VERSION 5.7 ;
  NOWIREEXTENSIONATPIN ON ;
  DIVIDERCHAR "/" ;
  BUSBITCHARS "[]" ;
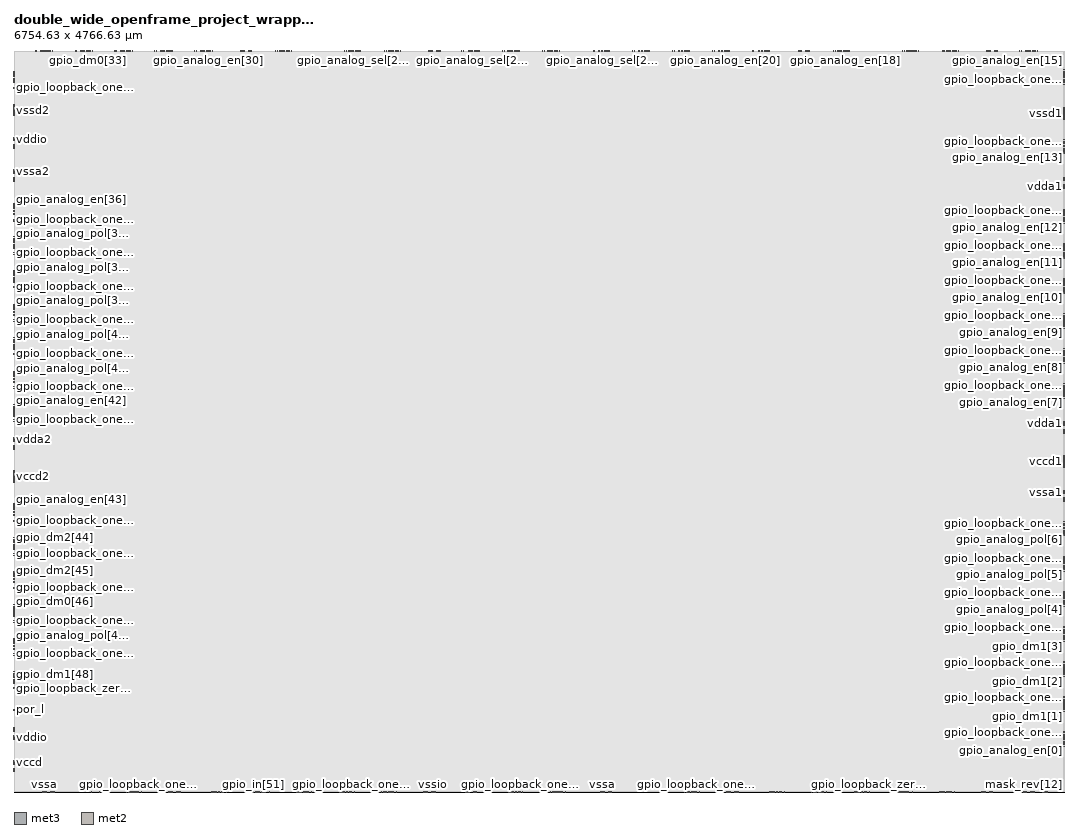
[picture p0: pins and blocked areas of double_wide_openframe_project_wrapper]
MACRO double_wide_openframe_project_wrapper
  CLASS BLOCK ;
  FOREIGN double_wide_openframe_project_wrapper ;
  ORIGIN 0.000 0.000 ;
  SIZE 6754.630 BY 4766.630 ;
  PIN analog_io[0]
    DIRECTION INOUT ;
    USE SIGNAL ;
    PORT
      LAYER met3 ;
        RECT 6754.330 306.190 6756.630 306.830 ;
    END
  END analog_io[0]
  PIN analog_io[10]
    DIRECTION INOUT ;
    USE SIGNAL ;
    PORT
      LAYER met3 ;
        RECT 6754.330 3222.190 6756.630 3222.830 ;
    END
  END analog_io[10]
  PIN analog_io[11]
    DIRECTION INOUT ;
    USE SIGNAL ;
    PORT
      LAYER met3 ;
        RECT 6754.330 3447.190 6756.630 3447.830 ;
    END
  END analog_io[11]
  PIN analog_io[12]
    DIRECTION INOUT ;
    USE SIGNAL ;
    PORT
      LAYER met3 ;
        RECT 6754.330 3672.190 6756.630 3672.830 ;
    END
  END analog_io[12]
  PIN analog_io[13]
    DIRECTION INOUT ;
    USE SIGNAL ;
    PORT
      LAYER met3 ;
        RECT 6754.330 4118.190 6756.630 4118.830 ;
    END
  END analog_io[13]
  PIN analog_io[14]
    DIRECTION INOUT ;
    USE SIGNAL ;
    PORT
      LAYER met3 ;
        RECT 6754.330 4564.190 6756.630 4564.830 ;
    END
  END analog_io[14]
  PIN analog_io[15]
    DIRECTION INOUT ;
    USE SIGNAL ;
    PORT
      LAYER met2 ;
        RECT 6569.800 4766.350 6570.440 4768.630 ;
    END
  END analog_io[15]
  PIN analog_io[16]
    DIRECTION INOUT ;
    USE SIGNAL ;
    PORT
      LAYER met2 ;
        RECT 6060.800 4766.350 6061.440 4768.630 ;
    END
  END analog_io[16]
  PIN analog_io[17]
    DIRECTION INOUT ;
    USE SIGNAL ;
    PORT
      LAYER met2 ;
        RECT 5803.800 4766.350 5804.440 4768.630 ;
    END
  END analog_io[17]
  PIN analog_io[18]
    DIRECTION INOUT ;
    USE SIGNAL ;
    PORT
      LAYER met2 ;
        RECT 5358.800 4766.350 5359.440 4768.630 ;
    END
  END analog_io[18]
  PIN analog_io[19]
    DIRECTION INOUT ;
    USE SIGNAL ;
    PORT
      LAYER met2 ;
        RECT 4849.800 4766.350 4850.440 4768.630 ;
    END
  END analog_io[19]
  PIN analog_io[1]
    DIRECTION INOUT ;
    USE SIGNAL ;
    PORT
      LAYER met3 ;
        RECT 6754.330 532.190 6756.630 532.830 ;
    END
  END analog_io[1]
  PIN analog_io[20]
    DIRECTION INOUT ;
    USE SIGNAL ;
    PORT
      LAYER met2 ;
        RECT 4591.800 4766.350 4592.440 4768.630 ;
    END
  END analog_io[20]
  PIN analog_io[21]
    DIRECTION INOUT ;
    USE SIGNAL ;
    PORT
      LAYER met2 ;
        RECT 4334.800 4766.350 4335.440 4768.630 ;
    END
  END analog_io[21]
  PIN analog_io[22]
    DIRECTION INOUT ;
    USE SIGNAL ;
    PORT
      LAYER met2 ;
        RECT 4077.800 4766.350 4078.440 4768.630 ;
    END
  END analog_io[22]
  PIN analog_io[23]
    DIRECTION INOUT ;
    USE SIGNAL ;
    PORT
      LAYER met2 ;
        RECT 3820.800 4766.350 3821.440 4768.630 ;
    END
  END analog_io[23]
  PIN analog_io[24]
    DIRECTION INOUT ;
    USE SIGNAL ;
    PORT
      LAYER met2 ;
        RECT 3495.800 4766.350 3496.440 4768.630 ;
    END
  END analog_io[24]
  PIN analog_io[25]
    DIRECTION INOUT ;
    USE SIGNAL ;
    PORT
      LAYER met2 ;
        RECT 3238.800 4766.350 3239.440 4768.630 ;
    END
  END analog_io[25]
  PIN analog_io[26]
    DIRECTION INOUT ;
    USE SIGNAL ;
    PORT
      LAYER met2 ;
        RECT 2981.800 4766.350 2982.440 4768.630 ;
    END
  END analog_io[26]
  PIN analog_io[27]
    DIRECTION INOUT ;
    USE SIGNAL ;
    PORT
      LAYER met2 ;
        RECT 2472.800 4766.350 2473.440 4768.630 ;
    END
  END analog_io[27]
  PIN analog_io[28]
    DIRECTION INOUT ;
    USE SIGNAL ;
    PORT
      LAYER met2 ;
        RECT 2215.800 4766.350 2216.440 4768.630 ;
    END
  END analog_io[28]
  PIN analog_io[29]
    DIRECTION INOUT ;
    USE SIGNAL ;
    PORT
      LAYER met2 ;
        RECT 1770.800 4766.350 1771.440 4768.630 ;
    END
  END analog_io[29]
  PIN analog_io[2]
    DIRECTION INOUT ;
    USE SIGNAL ;
    PORT
      LAYER met3 ;
        RECT 6754.330 757.190 6756.630 757.830 ;
    END
  END analog_io[2]
  PIN analog_io[30]
    DIRECTION INOUT ;
    USE SIGNAL ;
    PORT
      LAYER met2 ;
        RECT 1261.800 4766.350 1262.440 4768.630 ;
    END
  END analog_io[30]
  PIN analog_io[31]
    DIRECTION INOUT ;
    USE SIGNAL ;
    PORT
      LAYER met2 ;
        RECT 1003.800 4766.350 1004.440 4768.630 ;
    END
  END analog_io[31]
  PIN analog_io[32]
    DIRECTION INOUT ;
    USE SIGNAL ;
    PORT
      LAYER met2 ;
        RECT 746.800 4766.350 747.440 4768.630 ;
    END
  END analog_io[32]
  PIN analog_io[33]
    DIRECTION INOUT ;
    USE SIGNAL ;
    PORT
      LAYER met2 ;
        RECT 489.800 4766.350 490.440 4768.630 ;
    END
  END analog_io[33]
  PIN analog_io[34]
    DIRECTION INOUT ;
    USE SIGNAL ;
    PORT
      LAYER met2 ;
        RECT 232.800 4766.350 233.440 4768.630 ;
    END
  END analog_io[34]
  PIN analog_io[35]
    DIRECTION INOUT ;
    USE SIGNAL ;
    PORT
      LAYER met3 ;
        RECT -2.000 4622.800 0.300 4623.440 ;
    END
  END analog_io[35]
  PIN analog_io[36]
    DIRECTION INOUT ;
    USE SIGNAL ;
    PORT
      LAYER met3 ;
        RECT -2.000 3773.800 0.300 3774.440 ;
    END
  END analog_io[36]
  PIN analog_io[37]
    DIRECTION INOUT ;
    USE SIGNAL ;
    PORT
      LAYER met3 ;
        RECT -2.000 3557.800 0.300 3558.440 ;
    END
  END analog_io[37]
  PIN analog_io[38]
    DIRECTION INOUT ;
    USE SIGNAL ;
    PORT
      LAYER met3 ;
        RECT -2.000 3341.800 0.300 3342.440 ;
    END
  END analog_io[38]
  PIN analog_io[39]
    DIRECTION INOUT ;
    USE SIGNAL ;
    PORT
      LAYER met3 ;
        RECT -2.000 3125.800 0.300 3126.440 ;
    END
  END analog_io[39]
  PIN analog_io[3]
    DIRECTION INOUT ;
    USE SIGNAL ;
    PORT
      LAYER met3 ;
        RECT 6754.330 983.190 6756.630 983.830 ;
    END
  END analog_io[3]
  PIN analog_io[40]
    DIRECTION INOUT ;
    USE SIGNAL ;
    PORT
      LAYER met3 ;
        RECT -2.000 2909.800 0.300 2910.440 ;
    END
  END analog_io[40]
  PIN analog_io[41]
    DIRECTION INOUT ;
    USE SIGNAL ;
    PORT
      LAYER met3 ;
        RECT -2.000 2693.800 0.300 2694.440 ;
    END
  END analog_io[41]
  PIN analog_io[42]
    DIRECTION INOUT ;
    USE SIGNAL ;
    PORT
      LAYER met3 ;
        RECT -2.000 2477.800 0.300 2478.440 ;
    END
  END analog_io[42]
  PIN analog_io[43]
    DIRECTION INOUT ;
    USE SIGNAL ;
    PORT
      LAYER met3 ;
        RECT -2.000 1839.800 0.300 1840.440 ;
    END
  END analog_io[43]
  PIN analog_io[44]
    DIRECTION INOUT ;
    USE SIGNAL ;
    PORT
      LAYER met3 ;
        RECT -2.000 1623.800 0.300 1624.440 ;
    END
  END analog_io[44]
  PIN analog_io[45]
    DIRECTION INOUT ;
    USE SIGNAL ;
    PORT
      LAYER met3 ;
        RECT -2.000 1407.800 0.300 1408.440 ;
    END
  END analog_io[45]
  PIN analog_io[46]
    DIRECTION INOUT ;
    USE SIGNAL ;
    PORT
      LAYER met3 ;
        RECT -2.000 1191.800 0.300 1192.440 ;
    END
  END analog_io[46]
  PIN analog_io[47]
    DIRECTION INOUT ;
    USE SIGNAL ;
    PORT
      LAYER met3 ;
        RECT -2.000 975.800 0.300 976.440 ;
    END
  END analog_io[47]
  PIN analog_io[48]
    DIRECTION INOUT ;
    USE SIGNAL ;
    PORT
      LAYER met3 ;
        RECT -2.000 759.800 0.300 760.440 ;
    END
  END analog_io[48]
  PIN analog_io[49]
    DIRECTION INOUT ;
    USE SIGNAL ;
    PORT
      LAYER met2 ;
        RECT 738.190 -2.000 738.830 0.280 ;
    END
  END analog_io[49]
  PIN analog_io[4]
    DIRECTION INOUT ;
    USE SIGNAL ;
    PORT
      LAYER met3 ;
        RECT 6754.330 1208.190 6756.630 1208.830 ;
    END
  END analog_io[4]
  PIN analog_io[50]
    DIRECTION INOUT ;
    USE SIGNAL ;
    PORT
      LAYER met2 ;
        RECT 1281.190 -2.000 1281.830 0.280 ;
    END
  END analog_io[50]
  PIN analog_io[51]
    DIRECTION INOUT ;
    USE SIGNAL ;
    PORT
      LAYER met2 ;
        RECT 1555.190 -2.000 1555.830 0.280 ;
    END
  END analog_io[51]
  PIN analog_io[52]
    DIRECTION INOUT ;
    USE SIGNAL ;
    PORT
      LAYER met2 ;
        RECT 1829.190 -2.000 1829.830 0.280 ;
    END
  END analog_io[52]
  PIN analog_io[53]
    DIRECTION INOUT ;
    USE SIGNAL ;
    PORT
      LAYER met2 ;
        RECT 2103.190 -2.000 2103.830 0.280 ;
    END
  END analog_io[53]
  PIN analog_io[54]
    DIRECTION INOUT ;
    USE SIGNAL ;
    PORT
      LAYER met2 ;
        RECT 2377.190 -2.000 2377.830 0.280 ;
    END
  END analog_io[54]
  PIN analog_io[55]
    DIRECTION INOUT ;
    USE SIGNAL ;
    PORT
      LAYER met2 ;
        RECT 3191.670 -2.000 3192.310 0.280 ;
    END
  END analog_io[55]
  PIN analog_io[56]
    DIRECTION INOUT ;
    USE SIGNAL ;
    PORT
      LAYER met2 ;
        RECT 3465.670 -2.000 3466.310 0.280 ;
    END
  END analog_io[56]
  PIN analog_io[57]
    DIRECTION INOUT ;
    USE SIGNAL ;
    PORT
      LAYER met2 ;
        RECT 4326.190 -2.000 4326.830 0.280 ;
    END
  END analog_io[57]
  PIN analog_io[58]
    DIRECTION INOUT ;
    USE SIGNAL ;
    PORT
      LAYER met2 ;
        RECT 4869.190 -2.000 4869.830 0.280 ;
    END
  END analog_io[58]
  PIN analog_io[59]
    DIRECTION INOUT ;
    USE SIGNAL ;
    PORT
      LAYER met2 ;
        RECT 5143.190 -2.000 5143.830 0.280 ;
    END
  END analog_io[59]
  PIN analog_io[5]
    DIRECTION INOUT ;
    USE SIGNAL ;
    PORT
      LAYER met3 ;
        RECT 6754.330 1433.190 6756.630 1433.830 ;
    END
  END analog_io[5]
  PIN analog_io[60]
    DIRECTION INOUT ;
    USE SIGNAL ;
    PORT
      LAYER met2 ;
        RECT 5417.190 -2.000 5417.830 0.280 ;
    END
  END analog_io[60]
  PIN analog_io[61]
    DIRECTION INOUT ;
    USE SIGNAL ;
    PORT
      LAYER met2 ;
        RECT 5691.190 -2.000 5691.830 0.280 ;
    END
  END analog_io[61]
  PIN analog_io[62]
    DIRECTION INOUT ;
    USE SIGNAL ;
    PORT
      LAYER met2 ;
        RECT 5965.190 -2.000 5965.830 0.280 ;
    END
  END analog_io[62]
  PIN analog_io[6]
    DIRECTION INOUT ;
    USE SIGNAL ;
    PORT
      LAYER met3 ;
        RECT 6754.330 1659.190 6756.630 1659.830 ;
    END
  END analog_io[6]
  PIN analog_io[7]
    DIRECTION INOUT ;
    USE SIGNAL ;
    PORT
      LAYER met3 ;
        RECT 6754.330 2545.190 6756.630 2545.830 ;
    END
  END analog_io[7]
  PIN analog_io[8]
    DIRECTION INOUT ;
    USE SIGNAL ;
    PORT
      LAYER met3 ;
        RECT 6754.330 2771.190 6756.630 2771.830 ;
    END
  END analog_io[8]
  PIN analog_io[9]
    DIRECTION INOUT ;
    USE SIGNAL ;
    PORT
      LAYER met3 ;
        RECT 6754.330 2996.190 6756.630 2996.830 ;
    END
  END analog_io[9]
  PIN analog_noesd_io[0]
    DIRECTION INOUT ;
    USE SIGNAL ;
    PORT
      LAYER met3 ;
        RECT 6754.330 315.175 6756.630 316.245 ;
    END
  END analog_noesd_io[0]
  PIN analog_noesd_io[10]
    DIRECTION INOUT ;
    USE SIGNAL ;
    PORT
      LAYER met3 ;
        RECT 6754.330 3231.175 6756.630 3232.245 ;
    END
  END analog_noesd_io[10]
  PIN analog_noesd_io[11]
    DIRECTION INOUT ;
    USE SIGNAL ;
    PORT
      LAYER met3 ;
        RECT 6754.330 3456.175 6756.630 3457.245 ;
    END
  END analog_noesd_io[11]
  PIN analog_noesd_io[12]
    DIRECTION INOUT ;
    USE SIGNAL ;
    PORT
      LAYER met3 ;
        RECT 6754.330 3681.175 6756.630 3682.245 ;
    END
  END analog_noesd_io[12]
  PIN analog_noesd_io[13]
    DIRECTION INOUT ;
    USE SIGNAL ;
    PORT
      LAYER met3 ;
        RECT 6754.330 4127.175 6756.630 4128.245 ;
    END
  END analog_noesd_io[13]
  PIN analog_noesd_io[14]
    DIRECTION INOUT ;
    USE SIGNAL ;
    PORT
      LAYER met3 ;
        RECT 6754.330 4573.175 6756.630 4574.245 ;
    END
  END analog_noesd_io[14]
  PIN analog_noesd_io[15]
    DIRECTION INOUT ;
    USE SIGNAL ;
    PORT
      LAYER met2 ;
        RECT 6560.385 4766.350 6561.455 4768.630 ;
    END
  END analog_noesd_io[15]
  PIN analog_noesd_io[16]
    DIRECTION INOUT ;
    USE SIGNAL ;
    PORT
      LAYER met2 ;
        RECT 6051.385 4766.350 6052.455 4768.630 ;
    END
  END analog_noesd_io[16]
  PIN analog_noesd_io[17]
    DIRECTION INOUT ;
    USE SIGNAL ;
    PORT
      LAYER met2 ;
        RECT 5794.385 4766.350 5795.455 4768.630 ;
    END
  END analog_noesd_io[17]
  PIN analog_noesd_io[18]
    DIRECTION INOUT ;
    USE SIGNAL ;
    PORT
      LAYER met2 ;
        RECT 5349.385 4766.350 5350.455 4768.630 ;
    END
  END analog_noesd_io[18]
  PIN analog_noesd_io[19]
    DIRECTION INOUT ;
    USE SIGNAL ;
    PORT
      LAYER met2 ;
        RECT 4840.385 4766.350 4841.455 4768.630 ;
    END
  END analog_noesd_io[19]
  PIN analog_noesd_io[1]
    DIRECTION INOUT ;
    USE SIGNAL ;
    PORT
      LAYER met3 ;
        RECT 6754.330 541.175 6756.630 542.245 ;
    END
  END analog_noesd_io[1]
  PIN analog_noesd_io[20]
    DIRECTION INOUT ;
    USE SIGNAL ;
    PORT
      LAYER met2 ;
        RECT 4582.385 4766.350 4583.455 4768.630 ;
    END
  END analog_noesd_io[20]
  PIN analog_noesd_io[21]
    DIRECTION INOUT ;
    USE SIGNAL ;
    PORT
      LAYER met2 ;
        RECT 4325.385 4766.350 4326.455 4768.630 ;
    END
  END analog_noesd_io[21]
  PIN analog_noesd_io[22]
    DIRECTION INOUT ;
    USE SIGNAL ;
    PORT
      LAYER met2 ;
        RECT 4068.385 4766.350 4069.455 4768.630 ;
    END
  END analog_noesd_io[22]
  PIN analog_noesd_io[23]
    DIRECTION INOUT ;
    USE SIGNAL ;
    PORT
      LAYER met2 ;
        RECT 3811.385 4766.350 3812.455 4768.630 ;
    END
  END analog_noesd_io[23]
  PIN analog_noesd_io[24]
    DIRECTION INOUT ;
    USE SIGNAL ;
    PORT
      LAYER met2 ;
        RECT 3486.385 4766.350 3487.455 4768.630 ;
    END
  END analog_noesd_io[24]
  PIN analog_noesd_io[25]
    DIRECTION INOUT ;
    USE SIGNAL ;
    PORT
      LAYER met2 ;
        RECT 3229.385 4766.350 3230.455 4768.630 ;
    END
  END analog_noesd_io[25]
  PIN analog_noesd_io[26]
    DIRECTION INOUT ;
    USE SIGNAL ;
    PORT
      LAYER met2 ;
        RECT 2972.385 4766.350 2973.455 4768.630 ;
    END
  END analog_noesd_io[26]
  PIN analog_noesd_io[27]
    DIRECTION INOUT ;
    USE SIGNAL ;
    PORT
      LAYER met2 ;
        RECT 2463.385 4766.350 2464.455 4768.630 ;
    END
  END analog_noesd_io[27]
  PIN analog_noesd_io[28]
    DIRECTION INOUT ;
    USE SIGNAL ;
    PORT
      LAYER met2 ;
        RECT 2206.385 4766.350 2207.455 4768.630 ;
    END
  END analog_noesd_io[28]
  PIN analog_noesd_io[29]
    DIRECTION INOUT ;
    USE SIGNAL ;
    PORT
      LAYER met2 ;
        RECT 1761.385 4766.350 1762.455 4768.630 ;
    END
  END analog_noesd_io[29]
  PIN analog_noesd_io[2]
    DIRECTION INOUT ;
    USE SIGNAL ;
    PORT
      LAYER met3 ;
        RECT 6754.330 766.175 6756.630 767.245 ;
    END
  END analog_noesd_io[2]
  PIN analog_noesd_io[30]
    DIRECTION INOUT ;
    USE SIGNAL ;
    PORT
      LAYER met2 ;
        RECT 1252.385 4766.350 1253.455 4768.630 ;
    END
  END analog_noesd_io[30]
  PIN analog_noesd_io[31]
    DIRECTION INOUT ;
    USE SIGNAL ;
    PORT
      LAYER met2 ;
        RECT 994.385 4766.350 995.455 4768.630 ;
    END
  END analog_noesd_io[31]
  PIN analog_noesd_io[32]
    DIRECTION INOUT ;
    USE SIGNAL ;
    PORT
      LAYER met2 ;
        RECT 737.385 4766.350 738.455 4768.630 ;
    END
  END analog_noesd_io[32]
  PIN analog_noesd_io[33]
    DIRECTION INOUT ;
    USE SIGNAL ;
    PORT
      LAYER met2 ;
        RECT 480.385 4766.350 481.455 4768.630 ;
    END
  END analog_noesd_io[33]
  PIN analog_noesd_io[34]
    DIRECTION INOUT ;
    USE SIGNAL ;
    PORT
      LAYER met2 ;
        RECT 223.385 4766.350 224.455 4768.630 ;
    END
  END analog_noesd_io[34]
  PIN analog_noesd_io[35]
    DIRECTION INOUT ;
    USE SIGNAL ;
    PORT
      LAYER met3 ;
        RECT -2.000 4613.385 0.300 4614.455 ;
    END
  END analog_noesd_io[35]
  PIN analog_noesd_io[36]
    DIRECTION INOUT ;
    USE SIGNAL ;
    PORT
      LAYER met3 ;
        RECT -2.000 3764.385 0.300 3765.455 ;
    END
  END analog_noesd_io[36]
  PIN analog_noesd_io[37]
    DIRECTION INOUT ;
    USE SIGNAL ;
    PORT
      LAYER met3 ;
        RECT -2.000 3548.385 0.300 3549.455 ;
    END
  END analog_noesd_io[37]
  PIN analog_noesd_io[38]
    DIRECTION INOUT ;
    USE SIGNAL ;
    PORT
      LAYER met3 ;
        RECT -2.000 3332.385 0.300 3333.455 ;
    END
  END analog_noesd_io[38]
  PIN analog_noesd_io[39]
    DIRECTION INOUT ;
    USE SIGNAL ;
    PORT
      LAYER met3 ;
        RECT -2.000 3116.385 0.300 3117.455 ;
    END
  END analog_noesd_io[39]
  PIN analog_noesd_io[3]
    DIRECTION INOUT ;
    USE SIGNAL ;
    PORT
      LAYER met3 ;
        RECT 6754.330 992.175 6756.630 993.245 ;
    END
  END analog_noesd_io[3]
  PIN analog_noesd_io[40]
    DIRECTION INOUT ;
    USE SIGNAL ;
    PORT
      LAYER met3 ;
        RECT -2.000 2900.385 0.300 2901.455 ;
    END
  END analog_noesd_io[40]
  PIN analog_noesd_io[41]
    DIRECTION INOUT ;
    USE SIGNAL ;
    PORT
      LAYER met3 ;
        RECT -2.000 2684.385 0.300 2685.455 ;
    END
  END analog_noesd_io[41]
  PIN analog_noesd_io[42]
    DIRECTION INOUT ;
    USE SIGNAL ;
    PORT
      LAYER met3 ;
        RECT -2.000 2468.385 0.300 2469.455 ;
    END
  END analog_noesd_io[42]
  PIN analog_noesd_io[43]
    DIRECTION INOUT ;
    USE SIGNAL ;
    PORT
      LAYER met3 ;
        RECT -2.000 1830.385 0.300 1831.455 ;
    END
  END analog_noesd_io[43]
  PIN analog_noesd_io[44]
    DIRECTION INOUT ;
    USE SIGNAL ;
    PORT
      LAYER met3 ;
        RECT -2.000 1614.385 0.300 1615.455 ;
    END
  END analog_noesd_io[44]
  PIN analog_noesd_io[45]
    DIRECTION INOUT ;
    USE SIGNAL ;
    PORT
      LAYER met3 ;
        RECT -2.000 1398.385 0.300 1399.455 ;
    END
  END analog_noesd_io[45]
  PIN analog_noesd_io[46]
    DIRECTION INOUT ;
    USE SIGNAL ;
    PORT
      LAYER met3 ;
        RECT -2.000 1182.385 0.300 1183.455 ;
    END
  END analog_noesd_io[46]
  PIN analog_noesd_io[47]
    DIRECTION INOUT ;
    USE SIGNAL ;
    PORT
      LAYER met3 ;
        RECT -2.000 966.385 0.300 967.455 ;
    END
  END analog_noesd_io[47]
  PIN analog_noesd_io[48]
    DIRECTION INOUT ;
    USE SIGNAL ;
    PORT
      LAYER met3 ;
        RECT -2.000 750.385 0.300 751.455 ;
    END
  END analog_noesd_io[48]
  PIN analog_noesd_io[49]
    DIRECTION INOUT ;
    USE SIGNAL ;
    PORT
      LAYER met2 ;
        RECT 747.175 -2.000 748.245 0.280 ;
    END
  END analog_noesd_io[49]
  PIN analog_noesd_io[4]
    DIRECTION INOUT ;
    USE SIGNAL ;
    PORT
      LAYER met3 ;
        RECT 6754.330 1217.175 6756.630 1218.245 ;
    END
  END analog_noesd_io[4]
  PIN analog_noesd_io[50]
    DIRECTION INOUT ;
    USE SIGNAL ;
    PORT
      LAYER met2 ;
        RECT 1290.175 -2.000 1291.245 0.280 ;
    END
  END analog_noesd_io[50]
  PIN analog_noesd_io[51]
    DIRECTION INOUT ;
    USE SIGNAL ;
    PORT
      LAYER met2 ;
        RECT 1564.175 -2.000 1565.245 0.280 ;
    END
  END analog_noesd_io[51]
  PIN analog_noesd_io[52]
    DIRECTION INOUT ;
    USE SIGNAL ;
    PORT
      LAYER met2 ;
        RECT 1838.175 -2.000 1839.245 0.280 ;
    END
  END analog_noesd_io[52]
  PIN analog_noesd_io[53]
    DIRECTION INOUT ;
    USE SIGNAL ;
    PORT
      LAYER met2 ;
        RECT 2112.175 -2.000 2113.245 0.280 ;
    END
  END analog_noesd_io[53]
  PIN analog_noesd_io[54]
    DIRECTION INOUT ;
    USE SIGNAL ;
    PORT
      LAYER met2 ;
        RECT 2386.175 -2.000 2387.245 0.280 ;
    END
  END analog_noesd_io[54]
  PIN analog_noesd_io[55]
    DIRECTION INOUT ;
    USE SIGNAL ;
    PORT
      LAYER met2 ;
        RECT 3200.655 -2.000 3201.725 0.280 ;
    END
  END analog_noesd_io[55]
  PIN analog_noesd_io[56]
    DIRECTION INOUT ;
    USE SIGNAL ;
    PORT
      LAYER met2 ;
        RECT 3474.655 -2.000 3475.725 0.280 ;
    END
  END analog_noesd_io[56]
  PIN analog_noesd_io[57]
    DIRECTION INOUT ;
    USE SIGNAL ;
    PORT
      LAYER met2 ;
        RECT 4335.175 -2.000 4336.245 0.280 ;
    END
  END analog_noesd_io[57]
  PIN analog_noesd_io[58]
    DIRECTION INOUT ;
    USE SIGNAL ;
    PORT
      LAYER met2 ;
        RECT 4878.175 -2.000 4879.245 0.280 ;
    END
  END analog_noesd_io[58]
  PIN analog_noesd_io[59]
    DIRECTION INOUT ;
    USE SIGNAL ;
    PORT
      LAYER met2 ;
        RECT 5152.175 -2.000 5153.245 0.280 ;
    END
  END analog_noesd_io[59]
  PIN analog_noesd_io[5]
    DIRECTION INOUT ;
    USE SIGNAL ;
    PORT
      LAYER met3 ;
        RECT 6754.330 1442.175 6756.630 1443.245 ;
    END
  END analog_noesd_io[5]
  PIN analog_noesd_io[60]
    DIRECTION INOUT ;
    USE SIGNAL ;
    PORT
      LAYER met2 ;
        RECT 5426.175 -2.000 5427.245 0.280 ;
    END
  END analog_noesd_io[60]
  PIN analog_noesd_io[61]
    DIRECTION INOUT ;
    USE SIGNAL ;
    PORT
      LAYER met2 ;
        RECT 5700.175 -2.000 5701.245 0.280 ;
    END
  END analog_noesd_io[61]
  PIN analog_noesd_io[62]
    DIRECTION INOUT ;
    USE SIGNAL ;
    PORT
      LAYER met2 ;
        RECT 5974.175 -2.000 5975.245 0.280 ;
    END
  END analog_noesd_io[62]
  PIN analog_noesd_io[6]
    DIRECTION INOUT ;
    USE SIGNAL ;
    PORT
      LAYER met3 ;
        RECT 6754.330 1668.175 6756.630 1669.245 ;
    END
  END analog_noesd_io[6]
  PIN analog_noesd_io[7]
    DIRECTION INOUT ;
    USE SIGNAL ;
    PORT
      LAYER met3 ;
        RECT 6754.330 2554.175 6756.630 2555.245 ;
    END
  END analog_noesd_io[7]
  PIN analog_noesd_io[8]
    DIRECTION INOUT ;
    USE SIGNAL ;
    PORT
      LAYER met3 ;
        RECT 6754.330 2780.175 6756.630 2781.245 ;
    END
  END analog_noesd_io[8]
  PIN analog_noesd_io[9]
    DIRECTION INOUT ;
    USE SIGNAL ;
    PORT
      LAYER met3 ;
        RECT 6754.330 3005.175 6756.630 3006.245 ;
    END
  END analog_noesd_io[9]
  PIN gpio_analog_en[0]
    DIRECTION OUTPUT ;
    USE SIGNAL ;
    PORT
      LAYER met3 ;
        RECT 6754.330 318.300 6756.630 318.650 ;
    END
  END gpio_analog_en[0]
  PIN gpio_analog_en[10]
    DIRECTION OUTPUT ;
    USE SIGNAL ;
    PORT
      LAYER met3 ;
        RECT 6754.330 3234.300 6756.630 3234.650 ;
    END
  END gpio_analog_en[10]
  PIN gpio_analog_en[11]
    DIRECTION OUTPUT ;
    USE SIGNAL ;
    PORT
      LAYER met3 ;
        RECT 6754.330 3459.300 6756.630 3459.650 ;
    END
  END gpio_analog_en[11]
  PIN gpio_analog_en[12]
    DIRECTION OUTPUT ;
    USE SIGNAL ;
    PORT
      LAYER met3 ;
        RECT 6754.330 3684.300 6756.630 3684.650 ;
    END
  END gpio_analog_en[12]
  PIN gpio_analog_en[13]
    DIRECTION OUTPUT ;
    USE SIGNAL ;
    PORT
      LAYER met3 ;
        RECT 6754.330 4130.300 6756.630 4130.650 ;
    END
  END gpio_analog_en[13]
  PIN gpio_analog_en[14]
    DIRECTION OUTPUT ;
    USE SIGNAL ;
    PORT
      LAYER met3 ;
        RECT 6754.330 4576.300 6756.630 4576.650 ;
    END
  END gpio_analog_en[14]
  PIN gpio_analog_en[15]
    DIRECTION OUTPUT ;
    USE SIGNAL ;
    PORT
      LAYER met2 ;
        RECT 6558.020 4766.350 6558.300 4768.630 ;
    END
  END gpio_analog_en[15]
  PIN gpio_analog_en[16]
    DIRECTION OUTPUT ;
    USE SIGNAL ;
    PORT
      LAYER met2 ;
        RECT 6049.020 4766.350 6049.300 4768.630 ;
    END
  END gpio_analog_en[16]
  PIN gpio_analog_en[17]
    DIRECTION OUTPUT ;
    USE SIGNAL ;
    PORT
      LAYER met2 ;
        RECT 5792.020 4766.350 5792.300 4768.630 ;
    END
  END gpio_analog_en[17]
  PIN gpio_analog_en[18]
    DIRECTION OUTPUT ;
    USE SIGNAL ;
    PORT
      LAYER met2 ;
        RECT 5347.020 4766.350 5347.300 4768.630 ;
    END
  END gpio_analog_en[18]
  PIN gpio_analog_en[19]
    DIRECTION OUTPUT ;
    USE SIGNAL ;
    PORT
      LAYER met2 ;
        RECT 4838.020 4766.350 4838.300 4768.630 ;
    END
  END gpio_analog_en[19]
  PIN gpio_analog_en[1]
    DIRECTION OUTPUT ;
    USE SIGNAL ;
    PORT
      LAYER met3 ;
        RECT 6754.330 544.300 6756.630 544.650 ;
    END
  END gpio_analog_en[1]
  PIN gpio_analog_en[20]
    DIRECTION OUTPUT ;
    USE SIGNAL ;
    PORT
      LAYER met2 ;
        RECT 4580.020 4766.350 4580.300 4768.630 ;
    END
  END gpio_analog_en[20]
  PIN gpio_analog_en[21]
    DIRECTION OUTPUT ;
    USE SIGNAL ;
    PORT
      LAYER met2 ;
        RECT 4323.020 4766.350 4323.300 4768.630 ;
    END
  END gpio_analog_en[21]
  PIN gpio_analog_en[22]
    DIRECTION OUTPUT ;
    USE SIGNAL ;
    PORT
      LAYER met2 ;
        RECT 4066.020 4766.350 4066.300 4768.630 ;
    END
  END gpio_analog_en[22]
  PIN gpio_analog_en[23]
    DIRECTION OUTPUT ;
    USE SIGNAL ;
    PORT
      LAYER met2 ;
        RECT 3809.020 4766.350 3809.300 4768.630 ;
    END
  END gpio_analog_en[23]
  PIN gpio_analog_en[24]
    DIRECTION OUTPUT ;
    USE SIGNAL ;
    PORT
      LAYER met2 ;
        RECT 3484.020 4766.350 3484.300 4768.630 ;
    END
  END gpio_analog_en[24]
  PIN gpio_analog_en[25]
    DIRECTION OUTPUT ;
    USE SIGNAL ;
    PORT
      LAYER met2 ;
        RECT 3227.020 4766.350 3227.300 4768.630 ;
    END
  END gpio_analog_en[25]
  PIN gpio_analog_en[26]
    DIRECTION OUTPUT ;
    USE SIGNAL ;
    PORT
      LAYER met2 ;
        RECT 2970.020 4766.350 2970.300 4768.630 ;
    END
  END gpio_analog_en[26]
  PIN gpio_analog_en[27]
    DIRECTION OUTPUT ;
    USE SIGNAL ;
    PORT
      LAYER met2 ;
        RECT 2461.020 4766.350 2461.300 4768.630 ;
    END
  END gpio_analog_en[27]
  PIN gpio_analog_en[28]
    DIRECTION OUTPUT ;
    USE SIGNAL ;
    PORT
      LAYER met2 ;
        RECT 2204.020 4766.350 2204.300 4768.630 ;
    END
  END gpio_analog_en[28]
  PIN gpio_analog_en[29]
    DIRECTION OUTPUT ;
    USE SIGNAL ;
    PORT
      LAYER met2 ;
        RECT 1759.020 4766.350 1759.300 4768.630 ;
    END
  END gpio_analog_en[29]
  PIN gpio_analog_en[2]
    DIRECTION OUTPUT ;
    USE SIGNAL ;
    PORT
      LAYER met3 ;
        RECT 6754.330 769.300 6756.630 769.650 ;
    END
  END gpio_analog_en[2]
  PIN gpio_analog_en[30]
    DIRECTION OUTPUT ;
    USE SIGNAL ;
    PORT
      LAYER met2 ;
        RECT 1250.020 4766.350 1250.300 4768.630 ;
    END
  END gpio_analog_en[30]
  PIN gpio_analog_en[31]
    DIRECTION OUTPUT ;
    USE SIGNAL ;
    PORT
      LAYER met2 ;
        RECT 992.020 4766.350 992.300 4768.630 ;
    END
  END gpio_analog_en[31]
  PIN gpio_analog_en[32]
    DIRECTION OUTPUT ;
    USE SIGNAL ;
    PORT
      LAYER met2 ;
        RECT 735.020 4766.350 735.300 4768.630 ;
    END
  END gpio_analog_en[32]
  PIN gpio_analog_en[33]
    DIRECTION OUTPUT ;
    USE SIGNAL ;
    PORT
      LAYER met2 ;
        RECT 478.020 4766.350 478.300 4768.630 ;
    END
  END gpio_analog_en[33]
  PIN gpio_analog_en[34]
    DIRECTION OUTPUT ;
    USE SIGNAL ;
    PORT
      LAYER met2 ;
        RECT 221.020 4766.350 221.300 4768.630 ;
    END
  END gpio_analog_en[34]
  PIN gpio_analog_en[35]
    DIRECTION OUTPUT ;
    USE SIGNAL ;
    PORT
      LAYER met3 ;
        RECT -2.000 4610.980 0.300 4611.330 ;
    END
  END gpio_analog_en[35]
  PIN gpio_analog_en[36]
    DIRECTION OUTPUT ;
    USE SIGNAL ;
    PORT
      LAYER met3 ;
        RECT -2.000 3761.980 0.300 3762.330 ;
    END
  END gpio_analog_en[36]
  PIN gpio_analog_en[37]
    DIRECTION OUTPUT ;
    USE SIGNAL ;
    PORT
      LAYER met3 ;
        RECT -2.000 3545.980 0.300 3546.330 ;
    END
  END gpio_analog_en[37]
  PIN gpio_analog_en[38]
    DIRECTION OUTPUT ;
    USE SIGNAL ;
    PORT
      LAYER met3 ;
        RECT -2.000 3329.980 0.300 3330.330 ;
    END
  END gpio_analog_en[38]
  PIN gpio_analog_en[39]
    DIRECTION OUTPUT ;
    USE SIGNAL ;
    PORT
      LAYER met3 ;
        RECT -2.000 3113.980 0.300 3114.330 ;
    END
  END gpio_analog_en[39]
  PIN gpio_analog_en[3]
    DIRECTION OUTPUT ;
    USE SIGNAL ;
    PORT
      LAYER met3 ;
        RECT 6754.330 995.300 6756.630 995.650 ;
    END
  END gpio_analog_en[3]
  PIN gpio_analog_en[40]
    DIRECTION OUTPUT ;
    USE SIGNAL ;
    PORT
      LAYER met3 ;
        RECT -2.000 2897.980 0.300 2898.330 ;
    END
  END gpio_analog_en[40]
  PIN gpio_analog_en[41]
    DIRECTION OUTPUT ;
    USE SIGNAL ;
    PORT
      LAYER met3 ;
        RECT -2.000 2681.980 0.300 2682.330 ;
    END
  END gpio_analog_en[41]
  PIN gpio_analog_en[42]
    DIRECTION OUTPUT ;
    USE SIGNAL ;
    PORT
      LAYER met3 ;
        RECT -2.000 2465.980 0.300 2466.330 ;
    END
  END gpio_analog_en[42]
  PIN gpio_analog_en[43]
    DIRECTION OUTPUT ;
    USE SIGNAL ;
    PORT
      LAYER met3 ;
        RECT -2.000 1827.980 0.300 1828.330 ;
    END
  END gpio_analog_en[43]
  PIN gpio_analog_en[44]
    DIRECTION OUTPUT ;
    USE SIGNAL ;
    PORT
      LAYER met3 ;
        RECT -2.000 1611.980 0.300 1612.330 ;
    END
  END gpio_analog_en[44]
  PIN gpio_analog_en[45]
    DIRECTION OUTPUT ;
    USE SIGNAL ;
    PORT
      LAYER met3 ;
        RECT -2.000 1395.980 0.300 1396.330 ;
    END
  END gpio_analog_en[45]
  PIN gpio_analog_en[46]
    DIRECTION OUTPUT ;
    USE SIGNAL ;
    PORT
      LAYER met3 ;
        RECT -2.000 1179.980 0.300 1180.330 ;
    END
  END gpio_analog_en[46]
  PIN gpio_analog_en[47]
    DIRECTION OUTPUT ;
    USE SIGNAL ;
    PORT
      LAYER met3 ;
        RECT -2.000 963.980 0.300 964.330 ;
    END
  END gpio_analog_en[47]
  PIN gpio_analog_en[48]
    DIRECTION OUTPUT ;
    USE SIGNAL ;
    PORT
      LAYER met3 ;
        RECT -2.000 747.980 0.300 748.330 ;
    END
  END gpio_analog_en[48]
  PIN gpio_analog_en[49]
    DIRECTION OUTPUT ;
    USE SIGNAL ;
    PORT
      LAYER met2 ;
        RECT 750.330 -2.000 750.610 0.280 ;
    END
  END gpio_analog_en[49]
  PIN gpio_analog_en[4]
    DIRECTION OUTPUT ;
    USE SIGNAL ;
    PORT
      LAYER met3 ;
        RECT 6754.330 1220.300 6756.630 1220.650 ;
    END
  END gpio_analog_en[4]
  PIN gpio_analog_en[50]
    DIRECTION OUTPUT ;
    USE SIGNAL ;
    PORT
      LAYER met2 ;
        RECT 1293.330 -2.000 1293.610 0.280 ;
    END
  END gpio_analog_en[50]
  PIN gpio_analog_en[51]
    DIRECTION OUTPUT ;
    USE SIGNAL ;
    PORT
      LAYER met2 ;
        RECT 1567.330 -2.000 1567.610 0.280 ;
    END
  END gpio_analog_en[51]
  PIN gpio_analog_en[52]
    DIRECTION OUTPUT ;
    USE SIGNAL ;
    PORT
      LAYER met2 ;
        RECT 1841.330 -2.000 1841.610 0.280 ;
    END
  END gpio_analog_en[52]
  PIN gpio_analog_en[53]
    DIRECTION OUTPUT ;
    USE SIGNAL ;
    PORT
      LAYER met2 ;
        RECT 2115.330 -2.000 2115.610 0.280 ;
    END
  END gpio_analog_en[53]
  PIN gpio_analog_en[54]
    DIRECTION OUTPUT ;
    USE SIGNAL ;
    PORT
      LAYER met2 ;
        RECT 2389.330 -2.000 2389.610 0.280 ;
    END
  END gpio_analog_en[54]
  PIN gpio_analog_en[55]
    DIRECTION OUTPUT ;
    USE SIGNAL ;
    PORT
      LAYER met2 ;
        RECT 3203.810 -2.000 3204.090 0.280 ;
    END
  END gpio_analog_en[55]
  PIN gpio_analog_en[56]
    DIRECTION OUTPUT ;
    USE SIGNAL ;
    PORT
      LAYER met2 ;
        RECT 3477.810 -2.000 3478.090 0.280 ;
    END
  END gpio_analog_en[56]
  PIN gpio_analog_en[57]
    DIRECTION OUTPUT ;
    USE SIGNAL ;
    PORT
      LAYER met2 ;
        RECT 4338.330 -2.000 4338.610 0.280 ;
    END
  END gpio_analog_en[57]
  PIN gpio_analog_en[58]
    DIRECTION OUTPUT ;
    USE SIGNAL ;
    PORT
      LAYER met2 ;
        RECT 4881.330 -2.000 4881.610 0.280 ;
    END
  END gpio_analog_en[58]
  PIN gpio_analog_en[59]
    DIRECTION OUTPUT ;
    USE SIGNAL ;
    PORT
      LAYER met2 ;
        RECT 5155.330 -2.000 5155.610 0.280 ;
    END
  END gpio_analog_en[59]
  PIN gpio_analog_en[5]
    DIRECTION OUTPUT ;
    USE SIGNAL ;
    PORT
      LAYER met3 ;
        RECT 6754.330 1445.300 6756.630 1445.650 ;
    END
  END gpio_analog_en[5]
  PIN gpio_analog_en[60]
    DIRECTION OUTPUT ;
    USE SIGNAL ;
    PORT
      LAYER met2 ;
        RECT 5429.330 -2.000 5429.610 0.280 ;
    END
  END gpio_analog_en[60]
  PIN gpio_analog_en[61]
    DIRECTION OUTPUT ;
    USE SIGNAL ;
    PORT
      LAYER met2 ;
        RECT 5703.330 -2.000 5703.610 0.280 ;
    END
  END gpio_analog_en[61]
  PIN gpio_analog_en[62]
    DIRECTION OUTPUT ;
    USE SIGNAL ;
    PORT
      LAYER met2 ;
        RECT 5977.330 -2.000 5977.610 0.280 ;
    END
  END gpio_analog_en[62]
  PIN gpio_analog_en[6]
    DIRECTION OUTPUT ;
    USE SIGNAL ;
    PORT
      LAYER met3 ;
        RECT 6754.330 1671.300 6756.630 1671.650 ;
    END
  END gpio_analog_en[6]
  PIN gpio_analog_en[7]
    DIRECTION OUTPUT ;
    USE SIGNAL ;
    PORT
      LAYER met3 ;
        RECT 6754.330 2557.300 6756.630 2557.650 ;
    END
  END gpio_analog_en[7]
  PIN gpio_analog_en[8]
    DIRECTION OUTPUT ;
    USE SIGNAL ;
    PORT
      LAYER met3 ;
        RECT 6754.330 2783.300 6756.630 2783.650 ;
    END
  END gpio_analog_en[8]
  PIN gpio_analog_en[9]
    DIRECTION OUTPUT ;
    USE SIGNAL ;
    PORT
      LAYER met3 ;
        RECT 6754.330 3008.300 6756.630 3008.650 ;
    END
  END gpio_analog_en[9]
  PIN gpio_analog_pol[0]
    DIRECTION OUTPUT ;
    USE SIGNAL ;
    PORT
      LAYER met3 ;
        RECT 6754.330 324.740 6756.630 325.090 ;
    END
  END gpio_analog_pol[0]
  PIN gpio_analog_pol[10]
    DIRECTION OUTPUT ;
    USE SIGNAL ;
    PORT
      LAYER met3 ;
        RECT 6754.330 3240.740 6756.630 3241.090 ;
    END
  END gpio_analog_pol[10]
  PIN gpio_analog_pol[11]
    DIRECTION OUTPUT ;
    USE SIGNAL ;
    PORT
      LAYER met3 ;
        RECT 6754.330 3465.740 6756.630 3466.090 ;
    END
  END gpio_analog_pol[11]
  PIN gpio_analog_pol[12]
    DIRECTION OUTPUT ;
    USE SIGNAL ;
    PORT
      LAYER met3 ;
        RECT 6754.330 3690.740 6756.630 3691.090 ;
    END
  END gpio_analog_pol[12]
  PIN gpio_analog_pol[13]
    DIRECTION OUTPUT ;
    USE SIGNAL ;
    PORT
      LAYER met3 ;
        RECT 6754.330 4136.740 6756.630 4137.090 ;
    END
  END gpio_analog_pol[13]
  PIN gpio_analog_pol[14]
    DIRECTION OUTPUT ;
    USE SIGNAL ;
    PORT
      LAYER met3 ;
        RECT 6754.330 4582.740 6756.630 4583.090 ;
    END
  END gpio_analog_pol[14]
  PIN gpio_analog_pol[15]
    DIRECTION OUTPUT ;
    USE SIGNAL ;
    PORT
      LAYER met2 ;
        RECT 6551.580 4766.350 6551.860 4768.630 ;
    END
  END gpio_analog_pol[15]
  PIN gpio_analog_pol[16]
    DIRECTION OUTPUT ;
    USE SIGNAL ;
    PORT
      LAYER met2 ;
        RECT 6042.580 4766.350 6042.860 4768.630 ;
    END
  END gpio_analog_pol[16]
  PIN gpio_analog_pol[17]
    DIRECTION OUTPUT ;
    USE SIGNAL ;
    PORT
      LAYER met2 ;
        RECT 5785.580 4766.350 5785.860 4768.630 ;
    END
  END gpio_analog_pol[17]
  PIN gpio_analog_pol[18]
    DIRECTION OUTPUT ;
    USE SIGNAL ;
    PORT
      LAYER met2 ;
        RECT 5340.580 4766.350 5340.860 4768.630 ;
    END
  END gpio_analog_pol[18]
  PIN gpio_analog_pol[19]
    DIRECTION OUTPUT ;
    USE SIGNAL ;
    PORT
      LAYER met2 ;
        RECT 4831.580 4766.350 4831.860 4768.630 ;
    END
  END gpio_analog_pol[19]
  PIN gpio_analog_pol[1]
    DIRECTION OUTPUT ;
    USE SIGNAL ;
    PORT
      LAYER met3 ;
        RECT 6754.330 550.740 6756.630 551.090 ;
    END
  END gpio_analog_pol[1]
  PIN gpio_analog_pol[20]
    DIRECTION OUTPUT ;
    USE SIGNAL ;
    PORT
      LAYER met2 ;
        RECT 4573.580 4766.350 4573.860 4768.630 ;
    END
  END gpio_analog_pol[20]
  PIN gpio_analog_pol[21]
    DIRECTION OUTPUT ;
    USE SIGNAL ;
    PORT
      LAYER met2 ;
        RECT 4316.580 4766.350 4316.860 4768.630 ;
    END
  END gpio_analog_pol[21]
  PIN gpio_analog_pol[22]
    DIRECTION OUTPUT ;
    USE SIGNAL ;
    PORT
      LAYER met2 ;
        RECT 4059.580 4766.350 4059.860 4768.630 ;
    END
  END gpio_analog_pol[22]
  PIN gpio_analog_pol[23]
    DIRECTION OUTPUT ;
    USE SIGNAL ;
    PORT
      LAYER met2 ;
        RECT 3802.580 4766.350 3802.860 4768.630 ;
    END
  END gpio_analog_pol[23]
  PIN gpio_analog_pol[24]
    DIRECTION OUTPUT ;
    USE SIGNAL ;
    PORT
      LAYER met2 ;
        RECT 3477.580 4766.350 3477.860 4768.630 ;
    END
  END gpio_analog_pol[24]
  PIN gpio_analog_pol[25]
    DIRECTION OUTPUT ;
    USE SIGNAL ;
    PORT
      LAYER met2 ;
        RECT 3220.580 4766.350 3220.860 4768.630 ;
    END
  END gpio_analog_pol[25]
  PIN gpio_analog_pol[26]
    DIRECTION OUTPUT ;
    USE SIGNAL ;
    PORT
      LAYER met2 ;
        RECT 2963.580 4766.350 2963.860 4768.630 ;
    END
  END gpio_analog_pol[26]
  PIN gpio_analog_pol[27]
    DIRECTION OUTPUT ;
    USE SIGNAL ;
    PORT
      LAYER met2 ;
        RECT 2454.580 4766.350 2454.860 4768.630 ;
    END
  END gpio_analog_pol[27]
  PIN gpio_analog_pol[28]
    DIRECTION OUTPUT ;
    USE SIGNAL ;
    PORT
      LAYER met2 ;
        RECT 2197.580 4766.350 2197.860 4768.630 ;
    END
  END gpio_analog_pol[28]
  PIN gpio_analog_pol[29]
    DIRECTION OUTPUT ;
    USE SIGNAL ;
    PORT
      LAYER met2 ;
        RECT 1752.580 4766.350 1752.860 4768.630 ;
    END
  END gpio_analog_pol[29]
  PIN gpio_analog_pol[2]
    DIRECTION OUTPUT ;
    USE SIGNAL ;
    PORT
      LAYER met3 ;
        RECT 6754.330 775.740 6756.630 776.090 ;
    END
  END gpio_analog_pol[2]
  PIN gpio_analog_pol[30]
    DIRECTION OUTPUT ;
    USE SIGNAL ;
    PORT
      LAYER met2 ;
        RECT 1243.580 4766.350 1243.860 4768.630 ;
    END
  END gpio_analog_pol[30]
  PIN gpio_analog_pol[31]
    DIRECTION OUTPUT ;
    USE SIGNAL ;
    PORT
      LAYER met2 ;
        RECT 985.580 4766.350 985.860 4768.630 ;
    END
  END gpio_analog_pol[31]
  PIN gpio_analog_pol[32]
    DIRECTION OUTPUT ;
    USE SIGNAL ;
    PORT
      LAYER met2 ;
        RECT 728.580 4766.350 728.860 4768.630 ;
    END
  END gpio_analog_pol[32]
  PIN gpio_analog_pol[33]
    DIRECTION OUTPUT ;
    USE SIGNAL ;
    PORT
      LAYER met2 ;
        RECT 471.580 4766.350 471.860 4768.630 ;
    END
  END gpio_analog_pol[33]
  PIN gpio_analog_pol[34]
    DIRECTION OUTPUT ;
    USE SIGNAL ;
    PORT
      LAYER met2 ;
        RECT 214.580 4766.350 214.860 4768.630 ;
    END
  END gpio_analog_pol[34]
  PIN gpio_analog_pol[35]
    DIRECTION OUTPUT ;
    USE SIGNAL ;
    PORT
      LAYER met3 ;
        RECT -2.000 4604.540 0.300 4604.890 ;
    END
  END gpio_analog_pol[35]
  PIN gpio_analog_pol[36]
    DIRECTION OUTPUT ;
    USE SIGNAL ;
    PORT
      LAYER met3 ;
        RECT -2.000 3755.540 0.300 3755.890 ;
    END
  END gpio_analog_pol[36]
  PIN gpio_analog_pol[37]
    DIRECTION OUTPUT ;
    USE SIGNAL ;
    PORT
      LAYER met3 ;
        RECT -2.000 3539.540 0.300 3539.890 ;
    END
  END gpio_analog_pol[37]
  PIN gpio_analog_pol[38]
    DIRECTION OUTPUT ;
    USE SIGNAL ;
    PORT
      LAYER met3 ;
        RECT -2.000 3323.540 0.300 3323.890 ;
    END
  END gpio_analog_pol[38]
  PIN gpio_analog_pol[39]
    DIRECTION OUTPUT ;
    USE SIGNAL ;
    PORT
      LAYER met3 ;
        RECT -2.000 3107.540 0.300 3107.890 ;
    END
  END gpio_analog_pol[39]
  PIN gpio_analog_pol[3]
    DIRECTION OUTPUT ;
    USE SIGNAL ;
    PORT
      LAYER met3 ;
        RECT 6754.330 1001.740 6756.630 1002.090 ;
    END
  END gpio_analog_pol[3]
  PIN gpio_analog_pol[40]
    DIRECTION OUTPUT ;
    USE SIGNAL ;
    PORT
      LAYER met3 ;
        RECT -2.000 2891.540 0.300 2891.890 ;
    END
  END gpio_analog_pol[40]
  PIN gpio_analog_pol[41]
    DIRECTION OUTPUT ;
    USE SIGNAL ;
    PORT
      LAYER met3 ;
        RECT -2.000 2675.540 0.300 2675.890 ;
    END
  END gpio_analog_pol[41]
  PIN gpio_analog_pol[42]
    DIRECTION OUTPUT ;
    USE SIGNAL ;
    PORT
      LAYER met3 ;
        RECT -2.000 2459.540 0.300 2459.890 ;
    END
  END gpio_analog_pol[42]
  PIN gpio_analog_pol[43]
    DIRECTION OUTPUT ;
    USE SIGNAL ;
    PORT
      LAYER met3 ;
        RECT -2.000 1821.540 0.300 1821.890 ;
    END
  END gpio_analog_pol[43]
  PIN gpio_analog_pol[44]
    DIRECTION OUTPUT ;
    USE SIGNAL ;
    PORT
      LAYER met3 ;
        RECT -2.000 1605.540 0.300 1605.890 ;
    END
  END gpio_analog_pol[44]
  PIN gpio_analog_pol[45]
    DIRECTION OUTPUT ;
    USE SIGNAL ;
    PORT
      LAYER met3 ;
        RECT -2.000 1389.540 0.300 1389.890 ;
    END
  END gpio_analog_pol[45]
  PIN gpio_analog_pol[46]
    DIRECTION OUTPUT ;
    USE SIGNAL ;
    PORT
      LAYER met3 ;
        RECT -2.000 1173.540 0.300 1173.890 ;
    END
  END gpio_analog_pol[46]
  PIN gpio_analog_pol[47]
    DIRECTION OUTPUT ;
    USE SIGNAL ;
    PORT
      LAYER met3 ;
        RECT -2.000 957.540 0.300 957.890 ;
    END
  END gpio_analog_pol[47]
  PIN gpio_analog_pol[48]
    DIRECTION OUTPUT ;
    USE SIGNAL ;
    PORT
      LAYER met3 ;
        RECT -2.000 741.540 0.300 741.890 ;
    END
  END gpio_analog_pol[48]
  PIN gpio_analog_pol[49]
    DIRECTION OUTPUT ;
    USE SIGNAL ;
    PORT
      LAYER met2 ;
        RECT 756.770 -2.000 757.050 0.280 ;
    END
  END gpio_analog_pol[49]
  PIN gpio_analog_pol[4]
    DIRECTION OUTPUT ;
    USE SIGNAL ;
    PORT
      LAYER met3 ;
        RECT 6754.330 1226.740 6756.630 1227.090 ;
    END
  END gpio_analog_pol[4]
  PIN gpio_analog_pol[50]
    DIRECTION OUTPUT ;
    USE SIGNAL ;
    PORT
      LAYER met2 ;
        RECT 1299.770 -2.000 1300.050 0.280 ;
    END
  END gpio_analog_pol[50]
  PIN gpio_analog_pol[51]
    DIRECTION OUTPUT ;
    USE SIGNAL ;
    PORT
      LAYER met2 ;
        RECT 1573.770 -2.000 1574.050 0.280 ;
    END
  END gpio_analog_pol[51]
  PIN gpio_analog_pol[52]
    DIRECTION OUTPUT ;
    USE SIGNAL ;
    PORT
      LAYER met2 ;
        RECT 1847.770 -2.000 1848.050 0.280 ;
    END
  END gpio_analog_pol[52]
  PIN gpio_analog_pol[53]
    DIRECTION OUTPUT ;
    USE SIGNAL ;
    PORT
      LAYER met2 ;
        RECT 2121.770 -2.000 2122.050 0.280 ;
    END
  END gpio_analog_pol[53]
  PIN gpio_analog_pol[54]
    DIRECTION OUTPUT ;
    USE SIGNAL ;
    PORT
      LAYER met2 ;
        RECT 2395.770 -2.000 2396.050 0.280 ;
    END
  END gpio_analog_pol[54]
  PIN gpio_analog_pol[55]
    DIRECTION OUTPUT ;
    USE SIGNAL ;
    PORT
      LAYER met2 ;
        RECT 3210.250 -2.000 3210.530 0.280 ;
    END
  END gpio_analog_pol[55]
  PIN gpio_analog_pol[56]
    DIRECTION OUTPUT ;
    USE SIGNAL ;
    PORT
      LAYER met2 ;
        RECT 3484.250 -2.000 3484.530 0.280 ;
    END
  END gpio_analog_pol[56]
  PIN gpio_analog_pol[57]
    DIRECTION OUTPUT ;
    USE SIGNAL ;
    PORT
      LAYER met2 ;
        RECT 4344.770 -2.000 4345.050 0.280 ;
    END
  END gpio_analog_pol[57]
  PIN gpio_analog_pol[58]
    DIRECTION OUTPUT ;
    USE SIGNAL ;
    PORT
      LAYER met2 ;
        RECT 4887.770 -2.000 4888.050 0.280 ;
    END
  END gpio_analog_pol[58]
  PIN gpio_analog_pol[59]
    DIRECTION OUTPUT ;
    USE SIGNAL ;
    PORT
      LAYER met2 ;
        RECT 5161.770 -2.000 5162.050 0.280 ;
    END
  END gpio_analog_pol[59]
  PIN gpio_analog_pol[5]
    DIRECTION OUTPUT ;
    USE SIGNAL ;
    PORT
      LAYER met3 ;
        RECT 6754.330 1451.740 6756.630 1452.090 ;
    END
  END gpio_analog_pol[5]
  PIN gpio_analog_pol[60]
    DIRECTION OUTPUT ;
    USE SIGNAL ;
    PORT
      LAYER met2 ;
        RECT 5435.770 -2.000 5436.050 0.280 ;
    END
  END gpio_analog_pol[60]
  PIN gpio_analog_pol[61]
    DIRECTION OUTPUT ;
    USE SIGNAL ;
    PORT
      LAYER met2 ;
        RECT 5709.770 -2.000 5710.050 0.280 ;
    END
  END gpio_analog_pol[61]
  PIN gpio_analog_pol[62]
    DIRECTION OUTPUT ;
    USE SIGNAL ;
    PORT
      LAYER met2 ;
        RECT 5983.770 -2.000 5984.050 0.280 ;
    END
  END gpio_analog_pol[62]
  PIN gpio_analog_pol[6]
    DIRECTION OUTPUT ;
    USE SIGNAL ;
    PORT
      LAYER met3 ;
        RECT 6754.330 1677.740 6756.630 1678.090 ;
    END
  END gpio_analog_pol[6]
  PIN gpio_analog_pol[7]
    DIRECTION OUTPUT ;
    USE SIGNAL ;
    PORT
      LAYER met3 ;
        RECT 6754.330 2563.740 6756.630 2564.090 ;
    END
  END gpio_analog_pol[7]
  PIN gpio_analog_pol[8]
    DIRECTION OUTPUT ;
    USE SIGNAL ;
    PORT
      LAYER met3 ;
        RECT 6754.330 2789.740 6756.630 2790.090 ;
    END
  END gpio_analog_pol[8]
  PIN gpio_analog_pol[9]
    DIRECTION OUTPUT ;
    USE SIGNAL ;
    PORT
      LAYER met3 ;
        RECT 6754.330 3014.740 6756.630 3015.090 ;
    END
  END gpio_analog_pol[9]
  PIN gpio_analog_sel[0]
    DIRECTION OUTPUT ;
    USE SIGNAL ;
    PORT
      LAYER met3 ;
        RECT 6754.330 339.920 6756.630 340.270 ;
    END
  END gpio_analog_sel[0]
  PIN gpio_analog_sel[10]
    DIRECTION OUTPUT ;
    USE SIGNAL ;
    PORT
      LAYER met3 ;
        RECT 6754.330 3255.920 6756.630 3256.270 ;
    END
  END gpio_analog_sel[10]
  PIN gpio_analog_sel[11]
    DIRECTION OUTPUT ;
    USE SIGNAL ;
    PORT
      LAYER met3 ;
        RECT 6754.330 3480.920 6756.630 3481.270 ;
    END
  END gpio_analog_sel[11]
  PIN gpio_analog_sel[12]
    DIRECTION OUTPUT ;
    USE SIGNAL ;
    PORT
      LAYER met3 ;
        RECT 6754.330 3705.920 6756.630 3706.270 ;
    END
  END gpio_analog_sel[12]
  PIN gpio_analog_sel[13]
    DIRECTION OUTPUT ;
    USE SIGNAL ;
    PORT
      LAYER met3 ;
        RECT 6754.330 4151.920 6756.630 4152.270 ;
    END
  END gpio_analog_sel[13]
  PIN gpio_analog_sel[14]
    DIRECTION OUTPUT ;
    USE SIGNAL ;
    PORT
      LAYER met3 ;
        RECT 6754.330 4597.920 6756.630 4598.270 ;
    END
  END gpio_analog_sel[14]
  PIN gpio_analog_sel[15]
    DIRECTION OUTPUT ;
    USE SIGNAL ;
    PORT
      LAYER met2 ;
        RECT 6536.400 4766.350 6536.680 4768.630 ;
    END
  END gpio_analog_sel[15]
  PIN gpio_analog_sel[16]
    DIRECTION OUTPUT ;
    USE SIGNAL ;
    PORT
      LAYER met2 ;
        RECT 6027.400 4766.350 6027.680 4768.630 ;
    END
  END gpio_analog_sel[16]
  PIN gpio_analog_sel[17]
    DIRECTION OUTPUT ;
    USE SIGNAL ;
    PORT
      LAYER met2 ;
        RECT 5770.400 4766.350 5770.680 4768.630 ;
    END
  END gpio_analog_sel[17]
  PIN gpio_analog_sel[18]
    DIRECTION OUTPUT ;
    USE SIGNAL ;
    PORT
      LAYER met2 ;
        RECT 5325.400 4766.350 5325.680 4768.630 ;
    END
  END gpio_analog_sel[18]
  PIN gpio_analog_sel[19]
    DIRECTION OUTPUT ;
    USE SIGNAL ;
    PORT
      LAYER met2 ;
        RECT 4816.400 4766.350 4816.680 4768.630 ;
    END
  END gpio_analog_sel[19]
  PIN gpio_analog_sel[1]
    DIRECTION OUTPUT ;
    USE SIGNAL ;
    PORT
      LAYER met3 ;
        RECT 6754.330 565.920 6756.630 566.270 ;
    END
  END gpio_analog_sel[1]
  PIN gpio_analog_sel[20]
    DIRECTION OUTPUT ;
    USE SIGNAL ;
    PORT
      LAYER met2 ;
        RECT 4558.400 4766.350 4558.680 4768.630 ;
    END
  END gpio_analog_sel[20]
  PIN gpio_analog_sel[21]
    DIRECTION OUTPUT ;
    USE SIGNAL ;
    PORT
      LAYER met2 ;
        RECT 4301.400 4766.350 4301.680 4768.630 ;
    END
  END gpio_analog_sel[21]
  PIN gpio_analog_sel[22]
    DIRECTION OUTPUT ;
    USE SIGNAL ;
    PORT
      LAYER met2 ;
        RECT 4044.400 4766.350 4044.680 4768.630 ;
    END
  END gpio_analog_sel[22]
  PIN gpio_analog_sel[23]
    DIRECTION OUTPUT ;
    USE SIGNAL ;
    PORT
      LAYER met2 ;
        RECT 3787.400 4766.350 3787.680 4768.630 ;
    END
  END gpio_analog_sel[23]
  PIN gpio_analog_sel[24]
    DIRECTION OUTPUT ;
    USE SIGNAL ;
    PORT
      LAYER met2 ;
        RECT 3462.400 4766.350 3462.680 4768.630 ;
    END
  END gpio_analog_sel[24]
  PIN gpio_analog_sel[25]
    DIRECTION OUTPUT ;
    USE SIGNAL ;
    PORT
      LAYER met2 ;
        RECT 3205.400 4766.350 3205.680 4768.630 ;
    END
  END gpio_analog_sel[25]
  PIN gpio_analog_sel[26]
    DIRECTION OUTPUT ;
    USE SIGNAL ;
    PORT
      LAYER met2 ;
        RECT 2948.400 4766.350 2948.680 4768.630 ;
    END
  END gpio_analog_sel[26]
  PIN gpio_analog_sel[27]
    DIRECTION OUTPUT ;
    USE SIGNAL ;
    PORT
      LAYER met2 ;
        RECT 2439.400 4766.350 2439.680 4768.630 ;
    END
  END gpio_analog_sel[27]
  PIN gpio_analog_sel[28]
    DIRECTION OUTPUT ;
    USE SIGNAL ;
    PORT
      LAYER met2 ;
        RECT 2182.400 4766.350 2182.680 4768.630 ;
    END
  END gpio_analog_sel[28]
  PIN gpio_analog_sel[29]
    DIRECTION OUTPUT ;
    USE SIGNAL ;
    PORT
      LAYER met2 ;
        RECT 1737.400 4766.350 1737.680 4768.630 ;
    END
  END gpio_analog_sel[29]
  PIN gpio_analog_sel[2]
    DIRECTION OUTPUT ;
    USE SIGNAL ;
    PORT
      LAYER met3 ;
        RECT 6754.330 790.920 6756.630 791.270 ;
    END
  END gpio_analog_sel[2]
  PIN gpio_analog_sel[30]
    DIRECTION OUTPUT ;
    USE SIGNAL ;
    PORT
      LAYER met2 ;
        RECT 1228.400 4766.350 1228.680 4768.630 ;
    END
  END gpio_analog_sel[30]
  PIN gpio_analog_sel[31]
    DIRECTION OUTPUT ;
    USE SIGNAL ;
    PORT
      LAYER met2 ;
        RECT 970.400 4766.350 970.680 4768.630 ;
    END
  END gpio_analog_sel[31]
  PIN gpio_analog_sel[32]
    DIRECTION OUTPUT ;
    USE SIGNAL ;
    PORT
      LAYER met2 ;
        RECT 713.400 4766.350 713.680 4768.630 ;
    END
  END gpio_analog_sel[32]
  PIN gpio_analog_sel[33]
    DIRECTION OUTPUT ;
    USE SIGNAL ;
    PORT
      LAYER met2 ;
        RECT 456.400 4766.350 456.680 4768.630 ;
    END
  END gpio_analog_sel[33]
  PIN gpio_analog_sel[34]
    DIRECTION OUTPUT ;
    USE SIGNAL ;
    PORT
      LAYER met2 ;
        RECT 199.400 4766.350 199.680 4768.630 ;
    END
  END gpio_analog_sel[34]
  PIN gpio_analog_sel[35]
    DIRECTION OUTPUT ;
    USE SIGNAL ;
    PORT
      LAYER met3 ;
        RECT -2.000 4589.360 0.300 4589.710 ;
    END
  END gpio_analog_sel[35]
  PIN gpio_analog_sel[36]
    DIRECTION OUTPUT ;
    USE SIGNAL ;
    PORT
      LAYER met3 ;
        RECT -2.000 3740.360 0.300 3740.710 ;
    END
  END gpio_analog_sel[36]
  PIN gpio_analog_sel[37]
    DIRECTION OUTPUT ;
    USE SIGNAL ;
    PORT
      LAYER met3 ;
        RECT -2.000 3524.360 0.300 3524.710 ;
    END
  END gpio_analog_sel[37]
  PIN gpio_analog_sel[38]
    DIRECTION OUTPUT ;
    USE SIGNAL ;
    PORT
      LAYER met3 ;
        RECT -2.000 3308.360 0.300 3308.710 ;
    END
  END gpio_analog_sel[38]
  PIN gpio_analog_sel[39]
    DIRECTION OUTPUT ;
    USE SIGNAL ;
    PORT
      LAYER met3 ;
        RECT -2.000 3092.360 0.300 3092.710 ;
    END
  END gpio_analog_sel[39]
  PIN gpio_analog_sel[3]
    DIRECTION OUTPUT ;
    USE SIGNAL ;
    PORT
      LAYER met3 ;
        RECT 6754.330 1016.920 6756.630 1017.270 ;
    END
  END gpio_analog_sel[3]
  PIN gpio_analog_sel[40]
    DIRECTION OUTPUT ;
    USE SIGNAL ;
    PORT
      LAYER met3 ;
        RECT -2.000 2876.360 0.300 2876.710 ;
    END
  END gpio_analog_sel[40]
  PIN gpio_analog_sel[41]
    DIRECTION OUTPUT ;
    USE SIGNAL ;
    PORT
      LAYER met3 ;
        RECT -2.000 2660.360 0.300 2660.710 ;
    END
  END gpio_analog_sel[41]
  PIN gpio_analog_sel[42]
    DIRECTION OUTPUT ;
    USE SIGNAL ;
    PORT
      LAYER met3 ;
        RECT -2.000 2444.360 0.300 2444.710 ;
    END
  END gpio_analog_sel[42]
  PIN gpio_analog_sel[43]
    DIRECTION OUTPUT ;
    USE SIGNAL ;
    PORT
      LAYER met3 ;
        RECT -2.000 1806.360 0.300 1806.710 ;
    END
  END gpio_analog_sel[43]
  PIN gpio_analog_sel[44]
    DIRECTION OUTPUT ;
    USE SIGNAL ;
    PORT
      LAYER met3 ;
        RECT -2.000 1590.360 0.300 1590.710 ;
    END
  END gpio_analog_sel[44]
  PIN gpio_analog_sel[45]
    DIRECTION OUTPUT ;
    USE SIGNAL ;
    PORT
      LAYER met3 ;
        RECT -2.000 1374.360 0.300 1374.710 ;
    END
  END gpio_analog_sel[45]
  PIN gpio_analog_sel[46]
    DIRECTION OUTPUT ;
    USE SIGNAL ;
    PORT
      LAYER met3 ;
        RECT -2.000 1158.360 0.300 1158.710 ;
    END
  END gpio_analog_sel[46]
  PIN gpio_analog_sel[47]
    DIRECTION OUTPUT ;
    USE SIGNAL ;
    PORT
      LAYER met3 ;
        RECT -2.000 942.360 0.300 942.710 ;
    END
  END gpio_analog_sel[47]
  PIN gpio_analog_sel[48]
    DIRECTION OUTPUT ;
    USE SIGNAL ;
    PORT
      LAYER met3 ;
        RECT -2.000 726.360 0.300 726.710 ;
    END
  END gpio_analog_sel[48]
  PIN gpio_analog_sel[49]
    DIRECTION OUTPUT ;
    USE SIGNAL ;
    PORT
      LAYER met2 ;
        RECT 771.950 -2.000 772.230 0.280 ;
    END
  END gpio_analog_sel[49]
  PIN gpio_analog_sel[4]
    DIRECTION OUTPUT ;
    USE SIGNAL ;
    PORT
      LAYER met3 ;
        RECT 6754.330 1241.920 6756.630 1242.270 ;
    END
  END gpio_analog_sel[4]
  PIN gpio_analog_sel[50]
    DIRECTION OUTPUT ;
    USE SIGNAL ;
    PORT
      LAYER met2 ;
        RECT 1314.950 -2.000 1315.230 0.280 ;
    END
  END gpio_analog_sel[50]
  PIN gpio_analog_sel[51]
    DIRECTION OUTPUT ;
    USE SIGNAL ;
    PORT
      LAYER met2 ;
        RECT 1588.950 -2.000 1589.230 0.280 ;
    END
  END gpio_analog_sel[51]
  PIN gpio_analog_sel[52]
    DIRECTION OUTPUT ;
    USE SIGNAL ;
    PORT
      LAYER met2 ;
        RECT 1862.950 -2.000 1863.230 0.280 ;
    END
  END gpio_analog_sel[52]
  PIN gpio_analog_sel[53]
    DIRECTION OUTPUT ;
    USE SIGNAL ;
    PORT
      LAYER met2 ;
        RECT 2136.950 -2.000 2137.230 0.280 ;
    END
  END gpio_analog_sel[53]
  PIN gpio_analog_sel[54]
    DIRECTION OUTPUT ;
    USE SIGNAL ;
    PORT
      LAYER met2 ;
        RECT 2410.950 -2.000 2411.230 0.280 ;
    END
  END gpio_analog_sel[54]
  PIN gpio_analog_sel[55]
    DIRECTION OUTPUT ;
    USE SIGNAL ;
    PORT
      LAYER met2 ;
        RECT 3225.430 -2.000 3225.710 0.280 ;
    END
  END gpio_analog_sel[55]
  PIN gpio_analog_sel[56]
    DIRECTION OUTPUT ;
    USE SIGNAL ;
    PORT
      LAYER met2 ;
        RECT 3499.430 -2.000 3499.710 0.280 ;
    END
  END gpio_analog_sel[56]
  PIN gpio_analog_sel[57]
    DIRECTION OUTPUT ;
    USE SIGNAL ;
    PORT
      LAYER met2 ;
        RECT 4359.950 -2.000 4360.230 0.280 ;
    END
  END gpio_analog_sel[57]
  PIN gpio_analog_sel[58]
    DIRECTION OUTPUT ;
    USE SIGNAL ;
    PORT
      LAYER met2 ;
        RECT 4902.950 -2.000 4903.230 0.280 ;
    END
  END gpio_analog_sel[58]
  PIN gpio_analog_sel[59]
    DIRECTION OUTPUT ;
    USE SIGNAL ;
    PORT
      LAYER met2 ;
        RECT 5176.950 -2.000 5177.230 0.280 ;
    END
  END gpio_analog_sel[59]
  PIN gpio_analog_sel[5]
    DIRECTION OUTPUT ;
    USE SIGNAL ;
    PORT
      LAYER met3 ;
        RECT 6754.330 1466.920 6756.630 1467.270 ;
    END
  END gpio_analog_sel[5]
  PIN gpio_analog_sel[60]
    DIRECTION OUTPUT ;
    USE SIGNAL ;
    PORT
      LAYER met2 ;
        RECT 5450.950 -2.000 5451.230 0.280 ;
    END
  END gpio_analog_sel[60]
  PIN gpio_analog_sel[61]
    DIRECTION OUTPUT ;
    USE SIGNAL ;
    PORT
      LAYER met2 ;
        RECT 5724.950 -2.000 5725.230 0.280 ;
    END
  END gpio_analog_sel[61]
  PIN gpio_analog_sel[62]
    DIRECTION OUTPUT ;
    USE SIGNAL ;
    PORT
      LAYER met2 ;
        RECT 5998.950 -2.000 5999.230 0.280 ;
    END
  END gpio_analog_sel[62]
  PIN gpio_analog_sel[6]
    DIRECTION OUTPUT ;
    USE SIGNAL ;
    PORT
      LAYER met3 ;
        RECT 6754.330 1692.920 6756.630 1693.270 ;
    END
  END gpio_analog_sel[6]
  PIN gpio_analog_sel[7]
    DIRECTION OUTPUT ;
    USE SIGNAL ;
    PORT
      LAYER met3 ;
        RECT 6754.330 2578.920 6756.630 2579.270 ;
    END
  END gpio_analog_sel[7]
  PIN gpio_analog_sel[8]
    DIRECTION OUTPUT ;
    USE SIGNAL ;
    PORT
      LAYER met3 ;
        RECT 6754.330 2804.920 6756.630 2805.270 ;
    END
  END gpio_analog_sel[8]
  PIN gpio_analog_sel[9]
    DIRECTION OUTPUT ;
    USE SIGNAL ;
    PORT
      LAYER met3 ;
        RECT 6754.330 3029.920 6756.630 3030.270 ;
    END
  END gpio_analog_sel[9]
  PIN gpio_dm0[0]
    DIRECTION OUTPUT ;
    USE SIGNAL ;
    PORT
      LAYER met3 ;
        RECT 6754.330 321.520 6756.630 321.870 ;
    END
  END gpio_dm0[0]
  PIN gpio_dm0[10]
    DIRECTION OUTPUT ;
    USE SIGNAL ;
    PORT
      LAYER met3 ;
        RECT 6754.330 3237.520 6756.630 3237.870 ;
    END
  END gpio_dm0[10]
  PIN gpio_dm0[11]
    DIRECTION OUTPUT ;
    USE SIGNAL ;
    PORT
      LAYER met3 ;
        RECT 6754.330 3462.520 6756.630 3462.870 ;
    END
  END gpio_dm0[11]
  PIN gpio_dm0[12]
    DIRECTION OUTPUT ;
    USE SIGNAL ;
    PORT
      LAYER met3 ;
        RECT 6754.330 3687.520 6756.630 3687.870 ;
    END
  END gpio_dm0[12]
  PIN gpio_dm0[13]
    DIRECTION OUTPUT ;
    USE SIGNAL ;
    PORT
      LAYER met3 ;
        RECT 6754.330 4133.520 6756.630 4133.870 ;
    END
  END gpio_dm0[13]
  PIN gpio_dm0[14]
    DIRECTION OUTPUT ;
    USE SIGNAL ;
    PORT
      LAYER met3 ;
        RECT 6754.330 4579.520 6756.630 4579.870 ;
    END
  END gpio_dm0[14]
  PIN gpio_dm0[15]
    DIRECTION OUTPUT ;
    USE SIGNAL ;
    PORT
      LAYER met2 ;
        RECT 6554.800 4766.350 6555.080 4768.630 ;
    END
  END gpio_dm0[15]
  PIN gpio_dm0[16]
    DIRECTION OUTPUT ;
    USE SIGNAL ;
    PORT
      LAYER met2 ;
        RECT 6045.800 4766.350 6046.080 4768.630 ;
    END
  END gpio_dm0[16]
  PIN gpio_dm0[17]
    DIRECTION OUTPUT ;
    USE SIGNAL ;
    PORT
      LAYER met2 ;
        RECT 5788.800 4766.350 5789.080 4768.630 ;
    END
  END gpio_dm0[17]
  PIN gpio_dm0[18]
    DIRECTION OUTPUT ;
    USE SIGNAL ;
    PORT
      LAYER met2 ;
        RECT 5343.800 4766.350 5344.080 4768.630 ;
    END
  END gpio_dm0[18]
  PIN gpio_dm0[19]
    DIRECTION OUTPUT ;
    USE SIGNAL ;
    PORT
      LAYER met2 ;
        RECT 4834.800 4766.350 4835.080 4768.630 ;
    END
  END gpio_dm0[19]
  PIN gpio_dm0[1]
    DIRECTION OUTPUT ;
    USE SIGNAL ;
    PORT
      LAYER met3 ;
        RECT 6754.330 547.520 6756.630 547.870 ;
    END
  END gpio_dm0[1]
  PIN gpio_dm0[20]
    DIRECTION OUTPUT ;
    USE SIGNAL ;
    PORT
      LAYER met2 ;
        RECT 4576.800 4766.220 4577.080 4768.630 ;
    END
  END gpio_dm0[20]
  PIN gpio_dm0[21]
    DIRECTION OUTPUT ;
    USE SIGNAL ;
    PORT
      LAYER met2 ;
        RECT 4319.800 4766.350 4320.080 4768.630 ;
    END
  END gpio_dm0[21]
  PIN gpio_dm0[22]
    DIRECTION OUTPUT ;
    USE SIGNAL ;
    PORT
      LAYER met2 ;
        RECT 4062.800 4766.350 4063.080 4768.630 ;
    END
  END gpio_dm0[22]
  PIN gpio_dm0[23]
    DIRECTION OUTPUT ;
    USE SIGNAL ;
    PORT
      LAYER met2 ;
        RECT 3805.800 4766.350 3806.080 4768.630 ;
    END
  END gpio_dm0[23]
  PIN gpio_dm0[24]
    DIRECTION OUTPUT ;
    USE SIGNAL ;
    PORT
      LAYER met2 ;
        RECT 3480.800 4766.350 3481.080 4768.630 ;
    END
  END gpio_dm0[24]
  PIN gpio_dm0[25]
    DIRECTION OUTPUT ;
    USE SIGNAL ;
    PORT
      LAYER met2 ;
        RECT 3223.800 4766.350 3224.080 4768.630 ;
    END
  END gpio_dm0[25]
  PIN gpio_dm0[26]
    DIRECTION OUTPUT ;
    USE SIGNAL ;
    PORT
      LAYER met2 ;
        RECT 2966.800 4766.350 2967.080 4768.630 ;
    END
  END gpio_dm0[26]
  PIN gpio_dm0[27]
    DIRECTION OUTPUT ;
    USE SIGNAL ;
    PORT
      LAYER met2 ;
        RECT 2457.800 4766.350 2458.080 4768.630 ;
    END
  END gpio_dm0[27]
  PIN gpio_dm0[28]
    DIRECTION OUTPUT ;
    USE SIGNAL ;
    PORT
      LAYER met2 ;
        RECT 2200.800 4766.350 2201.080 4768.630 ;
    END
  END gpio_dm0[28]
  PIN gpio_dm0[29]
    DIRECTION OUTPUT ;
    USE SIGNAL ;
    PORT
      LAYER met2 ;
        RECT 1755.800 4766.350 1756.080 4768.630 ;
    END
  END gpio_dm0[29]
  PIN gpio_dm0[2]
    DIRECTION OUTPUT ;
    USE SIGNAL ;
    PORT
      LAYER met3 ;
        RECT 6754.330 772.520 6756.630 772.870 ;
    END
  END gpio_dm0[2]
  PIN gpio_dm0[30]
    DIRECTION OUTPUT ;
    USE SIGNAL ;
    PORT
      LAYER met2 ;
        RECT 1246.800 4766.350 1247.080 4768.630 ;
    END
  END gpio_dm0[30]
  PIN gpio_dm0[31]
    DIRECTION OUTPUT ;
    USE SIGNAL ;
    PORT
      LAYER met2 ;
        RECT 988.800 4766.350 989.080 4768.630 ;
    END
  END gpio_dm0[31]
  PIN gpio_dm0[32]
    DIRECTION OUTPUT ;
    USE SIGNAL ;
    PORT
      LAYER met2 ;
        RECT 731.800 4766.350 732.080 4768.630 ;
    END
  END gpio_dm0[32]
  PIN gpio_dm0[33]
    DIRECTION OUTPUT ;
    USE SIGNAL ;
    PORT
      LAYER met2 ;
        RECT 474.800 4766.350 475.080 4768.630 ;
    END
  END gpio_dm0[33]
  PIN gpio_dm0[34]
    DIRECTION OUTPUT ;
    USE SIGNAL ;
    PORT
      LAYER met2 ;
        RECT 217.800 4766.350 218.080 4768.630 ;
    END
  END gpio_dm0[34]
  PIN gpio_dm0[35]
    DIRECTION OUTPUT ;
    USE SIGNAL ;
    PORT
      LAYER met3 ;
        RECT -2.000 4607.760 0.300 4608.110 ;
    END
  END gpio_dm0[35]
  PIN gpio_dm0[36]
    DIRECTION OUTPUT ;
    USE SIGNAL ;
    PORT
      LAYER met3 ;
        RECT -2.000 3758.760 0.300 3759.110 ;
    END
  END gpio_dm0[36]
  PIN gpio_dm0[37]
    DIRECTION OUTPUT ;
    USE SIGNAL ;
    PORT
      LAYER met3 ;
        RECT -2.000 3542.760 0.300 3543.110 ;
    END
  END gpio_dm0[37]
  PIN gpio_dm0[38]
    DIRECTION OUTPUT ;
    USE SIGNAL ;
    PORT
      LAYER met3 ;
        RECT -2.000 3326.760 0.300 3327.110 ;
    END
  END gpio_dm0[38]
  PIN gpio_dm0[39]
    DIRECTION OUTPUT ;
    USE SIGNAL ;
    PORT
      LAYER met3 ;
        RECT -2.000 3110.760 0.300 3111.110 ;
    END
  END gpio_dm0[39]
  PIN gpio_dm0[3]
    DIRECTION OUTPUT ;
    USE SIGNAL ;
    PORT
      LAYER met3 ;
        RECT 6754.330 998.520 6756.630 998.870 ;
    END
  END gpio_dm0[3]
  PIN gpio_dm0[40]
    DIRECTION OUTPUT ;
    USE SIGNAL ;
    PORT
      LAYER met3 ;
        RECT -2.000 2894.760 0.300 2895.110 ;
    END
  END gpio_dm0[40]
  PIN gpio_dm0[41]
    DIRECTION OUTPUT ;
    USE SIGNAL ;
    PORT
      LAYER met3 ;
        RECT -2.000 2678.760 0.300 2679.110 ;
    END
  END gpio_dm0[41]
  PIN gpio_dm0[42]
    DIRECTION OUTPUT ;
    USE SIGNAL ;
    PORT
      LAYER met3 ;
        RECT -2.000 2462.760 0.300 2463.110 ;
    END
  END gpio_dm0[42]
  PIN gpio_dm0[43]
    DIRECTION OUTPUT ;
    USE SIGNAL ;
    PORT
      LAYER met3 ;
        RECT -2.000 1824.760 0.300 1825.110 ;
    END
  END gpio_dm0[43]
  PIN gpio_dm0[44]
    DIRECTION OUTPUT ;
    USE SIGNAL ;
    PORT
      LAYER met3 ;
        RECT -2.000 1608.760 0.300 1609.110 ;
    END
  END gpio_dm0[44]
  PIN gpio_dm0[45]
    DIRECTION OUTPUT ;
    USE SIGNAL ;
    PORT
      LAYER met3 ;
        RECT -2.000 1392.760 0.300 1393.110 ;
    END
  END gpio_dm0[45]
  PIN gpio_dm0[46]
    DIRECTION OUTPUT ;
    USE SIGNAL ;
    PORT
      LAYER met3 ;
        RECT -2.000 1176.760 0.300 1177.110 ;
    END
  END gpio_dm0[46]
  PIN gpio_dm0[47]
    DIRECTION OUTPUT ;
    USE SIGNAL ;
    PORT
      LAYER met3 ;
        RECT -2.000 960.760 0.300 961.110 ;
    END
  END gpio_dm0[47]
  PIN gpio_dm0[48]
    DIRECTION OUTPUT ;
    USE SIGNAL ;
    PORT
      LAYER met3 ;
        RECT -2.000 744.760 0.300 745.110 ;
    END
  END gpio_dm0[48]
  PIN gpio_dm0[49]
    DIRECTION OUTPUT ;
    USE SIGNAL ;
    PORT
      LAYER met2 ;
        RECT 753.550 -2.000 753.830 0.280 ;
    END
  END gpio_dm0[49]
  PIN gpio_dm0[4]
    DIRECTION OUTPUT ;
    USE SIGNAL ;
    PORT
      LAYER met3 ;
        RECT 6754.330 1223.520 6756.630 1223.870 ;
    END
  END gpio_dm0[4]
  PIN gpio_dm0[50]
    DIRECTION OUTPUT ;
    USE SIGNAL ;
    PORT
      LAYER met2 ;
        RECT 1296.550 -2.000 1296.830 0.280 ;
    END
  END gpio_dm0[50]
  PIN gpio_dm0[51]
    DIRECTION OUTPUT ;
    USE SIGNAL ;
    PORT
      LAYER met2 ;
        RECT 1570.550 -2.000 1570.830 0.280 ;
    END
  END gpio_dm0[51]
  PIN gpio_dm0[52]
    DIRECTION OUTPUT ;
    USE SIGNAL ;
    PORT
      LAYER met2 ;
        RECT 1844.550 -2.000 1844.830 0.280 ;
    END
  END gpio_dm0[52]
  PIN gpio_dm0[53]
    DIRECTION OUTPUT ;
    USE SIGNAL ;
    PORT
      LAYER met2 ;
        RECT 2118.550 -2.000 2118.830 0.280 ;
    END
  END gpio_dm0[53]
  PIN gpio_dm0[54]
    DIRECTION OUTPUT ;
    USE SIGNAL ;
    PORT
      LAYER met2 ;
        RECT 2392.550 -2.000 2392.830 0.280 ;
    END
  END gpio_dm0[54]
  PIN gpio_dm0[55]
    DIRECTION OUTPUT ;
    USE SIGNAL ;
    PORT
      LAYER met2 ;
        RECT 3207.030 -2.000 3207.310 0.280 ;
    END
  END gpio_dm0[55]
  PIN gpio_dm0[56]
    DIRECTION OUTPUT ;
    USE SIGNAL ;
    PORT
      LAYER met2 ;
        RECT 3481.030 -2.000 3481.310 0.280 ;
    END
  END gpio_dm0[56]
  PIN gpio_dm0[57]
    DIRECTION OUTPUT ;
    USE SIGNAL ;
    PORT
      LAYER met2 ;
        RECT 4341.550 -2.000 4341.830 0.280 ;
    END
  END gpio_dm0[57]
  PIN gpio_dm0[58]
    DIRECTION OUTPUT ;
    USE SIGNAL ;
    PORT
      LAYER met2 ;
        RECT 4884.550 -2.000 4884.830 0.280 ;
    END
  END gpio_dm0[58]
  PIN gpio_dm0[59]
    DIRECTION OUTPUT ;
    USE SIGNAL ;
    PORT
      LAYER met2 ;
        RECT 5158.550 -2.000 5158.830 0.280 ;
    END
  END gpio_dm0[59]
  PIN gpio_dm0[5]
    DIRECTION OUTPUT ;
    USE SIGNAL ;
    PORT
      LAYER met3 ;
        RECT 6754.330 1448.520 6756.630 1448.870 ;
    END
  END gpio_dm0[5]
  PIN gpio_dm0[60]
    DIRECTION OUTPUT ;
    USE SIGNAL ;
    PORT
      LAYER met2 ;
        RECT 5432.550 -2.000 5432.830 0.280 ;
    END
  END gpio_dm0[60]
  PIN gpio_dm0[61]
    DIRECTION OUTPUT ;
    USE SIGNAL ;
    PORT
      LAYER met2 ;
        RECT 5706.550 -2.000 5706.830 0.280 ;
    END
  END gpio_dm0[61]
  PIN gpio_dm0[62]
    DIRECTION OUTPUT ;
    USE SIGNAL ;
    PORT
      LAYER met2 ;
        RECT 5980.550 -2.000 5980.830 0.280 ;
    END
  END gpio_dm0[62]
  PIN gpio_dm0[6]
    DIRECTION OUTPUT ;
    USE SIGNAL ;
    PORT
      LAYER met3 ;
        RECT 6754.330 1674.520 6756.630 1674.870 ;
    END
  END gpio_dm0[6]
  PIN gpio_dm0[7]
    DIRECTION OUTPUT ;
    USE SIGNAL ;
    PORT
      LAYER met3 ;
        RECT 6754.330 2560.520 6756.630 2560.870 ;
    END
  END gpio_dm0[7]
  PIN gpio_dm0[8]
    DIRECTION OUTPUT ;
    USE SIGNAL ;
    PORT
      LAYER met3 ;
        RECT 6754.330 2786.520 6756.630 2786.870 ;
    END
  END gpio_dm0[8]
  PIN gpio_dm0[9]
    DIRECTION OUTPUT ;
    USE SIGNAL ;
    PORT
      LAYER met3 ;
        RECT 6754.330 3011.520 6756.630 3011.870 ;
    END
  END gpio_dm0[9]
  PIN gpio_dm1[0]
    DIRECTION OUTPUT ;
    USE SIGNAL ;
    PORT
      LAYER met3 ;
        RECT 6754.330 312.320 6756.630 312.670 ;
    END
  END gpio_dm1[0]
  PIN gpio_dm1[10]
    DIRECTION OUTPUT ;
    USE SIGNAL ;
    PORT
      LAYER met3 ;
        RECT 6754.330 3228.320 6756.630 3228.670 ;
    END
  END gpio_dm1[10]
  PIN gpio_dm1[11]
    DIRECTION OUTPUT ;
    USE SIGNAL ;
    PORT
      LAYER met3 ;
        RECT 6754.330 3453.320 6756.630 3453.670 ;
    END
  END gpio_dm1[11]
  PIN gpio_dm1[12]
    DIRECTION OUTPUT ;
    USE SIGNAL ;
    PORT
      LAYER met3 ;
        RECT 6754.330 3678.320 6756.630 3678.670 ;
    END
  END gpio_dm1[12]
  PIN gpio_dm1[13]
    DIRECTION OUTPUT ;
    USE SIGNAL ;
    PORT
      LAYER met3 ;
        RECT 6754.330 4124.320 6756.630 4124.670 ;
    END
  END gpio_dm1[13]
  PIN gpio_dm1[14]
    DIRECTION OUTPUT ;
    USE SIGNAL ;
    PORT
      LAYER met3 ;
        RECT 6754.330 4570.320 6756.630 4570.670 ;
    END
  END gpio_dm1[14]
  PIN gpio_dm1[15]
    DIRECTION OUTPUT ;
    USE SIGNAL ;
    PORT
      LAYER met2 ;
        RECT 6564.000 4766.350 6564.280 4768.630 ;
    END
  END gpio_dm1[15]
  PIN gpio_dm1[16]
    DIRECTION OUTPUT ;
    USE SIGNAL ;
    PORT
      LAYER met2 ;
        RECT 6055.000 4766.350 6055.280 4768.630 ;
    END
  END gpio_dm1[16]
  PIN gpio_dm1[17]
    DIRECTION OUTPUT ;
    USE SIGNAL ;
    PORT
      LAYER met2 ;
        RECT 5798.000 4766.350 5798.280 4768.630 ;
    END
  END gpio_dm1[17]
  PIN gpio_dm1[18]
    DIRECTION OUTPUT ;
    USE SIGNAL ;
    PORT
      LAYER met2 ;
        RECT 5353.000 4766.350 5353.280 4768.630 ;
    END
  END gpio_dm1[18]
  PIN gpio_dm1[19]
    DIRECTION OUTPUT ;
    USE SIGNAL ;
    PORT
      LAYER met2 ;
        RECT 4844.000 4766.350 4844.280 4768.630 ;
    END
  END gpio_dm1[19]
  PIN gpio_dm1[1]
    DIRECTION OUTPUT ;
    USE SIGNAL ;
    PORT
      LAYER met3 ;
        RECT 6754.330 538.320 6756.630 538.670 ;
    END
  END gpio_dm1[1]
  PIN gpio_dm1[20]
    DIRECTION OUTPUT ;
    USE SIGNAL ;
    PORT
      LAYER met2 ;
        RECT 4586.000 4766.350 4586.280 4768.630 ;
    END
  END gpio_dm1[20]
  PIN gpio_dm1[21]
    DIRECTION OUTPUT ;
    USE SIGNAL ;
    PORT
      LAYER met2 ;
        RECT 4329.000 4766.350 4329.280 4768.630 ;
    END
  END gpio_dm1[21]
  PIN gpio_dm1[22]
    DIRECTION OUTPUT ;
    USE SIGNAL ;
    PORT
      LAYER met2 ;
        RECT 4072.000 4766.350 4072.280 4768.630 ;
    END
  END gpio_dm1[22]
  PIN gpio_dm1[23]
    DIRECTION OUTPUT ;
    USE SIGNAL ;
    PORT
      LAYER met2 ;
        RECT 3815.000 4766.350 3815.280 4768.630 ;
    END
  END gpio_dm1[23]
  PIN gpio_dm1[24]
    DIRECTION OUTPUT ;
    USE SIGNAL ;
    PORT
      LAYER met2 ;
        RECT 3490.000 4766.350 3490.280 4768.630 ;
    END
  END gpio_dm1[24]
  PIN gpio_dm1[25]
    DIRECTION OUTPUT ;
    USE SIGNAL ;
    PORT
      LAYER met2 ;
        RECT 3233.000 4766.350 3233.280 4768.630 ;
    END
  END gpio_dm1[25]
  PIN gpio_dm1[26]
    DIRECTION OUTPUT ;
    USE SIGNAL ;
    PORT
      LAYER met2 ;
        RECT 2976.000 4766.350 2976.280 4768.630 ;
    END
  END gpio_dm1[26]
  PIN gpio_dm1[27]
    DIRECTION OUTPUT ;
    USE SIGNAL ;
    PORT
      LAYER met2 ;
        RECT 2467.000 4766.350 2467.280 4768.630 ;
    END
  END gpio_dm1[27]
  PIN gpio_dm1[28]
    DIRECTION OUTPUT ;
    USE SIGNAL ;
    PORT
      LAYER met2 ;
        RECT 2210.000 4766.350 2210.280 4768.630 ;
    END
  END gpio_dm1[28]
  PIN gpio_dm1[29]
    DIRECTION OUTPUT ;
    USE SIGNAL ;
    PORT
      LAYER met2 ;
        RECT 1765.000 4766.350 1765.280 4768.630 ;
    END
  END gpio_dm1[29]
  PIN gpio_dm1[2]
    DIRECTION OUTPUT ;
    USE SIGNAL ;
    PORT
      LAYER met3 ;
        RECT 6754.330 763.320 6756.630 763.670 ;
    END
  END gpio_dm1[2]
  PIN gpio_dm1[30]
    DIRECTION OUTPUT ;
    USE SIGNAL ;
    PORT
      LAYER met2 ;
        RECT 1256.000 4766.350 1256.280 4768.630 ;
    END
  END gpio_dm1[30]
  PIN gpio_dm1[31]
    DIRECTION OUTPUT ;
    USE SIGNAL ;
    PORT
      LAYER met2 ;
        RECT 998.000 4766.350 998.280 4768.630 ;
    END
  END gpio_dm1[31]
  PIN gpio_dm1[32]
    DIRECTION OUTPUT ;
    USE SIGNAL ;
    PORT
      LAYER met2 ;
        RECT 741.000 4766.350 741.280 4768.630 ;
    END
  END gpio_dm1[32]
  PIN gpio_dm1[33]
    DIRECTION OUTPUT ;
    USE SIGNAL ;
    PORT
      LAYER met2 ;
        RECT 484.000 4766.350 484.280 4768.630 ;
    END
  END gpio_dm1[33]
  PIN gpio_dm1[34]
    DIRECTION OUTPUT ;
    USE SIGNAL ;
    PORT
      LAYER met2 ;
        RECT 227.000 4766.350 227.280 4768.630 ;
    END
  END gpio_dm1[34]
  PIN gpio_dm1[35]
    DIRECTION OUTPUT ;
    USE SIGNAL ;
    PORT
      LAYER met3 ;
        RECT -2.000 4616.960 0.300 4617.310 ;
    END
  END gpio_dm1[35]
  PIN gpio_dm1[36]
    DIRECTION OUTPUT ;
    USE SIGNAL ;
    PORT
      LAYER met3 ;
        RECT -2.000 3767.960 0.300 3768.310 ;
    END
  END gpio_dm1[36]
  PIN gpio_dm1[37]
    DIRECTION OUTPUT ;
    USE SIGNAL ;
    PORT
      LAYER met3 ;
        RECT -2.000 3551.960 0.300 3552.310 ;
    END
  END gpio_dm1[37]
  PIN gpio_dm1[38]
    DIRECTION OUTPUT ;
    USE SIGNAL ;
    PORT
      LAYER met3 ;
        RECT -2.000 3335.960 0.300 3336.310 ;
    END
  END gpio_dm1[38]
  PIN gpio_dm1[39]
    DIRECTION OUTPUT ;
    USE SIGNAL ;
    PORT
      LAYER met3 ;
        RECT -2.000 3119.960 0.300 3120.310 ;
    END
  END gpio_dm1[39]
  PIN gpio_dm1[3]
    DIRECTION OUTPUT ;
    USE SIGNAL ;
    PORT
      LAYER met3 ;
        RECT 6754.330 989.320 6756.630 989.670 ;
    END
  END gpio_dm1[3]
  PIN gpio_dm1[40]
    DIRECTION OUTPUT ;
    USE SIGNAL ;
    PORT
      LAYER met3 ;
        RECT -2.000 2903.960 0.300 2904.310 ;
    END
  END gpio_dm1[40]
  PIN gpio_dm1[41]
    DIRECTION OUTPUT ;
    USE SIGNAL ;
    PORT
      LAYER met3 ;
        RECT -2.000 2687.960 0.300 2688.310 ;
    END
  END gpio_dm1[41]
  PIN gpio_dm1[42]
    DIRECTION OUTPUT ;
    USE SIGNAL ;
    PORT
      LAYER met3 ;
        RECT -2.000 2471.960 0.300 2472.310 ;
    END
  END gpio_dm1[42]
  PIN gpio_dm1[43]
    DIRECTION OUTPUT ;
    USE SIGNAL ;
    PORT
      LAYER met3 ;
        RECT -2.000 1833.960 0.300 1834.310 ;
    END
  END gpio_dm1[43]
  PIN gpio_dm1[44]
    DIRECTION OUTPUT ;
    USE SIGNAL ;
    PORT
      LAYER met3 ;
        RECT -2.000 1617.960 0.300 1618.310 ;
    END
  END gpio_dm1[44]
  PIN gpio_dm1[45]
    DIRECTION OUTPUT ;
    USE SIGNAL ;
    PORT
      LAYER met3 ;
        RECT -2.000 1401.960 0.300 1402.310 ;
    END
  END gpio_dm1[45]
  PIN gpio_dm1[46]
    DIRECTION OUTPUT ;
    USE SIGNAL ;
    PORT
      LAYER met3 ;
        RECT -2.000 1185.960 0.300 1186.310 ;
    END
  END gpio_dm1[46]
  PIN gpio_dm1[47]
    DIRECTION OUTPUT ;
    USE SIGNAL ;
    PORT
      LAYER met3 ;
        RECT -2.000 969.960 0.300 970.310 ;
    END
  END gpio_dm1[47]
  PIN gpio_dm1[48]
    DIRECTION OUTPUT ;
    USE SIGNAL ;
    PORT
      LAYER met3 ;
        RECT -2.000 753.960 0.300 754.310 ;
    END
  END gpio_dm1[48]
  PIN gpio_dm1[49]
    DIRECTION OUTPUT ;
    USE SIGNAL ;
    PORT
      LAYER met2 ;
        RECT 744.350 -2.000 744.630 0.280 ;
    END
  END gpio_dm1[49]
  PIN gpio_dm1[4]
    DIRECTION OUTPUT ;
    USE SIGNAL ;
    PORT
      LAYER met3 ;
        RECT 6754.330 1214.320 6756.630 1214.670 ;
    END
  END gpio_dm1[4]
  PIN gpio_dm1[50]
    DIRECTION OUTPUT ;
    USE SIGNAL ;
    PORT
      LAYER met2 ;
        RECT 1287.350 -2.000 1287.630 0.280 ;
    END
  END gpio_dm1[50]
  PIN gpio_dm1[51]
    DIRECTION OUTPUT ;
    USE SIGNAL ;
    PORT
      LAYER met2 ;
        RECT 1561.350 -2.000 1561.630 0.280 ;
    END
  END gpio_dm1[51]
  PIN gpio_dm1[52]
    DIRECTION OUTPUT ;
    USE SIGNAL ;
    PORT
      LAYER met2 ;
        RECT 1835.350 -2.000 1835.630 0.280 ;
    END
  END gpio_dm1[52]
  PIN gpio_dm1[53]
    DIRECTION OUTPUT ;
    USE SIGNAL ;
    PORT
      LAYER met2 ;
        RECT 2109.350 -2.000 2109.630 0.280 ;
    END
  END gpio_dm1[53]
  PIN gpio_dm1[54]
    DIRECTION OUTPUT ;
    USE SIGNAL ;
    PORT
      LAYER met2 ;
        RECT 2383.350 -2.000 2383.630 0.280 ;
    END
  END gpio_dm1[54]
  PIN gpio_dm1[55]
    DIRECTION OUTPUT ;
    USE SIGNAL ;
    PORT
      LAYER met2 ;
        RECT 3197.830 -2.000 3198.110 0.280 ;
    END
  END gpio_dm1[55]
  PIN gpio_dm1[56]
    DIRECTION OUTPUT ;
    USE SIGNAL ;
    PORT
      LAYER met2 ;
        RECT 3471.830 -2.000 3472.110 0.280 ;
    END
  END gpio_dm1[56]
  PIN gpio_dm1[57]
    DIRECTION OUTPUT ;
    USE SIGNAL ;
    PORT
      LAYER met2 ;
        RECT 4332.350 -2.000 4332.630 0.280 ;
    END
  END gpio_dm1[57]
  PIN gpio_dm1[58]
    DIRECTION OUTPUT ;
    USE SIGNAL ;
    PORT
      LAYER met2 ;
        RECT 4875.350 -2.000 4875.630 0.280 ;
    END
  END gpio_dm1[58]
  PIN gpio_dm1[59]
    DIRECTION OUTPUT ;
    USE SIGNAL ;
    PORT
      LAYER met2 ;
        RECT 5149.350 -2.000 5149.630 0.280 ;
    END
  END gpio_dm1[59]
  PIN gpio_dm1[5]
    DIRECTION OUTPUT ;
    USE SIGNAL ;
    PORT
      LAYER met3 ;
        RECT 6754.330 1439.320 6756.630 1439.670 ;
    END
  END gpio_dm1[5]
  PIN gpio_dm1[60]
    DIRECTION OUTPUT ;
    USE SIGNAL ;
    PORT
      LAYER met2 ;
        RECT 5423.350 -2.000 5423.630 0.280 ;
    END
  END gpio_dm1[60]
  PIN gpio_dm1[61]
    DIRECTION OUTPUT ;
    USE SIGNAL ;
    PORT
      LAYER met2 ;
        RECT 5697.350 -2.000 5697.630 0.280 ;
    END
  END gpio_dm1[61]
  PIN gpio_dm1[62]
    DIRECTION OUTPUT ;
    USE SIGNAL ;
    PORT
      LAYER met2 ;
        RECT 5971.350 -2.000 5971.630 0.280 ;
    END
  END gpio_dm1[62]
  PIN gpio_dm1[6]
    DIRECTION OUTPUT ;
    USE SIGNAL ;
    PORT
      LAYER met3 ;
        RECT 6754.330 1665.320 6756.630 1665.670 ;
    END
  END gpio_dm1[6]
  PIN gpio_dm1[7]
    DIRECTION OUTPUT ;
    USE SIGNAL ;
    PORT
      LAYER met3 ;
        RECT 6754.330 2551.320 6756.630 2551.670 ;
    END
  END gpio_dm1[7]
  PIN gpio_dm1[8]
    DIRECTION OUTPUT ;
    USE SIGNAL ;
    PORT
      LAYER met3 ;
        RECT 6754.330 2777.320 6756.630 2777.670 ;
    END
  END gpio_dm1[8]
  PIN gpio_dm1[9]
    DIRECTION OUTPUT ;
    USE SIGNAL ;
    PORT
      LAYER met3 ;
        RECT 6754.330 3002.320 6756.630 3002.670 ;
    END
  END gpio_dm1[9]
  PIN gpio_dm2[0]
    DIRECTION OUTPUT ;
    USE SIGNAL ;
    PORT
      LAYER met3 ;
        RECT 6754.330 343.140 6756.630 343.490 ;
    END
  END gpio_dm2[0]
  PIN gpio_dm2[10]
    DIRECTION OUTPUT ;
    USE SIGNAL ;
    PORT
      LAYER met3 ;
        RECT 6754.330 3259.140 6756.630 3259.490 ;
    END
  END gpio_dm2[10]
  PIN gpio_dm2[11]
    DIRECTION OUTPUT ;
    USE SIGNAL ;
    PORT
      LAYER met3 ;
        RECT 6754.330 3484.140 6756.630 3484.490 ;
    END
  END gpio_dm2[11]
  PIN gpio_dm2[12]
    DIRECTION OUTPUT ;
    USE SIGNAL ;
    PORT
      LAYER met3 ;
        RECT 6754.330 3709.140 6756.630 3709.490 ;
    END
  END gpio_dm2[12]
  PIN gpio_dm2[13]
    DIRECTION OUTPUT ;
    USE SIGNAL ;
    PORT
      LAYER met3 ;
        RECT 6754.330 4155.140 6756.630 4155.490 ;
    END
  END gpio_dm2[13]
  PIN gpio_dm2[14]
    DIRECTION OUTPUT ;
    USE SIGNAL ;
    PORT
      LAYER met3 ;
        RECT 6754.330 4601.140 6756.630 4601.490 ;
    END
  END gpio_dm2[14]
  PIN gpio_dm2[15]
    DIRECTION OUTPUT ;
    USE SIGNAL ;
    PORT
      LAYER met2 ;
        RECT 6533.180 4766.350 6533.460 4768.630 ;
    END
  END gpio_dm2[15]
  PIN gpio_dm2[16]
    DIRECTION OUTPUT ;
    USE SIGNAL ;
    PORT
      LAYER met2 ;
        RECT 6024.180 4766.350 6024.460 4768.630 ;
    END
  END gpio_dm2[16]
  PIN gpio_dm2[17]
    DIRECTION OUTPUT ;
    USE SIGNAL ;
    PORT
      LAYER met2 ;
        RECT 5767.180 4766.350 5767.460 4768.630 ;
    END
  END gpio_dm2[17]
  PIN gpio_dm2[18]
    DIRECTION OUTPUT ;
    USE SIGNAL ;
    PORT
      LAYER met2 ;
        RECT 5322.180 4766.350 5322.460 4768.630 ;
    END
  END gpio_dm2[18]
  PIN gpio_dm2[19]
    DIRECTION OUTPUT ;
    USE SIGNAL ;
    PORT
      LAYER met2 ;
        RECT 4813.180 4766.350 4813.460 4768.630 ;
    END
  END gpio_dm2[19]
  PIN gpio_dm2[1]
    DIRECTION OUTPUT ;
    USE SIGNAL ;
    PORT
      LAYER met3 ;
        RECT 6754.330 569.140 6756.630 569.490 ;
    END
  END gpio_dm2[1]
  PIN gpio_dm2[20]
    DIRECTION OUTPUT ;
    USE SIGNAL ;
    PORT
      LAYER met2 ;
        RECT 4555.180 4766.350 4555.460 4768.630 ;
    END
  END gpio_dm2[20]
  PIN gpio_dm2[21]
    DIRECTION OUTPUT ;
    USE SIGNAL ;
    PORT
      LAYER met2 ;
        RECT 4298.180 4766.350 4298.460 4768.630 ;
    END
  END gpio_dm2[21]
  PIN gpio_dm2[22]
    DIRECTION OUTPUT ;
    USE SIGNAL ;
    PORT
      LAYER met2 ;
        RECT 4041.180 4766.350 4041.460 4768.630 ;
    END
  END gpio_dm2[22]
  PIN gpio_dm2[23]
    DIRECTION OUTPUT ;
    USE SIGNAL ;
    PORT
      LAYER met2 ;
        RECT 3784.180 4766.350 3784.460 4768.630 ;
    END
  END gpio_dm2[23]
  PIN gpio_dm2[24]
    DIRECTION OUTPUT ;
    USE SIGNAL ;
    PORT
      LAYER met2 ;
        RECT 3459.180 4766.350 3459.460 4768.630 ;
    END
  END gpio_dm2[24]
  PIN gpio_dm2[25]
    DIRECTION OUTPUT ;
    USE SIGNAL ;
    PORT
      LAYER met2 ;
        RECT 3202.180 4766.350 3202.460 4768.630 ;
    END
  END gpio_dm2[25]
  PIN gpio_dm2[26]
    DIRECTION OUTPUT ;
    USE SIGNAL ;
    PORT
      LAYER met2 ;
        RECT 2945.180 4766.350 2945.460 4768.630 ;
    END
  END gpio_dm2[26]
  PIN gpio_dm2[27]
    DIRECTION OUTPUT ;
    USE SIGNAL ;
    PORT
      LAYER met2 ;
        RECT 2436.180 4766.350 2436.460 4768.630 ;
    END
  END gpio_dm2[27]
  PIN gpio_dm2[28]
    DIRECTION OUTPUT ;
    USE SIGNAL ;
    PORT
      LAYER met2 ;
        RECT 2179.180 4766.350 2179.460 4768.630 ;
    END
  END gpio_dm2[28]
  PIN gpio_dm2[29]
    DIRECTION OUTPUT ;
    USE SIGNAL ;
    PORT
      LAYER met2 ;
        RECT 1734.180 4766.350 1734.460 4768.630 ;
    END
  END gpio_dm2[29]
  PIN gpio_dm2[2]
    DIRECTION OUTPUT ;
    USE SIGNAL ;
    PORT
      LAYER met3 ;
        RECT 6754.330 794.140 6756.630 794.490 ;
    END
  END gpio_dm2[2]
  PIN gpio_dm2[30]
    DIRECTION OUTPUT ;
    USE SIGNAL ;
    PORT
      LAYER met2 ;
        RECT 1225.180 4766.350 1225.460 4768.630 ;
    END
  END gpio_dm2[30]
  PIN gpio_dm2[31]
    DIRECTION OUTPUT ;
    USE SIGNAL ;
    PORT
      LAYER met2 ;
        RECT 967.180 4766.350 967.460 4768.630 ;
    END
  END gpio_dm2[31]
  PIN gpio_dm2[32]
    DIRECTION OUTPUT ;
    USE SIGNAL ;
    PORT
      LAYER met2 ;
        RECT 710.180 4766.350 710.460 4768.630 ;
    END
  END gpio_dm2[32]
  PIN gpio_dm2[33]
    DIRECTION OUTPUT ;
    USE SIGNAL ;
    PORT
      LAYER met2 ;
        RECT 453.180 4766.350 453.460 4768.630 ;
    END
  END gpio_dm2[33]
  PIN gpio_dm2[34]
    DIRECTION OUTPUT ;
    USE SIGNAL ;
    PORT
      LAYER met2 ;
        RECT 196.180 4766.350 196.460 4768.630 ;
    END
  END gpio_dm2[34]
  PIN gpio_dm2[35]
    DIRECTION OUTPUT ;
    USE SIGNAL ;
    PORT
      LAYER met3 ;
        RECT -2.000 4586.140 0.300 4586.490 ;
    END
  END gpio_dm2[35]
  PIN gpio_dm2[36]
    DIRECTION OUTPUT ;
    USE SIGNAL ;
    PORT
      LAYER met3 ;
        RECT -2.000 3737.140 0.300 3737.490 ;
    END
  END gpio_dm2[36]
  PIN gpio_dm2[37]
    DIRECTION OUTPUT ;
    USE SIGNAL ;
    PORT
      LAYER met3 ;
        RECT -2.000 3521.140 0.300 3521.490 ;
    END
  END gpio_dm2[37]
  PIN gpio_dm2[38]
    DIRECTION OUTPUT ;
    USE SIGNAL ;
    PORT
      LAYER met3 ;
        RECT -2.000 3305.140 0.300 3305.490 ;
    END
  END gpio_dm2[38]
  PIN gpio_dm2[39]
    DIRECTION OUTPUT ;
    USE SIGNAL ;
    PORT
      LAYER met3 ;
        RECT -2.000 3089.140 0.300 3089.490 ;
    END
  END gpio_dm2[39]
  PIN gpio_dm2[3]
    DIRECTION OUTPUT ;
    USE SIGNAL ;
    PORT
      LAYER met3 ;
        RECT 6754.330 1020.140 6756.630 1020.490 ;
    END
  END gpio_dm2[3]
  PIN gpio_dm2[40]
    DIRECTION OUTPUT ;
    USE SIGNAL ;
    PORT
      LAYER met3 ;
        RECT -2.000 2873.140 0.300 2873.490 ;
    END
  END gpio_dm2[40]
  PIN gpio_dm2[41]
    DIRECTION OUTPUT ;
    USE SIGNAL ;
    PORT
      LAYER met3 ;
        RECT -2.000 2657.140 0.300 2657.490 ;
    END
  END gpio_dm2[41]
  PIN gpio_dm2[42]
    DIRECTION OUTPUT ;
    USE SIGNAL ;
    PORT
      LAYER met3 ;
        RECT -2.000 2441.140 0.300 2441.490 ;
    END
  END gpio_dm2[42]
  PIN gpio_dm2[43]
    DIRECTION OUTPUT ;
    USE SIGNAL ;
    PORT
      LAYER met3 ;
        RECT -2.000 1803.140 0.300 1803.490 ;
    END
  END gpio_dm2[43]
  PIN gpio_dm2[44]
    DIRECTION OUTPUT ;
    USE SIGNAL ;
    PORT
      LAYER met3 ;
        RECT -2.000 1587.140 0.300 1587.490 ;
    END
  END gpio_dm2[44]
  PIN gpio_dm2[45]
    DIRECTION OUTPUT ;
    USE SIGNAL ;
    PORT
      LAYER met3 ;
        RECT -2.000 1371.140 0.300 1371.490 ;
    END
  END gpio_dm2[45]
  PIN gpio_dm2[46]
    DIRECTION OUTPUT ;
    USE SIGNAL ;
    PORT
      LAYER met3 ;
        RECT -2.000 1155.140 0.300 1155.490 ;
    END
  END gpio_dm2[46]
  PIN gpio_dm2[47]
    DIRECTION OUTPUT ;
    USE SIGNAL ;
    PORT
      LAYER met3 ;
        RECT -2.000 939.140 0.300 939.490 ;
    END
  END gpio_dm2[47]
  PIN gpio_dm2[48]
    DIRECTION OUTPUT ;
    USE SIGNAL ;
    PORT
      LAYER met3 ;
        RECT -2.000 723.140 0.300 723.490 ;
    END
  END gpio_dm2[48]
  PIN gpio_dm2[49]
    DIRECTION OUTPUT ;
    USE SIGNAL ;
    PORT
      LAYER met2 ;
        RECT 775.170 -2.000 775.450 0.280 ;
    END
  END gpio_dm2[49]
  PIN gpio_dm2[4]
    DIRECTION OUTPUT ;
    USE SIGNAL ;
    PORT
      LAYER met3 ;
        RECT 6754.330 1245.140 6756.630 1245.490 ;
    END
  END gpio_dm2[4]
  PIN gpio_dm2[50]
    DIRECTION OUTPUT ;
    USE SIGNAL ;
    PORT
      LAYER met2 ;
        RECT 1318.170 -2.000 1318.450 0.280 ;
    END
  END gpio_dm2[50]
  PIN gpio_dm2[51]
    DIRECTION OUTPUT ;
    USE SIGNAL ;
    PORT
      LAYER met2 ;
        RECT 1592.170 -2.000 1592.450 0.280 ;
    END
  END gpio_dm2[51]
  PIN gpio_dm2[52]
    DIRECTION OUTPUT ;
    USE SIGNAL ;
    PORT
      LAYER met2 ;
        RECT 1866.170 -2.000 1866.450 0.280 ;
    END
  END gpio_dm2[52]
  PIN gpio_dm2[53]
    DIRECTION OUTPUT ;
    USE SIGNAL ;
    PORT
      LAYER met2 ;
        RECT 2140.170 -2.000 2140.450 0.280 ;
    END
  END gpio_dm2[53]
  PIN gpio_dm2[54]
    DIRECTION OUTPUT ;
    USE SIGNAL ;
    PORT
      LAYER met2 ;
        RECT 2414.170 -2.000 2414.450 0.280 ;
    END
  END gpio_dm2[54]
  PIN gpio_dm2[55]
    DIRECTION OUTPUT ;
    USE SIGNAL ;
    PORT
      LAYER met2 ;
        RECT 3228.650 -2.000 3228.930 0.280 ;
    END
  END gpio_dm2[55]
  PIN gpio_dm2[56]
    DIRECTION OUTPUT ;
    USE SIGNAL ;
    PORT
      LAYER met2 ;
        RECT 3502.650 -2.000 3502.930 0.280 ;
    END
  END gpio_dm2[56]
  PIN gpio_dm2[57]
    DIRECTION OUTPUT ;
    USE SIGNAL ;
    PORT
      LAYER met2 ;
        RECT 4363.170 -2.000 4363.450 0.280 ;
    END
  END gpio_dm2[57]
  PIN gpio_dm2[58]
    DIRECTION OUTPUT ;
    USE SIGNAL ;
    PORT
      LAYER met2 ;
        RECT 4906.170 -2.000 4906.450 0.280 ;
    END
  END gpio_dm2[58]
  PIN gpio_dm2[59]
    DIRECTION OUTPUT ;
    USE SIGNAL ;
    PORT
      LAYER met2 ;
        RECT 5180.170 -2.000 5180.450 0.280 ;
    END
  END gpio_dm2[59]
  PIN gpio_dm2[5]
    DIRECTION OUTPUT ;
    USE SIGNAL ;
    PORT
      LAYER met3 ;
        RECT 6754.330 1470.140 6756.630 1470.490 ;
    END
  END gpio_dm2[5]
  PIN gpio_dm2[60]
    DIRECTION OUTPUT ;
    USE SIGNAL ;
    PORT
      LAYER met2 ;
        RECT 5454.170 -2.000 5454.450 0.280 ;
    END
  END gpio_dm2[60]
  PIN gpio_dm2[61]
    DIRECTION OUTPUT ;
    USE SIGNAL ;
    PORT
      LAYER met2 ;
        RECT 5728.170 -2.000 5728.450 0.280 ;
    END
  END gpio_dm2[61]
  PIN gpio_dm2[62]
    DIRECTION OUTPUT ;
    USE SIGNAL ;
    PORT
      LAYER met2 ;
        RECT 6002.170 -2.000 6002.450 0.280 ;
    END
  END gpio_dm2[62]
  PIN gpio_dm2[6]
    DIRECTION OUTPUT ;
    USE SIGNAL ;
    PORT
      LAYER met3 ;
        RECT 6754.330 1696.140 6756.630 1696.490 ;
    END
  END gpio_dm2[6]
  PIN gpio_dm2[7]
    DIRECTION OUTPUT ;
    USE SIGNAL ;
    PORT
      LAYER met3 ;
        RECT 6754.330 2582.140 6756.630 2582.490 ;
    END
  END gpio_dm2[7]
  PIN gpio_dm2[8]
    DIRECTION OUTPUT ;
    USE SIGNAL ;
    PORT
      LAYER met3 ;
        RECT 6754.330 2808.140 6756.630 2808.490 ;
    END
  END gpio_dm2[8]
  PIN gpio_dm2[9]
    DIRECTION OUTPUT ;
    USE SIGNAL ;
    PORT
      LAYER met3 ;
        RECT 6754.330 3033.140 6756.630 3033.490 ;
    END
  END gpio_dm2[9]
  PIN gpio_holdover[0]
    DIRECTION OUTPUT ;
    USE SIGNAL ;
    PORT
      LAYER met3 ;
        RECT 6754.330 346.360 6756.630 346.710 ;
    END
  END gpio_holdover[0]
  PIN gpio_holdover[10]
    DIRECTION OUTPUT ;
    USE SIGNAL ;
    PORT
      LAYER met3 ;
        RECT 6754.330 3262.360 6756.630 3262.710 ;
    END
  END gpio_holdover[10]
  PIN gpio_holdover[11]
    DIRECTION OUTPUT ;
    USE SIGNAL ;
    PORT
      LAYER met3 ;
        RECT 6754.330 3487.360 6756.630 3487.710 ;
    END
  END gpio_holdover[11]
  PIN gpio_holdover[12]
    DIRECTION OUTPUT ;
    USE SIGNAL ;
    PORT
      LAYER met3 ;
        RECT 6754.330 3712.360 6756.630 3712.710 ;
    END
  END gpio_holdover[12]
  PIN gpio_holdover[13]
    DIRECTION OUTPUT ;
    USE SIGNAL ;
    PORT
      LAYER met3 ;
        RECT 6754.330 4158.360 6756.630 4158.710 ;
    END
  END gpio_holdover[13]
  PIN gpio_holdover[14]
    DIRECTION OUTPUT ;
    USE SIGNAL ;
    PORT
      LAYER met3 ;
        RECT 6754.330 4604.360 6756.630 4604.710 ;
    END
  END gpio_holdover[14]
  PIN gpio_holdover[15]
    DIRECTION OUTPUT ;
    USE SIGNAL ;
    PORT
      LAYER met2 ;
        RECT 6529.960 4766.350 6530.240 4768.630 ;
    END
  END gpio_holdover[15]
  PIN gpio_holdover[16]
    DIRECTION OUTPUT ;
    USE SIGNAL ;
    PORT
      LAYER met2 ;
        RECT 6020.960 4766.350 6021.240 4768.630 ;
    END
  END gpio_holdover[16]
  PIN gpio_holdover[17]
    DIRECTION OUTPUT ;
    USE SIGNAL ;
    PORT
      LAYER met2 ;
        RECT 5763.960 4766.350 5764.240 4768.630 ;
    END
  END gpio_holdover[17]
  PIN gpio_holdover[18]
    DIRECTION OUTPUT ;
    USE SIGNAL ;
    PORT
      LAYER met2 ;
        RECT 5318.960 4766.350 5319.240 4768.630 ;
    END
  END gpio_holdover[18]
  PIN gpio_holdover[19]
    DIRECTION OUTPUT ;
    USE SIGNAL ;
    PORT
      LAYER met2 ;
        RECT 4809.960 4766.350 4810.240 4768.630 ;
    END
  END gpio_holdover[19]
  PIN gpio_holdover[1]
    DIRECTION OUTPUT ;
    USE SIGNAL ;
    PORT
      LAYER met3 ;
        RECT 6754.330 572.360 6756.630 572.710 ;
    END
  END gpio_holdover[1]
  PIN gpio_holdover[20]
    DIRECTION OUTPUT ;
    USE SIGNAL ;
    PORT
      LAYER met2 ;
        RECT 4551.960 4766.350 4552.240 4768.630 ;
    END
  END gpio_holdover[20]
  PIN gpio_holdover[21]
    DIRECTION OUTPUT ;
    USE SIGNAL ;
    PORT
      LAYER met2 ;
        RECT 4294.960 4766.350 4295.240 4768.630 ;
    END
  END gpio_holdover[21]
  PIN gpio_holdover[22]
    DIRECTION OUTPUT ;
    USE SIGNAL ;
    PORT
      LAYER met2 ;
        RECT 4037.960 4766.350 4038.240 4768.630 ;
    END
  END gpio_holdover[22]
  PIN gpio_holdover[23]
    DIRECTION OUTPUT ;
    USE SIGNAL ;
    PORT
      LAYER met2 ;
        RECT 3780.960 4766.350 3781.240 4768.630 ;
    END
  END gpio_holdover[23]
  PIN gpio_holdover[24]
    DIRECTION OUTPUT ;
    USE SIGNAL ;
    PORT
      LAYER met2 ;
        RECT 3455.960 4766.350 3456.240 4768.630 ;
    END
  END gpio_holdover[24]
  PIN gpio_holdover[25]
    DIRECTION OUTPUT ;
    USE SIGNAL ;
    PORT
      LAYER met2 ;
        RECT 3198.960 4766.350 3199.240 4768.630 ;
    END
  END gpio_holdover[25]
  PIN gpio_holdover[26]
    DIRECTION OUTPUT ;
    USE SIGNAL ;
    PORT
      LAYER met2 ;
        RECT 2941.960 4766.350 2942.240 4768.630 ;
    END
  END gpio_holdover[26]
  PIN gpio_holdover[27]
    DIRECTION OUTPUT ;
    USE SIGNAL ;
    PORT
      LAYER met2 ;
        RECT 2432.960 4766.350 2433.240 4768.630 ;
    END
  END gpio_holdover[27]
  PIN gpio_holdover[28]
    DIRECTION OUTPUT ;
    USE SIGNAL ;
    PORT
      LAYER met2 ;
        RECT 2175.960 4766.350 2176.240 4768.630 ;
    END
  END gpio_holdover[28]
  PIN gpio_holdover[29]
    DIRECTION OUTPUT ;
    USE SIGNAL ;
    PORT
      LAYER met2 ;
        RECT 1730.960 4766.350 1731.240 4768.630 ;
    END
  END gpio_holdover[29]
  PIN gpio_holdover[2]
    DIRECTION OUTPUT ;
    USE SIGNAL ;
    PORT
      LAYER met3 ;
        RECT 6754.330 797.360 6756.630 797.710 ;
    END
  END gpio_holdover[2]
  PIN gpio_holdover[30]
    DIRECTION OUTPUT ;
    USE SIGNAL ;
    PORT
      LAYER met2 ;
        RECT 1221.960 4766.350 1222.240 4768.630 ;
    END
  END gpio_holdover[30]
  PIN gpio_holdover[31]
    DIRECTION OUTPUT ;
    USE SIGNAL ;
    PORT
      LAYER met2 ;
        RECT 963.960 4766.350 964.240 4768.630 ;
    END
  END gpio_holdover[31]
  PIN gpio_holdover[32]
    DIRECTION OUTPUT ;
    USE SIGNAL ;
    PORT
      LAYER met2 ;
        RECT 706.960 4766.350 707.240 4768.630 ;
    END
  END gpio_holdover[32]
  PIN gpio_holdover[33]
    DIRECTION OUTPUT ;
    USE SIGNAL ;
    PORT
      LAYER met2 ;
        RECT 449.960 4766.350 450.240 4768.630 ;
    END
  END gpio_holdover[33]
  PIN gpio_holdover[34]
    DIRECTION OUTPUT ;
    USE SIGNAL ;
    PORT
      LAYER met2 ;
        RECT 192.960 4766.350 193.240 4768.630 ;
    END
  END gpio_holdover[34]
  PIN gpio_holdover[35]
    DIRECTION OUTPUT ;
    USE SIGNAL ;
    PORT
      LAYER met3 ;
        RECT -2.000 4582.920 0.300 4583.270 ;
    END
  END gpio_holdover[35]
  PIN gpio_holdover[36]
    DIRECTION OUTPUT ;
    USE SIGNAL ;
    PORT
      LAYER met3 ;
        RECT -2.000 3733.920 0.300 3734.270 ;
    END
  END gpio_holdover[36]
  PIN gpio_holdover[37]
    DIRECTION OUTPUT ;
    USE SIGNAL ;
    PORT
      LAYER met3 ;
        RECT -2.000 3517.920 0.300 3518.270 ;
    END
  END gpio_holdover[37]
  PIN gpio_holdover[38]
    DIRECTION OUTPUT ;
    USE SIGNAL ;
    PORT
      LAYER met3 ;
        RECT -2.000 3301.920 0.300 3302.270 ;
    END
  END gpio_holdover[38]
  PIN gpio_holdover[39]
    DIRECTION OUTPUT ;
    USE SIGNAL ;
    PORT
      LAYER met3 ;
        RECT -2.000 3085.920 0.300 3086.270 ;
    END
  END gpio_holdover[39]
  PIN gpio_holdover[3]
    DIRECTION OUTPUT ;
    USE SIGNAL ;
    PORT
      LAYER met3 ;
        RECT 6754.330 1023.360 6756.630 1023.710 ;
    END
  END gpio_holdover[3]
  PIN gpio_holdover[40]
    DIRECTION OUTPUT ;
    USE SIGNAL ;
    PORT
      LAYER met3 ;
        RECT -2.000 2869.920 0.300 2870.270 ;
    END
  END gpio_holdover[40]
  PIN gpio_holdover[41]
    DIRECTION OUTPUT ;
    USE SIGNAL ;
    PORT
      LAYER met3 ;
        RECT -2.000 2653.920 0.300 2654.270 ;
    END
  END gpio_holdover[41]
  PIN gpio_holdover[42]
    DIRECTION OUTPUT ;
    USE SIGNAL ;
    PORT
      LAYER met3 ;
        RECT -2.000 2437.920 0.300 2438.270 ;
    END
  END gpio_holdover[42]
  PIN gpio_holdover[43]
    DIRECTION OUTPUT ;
    USE SIGNAL ;
    PORT
      LAYER met3 ;
        RECT -2.000 1799.920 0.300 1800.270 ;
    END
  END gpio_holdover[43]
  PIN gpio_holdover[44]
    DIRECTION OUTPUT ;
    USE SIGNAL ;
    PORT
      LAYER met3 ;
        RECT -2.000 1583.920 0.300 1584.270 ;
    END
  END gpio_holdover[44]
  PIN gpio_holdover[45]
    DIRECTION OUTPUT ;
    USE SIGNAL ;
    PORT
      LAYER met3 ;
        RECT -2.000 1367.920 0.300 1368.270 ;
    END
  END gpio_holdover[45]
  PIN gpio_holdover[46]
    DIRECTION OUTPUT ;
    USE SIGNAL ;
    PORT
      LAYER met3 ;
        RECT -2.000 1151.920 0.300 1152.270 ;
    END
  END gpio_holdover[46]
  PIN gpio_holdover[47]
    DIRECTION OUTPUT ;
    USE SIGNAL ;
    PORT
      LAYER met3 ;
        RECT -2.000 935.920 0.300 936.270 ;
    END
  END gpio_holdover[47]
  PIN gpio_holdover[48]
    DIRECTION OUTPUT ;
    USE SIGNAL ;
    PORT
      LAYER met3 ;
        RECT -2.000 719.920 0.300 720.270 ;
    END
  END gpio_holdover[48]
  PIN gpio_holdover[49]
    DIRECTION OUTPUT ;
    USE SIGNAL ;
    PORT
      LAYER met2 ;
        RECT 778.390 -2.000 778.670 0.280 ;
    END
  END gpio_holdover[49]
  PIN gpio_holdover[4]
    DIRECTION OUTPUT ;
    USE SIGNAL ;
    PORT
      LAYER met3 ;
        RECT 6754.330 1248.360 6756.630 1248.710 ;
    END
  END gpio_holdover[4]
  PIN gpio_holdover[50]
    DIRECTION OUTPUT ;
    USE SIGNAL ;
    PORT
      LAYER met2 ;
        RECT 1321.390 -2.000 1321.670 0.280 ;
    END
  END gpio_holdover[50]
  PIN gpio_holdover[51]
    DIRECTION OUTPUT ;
    USE SIGNAL ;
    PORT
      LAYER met2 ;
        RECT 1595.390 -2.000 1595.670 0.280 ;
    END
  END gpio_holdover[51]
  PIN gpio_holdover[52]
    DIRECTION OUTPUT ;
    USE SIGNAL ;
    PORT
      LAYER met2 ;
        RECT 1869.390 -2.000 1869.670 0.280 ;
    END
  END gpio_holdover[52]
  PIN gpio_holdover[53]
    DIRECTION OUTPUT ;
    USE SIGNAL ;
    PORT
      LAYER met2 ;
        RECT 2143.390 -2.000 2143.670 0.280 ;
    END
  END gpio_holdover[53]
  PIN gpio_holdover[54]
    DIRECTION OUTPUT ;
    USE SIGNAL ;
    PORT
      LAYER met2 ;
        RECT 2417.390 -2.000 2417.670 0.280 ;
    END
  END gpio_holdover[54]
  PIN gpio_holdover[55]
    DIRECTION OUTPUT ;
    USE SIGNAL ;
    PORT
      LAYER met2 ;
        RECT 3231.870 -2.000 3232.150 0.280 ;
    END
  END gpio_holdover[55]
  PIN gpio_holdover[56]
    DIRECTION OUTPUT ;
    USE SIGNAL ;
    PORT
      LAYER met2 ;
        RECT 3505.870 -2.000 3506.150 0.280 ;
    END
  END gpio_holdover[56]
  PIN gpio_holdover[57]
    DIRECTION OUTPUT ;
    USE SIGNAL ;
    PORT
      LAYER met2 ;
        RECT 4366.390 -2.000 4366.670 0.280 ;
    END
  END gpio_holdover[57]
  PIN gpio_holdover[58]
    DIRECTION OUTPUT ;
    USE SIGNAL ;
    PORT
      LAYER met2 ;
        RECT 4909.390 -2.000 4909.670 0.280 ;
    END
  END gpio_holdover[58]
  PIN gpio_holdover[59]
    DIRECTION OUTPUT ;
    USE SIGNAL ;
    PORT
      LAYER met2 ;
        RECT 5183.390 -2.000 5183.670 0.280 ;
    END
  END gpio_holdover[59]
  PIN gpio_holdover[5]
    DIRECTION OUTPUT ;
    USE SIGNAL ;
    PORT
      LAYER met3 ;
        RECT 6754.330 1473.360 6756.630 1473.710 ;
    END
  END gpio_holdover[5]
  PIN gpio_holdover[60]
    DIRECTION OUTPUT ;
    USE SIGNAL ;
    PORT
      LAYER met2 ;
        RECT 5457.390 -2.000 5457.670 0.280 ;
    END
  END gpio_holdover[60]
  PIN gpio_holdover[61]
    DIRECTION OUTPUT ;
    USE SIGNAL ;
    PORT
      LAYER met2 ;
        RECT 5731.390 -2.000 5731.670 0.280 ;
    END
  END gpio_holdover[61]
  PIN gpio_holdover[62]
    DIRECTION OUTPUT ;
    USE SIGNAL ;
    PORT
      LAYER met2 ;
        RECT 6005.390 -2.000 6005.670 0.280 ;
    END
  END gpio_holdover[62]
  PIN gpio_holdover[6]
    DIRECTION OUTPUT ;
    USE SIGNAL ;
    PORT
      LAYER met3 ;
        RECT 6754.330 1699.360 6756.630 1699.710 ;
    END
  END gpio_holdover[6]
  PIN gpio_holdover[7]
    DIRECTION OUTPUT ;
    USE SIGNAL ;
    PORT
      LAYER met3 ;
        RECT 6754.330 2585.360 6756.630 2585.710 ;
    END
  END gpio_holdover[7]
  PIN gpio_holdover[8]
    DIRECTION OUTPUT ;
    USE SIGNAL ;
    PORT
      LAYER met3 ;
        RECT 6754.330 2811.360 6756.630 2811.710 ;
    END
  END gpio_holdover[8]
  PIN gpio_holdover[9]
    DIRECTION OUTPUT ;
    USE SIGNAL ;
    PORT
      LAYER met3 ;
        RECT 6754.330 3036.360 6756.630 3036.710 ;
    END
  END gpio_holdover[9]
  PIN gpio_ib_mode_sel[0]
    DIRECTION OUTPUT ;
    USE SIGNAL ;
    PORT
      LAYER met3 ;
        RECT 6754.330 361.540 6756.630 361.890 ;
    END
  END gpio_ib_mode_sel[0]
  PIN gpio_ib_mode_sel[10]
    DIRECTION OUTPUT ;
    USE SIGNAL ;
    PORT
      LAYER met3 ;
        RECT 6754.330 3277.540 6756.630 3277.890 ;
    END
  END gpio_ib_mode_sel[10]
  PIN gpio_ib_mode_sel[11]
    DIRECTION OUTPUT ;
    USE SIGNAL ;
    PORT
      LAYER met3 ;
        RECT 6754.330 3502.540 6756.630 3502.890 ;
    END
  END gpio_ib_mode_sel[11]
  PIN gpio_ib_mode_sel[12]
    DIRECTION OUTPUT ;
    USE SIGNAL ;
    PORT
      LAYER met3 ;
        RECT 6754.330 3727.540 6756.630 3727.890 ;
    END
  END gpio_ib_mode_sel[12]
  PIN gpio_ib_mode_sel[13]
    DIRECTION OUTPUT ;
    USE SIGNAL ;
    PORT
      LAYER met3 ;
        RECT 6754.330 4173.540 6756.630 4173.890 ;
    END
  END gpio_ib_mode_sel[13]
  PIN gpio_ib_mode_sel[14]
    DIRECTION OUTPUT ;
    USE SIGNAL ;
    PORT
      LAYER met3 ;
        RECT 6754.330 4619.540 6756.630 4619.890 ;
    END
  END gpio_ib_mode_sel[14]
  PIN gpio_ib_mode_sel[15]
    DIRECTION OUTPUT ;
    USE SIGNAL ;
    PORT
      LAYER met2 ;
        RECT 6514.780 4766.350 6515.060 4768.630 ;
    END
  END gpio_ib_mode_sel[15]
  PIN gpio_ib_mode_sel[16]
    DIRECTION OUTPUT ;
    USE SIGNAL ;
    PORT
      LAYER met2 ;
        RECT 6005.780 4766.350 6006.060 4768.630 ;
    END
  END gpio_ib_mode_sel[16]
  PIN gpio_ib_mode_sel[17]
    DIRECTION OUTPUT ;
    USE SIGNAL ;
    PORT
      LAYER met2 ;
        RECT 5748.780 4766.350 5749.060 4768.630 ;
    END
  END gpio_ib_mode_sel[17]
  PIN gpio_ib_mode_sel[18]
    DIRECTION OUTPUT ;
    USE SIGNAL ;
    PORT
      LAYER met2 ;
        RECT 5303.780 4766.350 5304.060 4768.630 ;
    END
  END gpio_ib_mode_sel[18]
  PIN gpio_ib_mode_sel[19]
    DIRECTION OUTPUT ;
    USE SIGNAL ;
    PORT
      LAYER met2 ;
        RECT 4794.780 4766.350 4795.060 4768.630 ;
    END
  END gpio_ib_mode_sel[19]
  PIN gpio_ib_mode_sel[1]
    DIRECTION OUTPUT ;
    USE SIGNAL ;
    PORT
      LAYER met3 ;
        RECT 6754.330 587.540 6756.630 587.890 ;
    END
  END gpio_ib_mode_sel[1]
  PIN gpio_ib_mode_sel[20]
    DIRECTION OUTPUT ;
    USE SIGNAL ;
    PORT
      LAYER met2 ;
        RECT 4536.780 4766.350 4537.060 4768.630 ;
    END
  END gpio_ib_mode_sel[20]
  PIN gpio_ib_mode_sel[21]
    DIRECTION OUTPUT ;
    USE SIGNAL ;
    PORT
      LAYER met2 ;
        RECT 4279.780 4766.350 4280.060 4768.630 ;
    END
  END gpio_ib_mode_sel[21]
  PIN gpio_ib_mode_sel[22]
    DIRECTION OUTPUT ;
    USE SIGNAL ;
    PORT
      LAYER met2 ;
        RECT 4022.780 4766.350 4023.060 4768.630 ;
    END
  END gpio_ib_mode_sel[22]
  PIN gpio_ib_mode_sel[23]
    DIRECTION OUTPUT ;
    USE SIGNAL ;
    PORT
      LAYER met2 ;
        RECT 3765.780 4766.350 3766.060 4768.630 ;
    END
  END gpio_ib_mode_sel[23]
  PIN gpio_ib_mode_sel[24]
    DIRECTION OUTPUT ;
    USE SIGNAL ;
    PORT
      LAYER met2 ;
        RECT 3440.780 4766.350 3441.060 4768.630 ;
    END
  END gpio_ib_mode_sel[24]
  PIN gpio_ib_mode_sel[25]
    DIRECTION OUTPUT ;
    USE SIGNAL ;
    PORT
      LAYER met2 ;
        RECT 3183.780 4766.350 3184.060 4768.630 ;
    END
  END gpio_ib_mode_sel[25]
  PIN gpio_ib_mode_sel[26]
    DIRECTION OUTPUT ;
    USE SIGNAL ;
    PORT
      LAYER met2 ;
        RECT 2926.780 4766.350 2927.060 4768.630 ;
    END
  END gpio_ib_mode_sel[26]
  PIN gpio_ib_mode_sel[27]
    DIRECTION OUTPUT ;
    USE SIGNAL ;
    PORT
      LAYER met2 ;
        RECT 2417.780 4766.350 2418.060 4768.630 ;
    END
  END gpio_ib_mode_sel[27]
  PIN gpio_ib_mode_sel[28]
    DIRECTION OUTPUT ;
    USE SIGNAL ;
    PORT
      LAYER met2 ;
        RECT 2160.780 4766.350 2161.060 4768.630 ;
    END
  END gpio_ib_mode_sel[28]
  PIN gpio_ib_mode_sel[29]
    DIRECTION OUTPUT ;
    USE SIGNAL ;
    PORT
      LAYER met2 ;
        RECT 1715.780 4766.350 1716.060 4768.630 ;
    END
  END gpio_ib_mode_sel[29]
  PIN gpio_ib_mode_sel[2]
    DIRECTION OUTPUT ;
    USE SIGNAL ;
    PORT
      LAYER met3 ;
        RECT 6754.330 812.540 6756.630 812.890 ;
    END
  END gpio_ib_mode_sel[2]
  PIN gpio_ib_mode_sel[30]
    DIRECTION OUTPUT ;
    USE SIGNAL ;
    PORT
      LAYER met2 ;
        RECT 1206.780 4766.350 1207.060 4768.630 ;
    END
  END gpio_ib_mode_sel[30]
  PIN gpio_ib_mode_sel[31]
    DIRECTION OUTPUT ;
    USE SIGNAL ;
    PORT
      LAYER met2 ;
        RECT 948.780 4766.350 949.060 4768.630 ;
    END
  END gpio_ib_mode_sel[31]
  PIN gpio_ib_mode_sel[32]
    DIRECTION OUTPUT ;
    USE SIGNAL ;
    PORT
      LAYER met2 ;
        RECT 691.780 4766.350 692.060 4768.630 ;
    END
  END gpio_ib_mode_sel[32]
  PIN gpio_ib_mode_sel[33]
    DIRECTION OUTPUT ;
    USE SIGNAL ;
    PORT
      LAYER met2 ;
        RECT 434.780 4766.350 435.060 4768.630 ;
    END
  END gpio_ib_mode_sel[33]
  PIN gpio_ib_mode_sel[34]
    DIRECTION OUTPUT ;
    USE SIGNAL ;
    PORT
      LAYER met2 ;
        RECT 177.780 4766.350 178.060 4768.630 ;
    END
  END gpio_ib_mode_sel[34]
  PIN gpio_ib_mode_sel[35]
    DIRECTION OUTPUT ;
    USE SIGNAL ;
    PORT
      LAYER met3 ;
        RECT -2.000 4567.740 0.300 4568.090 ;
    END
  END gpio_ib_mode_sel[35]
  PIN gpio_ib_mode_sel[36]
    DIRECTION OUTPUT ;
    USE SIGNAL ;
    PORT
      LAYER met3 ;
        RECT -2.000 3718.740 0.300 3719.090 ;
    END
  END gpio_ib_mode_sel[36]
  PIN gpio_ib_mode_sel[37]
    DIRECTION OUTPUT ;
    USE SIGNAL ;
    PORT
      LAYER met3 ;
        RECT -2.000 3502.740 0.300 3503.090 ;
    END
  END gpio_ib_mode_sel[37]
  PIN gpio_ib_mode_sel[38]
    DIRECTION OUTPUT ;
    USE SIGNAL ;
    PORT
      LAYER met3 ;
        RECT -2.000 3286.740 0.300 3287.090 ;
    END
  END gpio_ib_mode_sel[38]
  PIN gpio_ib_mode_sel[39]
    DIRECTION OUTPUT ;
    USE SIGNAL ;
    PORT
      LAYER met3 ;
        RECT -2.000 3070.740 0.300 3071.090 ;
    END
  END gpio_ib_mode_sel[39]
  PIN gpio_ib_mode_sel[3]
    DIRECTION OUTPUT ;
    USE SIGNAL ;
    PORT
      LAYER met3 ;
        RECT 6754.330 1038.540 6756.630 1038.890 ;
    END
  END gpio_ib_mode_sel[3]
  PIN gpio_ib_mode_sel[40]
    DIRECTION OUTPUT ;
    USE SIGNAL ;
    PORT
      LAYER met3 ;
        RECT -2.000 2854.740 0.300 2855.090 ;
    END
  END gpio_ib_mode_sel[40]
  PIN gpio_ib_mode_sel[41]
    DIRECTION OUTPUT ;
    USE SIGNAL ;
    PORT
      LAYER met3 ;
        RECT -2.000 2638.740 0.300 2639.090 ;
    END
  END gpio_ib_mode_sel[41]
  PIN gpio_ib_mode_sel[42]
    DIRECTION OUTPUT ;
    USE SIGNAL ;
    PORT
      LAYER met3 ;
        RECT -2.000 2422.740 0.300 2423.090 ;
    END
  END gpio_ib_mode_sel[42]
  PIN gpio_ib_mode_sel[43]
    DIRECTION OUTPUT ;
    USE SIGNAL ;
    PORT
      LAYER met3 ;
        RECT -2.000 1784.740 0.300 1785.090 ;
    END
  END gpio_ib_mode_sel[43]
  PIN gpio_ib_mode_sel[44]
    DIRECTION OUTPUT ;
    USE SIGNAL ;
    PORT
      LAYER met3 ;
        RECT -2.000 1568.740 0.300 1569.090 ;
    END
  END gpio_ib_mode_sel[44]
  PIN gpio_ib_mode_sel[45]
    DIRECTION OUTPUT ;
    USE SIGNAL ;
    PORT
      LAYER met3 ;
        RECT -2.000 1352.740 0.300 1353.090 ;
    END
  END gpio_ib_mode_sel[45]
  PIN gpio_ib_mode_sel[46]
    DIRECTION OUTPUT ;
    USE SIGNAL ;
    PORT
      LAYER met3 ;
        RECT -2.000 1136.740 0.300 1137.090 ;
    END
  END gpio_ib_mode_sel[46]
  PIN gpio_ib_mode_sel[47]
    DIRECTION OUTPUT ;
    USE SIGNAL ;
    PORT
      LAYER met3 ;
        RECT -2.000 920.740 0.300 921.090 ;
    END
  END gpio_ib_mode_sel[47]
  PIN gpio_ib_mode_sel[48]
    DIRECTION OUTPUT ;
    USE SIGNAL ;
    PORT
      LAYER met3 ;
        RECT -2.000 704.740 0.300 705.090 ;
    END
  END gpio_ib_mode_sel[48]
  PIN gpio_ib_mode_sel[49]
    DIRECTION OUTPUT ;
    USE SIGNAL ;
    PORT
      LAYER met2 ;
        RECT 793.570 -2.000 793.850 0.280 ;
    END
  END gpio_ib_mode_sel[49]
  PIN gpio_ib_mode_sel[4]
    DIRECTION OUTPUT ;
    USE SIGNAL ;
    PORT
      LAYER met3 ;
        RECT 6754.330 1263.540 6756.630 1263.890 ;
    END
  END gpio_ib_mode_sel[4]
  PIN gpio_ib_mode_sel[50]
    DIRECTION OUTPUT ;
    USE SIGNAL ;
    PORT
      LAYER met2 ;
        RECT 1336.570 -2.000 1336.850 0.280 ;
    END
  END gpio_ib_mode_sel[50]
  PIN gpio_ib_mode_sel[51]
    DIRECTION OUTPUT ;
    USE SIGNAL ;
    PORT
      LAYER met2 ;
        RECT 1610.570 -2.000 1610.850 0.280 ;
    END
  END gpio_ib_mode_sel[51]
  PIN gpio_ib_mode_sel[52]
    DIRECTION OUTPUT ;
    USE SIGNAL ;
    PORT
      LAYER met2 ;
        RECT 1884.570 -2.000 1884.850 0.280 ;
    END
  END gpio_ib_mode_sel[52]
  PIN gpio_ib_mode_sel[53]
    DIRECTION OUTPUT ;
    USE SIGNAL ;
    PORT
      LAYER met2 ;
        RECT 2158.570 -2.000 2158.850 0.280 ;
    END
  END gpio_ib_mode_sel[53]
  PIN gpio_ib_mode_sel[54]
    DIRECTION OUTPUT ;
    USE SIGNAL ;
    PORT
      LAYER met2 ;
        RECT 2432.570 -2.000 2432.850 0.280 ;
    END
  END gpio_ib_mode_sel[54]
  PIN gpio_ib_mode_sel[55]
    DIRECTION OUTPUT ;
    USE SIGNAL ;
    PORT
      LAYER met2 ;
        RECT 3247.050 -2.000 3247.330 0.280 ;
    END
  END gpio_ib_mode_sel[55]
  PIN gpio_ib_mode_sel[56]
    DIRECTION OUTPUT ;
    USE SIGNAL ;
    PORT
      LAYER met2 ;
        RECT 3521.050 -2.000 3521.330 0.280 ;
    END
  END gpio_ib_mode_sel[56]
  PIN gpio_ib_mode_sel[57]
    DIRECTION OUTPUT ;
    USE SIGNAL ;
    PORT
      LAYER met2 ;
        RECT 4381.570 -2.000 4381.850 0.280 ;
    END
  END gpio_ib_mode_sel[57]
  PIN gpio_ib_mode_sel[58]
    DIRECTION OUTPUT ;
    USE SIGNAL ;
    PORT
      LAYER met2 ;
        RECT 4924.570 -2.000 4924.850 0.280 ;
    END
  END gpio_ib_mode_sel[58]
  PIN gpio_ib_mode_sel[59]
    DIRECTION OUTPUT ;
    USE SIGNAL ;
    PORT
      LAYER met2 ;
        RECT 5198.570 -2.000 5198.850 0.280 ;
    END
  END gpio_ib_mode_sel[59]
  PIN gpio_ib_mode_sel[5]
    DIRECTION OUTPUT ;
    USE SIGNAL ;
    PORT
      LAYER met3 ;
        RECT 6754.330 1488.540 6756.630 1488.890 ;
    END
  END gpio_ib_mode_sel[5]
  PIN gpio_ib_mode_sel[60]
    DIRECTION OUTPUT ;
    USE SIGNAL ;
    PORT
      LAYER met2 ;
        RECT 5472.570 -2.000 5472.850 0.280 ;
    END
  END gpio_ib_mode_sel[60]
  PIN gpio_ib_mode_sel[61]
    DIRECTION OUTPUT ;
    USE SIGNAL ;
    PORT
      LAYER met2 ;
        RECT 5746.570 -2.000 5746.850 0.280 ;
    END
  END gpio_ib_mode_sel[61]
  PIN gpio_ib_mode_sel[62]
    DIRECTION OUTPUT ;
    USE SIGNAL ;
    PORT
      LAYER met2 ;
        RECT 6020.570 -2.000 6020.850 0.280 ;
    END
  END gpio_ib_mode_sel[62]
  PIN gpio_ib_mode_sel[6]
    DIRECTION OUTPUT ;
    USE SIGNAL ;
    PORT
      LAYER met3 ;
        RECT 6754.330 1714.540 6756.630 1714.890 ;
    END
  END gpio_ib_mode_sel[6]
  PIN gpio_ib_mode_sel[7]
    DIRECTION OUTPUT ;
    USE SIGNAL ;
    PORT
      LAYER met3 ;
        RECT 6754.330 2600.540 6756.630 2600.890 ;
    END
  END gpio_ib_mode_sel[7]
  PIN gpio_ib_mode_sel[8]
    DIRECTION OUTPUT ;
    USE SIGNAL ;
    PORT
      LAYER met3 ;
        RECT 6754.330 2826.540 6756.630 2826.890 ;
    END
  END gpio_ib_mode_sel[8]
  PIN gpio_ib_mode_sel[9]
    DIRECTION OUTPUT ;
    USE SIGNAL ;
    PORT
      LAYER met3 ;
        RECT 6754.330 3051.540 6756.630 3051.890 ;
    END
  END gpio_ib_mode_sel[9]
  PIN gpio_in[0]
    DIRECTION INPUT ;
    USE SIGNAL ;
    PORT
      LAYER met3 ;
        RECT 6754.330 293.920 6756.630 294.270 ;
    END
  END gpio_in[0]
  PIN gpio_in[10]
    DIRECTION INPUT ;
    USE SIGNAL ;
    PORT
      LAYER met3 ;
        RECT 6754.330 3209.920 6756.630 3210.270 ;
    END
  END gpio_in[10]
  PIN gpio_in[11]
    DIRECTION INPUT ;
    USE SIGNAL ;
    PORT
      LAYER met3 ;
        RECT 6754.330 3434.920 6756.630 3435.270 ;
    END
  END gpio_in[11]
  PIN gpio_in[12]
    DIRECTION INPUT ;
    USE SIGNAL ;
    PORT
      LAYER met3 ;
        RECT 6754.330 3659.920 6756.630 3660.270 ;
    END
  END gpio_in[12]
  PIN gpio_in[13]
    DIRECTION INPUT ;
    USE SIGNAL ;
    PORT
      LAYER met3 ;
        RECT 6754.330 4105.920 6756.630 4106.270 ;
    END
  END gpio_in[13]
  PIN gpio_in[14]
    DIRECTION INPUT ;
    USE SIGNAL ;
    PORT
      LAYER met3 ;
        RECT 6754.330 4551.920 6756.630 4552.270 ;
    END
  END gpio_in[14]
  PIN gpio_in[15]
    DIRECTION INPUT ;
    USE SIGNAL ;
    PORT
      LAYER met2 ;
        RECT 6582.400 4766.350 6582.680 4768.630 ;
    END
  END gpio_in[15]
  PIN gpio_in[16]
    DIRECTION INPUT ;
    USE SIGNAL ;
    PORT
      LAYER met2 ;
        RECT 6073.400 4766.350 6073.680 4768.630 ;
    END
  END gpio_in[16]
  PIN gpio_in[17]
    DIRECTION INPUT ;
    USE SIGNAL ;
    PORT
      LAYER met2 ;
        RECT 5816.400 4766.350 5816.680 4768.630 ;
    END
  END gpio_in[17]
  PIN gpio_in[18]
    DIRECTION INPUT ;
    USE SIGNAL ;
    PORT
      LAYER met2 ;
        RECT 5371.400 4766.350 5371.680 4768.630 ;
    END
  END gpio_in[18]
  PIN gpio_in[19]
    DIRECTION INPUT ;
    USE SIGNAL ;
    PORT
      LAYER met2 ;
        RECT 4862.400 4766.350 4862.680 4768.630 ;
    END
  END gpio_in[19]
  PIN gpio_in[1]
    DIRECTION INPUT ;
    USE SIGNAL ;
    PORT
      LAYER met3 ;
        RECT 6754.330 519.920 6756.630 520.270 ;
    END
  END gpio_in[1]
  PIN gpio_in[20]
    DIRECTION INPUT ;
    USE SIGNAL ;
    PORT
      LAYER met2 ;
        RECT 4604.400 4766.350 4604.680 4768.630 ;
    END
  END gpio_in[20]
  PIN gpio_in[21]
    DIRECTION INPUT ;
    USE SIGNAL ;
    PORT
      LAYER met2 ;
        RECT 4347.400 4766.350 4347.680 4768.630 ;
    END
  END gpio_in[21]
  PIN gpio_in[22]
    DIRECTION INPUT ;
    USE SIGNAL ;
    PORT
      LAYER met2 ;
        RECT 4090.400 4766.350 4090.680 4768.630 ;
    END
  END gpio_in[22]
  PIN gpio_in[23]
    DIRECTION INPUT ;
    USE SIGNAL ;
    PORT
      LAYER met2 ;
        RECT 3833.400 4766.350 3833.680 4768.630 ;
    END
  END gpio_in[23]
  PIN gpio_in[24]
    DIRECTION INPUT ;
    USE SIGNAL ;
    PORT
      LAYER met2 ;
        RECT 3508.400 4766.350 3508.680 4768.630 ;
    END
  END gpio_in[24]
  PIN gpio_in[25]
    DIRECTION INPUT ;
    USE SIGNAL ;
    PORT
      LAYER met2 ;
        RECT 3251.400 4766.350 3251.680 4768.630 ;
    END
  END gpio_in[25]
  PIN gpio_in[26]
    DIRECTION INPUT ;
    USE SIGNAL ;
    PORT
      LAYER met2 ;
        RECT 2994.400 4766.350 2994.680 4768.630 ;
    END
  END gpio_in[26]
  PIN gpio_in[27]
    DIRECTION INPUT ;
    USE SIGNAL ;
    PORT
      LAYER met2 ;
        RECT 2485.400 4766.350 2485.680 4768.630 ;
    END
  END gpio_in[27]
  PIN gpio_in[28]
    DIRECTION INPUT ;
    USE SIGNAL ;
    PORT
      LAYER met2 ;
        RECT 2228.400 4766.350 2228.680 4768.630 ;
    END
  END gpio_in[28]
  PIN gpio_in[29]
    DIRECTION INPUT ;
    USE SIGNAL ;
    PORT
      LAYER met2 ;
        RECT 1783.400 4766.350 1783.680 4768.630 ;
    END
  END gpio_in[29]
  PIN gpio_in[2]
    DIRECTION INPUT ;
    USE SIGNAL ;
    PORT
      LAYER met3 ;
        RECT 6754.330 744.920 6756.630 745.270 ;
    END
  END gpio_in[2]
  PIN gpio_in[30]
    DIRECTION INPUT ;
    USE SIGNAL ;
    PORT
      LAYER met2 ;
        RECT 1274.400 4766.350 1274.680 4768.630 ;
    END
  END gpio_in[30]
  PIN gpio_in[31]
    DIRECTION INPUT ;
    USE SIGNAL ;
    PORT
      LAYER met2 ;
        RECT 1016.400 4766.350 1016.680 4768.630 ;
    END
  END gpio_in[31]
  PIN gpio_in[32]
    DIRECTION INPUT ;
    USE SIGNAL ;
    PORT
      LAYER met2 ;
        RECT 759.400 4766.350 759.680 4768.630 ;
    END
  END gpio_in[32]
  PIN gpio_in[33]
    DIRECTION INPUT ;
    USE SIGNAL ;
    PORT
      LAYER met2 ;
        RECT 502.400 4766.350 502.680 4768.630 ;
    END
  END gpio_in[33]
  PIN gpio_in[34]
    DIRECTION INPUT ;
    USE SIGNAL ;
    PORT
      LAYER met2 ;
        RECT 245.400 4766.350 245.680 4768.630 ;
    END
  END gpio_in[34]
  PIN gpio_in[35]
    DIRECTION INPUT ;
    USE SIGNAL ;
    PORT
      LAYER met3 ;
        RECT -2.000 4635.360 0.300 4635.710 ;
    END
  END gpio_in[35]
  PIN gpio_in[36]
    DIRECTION INPUT ;
    USE SIGNAL ;
    PORT
      LAYER met3 ;
        RECT -2.000 3786.360 0.300 3786.710 ;
    END
  END gpio_in[36]
  PIN gpio_in[37]
    DIRECTION INPUT ;
    USE SIGNAL ;
    PORT
      LAYER met3 ;
        RECT -2.000 3570.360 0.300 3570.710 ;
    END
  END gpio_in[37]
  PIN gpio_in[38]
    DIRECTION INPUT ;
    USE SIGNAL ;
    PORT
      LAYER met3 ;
        RECT -2.000 3354.360 0.300 3354.710 ;
    END
  END gpio_in[38]
  PIN gpio_in[39]
    DIRECTION INPUT ;
    USE SIGNAL ;
    PORT
      LAYER met3 ;
        RECT -2.000 3138.360 0.300 3138.710 ;
    END
  END gpio_in[39]
  PIN gpio_in[3]
    DIRECTION INPUT ;
    USE SIGNAL ;
    PORT
      LAYER met3 ;
        RECT 6754.330 970.920 6756.630 971.270 ;
    END
  END gpio_in[3]
  PIN gpio_in[40]
    DIRECTION INPUT ;
    USE SIGNAL ;
    PORT
      LAYER met3 ;
        RECT -2.000 2922.360 0.300 2922.710 ;
    END
  END gpio_in[40]
  PIN gpio_in[41]
    DIRECTION INPUT ;
    USE SIGNAL ;
    PORT
      LAYER met3 ;
        RECT -2.000 2706.360 0.300 2706.710 ;
    END
  END gpio_in[41]
  PIN gpio_in[42]
    DIRECTION INPUT ;
    USE SIGNAL ;
    PORT
      LAYER met3 ;
        RECT -2.000 2490.360 0.300 2490.710 ;
    END
  END gpio_in[42]
  PIN gpio_in[43]
    DIRECTION INPUT ;
    USE SIGNAL ;
    PORT
      LAYER met3 ;
        RECT -2.000 1852.360 0.300 1852.710 ;
    END
  END gpio_in[43]
  PIN gpio_in[44]
    DIRECTION INPUT ;
    USE SIGNAL ;
    PORT
      LAYER met3 ;
        RECT -2.000 1636.360 0.300 1636.710 ;
    END
  END gpio_in[44]
  PIN gpio_in[45]
    DIRECTION INPUT ;
    USE SIGNAL ;
    PORT
      LAYER met3 ;
        RECT -2.000 1420.360 0.300 1420.710 ;
    END
  END gpio_in[45]
  PIN gpio_in[46]
    DIRECTION INPUT ;
    USE SIGNAL ;
    PORT
      LAYER met3 ;
        RECT -2.000 1204.360 0.300 1204.710 ;
    END
  END gpio_in[46]
  PIN gpio_in[47]
    DIRECTION INPUT ;
    USE SIGNAL ;
    ANTENNAGATEAREA 0.593700 ;
    ANTENNADIFFAREA 0.434700 ;
    PORT
      LAYER met3 ;
        RECT -2.000 988.360 0.300 988.710 ;
    END
  END gpio_in[47]
  PIN gpio_in[48]
    DIRECTION INPUT ;
    USE SIGNAL ;
    ANTENNAGATEAREA 1.286700 ;
    ANTENNADIFFAREA 0.434700 ;
    PORT
      LAYER met3 ;
        RECT -2.000 772.360 0.300 772.710 ;
    END
  END gpio_in[48]
  PIN gpio_in[49]
    DIRECTION INPUT ;
    USE SIGNAL ;
    PORT
      LAYER met2 ;
        RECT 725.950 -2.000 726.230 0.280 ;
    END
  END gpio_in[49]
  PIN gpio_in[4]
    DIRECTION INPUT ;
    USE SIGNAL ;
    PORT
      LAYER met3 ;
        RECT 6754.330 1195.920 6756.630 1196.270 ;
    END
  END gpio_in[4]
  PIN gpio_in[50]
    DIRECTION INPUT ;
    USE SIGNAL ;
    PORT
      LAYER met2 ;
        RECT 1268.950 -2.000 1269.230 0.280 ;
    END
  END gpio_in[50]
  PIN gpio_in[51]
    DIRECTION INPUT ;
    USE SIGNAL ;
    PORT
      LAYER met2 ;
        RECT 1542.950 -2.000 1543.230 0.280 ;
    END
  END gpio_in[51]
  PIN gpio_in[52]
    DIRECTION INPUT ;
    USE SIGNAL ;
    PORT
      LAYER met2 ;
        RECT 1816.950 -2.000 1817.230 0.280 ;
    END
  END gpio_in[52]
  PIN gpio_in[53]
    DIRECTION INPUT ;
    USE SIGNAL ;
    PORT
      LAYER met2 ;
        RECT 2090.950 -2.000 2091.230 0.280 ;
    END
  END gpio_in[53]
  PIN gpio_in[54]
    DIRECTION INPUT ;
    USE SIGNAL ;
    PORT
      LAYER met2 ;
        RECT 2364.950 -2.000 2365.230 0.280 ;
    END
  END gpio_in[54]
  PIN gpio_in[55]
    DIRECTION INPUT ;
    USE SIGNAL ;
    PORT
      LAYER met2 ;
        RECT 3179.430 -2.000 3179.710 0.280 ;
    END
  END gpio_in[55]
  PIN gpio_in[56]
    DIRECTION INPUT ;
    USE SIGNAL ;
    PORT
      LAYER met2 ;
        RECT 3453.430 -2.000 3453.710 0.280 ;
    END
  END gpio_in[56]
  PIN gpio_in[57]
    DIRECTION INPUT ;
    USE SIGNAL ;
    PORT
      LAYER met2 ;
        RECT 4313.950 -2.000 4314.230 0.280 ;
    END
  END gpio_in[57]
  PIN gpio_in[58]
    DIRECTION INPUT ;
    USE SIGNAL ;
    PORT
      LAYER met2 ;
        RECT 4856.950 -2.000 4857.230 0.280 ;
    END
  END gpio_in[58]
  PIN gpio_in[59]
    DIRECTION INPUT ;
    USE SIGNAL ;
    PORT
      LAYER met2 ;
        RECT 5130.950 -2.000 5131.230 0.280 ;
    END
  END gpio_in[59]
  PIN gpio_in[5]
    DIRECTION INPUT ;
    USE SIGNAL ;
    PORT
      LAYER met3 ;
        RECT 6754.330 1420.920 6756.630 1421.270 ;
    END
  END gpio_in[5]
  PIN gpio_in[60]
    DIRECTION INPUT ;
    USE SIGNAL ;
    PORT
      LAYER met2 ;
        RECT 5404.950 -2.000 5405.230 0.280 ;
    END
  END gpio_in[60]
  PIN gpio_in[61]
    DIRECTION INPUT ;
    USE SIGNAL ;
    PORT
      LAYER met2 ;
        RECT 5678.950 -2.000 5679.230 0.280 ;
    END
  END gpio_in[61]
  PIN gpio_in[62]
    DIRECTION INPUT ;
    USE SIGNAL ;
    PORT
      LAYER met2 ;
        RECT 5952.950 -2.000 5953.230 0.280 ;
    END
  END gpio_in[62]
  PIN gpio_in[6]
    DIRECTION INPUT ;
    USE SIGNAL ;
    PORT
      LAYER met3 ;
        RECT 6754.330 1646.920 6756.630 1647.270 ;
    END
  END gpio_in[6]
  PIN gpio_in[7]
    DIRECTION INPUT ;
    USE SIGNAL ;
    PORT
      LAYER met3 ;
        RECT 6754.330 2532.920 6756.630 2533.270 ;
    END
  END gpio_in[7]
  PIN gpio_in[8]
    DIRECTION INPUT ;
    USE SIGNAL ;
    PORT
      LAYER met3 ;
        RECT 6754.330 2758.920 6756.630 2759.270 ;
    END
  END gpio_in[8]
  PIN gpio_in[9]
    DIRECTION INPUT ;
    USE SIGNAL ;
    PORT
      LAYER met3 ;
        RECT 6754.330 2983.920 6756.630 2984.270 ;
    END
  END gpio_in[9]
  PIN gpio_in_h[0]
    DIRECTION INPUT ;
    USE SIGNAL ;
    PORT
      LAYER met3 ;
        RECT 6754.330 367.520 6756.630 367.870 ;
    END
  END gpio_in_h[0]
  PIN gpio_in_h[10]
    DIRECTION INPUT ;
    USE SIGNAL ;
    PORT
      LAYER met3 ;
        RECT 6754.330 3283.520 6756.630 3283.870 ;
    END
  END gpio_in_h[10]
  PIN gpio_in_h[11]
    DIRECTION INPUT ;
    USE SIGNAL ;
    PORT
      LAYER met3 ;
        RECT 6754.330 3508.520 6756.630 3508.870 ;
    END
  END gpio_in_h[11]
  PIN gpio_in_h[12]
    DIRECTION INPUT ;
    USE SIGNAL ;
    PORT
      LAYER met3 ;
        RECT 6754.330 3733.520 6756.630 3733.870 ;
    END
  END gpio_in_h[12]
  PIN gpio_in_h[13]
    DIRECTION INPUT ;
    USE SIGNAL ;
    PORT
      LAYER met3 ;
        RECT 6754.330 4179.520 6756.630 4179.870 ;
    END
  END gpio_in_h[13]
  PIN gpio_in_h[14]
    DIRECTION INPUT ;
    USE SIGNAL ;
    PORT
      LAYER met3 ;
        RECT 6754.330 4625.520 6756.630 4625.870 ;
    END
  END gpio_in_h[14]
  PIN gpio_in_h[15]
    DIRECTION INPUT ;
    USE SIGNAL ;
    PORT
      LAYER met2 ;
        RECT 6508.800 4766.350 6509.080 4768.630 ;
    END
  END gpio_in_h[15]
  PIN gpio_in_h[16]
    DIRECTION INPUT ;
    USE SIGNAL ;
    PORT
      LAYER met2 ;
        RECT 5999.800 4766.350 6000.080 4768.630 ;
    END
  END gpio_in_h[16]
  PIN gpio_in_h[17]
    DIRECTION INPUT ;
    USE SIGNAL ;
    PORT
      LAYER met2 ;
        RECT 5742.800 4766.350 5743.080 4768.630 ;
    END
  END gpio_in_h[17]
  PIN gpio_in_h[18]
    DIRECTION INPUT ;
    USE SIGNAL ;
    PORT
      LAYER met2 ;
        RECT 5297.800 4766.350 5298.080 4768.630 ;
    END
  END gpio_in_h[18]
  PIN gpio_in_h[19]
    DIRECTION INPUT ;
    USE SIGNAL ;
    PORT
      LAYER met2 ;
        RECT 4788.800 4766.350 4789.080 4768.630 ;
    END
  END gpio_in_h[19]
  PIN gpio_in_h[1]
    DIRECTION INPUT ;
    USE SIGNAL ;
    PORT
      LAYER met3 ;
        RECT 6754.330 593.520 6756.630 593.870 ;
    END
  END gpio_in_h[1]
  PIN gpio_in_h[20]
    DIRECTION INPUT ;
    USE SIGNAL ;
    PORT
      LAYER met2 ;
        RECT 4530.800 4766.350 4531.080 4768.630 ;
    END
  END gpio_in_h[20]
  PIN gpio_in_h[21]
    DIRECTION INPUT ;
    USE SIGNAL ;
    PORT
      LAYER met2 ;
        RECT 4273.800 4766.350 4274.080 4768.630 ;
    END
  END gpio_in_h[21]
  PIN gpio_in_h[22]
    DIRECTION INPUT ;
    USE SIGNAL ;
    PORT
      LAYER met2 ;
        RECT 4016.800 4766.350 4017.080 4768.630 ;
    END
  END gpio_in_h[22]
  PIN gpio_in_h[23]
    DIRECTION INPUT ;
    USE SIGNAL ;
    PORT
      LAYER met2 ;
        RECT 3759.800 4766.350 3760.080 4768.630 ;
    END
  END gpio_in_h[23]
  PIN gpio_in_h[24]
    DIRECTION INPUT ;
    USE SIGNAL ;
    PORT
      LAYER met2 ;
        RECT 3434.800 4766.350 3435.080 4768.630 ;
    END
  END gpio_in_h[24]
  PIN gpio_in_h[25]
    DIRECTION INPUT ;
    USE SIGNAL ;
    PORT
      LAYER met2 ;
        RECT 3177.800 4766.350 3178.080 4768.630 ;
    END
  END gpio_in_h[25]
  PIN gpio_in_h[26]
    DIRECTION INPUT ;
    USE SIGNAL ;
    PORT
      LAYER met2 ;
        RECT 2920.800 4766.350 2921.080 4768.630 ;
    END
  END gpio_in_h[26]
  PIN gpio_in_h[27]
    DIRECTION INPUT ;
    USE SIGNAL ;
    PORT
      LAYER met2 ;
        RECT 2411.800 4766.350 2412.080 4768.630 ;
    END
  END gpio_in_h[27]
  PIN gpio_in_h[28]
    DIRECTION INPUT ;
    USE SIGNAL ;
    PORT
      LAYER met2 ;
        RECT 2154.800 4766.350 2155.080 4768.630 ;
    END
  END gpio_in_h[28]
  PIN gpio_in_h[29]
    DIRECTION INPUT ;
    USE SIGNAL ;
    PORT
      LAYER met2 ;
        RECT 1709.800 4766.350 1710.080 4768.630 ;
    END
  END gpio_in_h[29]
  PIN gpio_in_h[2]
    DIRECTION INPUT ;
    USE SIGNAL ;
    PORT
      LAYER met3 ;
        RECT 6754.330 818.520 6756.630 818.870 ;
    END
  END gpio_in_h[2]
  PIN gpio_in_h[30]
    DIRECTION INPUT ;
    USE SIGNAL ;
    PORT
      LAYER met2 ;
        RECT 1200.800 4766.350 1201.080 4768.630 ;
    END
  END gpio_in_h[30]
  PIN gpio_in_h[31]
    DIRECTION INPUT ;
    USE SIGNAL ;
    PORT
      LAYER met2 ;
        RECT 942.800 4766.350 943.080 4768.630 ;
    END
  END gpio_in_h[31]
  PIN gpio_in_h[32]
    DIRECTION INPUT ;
    USE SIGNAL ;
    PORT
      LAYER met2 ;
        RECT 685.800 4766.350 686.080 4768.630 ;
    END
  END gpio_in_h[32]
  PIN gpio_in_h[33]
    DIRECTION INPUT ;
    USE SIGNAL ;
    PORT
      LAYER met2 ;
        RECT 428.800 4766.350 429.080 4768.630 ;
    END
  END gpio_in_h[33]
  PIN gpio_in_h[34]
    DIRECTION INPUT ;
    USE SIGNAL ;
    PORT
      LAYER met2 ;
        RECT 171.800 4766.350 172.080 4768.630 ;
    END
  END gpio_in_h[34]
  PIN gpio_in_h[35]
    DIRECTION INPUT ;
    USE SIGNAL ;
    PORT
      LAYER met3 ;
        RECT -2.000 4561.760 0.300 4562.110 ;
    END
  END gpio_in_h[35]
  PIN gpio_in_h[36]
    DIRECTION INPUT ;
    USE SIGNAL ;
    PORT
      LAYER met3 ;
        RECT -2.000 3712.760 0.300 3713.110 ;
    END
  END gpio_in_h[36]
  PIN gpio_in_h[37]
    DIRECTION INPUT ;
    USE SIGNAL ;
    PORT
      LAYER met3 ;
        RECT -2.000 3496.760 0.300 3497.110 ;
    END
  END gpio_in_h[37]
  PIN gpio_in_h[38]
    DIRECTION INPUT ;
    USE SIGNAL ;
    PORT
      LAYER met3 ;
        RECT -2.000 3280.760 0.300 3281.110 ;
    END
  END gpio_in_h[38]
  PIN gpio_in_h[39]
    DIRECTION INPUT ;
    USE SIGNAL ;
    PORT
      LAYER met3 ;
        RECT -2.000 3064.760 0.300 3065.110 ;
    END
  END gpio_in_h[39]
  PIN gpio_in_h[3]
    DIRECTION INPUT ;
    USE SIGNAL ;
    PORT
      LAYER met3 ;
        RECT 6754.330 1044.520 6756.630 1044.870 ;
    END
  END gpio_in_h[3]
  PIN gpio_in_h[40]
    DIRECTION INPUT ;
    USE SIGNAL ;
    PORT
      LAYER met3 ;
        RECT -2.000 2848.760 0.300 2849.110 ;
    END
  END gpio_in_h[40]
  PIN gpio_in_h[41]
    DIRECTION INPUT ;
    USE SIGNAL ;
    PORT
      LAYER met3 ;
        RECT -2.000 2632.760 0.300 2633.110 ;
    END
  END gpio_in_h[41]
  PIN gpio_in_h[42]
    DIRECTION INPUT ;
    USE SIGNAL ;
    PORT
      LAYER met3 ;
        RECT -2.000 2416.760 0.300 2417.110 ;
    END
  END gpio_in_h[42]
  PIN gpio_in_h[43]
    DIRECTION INPUT ;
    USE SIGNAL ;
    PORT
      LAYER met3 ;
        RECT -2.000 1778.760 0.300 1779.110 ;
    END
  END gpio_in_h[43]
  PIN gpio_in_h[44]
    DIRECTION INPUT ;
    USE SIGNAL ;
    PORT
      LAYER met3 ;
        RECT -2.000 1562.760 0.300 1563.110 ;
    END
  END gpio_in_h[44]
  PIN gpio_in_h[45]
    DIRECTION INPUT ;
    USE SIGNAL ;
    PORT
      LAYER met3 ;
        RECT -2.000 1346.760 0.300 1347.110 ;
    END
  END gpio_in_h[45]
  PIN gpio_in_h[46]
    DIRECTION INPUT ;
    USE SIGNAL ;
    PORT
      LAYER met3 ;
        RECT -2.000 1130.760 0.300 1131.110 ;
    END
  END gpio_in_h[46]
  PIN gpio_in_h[47]
    DIRECTION INPUT ;
    USE SIGNAL ;
    PORT
      LAYER met3 ;
        RECT -2.000 914.760 0.300 915.110 ;
    END
  END gpio_in_h[47]
  PIN gpio_in_h[48]
    DIRECTION INPUT ;
    USE SIGNAL ;
    PORT
      LAYER met3 ;
        RECT -2.000 698.760 0.300 699.110 ;
    END
  END gpio_in_h[48]
  PIN gpio_in_h[49]
    DIRECTION INPUT ;
    USE SIGNAL ;
    PORT
      LAYER met2 ;
        RECT 799.550 -2.000 799.830 0.280 ;
    END
  END gpio_in_h[49]
  PIN gpio_in_h[4]
    DIRECTION INPUT ;
    USE SIGNAL ;
    PORT
      LAYER met3 ;
        RECT 6754.330 1269.520 6756.630 1269.870 ;
    END
  END gpio_in_h[4]
  PIN gpio_in_h[50]
    DIRECTION INPUT ;
    USE SIGNAL ;
    PORT
      LAYER met2 ;
        RECT 1342.550 -2.000 1342.830 0.280 ;
    END
  END gpio_in_h[50]
  PIN gpio_in_h[51]
    DIRECTION INPUT ;
    USE SIGNAL ;
    PORT
      LAYER met2 ;
        RECT 1616.550 -2.000 1616.830 0.280 ;
    END
  END gpio_in_h[51]
  PIN gpio_in_h[52]
    DIRECTION INPUT ;
    USE SIGNAL ;
    PORT
      LAYER met2 ;
        RECT 1890.550 -2.000 1890.830 0.280 ;
    END
  END gpio_in_h[52]
  PIN gpio_in_h[53]
    DIRECTION INPUT ;
    USE SIGNAL ;
    PORT
      LAYER met2 ;
        RECT 2164.550 -2.000 2164.830 0.280 ;
    END
  END gpio_in_h[53]
  PIN gpio_in_h[54]
    DIRECTION INPUT ;
    USE SIGNAL ;
    PORT
      LAYER met2 ;
        RECT 2438.550 -2.000 2438.830 0.280 ;
    END
  END gpio_in_h[54]
  PIN gpio_in_h[55]
    DIRECTION INPUT ;
    USE SIGNAL ;
    PORT
      LAYER met2 ;
        RECT 3253.030 -2.000 3253.310 0.280 ;
    END
  END gpio_in_h[55]
  PIN gpio_in_h[56]
    DIRECTION INPUT ;
    USE SIGNAL ;
    PORT
      LAYER met2 ;
        RECT 3527.030 -2.000 3527.310 0.280 ;
    END
  END gpio_in_h[56]
  PIN gpio_in_h[57]
    DIRECTION INPUT ;
    USE SIGNAL ;
    PORT
      LAYER met2 ;
        RECT 4387.550 -2.000 4387.830 0.280 ;
    END
  END gpio_in_h[57]
  PIN gpio_in_h[58]
    DIRECTION INPUT ;
    USE SIGNAL ;
    PORT
      LAYER met2 ;
        RECT 4930.550 -2.000 4930.830 0.280 ;
    END
  END gpio_in_h[58]
  PIN gpio_in_h[59]
    DIRECTION INPUT ;
    USE SIGNAL ;
    PORT
      LAYER met2 ;
        RECT 5204.550 -2.000 5204.830 0.280 ;
    END
  END gpio_in_h[59]
  PIN gpio_in_h[5]
    DIRECTION INPUT ;
    USE SIGNAL ;
    PORT
      LAYER met3 ;
        RECT 6754.330 1494.520 6756.630 1494.870 ;
    END
  END gpio_in_h[5]
  PIN gpio_in_h[60]
    DIRECTION INPUT ;
    USE SIGNAL ;
    PORT
      LAYER met2 ;
        RECT 5478.550 -2.000 5478.830 0.280 ;
    END
  END gpio_in_h[60]
  PIN gpio_in_h[61]
    DIRECTION INPUT ;
    USE SIGNAL ;
    PORT
      LAYER met2 ;
        RECT 5752.550 -2.000 5752.830 0.280 ;
    END
  END gpio_in_h[61]
  PIN gpio_in_h[62]
    DIRECTION INPUT ;
    USE SIGNAL ;
    PORT
      LAYER met2 ;
        RECT 6026.550 -2.000 6026.830 0.280 ;
    END
  END gpio_in_h[62]
  PIN gpio_in_h[6]
    DIRECTION INPUT ;
    USE SIGNAL ;
    PORT
      LAYER met3 ;
        RECT 6754.330 1720.520 6756.630 1720.870 ;
    END
  END gpio_in_h[6]
  PIN gpio_in_h[7]
    DIRECTION INPUT ;
    USE SIGNAL ;
    PORT
      LAYER met3 ;
        RECT 6754.330 2606.520 6756.630 2606.870 ;
    END
  END gpio_in_h[7]
  PIN gpio_in_h[8]
    DIRECTION INPUT ;
    USE SIGNAL ;
    PORT
      LAYER met3 ;
        RECT 6754.330 2832.520 6756.630 2832.870 ;
    END
  END gpio_in_h[8]
  PIN gpio_in_h[9]
    DIRECTION INPUT ;
    USE SIGNAL ;
    PORT
      LAYER met3 ;
        RECT 6754.330 3057.520 6756.630 3057.870 ;
    END
  END gpio_in_h[9]
  PIN gpio_inp_dis[0]
    DIRECTION OUTPUT ;
    USE SIGNAL ;
    PORT
      LAYER met3 ;
        RECT 6754.330 327.500 6756.630 327.850 ;
    END
  END gpio_inp_dis[0]
  PIN gpio_inp_dis[10]
    DIRECTION OUTPUT ;
    USE SIGNAL ;
    PORT
      LAYER met3 ;
        RECT 6754.330 3243.500 6756.630 3243.850 ;
    END
  END gpio_inp_dis[10]
  PIN gpio_inp_dis[11]
    DIRECTION OUTPUT ;
    USE SIGNAL ;
    PORT
      LAYER met3 ;
        RECT 6754.330 3468.500 6756.630 3468.850 ;
    END
  END gpio_inp_dis[11]
  PIN gpio_inp_dis[12]
    DIRECTION OUTPUT ;
    USE SIGNAL ;
    PORT
      LAYER met3 ;
        RECT 6754.330 3693.500 6756.630 3693.850 ;
    END
  END gpio_inp_dis[12]
  PIN gpio_inp_dis[13]
    DIRECTION OUTPUT ;
    USE SIGNAL ;
    PORT
      LAYER met3 ;
        RECT 6754.330 4139.500 6756.630 4139.850 ;
    END
  END gpio_inp_dis[13]
  PIN gpio_inp_dis[14]
    DIRECTION OUTPUT ;
    USE SIGNAL ;
    PORT
      LAYER met3 ;
        RECT 6754.330 4585.500 6756.630 4585.850 ;
    END
  END gpio_inp_dis[14]
  PIN gpio_inp_dis[15]
    DIRECTION OUTPUT ;
    USE SIGNAL ;
    PORT
      LAYER met2 ;
        RECT 6548.820 4766.350 6549.100 4768.630 ;
    END
  END gpio_inp_dis[15]
  PIN gpio_inp_dis[16]
    DIRECTION OUTPUT ;
    USE SIGNAL ;
    PORT
      LAYER met2 ;
        RECT 6039.820 4766.350 6040.100 4768.630 ;
    END
  END gpio_inp_dis[16]
  PIN gpio_inp_dis[17]
    DIRECTION OUTPUT ;
    USE SIGNAL ;
    PORT
      LAYER met2 ;
        RECT 5782.820 4766.350 5783.100 4768.630 ;
    END
  END gpio_inp_dis[17]
  PIN gpio_inp_dis[18]
    DIRECTION OUTPUT ;
    USE SIGNAL ;
    PORT
      LAYER met2 ;
        RECT 5337.820 4766.350 5338.100 4768.630 ;
    END
  END gpio_inp_dis[18]
  PIN gpio_inp_dis[19]
    DIRECTION OUTPUT ;
    USE SIGNAL ;
    PORT
      LAYER met2 ;
        RECT 4828.820 4766.350 4829.100 4768.630 ;
    END
  END gpio_inp_dis[19]
  PIN gpio_inp_dis[1]
    DIRECTION OUTPUT ;
    USE SIGNAL ;
    PORT
      LAYER met3 ;
        RECT 6754.330 553.500 6756.630 553.850 ;
    END
  END gpio_inp_dis[1]
  PIN gpio_inp_dis[20]
    DIRECTION OUTPUT ;
    USE SIGNAL ;
    PORT
      LAYER met2 ;
        RECT 4570.820 4766.350 4571.100 4768.630 ;
    END
  END gpio_inp_dis[20]
  PIN gpio_inp_dis[21]
    DIRECTION OUTPUT ;
    USE SIGNAL ;
    PORT
      LAYER met2 ;
        RECT 4313.820 4766.350 4314.100 4768.630 ;
    END
  END gpio_inp_dis[21]
  PIN gpio_inp_dis[22]
    DIRECTION OUTPUT ;
    USE SIGNAL ;
    PORT
      LAYER met2 ;
        RECT 4056.820 4766.350 4057.100 4768.630 ;
    END
  END gpio_inp_dis[22]
  PIN gpio_inp_dis[23]
    DIRECTION OUTPUT ;
    USE SIGNAL ;
    PORT
      LAYER met2 ;
        RECT 3799.820 4766.350 3800.100 4768.630 ;
    END
  END gpio_inp_dis[23]
  PIN gpio_inp_dis[24]
    DIRECTION OUTPUT ;
    USE SIGNAL ;
    PORT
      LAYER met2 ;
        RECT 3474.820 4766.350 3475.100 4768.630 ;
    END
  END gpio_inp_dis[24]
  PIN gpio_inp_dis[25]
    DIRECTION OUTPUT ;
    USE SIGNAL ;
    PORT
      LAYER met2 ;
        RECT 3217.820 4766.350 3218.100 4768.630 ;
    END
  END gpio_inp_dis[25]
  PIN gpio_inp_dis[26]
    DIRECTION OUTPUT ;
    USE SIGNAL ;
    PORT
      LAYER met2 ;
        RECT 2960.820 4766.350 2961.100 4768.630 ;
    END
  END gpio_inp_dis[26]
  PIN gpio_inp_dis[27]
    DIRECTION OUTPUT ;
    USE SIGNAL ;
    PORT
      LAYER met2 ;
        RECT 2451.820 4766.350 2452.100 4768.630 ;
    END
  END gpio_inp_dis[27]
  PIN gpio_inp_dis[28]
    DIRECTION OUTPUT ;
    USE SIGNAL ;
    PORT
      LAYER met2 ;
        RECT 2194.820 4766.350 2195.100 4768.630 ;
    END
  END gpio_inp_dis[28]
  PIN gpio_inp_dis[29]
    DIRECTION OUTPUT ;
    USE SIGNAL ;
    PORT
      LAYER met2 ;
        RECT 1749.820 4766.350 1750.100 4768.630 ;
    END
  END gpio_inp_dis[29]
  PIN gpio_inp_dis[2]
    DIRECTION OUTPUT ;
    USE SIGNAL ;
    PORT
      LAYER met3 ;
        RECT 6754.330 778.500 6756.630 778.850 ;
    END
  END gpio_inp_dis[2]
  PIN gpio_inp_dis[30]
    DIRECTION OUTPUT ;
    USE SIGNAL ;
    PORT
      LAYER met2 ;
        RECT 1240.820 4766.350 1241.100 4768.630 ;
    END
  END gpio_inp_dis[30]
  PIN gpio_inp_dis[31]
    DIRECTION OUTPUT ;
    USE SIGNAL ;
    PORT
      LAYER met2 ;
        RECT 982.820 4766.350 983.100 4768.630 ;
    END
  END gpio_inp_dis[31]
  PIN gpio_inp_dis[32]
    DIRECTION OUTPUT ;
    USE SIGNAL ;
    PORT
      LAYER met2 ;
        RECT 725.820 4766.350 726.100 4768.630 ;
    END
  END gpio_inp_dis[32]
  PIN gpio_inp_dis[33]
    DIRECTION OUTPUT ;
    USE SIGNAL ;
    PORT
      LAYER met2 ;
        RECT 468.820 4766.350 469.100 4768.630 ;
    END
  END gpio_inp_dis[33]
  PIN gpio_inp_dis[34]
    DIRECTION OUTPUT ;
    USE SIGNAL ;
    PORT
      LAYER met2 ;
        RECT 211.820 4766.350 212.100 4768.630 ;
    END
  END gpio_inp_dis[34]
  PIN gpio_inp_dis[35]
    DIRECTION OUTPUT ;
    USE SIGNAL ;
    PORT
      LAYER met3 ;
        RECT -2.000 4601.780 0.300 4602.130 ;
    END
  END gpio_inp_dis[35]
  PIN gpio_inp_dis[36]
    DIRECTION OUTPUT ;
    USE SIGNAL ;
    PORT
      LAYER met3 ;
        RECT -2.000 3752.780 0.300 3753.130 ;
    END
  END gpio_inp_dis[36]
  PIN gpio_inp_dis[37]
    DIRECTION OUTPUT ;
    USE SIGNAL ;
    PORT
      LAYER met3 ;
        RECT -2.000 3536.780 0.300 3537.130 ;
    END
  END gpio_inp_dis[37]
  PIN gpio_inp_dis[38]
    DIRECTION OUTPUT ;
    USE SIGNAL ;
    PORT
      LAYER met3 ;
        RECT -2.000 3320.780 0.300 3321.130 ;
    END
  END gpio_inp_dis[38]
  PIN gpio_inp_dis[39]
    DIRECTION OUTPUT ;
    USE SIGNAL ;
    PORT
      LAYER met3 ;
        RECT -2.000 3104.780 0.300 3105.130 ;
    END
  END gpio_inp_dis[39]
  PIN gpio_inp_dis[3]
    DIRECTION OUTPUT ;
    USE SIGNAL ;
    PORT
      LAYER met3 ;
        RECT 6754.330 1004.500 6756.630 1004.850 ;
    END
  END gpio_inp_dis[3]
  PIN gpio_inp_dis[40]
    DIRECTION OUTPUT ;
    USE SIGNAL ;
    PORT
      LAYER met3 ;
        RECT -2.000 2888.780 0.300 2889.130 ;
    END
  END gpio_inp_dis[40]
  PIN gpio_inp_dis[41]
    DIRECTION OUTPUT ;
    USE SIGNAL ;
    PORT
      LAYER met3 ;
        RECT -2.000 2672.780 0.300 2673.130 ;
    END
  END gpio_inp_dis[41]
  PIN gpio_inp_dis[42]
    DIRECTION OUTPUT ;
    USE SIGNAL ;
    PORT
      LAYER met3 ;
        RECT -2.000 2456.780 0.300 2457.130 ;
    END
  END gpio_inp_dis[42]
  PIN gpio_inp_dis[43]
    DIRECTION OUTPUT ;
    USE SIGNAL ;
    PORT
      LAYER met3 ;
        RECT -2.000 1818.780 0.300 1819.130 ;
    END
  END gpio_inp_dis[43]
  PIN gpio_inp_dis[44]
    DIRECTION OUTPUT ;
    USE SIGNAL ;
    PORT
      LAYER met3 ;
        RECT -2.000 1602.780 0.300 1603.130 ;
    END
  END gpio_inp_dis[44]
  PIN gpio_inp_dis[45]
    DIRECTION OUTPUT ;
    USE SIGNAL ;
    PORT
      LAYER met3 ;
        RECT -2.000 1386.780 0.300 1387.130 ;
    END
  END gpio_inp_dis[45]
  PIN gpio_inp_dis[46]
    DIRECTION OUTPUT ;
    USE SIGNAL ;
    PORT
      LAYER met3 ;
        RECT -2.000 1170.780 0.300 1171.130 ;
    END
  END gpio_inp_dis[46]
  PIN gpio_inp_dis[47]
    DIRECTION OUTPUT ;
    USE SIGNAL ;
    PORT
      LAYER met3 ;
        RECT -2.000 954.780 0.300 955.130 ;
    END
  END gpio_inp_dis[47]
  PIN gpio_inp_dis[48]
    DIRECTION OUTPUT ;
    USE SIGNAL ;
    PORT
      LAYER met3 ;
        RECT -2.000 738.780 0.300 739.130 ;
    END
  END gpio_inp_dis[48]
  PIN gpio_inp_dis[49]
    DIRECTION OUTPUT ;
    USE SIGNAL ;
    PORT
      LAYER met2 ;
        RECT 759.530 -2.000 759.810 0.280 ;
    END
  END gpio_inp_dis[49]
  PIN gpio_inp_dis[4]
    DIRECTION OUTPUT ;
    USE SIGNAL ;
    PORT
      LAYER met3 ;
        RECT 6754.330 1229.500 6756.630 1229.850 ;
    END
  END gpio_inp_dis[4]
  PIN gpio_inp_dis[50]
    DIRECTION OUTPUT ;
    USE SIGNAL ;
    PORT
      LAYER met2 ;
        RECT 1302.530 -2.000 1302.810 0.280 ;
    END
  END gpio_inp_dis[50]
  PIN gpio_inp_dis[51]
    DIRECTION OUTPUT ;
    USE SIGNAL ;
    PORT
      LAYER met2 ;
        RECT 1576.530 -2.000 1576.810 0.280 ;
    END
  END gpio_inp_dis[51]
  PIN gpio_inp_dis[52]
    DIRECTION OUTPUT ;
    USE SIGNAL ;
    PORT
      LAYER met2 ;
        RECT 1850.530 -2.000 1850.810 0.280 ;
    END
  END gpio_inp_dis[52]
  PIN gpio_inp_dis[53]
    DIRECTION OUTPUT ;
    USE SIGNAL ;
    PORT
      LAYER met2 ;
        RECT 2124.530 -2.000 2124.810 0.280 ;
    END
  END gpio_inp_dis[53]
  PIN gpio_inp_dis[54]
    DIRECTION OUTPUT ;
    USE SIGNAL ;
    PORT
      LAYER met2 ;
        RECT 2398.530 -2.000 2398.810 0.280 ;
    END
  END gpio_inp_dis[54]
  PIN gpio_inp_dis[55]
    DIRECTION OUTPUT ;
    USE SIGNAL ;
    PORT
      LAYER met2 ;
        RECT 3213.010 -2.000 3213.290 0.280 ;
    END
  END gpio_inp_dis[55]
  PIN gpio_inp_dis[56]
    DIRECTION OUTPUT ;
    USE SIGNAL ;
    PORT
      LAYER met2 ;
        RECT 3487.010 -2.000 3487.290 0.280 ;
    END
  END gpio_inp_dis[56]
  PIN gpio_inp_dis[57]
    DIRECTION OUTPUT ;
    USE SIGNAL ;
    PORT
      LAYER met2 ;
        RECT 4347.530 -2.000 4347.810 0.280 ;
    END
  END gpio_inp_dis[57]
  PIN gpio_inp_dis[58]
    DIRECTION OUTPUT ;
    USE SIGNAL ;
    PORT
      LAYER met2 ;
        RECT 4890.530 -2.000 4890.810 0.280 ;
    END
  END gpio_inp_dis[58]
  PIN gpio_inp_dis[59]
    DIRECTION OUTPUT ;
    USE SIGNAL ;
    PORT
      LAYER met2 ;
        RECT 5164.530 -2.000 5164.810 0.280 ;
    END
  END gpio_inp_dis[59]
  PIN gpio_inp_dis[5]
    DIRECTION OUTPUT ;
    USE SIGNAL ;
    PORT
      LAYER met3 ;
        RECT 6754.330 1454.500 6756.630 1454.850 ;
    END
  END gpio_inp_dis[5]
  PIN gpio_inp_dis[60]
    DIRECTION OUTPUT ;
    USE SIGNAL ;
    PORT
      LAYER met2 ;
        RECT 5438.530 -2.000 5438.810 0.280 ;
    END
  END gpio_inp_dis[60]
  PIN gpio_inp_dis[61]
    DIRECTION OUTPUT ;
    USE SIGNAL ;
    PORT
      LAYER met2 ;
        RECT 5712.530 -2.000 5712.810 0.280 ;
    END
  END gpio_inp_dis[61]
  PIN gpio_inp_dis[62]
    DIRECTION OUTPUT ;
    USE SIGNAL ;
    PORT
      LAYER met2 ;
        RECT 5986.530 -2.000 5986.810 0.280 ;
    END
  END gpio_inp_dis[62]
  PIN gpio_inp_dis[6]
    DIRECTION OUTPUT ;
    USE SIGNAL ;
    PORT
      LAYER met3 ;
        RECT 6754.330 1680.500 6756.630 1680.850 ;
    END
  END gpio_inp_dis[6]
  PIN gpio_inp_dis[7]
    DIRECTION OUTPUT ;
    USE SIGNAL ;
    PORT
      LAYER met3 ;
        RECT 6754.330 2566.500 6756.630 2566.850 ;
    END
  END gpio_inp_dis[7]
  PIN gpio_inp_dis[8]
    DIRECTION OUTPUT ;
    USE SIGNAL ;
    PORT
      LAYER met3 ;
        RECT 6754.330 2792.500 6756.630 2792.850 ;
    END
  END gpio_inp_dis[8]
  PIN gpio_inp_dis[9]
    DIRECTION OUTPUT ;
    USE SIGNAL ;
    PORT
      LAYER met3 ;
        RECT 6754.330 3017.500 6756.630 3017.850 ;
    END
  END gpio_inp_dis[9]
  PIN gpio_loopback_one[0]
    DIRECTION INPUT ;
    USE SIGNAL ;
    PORT
      LAYER met3 ;
        RECT 6754.330 380.025 6756.630 380.335 ;
    END
  END gpio_loopback_one[0]
  PIN gpio_loopback_one[10]
    DIRECTION INPUT ;
    USE SIGNAL ;
    PORT
      LAYER met3 ;
        RECT 6754.330 3290.030 6756.630 3290.340 ;
    END
  END gpio_loopback_one[10]
  PIN gpio_loopback_one[11]
    DIRECTION INPUT ;
    USE SIGNAL ;
    PORT
      LAYER met3 ;
        RECT 6754.330 3515.030 6756.630 3515.340 ;
    END
  END gpio_loopback_one[11]
  PIN gpio_loopback_one[12]
    DIRECTION INPUT ;
    USE SIGNAL ;
    PORT
      LAYER met3 ;
        RECT 6754.330 3740.030 6756.630 3740.340 ;
    END
  END gpio_loopback_one[12]
  PIN gpio_loopback_one[13]
    DIRECTION INPUT ;
    USE SIGNAL ;
    PORT
      LAYER met3 ;
        RECT 6754.330 4185.030 6756.630 4185.340 ;
    END
  END gpio_loopback_one[13]
  PIN gpio_loopback_one[14]
    DIRECTION INPUT ;
    USE SIGNAL ;
    PORT
      LAYER met3 ;
        RECT 6754.330 4635.030 6756.630 4635.340 ;
    END
  END gpio_loopback_one[14]
  PIN gpio_loopback_one[15]
    DIRECTION INPUT ;
    USE SIGNAL ;
    PORT
      LAYER met2 ;
        RECT 6479.490 4766.350 6479.790 4768.630 ;
    END
  END gpio_loopback_one[15]
  PIN gpio_loopback_one[16]
    DIRECTION INPUT ;
    USE SIGNAL ;
    PORT
      LAYER met2 ;
        RECT 5982.490 4766.350 5982.790 4768.630 ;
    END
  END gpio_loopback_one[16]
  PIN gpio_loopback_one[17]
    DIRECTION INPUT ;
    USE SIGNAL ;
    PORT
      LAYER met2 ;
        RECT 5726.490 4766.350 5726.790 4768.630 ;
    END
  END gpio_loopback_one[17]
  PIN gpio_loopback_one[18]
    DIRECTION INPUT ;
    USE SIGNAL ;
    PORT
      LAYER met2 ;
        RECT 5281.490 4766.350 5281.790 4768.630 ;
    END
  END gpio_loopback_one[18]
  PIN gpio_loopback_one[19]
    DIRECTION INPUT ;
    USE SIGNAL ;
    PORT
      LAYER met2 ;
        RECT 4759.490 4766.350 4759.790 4768.630 ;
    END
  END gpio_loopback_one[19]
  PIN gpio_loopback_one[1]
    DIRECTION INPUT ;
    USE SIGNAL ;
    PORT
      LAYER met3 ;
        RECT 6754.330 605.025 6756.630 605.335 ;
    END
  END gpio_loopback_one[1]
  PIN gpio_loopback_one[20]
    DIRECTION INPUT ;
    USE SIGNAL ;
    PORT
      LAYER met2 ;
        RECT 4503.490 4766.350 4503.790 4768.630 ;
    END
  END gpio_loopback_one[20]
  PIN gpio_loopback_one[21]
    DIRECTION INPUT ;
    USE SIGNAL ;
    PORT
      LAYER met2 ;
        RECT 4247.490 4766.350 4247.790 4768.630 ;
    END
  END gpio_loopback_one[21]
  PIN gpio_loopback_one[22]
    DIRECTION INPUT ;
    USE SIGNAL ;
    PORT
      LAYER met2 ;
        RECT 3991.490 4766.350 3991.790 4768.630 ;
    END
  END gpio_loopback_one[22]
  PIN gpio_loopback_one[23]
    DIRECTION INPUT ;
    USE SIGNAL ;
    PORT
      LAYER met2 ;
        RECT 3735.490 4766.350 3735.790 4768.630 ;
    END
  END gpio_loopback_one[23]
  PIN gpio_loopback_one[24]
    DIRECTION INPUT ;
    USE SIGNAL ;
    PORT
      LAYER met2 ;
        RECT 3410.490 4766.350 3410.790 4768.630 ;
    END
  END gpio_loopback_one[24]
  PIN gpio_loopback_one[25]
    DIRECTION INPUT ;
    USE SIGNAL ;
    PORT
      LAYER met2 ;
        RECT 3153.490 4766.350 3153.790 4768.630 ;
    END
  END gpio_loopback_one[25]
  PIN gpio_loopback_one[26]
    DIRECTION INPUT ;
    USE SIGNAL ;
    PORT
      LAYER met2 ;
        RECT 2891.490 4766.350 2891.790 4768.630 ;
    END
  END gpio_loopback_one[26]
  PIN gpio_loopback_one[27]
    DIRECTION INPUT ;
    USE SIGNAL ;
    PORT
      LAYER met2 ;
        RECT 2394.490 4766.350 2394.790 4768.630 ;
    END
  END gpio_loopback_one[27]
  PIN gpio_loopback_one[28]
    DIRECTION INPUT ;
    USE SIGNAL ;
    PORT
      LAYER met2 ;
        RECT 2138.490 4766.350 2138.790 4768.630 ;
    END
  END gpio_loopback_one[28]
  PIN gpio_loopback_one[29]
    DIRECTION INPUT ;
    USE SIGNAL ;
    PORT
      LAYER met2 ;
        RECT 1693.490 4766.350 1693.790 4768.630 ;
    END
  END gpio_loopback_one[29]
  PIN gpio_loopback_one[2]
    DIRECTION INPUT ;
    USE SIGNAL ;
    PORT
      LAYER met3 ;
        RECT 6754.330 830.025 6756.630 830.335 ;
    END
  END gpio_loopback_one[2]
  PIN gpio_loopback_one[30]
    DIRECTION INPUT ;
    USE SIGNAL ;
    PORT
      LAYER met2 ;
        RECT 1171.490 4766.350 1171.790 4768.630 ;
    END
  END gpio_loopback_one[30]
  PIN gpio_loopback_one[31]
    DIRECTION INPUT ;
    USE SIGNAL ;
    PORT
      LAYER met2 ;
        RECT 915.490 4766.350 915.790 4768.630 ;
    END
  END gpio_loopback_one[31]
  PIN gpio_loopback_one[32]
    DIRECTION INPUT ;
    USE SIGNAL ;
    PORT
      LAYER met2 ;
        RECT 659.490 4766.350 659.790 4768.630 ;
    END
  END gpio_loopback_one[32]
  PIN gpio_loopback_one[33]
    DIRECTION INPUT ;
    USE SIGNAL ;
    PORT
      LAYER met2 ;
        RECT 403.490 4766.350 403.790 4768.630 ;
    END
  END gpio_loopback_one[33]
  PIN gpio_loopback_one[34]
    DIRECTION INPUT ;
    USE SIGNAL ;
    PORT
      LAYER met2 ;
        RECT 147.490 4766.350 147.790 4768.630 ;
    END
  END gpio_loopback_one[34]
  PIN gpio_loopback_one[35]
    DIRECTION INPUT ;
    USE SIGNAL ;
    PORT
      LAYER met3 ;
        RECT -2.000 4533.220 0.300 4533.520 ;
    END
  END gpio_loopback_one[35]
  PIN gpio_loopback_one[36]
    DIRECTION INPUT ;
    USE SIGNAL ;
    PORT
      LAYER met3 ;
        RECT -2.000 3683.220 0.300 3683.520 ;
    END
  END gpio_loopback_one[36]
  PIN gpio_loopback_one[37]
    DIRECTION INPUT ;
    USE SIGNAL ;
    PORT
      LAYER met3 ;
        RECT -2.000 3468.220 0.300 3468.520 ;
    END
  END gpio_loopback_one[37]
  PIN gpio_loopback_one[38]
    DIRECTION INPUT ;
    USE SIGNAL ;
    PORT
      LAYER met3 ;
        RECT -2.000 3253.220 0.300 3253.520 ;
    END
  END gpio_loopback_one[38]
  PIN gpio_loopback_one[39]
    DIRECTION INPUT ;
    USE SIGNAL ;
    PORT
      LAYER met3 ;
        RECT -2.000 3038.220 0.300 3038.520 ;
    END
  END gpio_loopback_one[39]
  PIN gpio_loopback_one[3]
    DIRECTION INPUT ;
    USE SIGNAL ;
    PORT
      LAYER met3 ;
        RECT 6754.330 1055.025 6756.630 1055.335 ;
    END
  END gpio_loopback_one[3]
  PIN gpio_loopback_one[40]
    DIRECTION INPUT ;
    USE SIGNAL ;
    PORT
      LAYER met3 ;
        RECT -2.000 2823.220 0.300 2823.520 ;
    END
  END gpio_loopback_one[40]
  PIN gpio_loopback_one[41]
    DIRECTION INPUT ;
    USE SIGNAL ;
    PORT
      LAYER met3 ;
        RECT -2.000 2608.220 0.300 2608.520 ;
    END
  END gpio_loopback_one[41]
  PIN gpio_loopback_one[42]
    DIRECTION INPUT ;
    USE SIGNAL ;
    PORT
      LAYER met3 ;
        RECT -2.000 2393.220 0.300 2393.520 ;
    END
  END gpio_loopback_one[42]
  PIN gpio_loopback_one[43]
    DIRECTION INPUT ;
    USE SIGNAL ;
    PORT
      LAYER met3 ;
        RECT -2.000 1748.220 0.300 1748.520 ;
    END
  END gpio_loopback_one[43]
  PIN gpio_loopback_one[44]
    DIRECTION INPUT ;
    USE SIGNAL ;
    PORT
      LAYER met3 ;
        RECT -2.000 1533.220 0.300 1533.520 ;
    END
  END gpio_loopback_one[44]
  PIN gpio_loopback_one[45]
    DIRECTION INPUT ;
    USE SIGNAL ;
    PORT
      LAYER met3 ;
        RECT -2.000 1318.220 0.300 1318.520 ;
    END
  END gpio_loopback_one[45]
  PIN gpio_loopback_one[46]
    DIRECTION INPUT ;
    USE SIGNAL ;
    PORT
      LAYER met3 ;
        RECT -2.000 1103.220 0.300 1103.520 ;
    END
  END gpio_loopback_one[46]
  PIN gpio_loopback_one[47]
    DIRECTION INPUT ;
    USE SIGNAL ;
    PORT
      LAYER met3 ;
        RECT -2.000 888.220 0.300 888.520 ;
    END
  END gpio_loopback_one[47]
  PIN gpio_loopback_one[48]
    DIRECTION INPUT ;
    USE SIGNAL ;
    PORT
      LAYER met3 ;
        RECT -2.000 673.220 0.550 673.520 ;
    END
  END gpio_loopback_one[48]
  PIN gpio_loopback_one[49]
    DIRECTION INPUT ;
    USE SIGNAL ;
    PORT
      LAYER met2 ;
        RECT 802.900 -2.000 803.160 0.280 ;
    END
  END gpio_loopback_one[49]
  PIN gpio_loopback_one[4]
    DIRECTION INPUT ;
    USE SIGNAL ;
    PORT
      LAYER met3 ;
        RECT 6754.330 1280.025 6756.630 1280.335 ;
    END
  END gpio_loopback_one[4]
  PIN gpio_loopback_one[50]
    DIRECTION INPUT ;
    USE SIGNAL ;
    PORT
      LAYER met2 ;
        RECT 1345.900 -2.000 1346.160 0.280 ;
    END
  END gpio_loopback_one[50]
  PIN gpio_loopback_one[51]
    DIRECTION INPUT ;
    USE SIGNAL ;
    PORT
      LAYER met2 ;
        RECT 1619.900 -2.000 1620.160 0.280 ;
    END
  END gpio_loopback_one[51]
  PIN gpio_loopback_one[52]
    DIRECTION INPUT ;
    USE SIGNAL ;
    PORT
      LAYER met2 ;
        RECT 1893.900 -2.000 1894.160 0.280 ;
    END
  END gpio_loopback_one[52]
  PIN gpio_loopback_one[53]
    DIRECTION INPUT ;
    USE SIGNAL ;
    PORT
      LAYER met2 ;
        RECT 2167.900 -2.000 2168.160 0.280 ;
    END
  END gpio_loopback_one[53]
  PIN gpio_loopback_one[54]
    DIRECTION INPUT ;
    USE SIGNAL ;
    PORT
      LAYER met2 ;
        RECT 2441.900 -2.000 2442.160 0.280 ;
    END
  END gpio_loopback_one[54]
  PIN gpio_loopback_one[55]
    DIRECTION INPUT ;
    USE SIGNAL ;
    PORT
      LAYER met2 ;
        RECT 3256.380 -2.000 3256.640 0.280 ;
    END
  END gpio_loopback_one[55]
  PIN gpio_loopback_one[56]
    DIRECTION INPUT ;
    USE SIGNAL ;
    PORT
      LAYER met2 ;
        RECT 3530.380 -2.000 3530.640 0.280 ;
    END
  END gpio_loopback_one[56]
  PIN gpio_loopback_one[57]
    DIRECTION INPUT ;
    USE SIGNAL ;
    PORT
      LAYER met2 ;
        RECT 4390.900 -2.000 4391.160 0.280 ;
    END
  END gpio_loopback_one[57]
  PIN gpio_loopback_one[58]
    DIRECTION INPUT ;
    USE SIGNAL ;
    PORT
      LAYER met2 ;
        RECT 4933.900 -2.000 4934.160 0.280 ;
    END
  END gpio_loopback_one[58]
  PIN gpio_loopback_one[59]
    DIRECTION INPUT ;
    USE SIGNAL ;
    PORT
      LAYER met2 ;
        RECT 5207.900 -2.000 5208.160 0.280 ;
    END
  END gpio_loopback_one[59]
  PIN gpio_loopback_one[5]
    DIRECTION INPUT ;
    USE SIGNAL ;
    PORT
      LAYER met3 ;
        RECT 6754.330 1505.025 6756.630 1505.335 ;
    END
  END gpio_loopback_one[5]
  PIN gpio_loopback_one[60]
    DIRECTION INPUT ;
    USE SIGNAL ;
    PORT
      LAYER met2 ;
        RECT 5481.900 -2.000 5482.160 0.280 ;
    END
  END gpio_loopback_one[60]
  PIN gpio_loopback_one[61]
    DIRECTION INPUT ;
    USE SIGNAL ;
    PORT
      LAYER met2 ;
        RECT 5755.900 -2.000 5756.160 0.280 ;
    END
  END gpio_loopback_one[61]
  PIN gpio_loopback_one[62]
    DIRECTION INPUT ;
    USE SIGNAL ;
    PORT
      LAYER met2 ;
        RECT 6029.900 -2.000 6030.160 0.280 ;
    END
  END gpio_loopback_one[62]
  PIN gpio_loopback_one[6]
    DIRECTION INPUT ;
    USE SIGNAL ;
    PORT
      LAYER met3 ;
        RECT 6754.330 1730.025 6756.630 1730.335 ;
    END
  END gpio_loopback_one[6]
  PIN gpio_loopback_one[7]
    DIRECTION INPUT ;
    USE SIGNAL ;
    PORT
      LAYER met3 ;
        RECT 6754.330 2615.025 6756.630 2615.335 ;
    END
  END gpio_loopback_one[7]
  PIN gpio_loopback_one[8]
    DIRECTION INPUT ;
    USE SIGNAL ;
    PORT
      LAYER met3 ;
        RECT 6754.330 2840.030 6756.630 2840.340 ;
    END
  END gpio_loopback_one[8]
  PIN gpio_loopback_one[9]
    DIRECTION INPUT ;
    USE SIGNAL ;
    PORT
      LAYER met3 ;
        RECT 6754.330 3065.030 6756.630 3065.340 ;
    END
  END gpio_loopback_one[9]
  PIN gpio_loopback_zero[0]
    DIRECTION INPUT ;
    USE SIGNAL ;
    PORT
      LAYER met3 ;
        RECT 6754.330 390.030 6756.630 390.340 ;
    END
  END gpio_loopback_zero[0]
  PIN gpio_loopback_zero[10]
    DIRECTION INPUT ;
    USE SIGNAL ;
    PORT
      LAYER met3 ;
        RECT 6754.330 3300.030 6756.630 3300.340 ;
    END
  END gpio_loopback_zero[10]
  PIN gpio_loopback_zero[11]
    DIRECTION INPUT ;
    USE SIGNAL ;
    PORT
      LAYER met3 ;
        RECT 6754.330 3525.030 6756.630 3525.340 ;
    END
  END gpio_loopback_zero[11]
  PIN gpio_loopback_zero[12]
    DIRECTION INPUT ;
    USE SIGNAL ;
    PORT
      LAYER met3 ;
        RECT 6754.330 3750.030 6756.630 3750.340 ;
    END
  END gpio_loopback_zero[12]
  PIN gpio_loopback_zero[13]
    DIRECTION INPUT ;
    USE SIGNAL ;
    PORT
      LAYER met3 ;
        RECT 6754.330 4195.030 6756.630 4195.340 ;
    END
  END gpio_loopback_zero[13]
  PIN gpio_loopback_zero[14]
    DIRECTION INPUT ;
    USE SIGNAL ;
    PORT
      LAYER met3 ;
        RECT 6754.330 4645.030 6756.630 4645.340 ;
    END
  END gpio_loopback_zero[14]
  PIN gpio_loopback_zero[15]
    DIRECTION INPUT ;
    USE SIGNAL ;
    PORT
      LAYER met2 ;
        RECT 6469.490 4766.350 6469.790 4768.630 ;
    END
  END gpio_loopback_zero[15]
  PIN gpio_loopback_zero[16]
    DIRECTION INPUT ;
    USE SIGNAL ;
    PORT
      LAYER met2 ;
        RECT 5972.490 4766.350 5972.790 4768.630 ;
    END
  END gpio_loopback_zero[16]
  PIN gpio_loopback_zero[17]
    DIRECTION INPUT ;
    USE SIGNAL ;
    PORT
      LAYER met2 ;
        RECT 5716.490 4766.350 5716.790 4768.630 ;
    END
  END gpio_loopback_zero[17]
  PIN gpio_loopback_zero[18]
    DIRECTION INPUT ;
    USE SIGNAL ;
    PORT
      LAYER met2 ;
        RECT 5271.490 4766.350 5271.790 4768.630 ;
    END
  END gpio_loopback_zero[18]
  PIN gpio_loopback_zero[19]
    DIRECTION INPUT ;
    USE SIGNAL ;
    PORT
      LAYER met2 ;
        RECT 4749.490 4766.350 4749.790 4768.630 ;
    END
  END gpio_loopback_zero[19]
  PIN gpio_loopback_zero[1]
    DIRECTION INPUT ;
    USE SIGNAL ;
    PORT
      LAYER met3 ;
        RECT 6754.330 615.030 6756.630 615.340 ;
    END
  END gpio_loopback_zero[1]
  PIN gpio_loopback_zero[20]
    DIRECTION INPUT ;
    USE SIGNAL ;
    PORT
      LAYER met2 ;
        RECT 4493.490 4766.350 4493.790 4768.630 ;
    END
  END gpio_loopback_zero[20]
  PIN gpio_loopback_zero[21]
    DIRECTION INPUT ;
    USE SIGNAL ;
    PORT
      LAYER met2 ;
        RECT 4237.490 4766.350 4237.790 4768.630 ;
    END
  END gpio_loopback_zero[21]
  PIN gpio_loopback_zero[22]
    DIRECTION INPUT ;
    USE SIGNAL ;
    PORT
      LAYER met2 ;
        RECT 3981.490 4766.350 3981.790 4768.630 ;
    END
  END gpio_loopback_zero[22]
  PIN gpio_loopback_zero[23]
    DIRECTION INPUT ;
    USE SIGNAL ;
    PORT
      LAYER met2 ;
        RECT 3725.490 4766.350 3725.790 4768.630 ;
    END
  END gpio_loopback_zero[23]
  PIN gpio_loopback_zero[24]
    DIRECTION INPUT ;
    USE SIGNAL ;
    PORT
      LAYER met2 ;
        RECT 3400.490 4766.350 3400.790 4768.630 ;
    END
  END gpio_loopback_zero[24]
  PIN gpio_loopback_zero[25]
    DIRECTION INPUT ;
    USE SIGNAL ;
    PORT
      LAYER met2 ;
        RECT 3143.490 4766.350 3143.790 4768.630 ;
    END
  END gpio_loopback_zero[25]
  PIN gpio_loopback_zero[26]
    DIRECTION INPUT ;
    USE SIGNAL ;
    PORT
      LAYER met2 ;
        RECT 2881.490 4766.350 2881.790 4768.630 ;
    END
  END gpio_loopback_zero[26]
  PIN gpio_loopback_zero[27]
    DIRECTION INPUT ;
    USE SIGNAL ;
    PORT
      LAYER met2 ;
        RECT 2384.490 4766.350 2384.790 4768.630 ;
    END
  END gpio_loopback_zero[27]
  PIN gpio_loopback_zero[28]
    DIRECTION INPUT ;
    USE SIGNAL ;
    PORT
      LAYER met2 ;
        RECT 2128.490 4766.350 2128.790 4768.630 ;
    END
  END gpio_loopback_zero[28]
  PIN gpio_loopback_zero[29]
    DIRECTION INPUT ;
    USE SIGNAL ;
    PORT
      LAYER met2 ;
        RECT 1683.490 4766.350 1683.790 4768.630 ;
    END
  END gpio_loopback_zero[29]
  PIN gpio_loopback_zero[2]
    DIRECTION INPUT ;
    USE SIGNAL ;
    PORT
      LAYER met3 ;
        RECT 6754.330 840.030 6756.630 840.340 ;
    END
  END gpio_loopback_zero[2]
  PIN gpio_loopback_zero[30]
    DIRECTION INPUT ;
    USE SIGNAL ;
    PORT
      LAYER met2 ;
        RECT 1161.490 4766.350 1161.790 4768.630 ;
    END
  END gpio_loopback_zero[30]
  PIN gpio_loopback_zero[31]
    DIRECTION INPUT ;
    USE SIGNAL ;
    PORT
      LAYER met2 ;
        RECT 905.490 4766.350 905.790 4768.630 ;
    END
  END gpio_loopback_zero[31]
  PIN gpio_loopback_zero[32]
    DIRECTION INPUT ;
    USE SIGNAL ;
    PORT
      LAYER met2 ;
        RECT 649.490 4766.350 649.790 4768.630 ;
    END
  END gpio_loopback_zero[32]
  PIN gpio_loopback_zero[33]
    DIRECTION INPUT ;
    USE SIGNAL ;
    PORT
      LAYER met2 ;
        RECT 393.490 4766.350 393.790 4768.630 ;
    END
  END gpio_loopback_zero[33]
  PIN gpio_loopback_zero[34]
    DIRECTION INPUT ;
    USE SIGNAL ;
    PORT
      LAYER met2 ;
        RECT 137.490 4766.350 137.790 4768.630 ;
    END
  END gpio_loopback_zero[34]
  PIN gpio_loopback_zero[35]
    DIRECTION INPUT ;
    USE SIGNAL ;
    PORT
      LAYER met3 ;
        RECT -2.000 4523.220 0.300 4523.520 ;
    END
  END gpio_loopback_zero[35]
  PIN gpio_loopback_zero[36]
    DIRECTION INPUT ;
    USE SIGNAL ;
    PORT
      LAYER met3 ;
        RECT -2.000 3673.220 0.300 3673.520 ;
    END
  END gpio_loopback_zero[36]
  PIN gpio_loopback_zero[37]
    DIRECTION INPUT ;
    USE SIGNAL ;
    PORT
      LAYER met3 ;
        RECT -2.000 3458.220 0.300 3458.520 ;
    END
  END gpio_loopback_zero[37]
  PIN gpio_loopback_zero[38]
    DIRECTION INPUT ;
    USE SIGNAL ;
    PORT
      LAYER met3 ;
        RECT -2.000 3243.220 0.300 3243.520 ;
    END
  END gpio_loopback_zero[38]
  PIN gpio_loopback_zero[39]
    DIRECTION INPUT ;
    USE SIGNAL ;
    PORT
      LAYER met3 ;
        RECT -2.000 3028.220 0.300 3028.520 ;
    END
  END gpio_loopback_zero[39]
  PIN gpio_loopback_zero[3]
    DIRECTION INPUT ;
    USE SIGNAL ;
    PORT
      LAYER met3 ;
        RECT 6754.330 1065.030 6756.630 1065.340 ;
    END
  END gpio_loopback_zero[3]
  PIN gpio_loopback_zero[40]
    DIRECTION INPUT ;
    USE SIGNAL ;
    PORT
      LAYER met3 ;
        RECT -2.000 2813.220 0.300 2813.520 ;
    END
  END gpio_loopback_zero[40]
  PIN gpio_loopback_zero[41]
    DIRECTION INPUT ;
    USE SIGNAL ;
    PORT
      LAYER met3 ;
        RECT -2.000 2598.220 0.300 2598.520 ;
    END
  END gpio_loopback_zero[41]
  PIN gpio_loopback_zero[42]
    DIRECTION INPUT ;
    USE SIGNAL ;
    PORT
      LAYER met3 ;
        RECT -2.000 2383.220 0.300 2383.520 ;
    END
  END gpio_loopback_zero[42]
  PIN gpio_loopback_zero[43]
    DIRECTION INPUT ;
    USE SIGNAL ;
    PORT
      LAYER met3 ;
        RECT -2.000 1738.220 0.300 1738.520 ;
    END
  END gpio_loopback_zero[43]
  PIN gpio_loopback_zero[44]
    DIRECTION INPUT ;
    USE SIGNAL ;
    PORT
      LAYER met3 ;
        RECT -2.000 1523.220 0.300 1523.520 ;
    END
  END gpio_loopback_zero[44]
  PIN gpio_loopback_zero[45]
    DIRECTION INPUT ;
    USE SIGNAL ;
    PORT
      LAYER met3 ;
        RECT -2.000 1308.220 0.300 1308.520 ;
    END
  END gpio_loopback_zero[45]
  PIN gpio_loopback_zero[46]
    DIRECTION INPUT ;
    USE SIGNAL ;
    PORT
      LAYER met3 ;
        RECT -2.000 1093.220 0.300 1093.520 ;
    END
  END gpio_loopback_zero[46]
  PIN gpio_loopback_zero[47]
    DIRECTION INPUT ;
    USE SIGNAL ;
    PORT
      LAYER met3 ;
        RECT -2.000 878.220 0.300 878.520 ;
    END
  END gpio_loopback_zero[47]
  PIN gpio_loopback_zero[48]
    DIRECTION INPUT ;
    USE SIGNAL ;
    PORT
      LAYER met3 ;
        RECT -2.000 663.220 0.300 663.520 ;
    END
  END gpio_loopback_zero[48]
  PIN gpio_loopback_zero[49]
    DIRECTION INPUT ;
    USE SIGNAL ;
    PORT
      LAYER met2 ;
        RECT 818.955 -2.000 819.215 0.280 ;
    END
  END gpio_loopback_zero[49]
  PIN gpio_loopback_zero[4]
    DIRECTION INPUT ;
    USE SIGNAL ;
    PORT
      LAYER met3 ;
        RECT 6754.330 1290.030 6756.630 1290.340 ;
    END
  END gpio_loopback_zero[4]
  PIN gpio_loopback_zero[50]
    DIRECTION INPUT ;
    USE SIGNAL ;
    PORT
      LAYER met2 ;
        RECT 1366.800 -2.000 1367.060 0.280 ;
    END
  END gpio_loopback_zero[50]
  PIN gpio_loopback_zero[51]
    DIRECTION INPUT ;
    USE SIGNAL ;
    PORT
      LAYER met2 ;
        RECT 1640.825 -2.000 1641.085 0.280 ;
    END
  END gpio_loopback_zero[51]
  PIN gpio_loopback_zero[52]
    DIRECTION INPUT ;
    USE SIGNAL ;
    PORT
      LAYER met2 ;
        RECT 1914.890 -2.000 1915.150 0.280 ;
    END
  END gpio_loopback_zero[52]
  PIN gpio_loopback_zero[53]
    DIRECTION INPUT ;
    USE SIGNAL ;
    PORT
      LAYER met2 ;
        RECT 2188.890 -2.000 2189.150 0.280 ;
    END
  END gpio_loopback_zero[53]
  PIN gpio_loopback_zero[54]
    DIRECTION INPUT ;
    USE SIGNAL ;
    PORT
      LAYER met2 ;
        RECT 2463.175 -2.000 2463.435 0.280 ;
    END
  END gpio_loopback_zero[54]
  PIN gpio_loopback_zero[55]
    DIRECTION INPUT ;
    USE SIGNAL ;
    PORT
      LAYER met2 ;
        RECT 3272.435 -2.000 3272.695 0.280 ;
    END
  END gpio_loopback_zero[55]
  PIN gpio_loopback_zero[56]
    DIRECTION INPUT ;
    USE SIGNAL ;
    PORT
      LAYER met2 ;
        RECT 3546.435 -2.000 3546.695 0.280 ;
    END
  END gpio_loopback_zero[56]
  PIN gpio_loopback_zero[57]
    DIRECTION INPUT ;
    USE SIGNAL ;
    PORT
      LAYER met2 ;
        RECT 4406.955 -2.000 4407.215 0.280 ;
    END
  END gpio_loopback_zero[57]
  PIN gpio_loopback_zero[58]
    DIRECTION INPUT ;
    USE SIGNAL ;
    PORT
      LAYER met2 ;
        RECT 4954.800 -2.000 4955.060 0.280 ;
    END
  END gpio_loopback_zero[58]
  PIN gpio_loopback_zero[59]
    DIRECTION INPUT ;
    USE SIGNAL ;
    PORT
      LAYER met2 ;
        RECT 5228.825 -2.000 5229.085 0.280 ;
    END
  END gpio_loopback_zero[59]
  PIN gpio_loopback_zero[5]
    DIRECTION INPUT ;
    USE SIGNAL ;
    PORT
      LAYER met3 ;
        RECT 6754.330 1515.030 6756.630 1515.340 ;
    END
  END gpio_loopback_zero[5]
  PIN gpio_loopback_zero[60]
    DIRECTION INPUT ;
    USE SIGNAL ;
    PORT
      LAYER met2 ;
        RECT 5502.890 -2.000 5503.150 0.280 ;
    END
  END gpio_loopback_zero[60]
  PIN gpio_loopback_zero[61]
    DIRECTION INPUT ;
    USE SIGNAL ;
    PORT
      LAYER met2 ;
        RECT 5776.890 -2.000 5777.150 0.280 ;
    END
  END gpio_loopback_zero[61]
  PIN gpio_loopback_zero[62]
    DIRECTION INPUT ;
    USE SIGNAL ;
    PORT
      LAYER met2 ;
        RECT 6051.175 -2.000 6051.435 0.280 ;
    END
  END gpio_loopback_zero[62]
  PIN gpio_loopback_zero[6]
    DIRECTION INPUT ;
    USE SIGNAL ;
    PORT
      LAYER met3 ;
        RECT 6754.330 1740.030 6756.630 1740.340 ;
    END
  END gpio_loopback_zero[6]
  PIN gpio_loopback_zero[7]
    DIRECTION INPUT ;
    USE SIGNAL ;
    PORT
      LAYER met3 ;
        RECT 6754.330 2625.030 6756.630 2625.340 ;
    END
  END gpio_loopback_zero[7]
  PIN gpio_loopback_zero[8]
    DIRECTION INPUT ;
    USE SIGNAL ;
    PORT
      LAYER met3 ;
        RECT 6754.330 2850.030 6756.630 2850.340 ;
    END
  END gpio_loopback_zero[8]
  PIN gpio_loopback_zero[9]
    DIRECTION INPUT ;
    USE SIGNAL ;
    PORT
      LAYER met3 ;
        RECT 6754.330 3075.030 6756.630 3075.340 ;
    END
  END gpio_loopback_zero[9]
  PIN gpio_oeb[0]
    DIRECTION OUTPUT ;
    USE SIGNAL ;
    PORT
      LAYER met3 ;
        RECT 6754.330 364.760 6756.630 365.110 ;
    END
  END gpio_oeb[0]
  PIN gpio_oeb[10]
    DIRECTION OUTPUT ;
    USE SIGNAL ;
    PORT
      LAYER met3 ;
        RECT 6754.330 3280.760 6756.630 3281.110 ;
    END
  END gpio_oeb[10]
  PIN gpio_oeb[11]
    DIRECTION OUTPUT ;
    USE SIGNAL ;
    PORT
      LAYER met3 ;
        RECT 6754.330 3505.760 6756.630 3506.110 ;
    END
  END gpio_oeb[11]
  PIN gpio_oeb[12]
    DIRECTION OUTPUT ;
    USE SIGNAL ;
    PORT
      LAYER met3 ;
        RECT 6754.330 3730.760 6756.630 3731.110 ;
    END
  END gpio_oeb[12]
  PIN gpio_oeb[13]
    DIRECTION OUTPUT ;
    USE SIGNAL ;
    PORT
      LAYER met3 ;
        RECT 6754.330 4176.760 6756.630 4177.110 ;
    END
  END gpio_oeb[13]
  PIN gpio_oeb[14]
    DIRECTION OUTPUT ;
    USE SIGNAL ;
    PORT
      LAYER met3 ;
        RECT 6754.330 4622.760 6756.630 4623.110 ;
    END
  END gpio_oeb[14]
  PIN gpio_oeb[15]
    DIRECTION OUTPUT ;
    USE SIGNAL ;
    PORT
      LAYER met2 ;
        RECT 6511.560 4766.350 6511.840 4768.630 ;
    END
  END gpio_oeb[15]
  PIN gpio_oeb[16]
    DIRECTION OUTPUT ;
    USE SIGNAL ;
    PORT
      LAYER met2 ;
        RECT 6002.560 4766.350 6002.840 4768.630 ;
    END
  END gpio_oeb[16]
  PIN gpio_oeb[17]
    DIRECTION OUTPUT ;
    USE SIGNAL ;
    PORT
      LAYER met2 ;
        RECT 5745.560 4766.350 5745.840 4768.630 ;
    END
  END gpio_oeb[17]
  PIN gpio_oeb[18]
    DIRECTION OUTPUT ;
    USE SIGNAL ;
    PORT
      LAYER met2 ;
        RECT 5300.560 4766.350 5300.840 4768.630 ;
    END
  END gpio_oeb[18]
  PIN gpio_oeb[19]
    DIRECTION OUTPUT ;
    USE SIGNAL ;
    PORT
      LAYER met2 ;
        RECT 4791.560 4766.350 4791.840 4768.630 ;
    END
  END gpio_oeb[19]
  PIN gpio_oeb[1]
    DIRECTION OUTPUT ;
    USE SIGNAL ;
    PORT
      LAYER met3 ;
        RECT 6754.330 590.760 6756.630 591.110 ;
    END
  END gpio_oeb[1]
  PIN gpio_oeb[20]
    DIRECTION OUTPUT ;
    USE SIGNAL ;
    PORT
      LAYER met2 ;
        RECT 4533.560 4766.350 4533.840 4768.630 ;
    END
  END gpio_oeb[20]
  PIN gpio_oeb[21]
    DIRECTION OUTPUT ;
    USE SIGNAL ;
    PORT
      LAYER met2 ;
        RECT 4276.560 4766.350 4276.840 4768.630 ;
    END
  END gpio_oeb[21]
  PIN gpio_oeb[22]
    DIRECTION OUTPUT ;
    USE SIGNAL ;
    PORT
      LAYER met2 ;
        RECT 4019.560 4766.350 4019.840 4768.630 ;
    END
  END gpio_oeb[22]
  PIN gpio_oeb[23]
    DIRECTION OUTPUT ;
    USE SIGNAL ;
    PORT
      LAYER met2 ;
        RECT 3762.560 4766.350 3762.840 4768.630 ;
    END
  END gpio_oeb[23]
  PIN gpio_oeb[24]
    DIRECTION OUTPUT ;
    USE SIGNAL ;
    PORT
      LAYER met2 ;
        RECT 3437.560 4766.350 3437.840 4768.630 ;
    END
  END gpio_oeb[24]
  PIN gpio_oeb[25]
    DIRECTION OUTPUT ;
    USE SIGNAL ;
    PORT
      LAYER met2 ;
        RECT 3180.560 4766.350 3180.840 4768.630 ;
    END
  END gpio_oeb[25]
  PIN gpio_oeb[26]
    DIRECTION OUTPUT ;
    USE SIGNAL ;
    PORT
      LAYER met2 ;
        RECT 2923.560 4766.350 2923.840 4768.630 ;
    END
  END gpio_oeb[26]
  PIN gpio_oeb[27]
    DIRECTION OUTPUT ;
    USE SIGNAL ;
    PORT
      LAYER met2 ;
        RECT 2414.560 4766.350 2414.840 4768.630 ;
    END
  END gpio_oeb[27]
  PIN gpio_oeb[28]
    DIRECTION OUTPUT ;
    USE SIGNAL ;
    PORT
      LAYER met2 ;
        RECT 2157.560 4766.350 2157.840 4768.630 ;
    END
  END gpio_oeb[28]
  PIN gpio_oeb[29]
    DIRECTION OUTPUT ;
    USE SIGNAL ;
    PORT
      LAYER met2 ;
        RECT 1712.560 4766.350 1712.840 4768.630 ;
    END
  END gpio_oeb[29]
  PIN gpio_oeb[2]
    DIRECTION OUTPUT ;
    USE SIGNAL ;
    PORT
      LAYER met3 ;
        RECT 6754.330 815.760 6756.630 816.110 ;
    END
  END gpio_oeb[2]
  PIN gpio_oeb[30]
    DIRECTION OUTPUT ;
    USE SIGNAL ;
    PORT
      LAYER met2 ;
        RECT 1203.560 4766.350 1203.840 4768.630 ;
    END
  END gpio_oeb[30]
  PIN gpio_oeb[31]
    DIRECTION OUTPUT ;
    USE SIGNAL ;
    PORT
      LAYER met2 ;
        RECT 945.560 4766.350 945.840 4768.630 ;
    END
  END gpio_oeb[31]
  PIN gpio_oeb[32]
    DIRECTION OUTPUT ;
    USE SIGNAL ;
    PORT
      LAYER met2 ;
        RECT 688.560 4766.350 688.840 4768.630 ;
    END
  END gpio_oeb[32]
  PIN gpio_oeb[33]
    DIRECTION OUTPUT ;
    USE SIGNAL ;
    PORT
      LAYER met2 ;
        RECT 431.560 4766.350 431.840 4768.630 ;
    END
  END gpio_oeb[33]
  PIN gpio_oeb[34]
    DIRECTION OUTPUT ;
    USE SIGNAL ;
    PORT
      LAYER met2 ;
        RECT 174.560 4766.350 174.840 4768.630 ;
    END
  END gpio_oeb[34]
  PIN gpio_oeb[35]
    DIRECTION OUTPUT ;
    USE SIGNAL ;
    PORT
      LAYER met3 ;
        RECT -2.000 4564.520 0.300 4564.870 ;
    END
  END gpio_oeb[35]
  PIN gpio_oeb[36]
    DIRECTION OUTPUT ;
    USE SIGNAL ;
    PORT
      LAYER met3 ;
        RECT -2.000 3715.520 0.300 3715.870 ;
    END
  END gpio_oeb[36]
  PIN gpio_oeb[37]
    DIRECTION OUTPUT ;
    USE SIGNAL ;
    PORT
      LAYER met3 ;
        RECT -2.000 3499.520 0.300 3499.870 ;
    END
  END gpio_oeb[37]
  PIN gpio_oeb[38]
    DIRECTION OUTPUT ;
    USE SIGNAL ;
    PORT
      LAYER met3 ;
        RECT -2.000 3283.520 0.300 3283.870 ;
    END
  END gpio_oeb[38]
  PIN gpio_oeb[39]
    DIRECTION OUTPUT ;
    USE SIGNAL ;
    PORT
      LAYER met3 ;
        RECT -2.000 3067.520 0.300 3067.870 ;
    END
  END gpio_oeb[39]
  PIN gpio_oeb[3]
    DIRECTION OUTPUT ;
    USE SIGNAL ;
    PORT
      LAYER met3 ;
        RECT 6754.330 1041.760 6756.630 1042.110 ;
    END
  END gpio_oeb[3]
  PIN gpio_oeb[40]
    DIRECTION OUTPUT ;
    USE SIGNAL ;
    PORT
      LAYER met3 ;
        RECT -2.000 2851.520 0.300 2851.870 ;
    END
  END gpio_oeb[40]
  PIN gpio_oeb[41]
    DIRECTION OUTPUT ;
    USE SIGNAL ;
    PORT
      LAYER met3 ;
        RECT -2.000 2635.520 0.300 2635.870 ;
    END
  END gpio_oeb[41]
  PIN gpio_oeb[42]
    DIRECTION OUTPUT ;
    USE SIGNAL ;
    PORT
      LAYER met3 ;
        RECT -2.000 2419.520 0.300 2419.870 ;
    END
  END gpio_oeb[42]
  PIN gpio_oeb[43]
    DIRECTION OUTPUT ;
    USE SIGNAL ;
    PORT
      LAYER met3 ;
        RECT -2.000 1781.520 0.300 1781.870 ;
    END
  END gpio_oeb[43]
  PIN gpio_oeb[44]
    DIRECTION OUTPUT ;
    USE SIGNAL ;
    PORT
      LAYER met3 ;
        RECT -2.000 1565.520 0.300 1565.870 ;
    END
  END gpio_oeb[44]
  PIN gpio_oeb[45]
    DIRECTION OUTPUT ;
    USE SIGNAL ;
    PORT
      LAYER met3 ;
        RECT -2.000 1349.520 0.300 1349.870 ;
    END
  END gpio_oeb[45]
  PIN gpio_oeb[46]
    DIRECTION OUTPUT ;
    USE SIGNAL ;
    PORT
      LAYER met3 ;
        RECT -2.000 1133.520 0.300 1133.870 ;
    END
  END gpio_oeb[46]
  PIN gpio_oeb[47]
    DIRECTION OUTPUT ;
    USE SIGNAL ;
    PORT
      LAYER met3 ;
        RECT -2.000 917.520 0.300 917.870 ;
    END
  END gpio_oeb[47]
  PIN gpio_oeb[48]
    DIRECTION OUTPUT ;
    USE SIGNAL ;
    PORT
      LAYER met3 ;
        RECT -2.000 701.520 0.300 701.870 ;
    END
  END gpio_oeb[48]
  PIN gpio_oeb[49]
    DIRECTION OUTPUT ;
    USE SIGNAL ;
    PORT
      LAYER met2 ;
        RECT 796.790 -2.000 797.070 0.280 ;
    END
  END gpio_oeb[49]
  PIN gpio_oeb[4]
    DIRECTION OUTPUT ;
    USE SIGNAL ;
    PORT
      LAYER met3 ;
        RECT 6754.330 1266.760 6756.630 1267.110 ;
    END
  END gpio_oeb[4]
  PIN gpio_oeb[50]
    DIRECTION OUTPUT ;
    USE SIGNAL ;
    PORT
      LAYER met2 ;
        RECT 1339.790 -2.000 1340.070 0.280 ;
    END
  END gpio_oeb[50]
  PIN gpio_oeb[51]
    DIRECTION OUTPUT ;
    USE SIGNAL ;
    PORT
      LAYER met2 ;
        RECT 1613.790 -2.000 1614.070 0.280 ;
    END
  END gpio_oeb[51]
  PIN gpio_oeb[52]
    DIRECTION OUTPUT ;
    USE SIGNAL ;
    PORT
      LAYER met2 ;
        RECT 1887.790 -2.000 1888.070 0.280 ;
    END
  END gpio_oeb[52]
  PIN gpio_oeb[53]
    DIRECTION OUTPUT ;
    USE SIGNAL ;
    PORT
      LAYER met2 ;
        RECT 2161.790 -2.000 2162.070 0.280 ;
    END
  END gpio_oeb[53]
  PIN gpio_oeb[54]
    DIRECTION OUTPUT ;
    USE SIGNAL ;
    PORT
      LAYER met2 ;
        RECT 2435.790 -2.000 2436.070 0.280 ;
    END
  END gpio_oeb[54]
  PIN gpio_oeb[55]
    DIRECTION OUTPUT ;
    USE SIGNAL ;
    PORT
      LAYER met2 ;
        RECT 3250.270 -2.000 3250.550 0.280 ;
    END
  END gpio_oeb[55]
  PIN gpio_oeb[56]
    DIRECTION OUTPUT ;
    USE SIGNAL ;
    PORT
      LAYER met2 ;
        RECT 3524.270 -2.000 3524.550 0.280 ;
    END
  END gpio_oeb[56]
  PIN gpio_oeb[57]
    DIRECTION OUTPUT ;
    USE SIGNAL ;
    PORT
      LAYER met2 ;
        RECT 4384.790 -2.000 4385.070 0.280 ;
    END
  END gpio_oeb[57]
  PIN gpio_oeb[58]
    DIRECTION OUTPUT ;
    USE SIGNAL ;
    PORT
      LAYER met2 ;
        RECT 4927.790 -2.000 4928.070 0.280 ;
    END
  END gpio_oeb[58]
  PIN gpio_oeb[59]
    DIRECTION OUTPUT ;
    USE SIGNAL ;
    PORT
      LAYER met2 ;
        RECT 5201.790 -2.000 5202.070 0.280 ;
    END
  END gpio_oeb[59]
  PIN gpio_oeb[5]
    DIRECTION OUTPUT ;
    USE SIGNAL ;
    PORT
      LAYER met3 ;
        RECT 6754.330 1491.760 6756.630 1492.110 ;
    END
  END gpio_oeb[5]
  PIN gpio_oeb[60]
    DIRECTION OUTPUT ;
    USE SIGNAL ;
    PORT
      LAYER met2 ;
        RECT 5475.790 -2.000 5476.070 0.280 ;
    END
  END gpio_oeb[60]
  PIN gpio_oeb[61]
    DIRECTION OUTPUT ;
    USE SIGNAL ;
    PORT
      LAYER met2 ;
        RECT 5749.790 -2.000 5750.070 0.280 ;
    END
  END gpio_oeb[61]
  PIN gpio_oeb[62]
    DIRECTION OUTPUT ;
    USE SIGNAL ;
    PORT
      LAYER met2 ;
        RECT 6023.790 -2.000 6024.070 0.280 ;
    END
  END gpio_oeb[62]
  PIN gpio_oeb[6]
    DIRECTION OUTPUT ;
    USE SIGNAL ;
    PORT
      LAYER met3 ;
        RECT 6754.330 1717.760 6756.630 1718.110 ;
    END
  END gpio_oeb[6]
  PIN gpio_oeb[7]
    DIRECTION OUTPUT ;
    USE SIGNAL ;
    PORT
      LAYER met3 ;
        RECT 6754.330 2603.760 6756.630 2604.110 ;
    END
  END gpio_oeb[7]
  PIN gpio_oeb[8]
    DIRECTION OUTPUT ;
    USE SIGNAL ;
    PORT
      LAYER met3 ;
        RECT 6754.330 2829.760 6756.630 2830.110 ;
    END
  END gpio_oeb[8]
  PIN gpio_oeb[9]
    DIRECTION OUTPUT ;
    USE SIGNAL ;
    PORT
      LAYER met3 ;
        RECT 6754.330 3054.760 6756.630 3055.110 ;
    END
  END gpio_oeb[9]
  PIN gpio_out[0]
    DIRECTION OUTPUT ;
    USE SIGNAL ;
    PORT
      LAYER met3 ;
        RECT 6754.330 349.120 6756.630 349.470 ;
    END
  END gpio_out[0]
  PIN gpio_out[10]
    DIRECTION OUTPUT ;
    USE SIGNAL ;
    PORT
      LAYER met3 ;
        RECT 6754.330 3265.120 6756.630 3265.470 ;
    END
  END gpio_out[10]
  PIN gpio_out[11]
    DIRECTION OUTPUT ;
    USE SIGNAL ;
    PORT
      LAYER met3 ;
        RECT 6754.330 3490.120 6756.630 3490.470 ;
    END
  END gpio_out[11]
  PIN gpio_out[12]
    DIRECTION OUTPUT ;
    USE SIGNAL ;
    PORT
      LAYER met3 ;
        RECT 6754.330 3715.120 6756.630 3715.470 ;
    END
  END gpio_out[12]
  PIN gpio_out[13]
    DIRECTION OUTPUT ;
    USE SIGNAL ;
    PORT
      LAYER met3 ;
        RECT 6754.330 4161.120 6756.630 4161.470 ;
    END
  END gpio_out[13]
  PIN gpio_out[14]
    DIRECTION OUTPUT ;
    USE SIGNAL ;
    PORT
      LAYER met3 ;
        RECT 6754.330 4607.120 6756.630 4607.470 ;
    END
  END gpio_out[14]
  PIN gpio_out[15]
    DIRECTION OUTPUT ;
    USE SIGNAL ;
    PORT
      LAYER met2 ;
        RECT 6527.200 4766.350 6527.480 4768.630 ;
    END
  END gpio_out[15]
  PIN gpio_out[16]
    DIRECTION OUTPUT ;
    USE SIGNAL ;
    PORT
      LAYER met2 ;
        RECT 6018.200 4766.350 6018.480 4768.630 ;
    END
  END gpio_out[16]
  PIN gpio_out[17]
    DIRECTION OUTPUT ;
    USE SIGNAL ;
    PORT
      LAYER met2 ;
        RECT 5761.200 4766.350 5761.480 4768.630 ;
    END
  END gpio_out[17]
  PIN gpio_out[18]
    DIRECTION OUTPUT ;
    USE SIGNAL ;
    PORT
      LAYER met2 ;
        RECT 5316.200 4766.350 5316.480 4768.630 ;
    END
  END gpio_out[18]
  PIN gpio_out[19]
    DIRECTION OUTPUT ;
    USE SIGNAL ;
    PORT
      LAYER met2 ;
        RECT 4807.200 4766.350 4807.480 4768.630 ;
    END
  END gpio_out[19]
  PIN gpio_out[1]
    DIRECTION OUTPUT ;
    USE SIGNAL ;
    PORT
      LAYER met3 ;
        RECT 6754.330 575.120 6756.630 575.470 ;
    END
  END gpio_out[1]
  PIN gpio_out[20]
    DIRECTION OUTPUT ;
    USE SIGNAL ;
    PORT
      LAYER met2 ;
        RECT 4549.200 4766.350 4549.480 4768.630 ;
    END
  END gpio_out[20]
  PIN gpio_out[21]
    DIRECTION OUTPUT ;
    USE SIGNAL ;
    PORT
      LAYER met2 ;
        RECT 4292.200 4766.350 4292.480 4768.630 ;
    END
  END gpio_out[21]
  PIN gpio_out[22]
    DIRECTION OUTPUT ;
    USE SIGNAL ;
    PORT
      LAYER met2 ;
        RECT 4035.200 4766.350 4035.480 4768.630 ;
    END
  END gpio_out[22]
  PIN gpio_out[23]
    DIRECTION OUTPUT ;
    USE SIGNAL ;
    PORT
      LAYER met2 ;
        RECT 3778.200 4766.350 3778.480 4768.630 ;
    END
  END gpio_out[23]
  PIN gpio_out[24]
    DIRECTION OUTPUT ;
    USE SIGNAL ;
    PORT
      LAYER met2 ;
        RECT 3453.200 4766.350 3453.480 4768.630 ;
    END
  END gpio_out[24]
  PIN gpio_out[25]
    DIRECTION OUTPUT ;
    USE SIGNAL ;
    PORT
      LAYER met2 ;
        RECT 3196.200 4766.350 3196.480 4768.630 ;
    END
  END gpio_out[25]
  PIN gpio_out[26]
    DIRECTION OUTPUT ;
    USE SIGNAL ;
    PORT
      LAYER met2 ;
        RECT 2939.200 4766.350 2939.480 4768.630 ;
    END
  END gpio_out[26]
  PIN gpio_out[27]
    DIRECTION OUTPUT ;
    USE SIGNAL ;
    PORT
      LAYER met2 ;
        RECT 2430.200 4766.350 2430.480 4768.630 ;
    END
  END gpio_out[27]
  PIN gpio_out[28]
    DIRECTION OUTPUT ;
    USE SIGNAL ;
    PORT
      LAYER met2 ;
        RECT 2173.200 4766.350 2173.480 4768.630 ;
    END
  END gpio_out[28]
  PIN gpio_out[29]
    DIRECTION OUTPUT ;
    USE SIGNAL ;
    PORT
      LAYER met2 ;
        RECT 1728.200 4766.350 1728.480 4768.630 ;
    END
  END gpio_out[29]
  PIN gpio_out[2]
    DIRECTION OUTPUT ;
    USE SIGNAL ;
    PORT
      LAYER met3 ;
        RECT 6754.330 800.120 6756.630 800.470 ;
    END
  END gpio_out[2]
  PIN gpio_out[30]
    DIRECTION OUTPUT ;
    USE SIGNAL ;
    PORT
      LAYER met2 ;
        RECT 1219.200 4766.350 1219.480 4768.630 ;
    END
  END gpio_out[30]
  PIN gpio_out[31]
    DIRECTION OUTPUT ;
    USE SIGNAL ;
    PORT
      LAYER met2 ;
        RECT 961.200 4766.350 961.480 4768.630 ;
    END
  END gpio_out[31]
  PIN gpio_out[32]
    DIRECTION OUTPUT ;
    USE SIGNAL ;
    PORT
      LAYER met2 ;
        RECT 704.200 4766.350 704.480 4768.630 ;
    END
  END gpio_out[32]
  PIN gpio_out[33]
    DIRECTION OUTPUT ;
    USE SIGNAL ;
    PORT
      LAYER met2 ;
        RECT 447.200 4766.350 447.480 4768.630 ;
    END
  END gpio_out[33]
  PIN gpio_out[34]
    DIRECTION OUTPUT ;
    USE SIGNAL ;
    PORT
      LAYER met2 ;
        RECT 190.200 4766.350 190.480 4768.630 ;
    END
  END gpio_out[34]
  PIN gpio_out[35]
    DIRECTION OUTPUT ;
    USE SIGNAL ;
    ANTENNADIFFAREA 0.445500 ;
    PORT
      LAYER met3 ;
        RECT -2.000 4580.160 0.300 4580.510 ;
    END
  END gpio_out[35]
  PIN gpio_out[36]
    DIRECTION OUTPUT ;
    USE SIGNAL ;
    ANTENNADIFFAREA 0.445500 ;
    PORT
      LAYER met3 ;
        RECT -2.000 3731.160 0.300 3731.510 ;
    END
  END gpio_out[36]
  PIN gpio_out[37]
    DIRECTION OUTPUT ;
    USE SIGNAL ;
    ANTENNADIFFAREA 0.445500 ;
    PORT
      LAYER met3 ;
        RECT -2.000 3515.160 0.300 3515.510 ;
    END
  END gpio_out[37]
  PIN gpio_out[38]
    DIRECTION OUTPUT ;
    USE SIGNAL ;
    ANTENNADIFFAREA 0.445500 ;
    PORT
      LAYER met3 ;
        RECT -2.000 3299.160 0.300 3299.510 ;
    END
  END gpio_out[38]
  PIN gpio_out[39]
    DIRECTION OUTPUT ;
    USE SIGNAL ;
    ANTENNADIFFAREA 0.445500 ;
    PORT
      LAYER met3 ;
        RECT -2.000 3083.160 0.300 3083.510 ;
    END
  END gpio_out[39]
  PIN gpio_out[3]
    DIRECTION OUTPUT ;
    USE SIGNAL ;
    PORT
      LAYER met3 ;
        RECT 6754.330 1026.120 6756.630 1026.470 ;
    END
  END gpio_out[3]
  PIN gpio_out[40]
    DIRECTION OUTPUT ;
    USE SIGNAL ;
    ANTENNADIFFAREA 0.445500 ;
    PORT
      LAYER met3 ;
        RECT -2.000 2867.160 0.300 2867.510 ;
    END
  END gpio_out[40]
  PIN gpio_out[41]
    DIRECTION OUTPUT ;
    USE SIGNAL ;
    ANTENNADIFFAREA 0.445500 ;
    PORT
      LAYER met3 ;
        RECT -2.000 2651.160 0.300 2651.510 ;
    END
  END gpio_out[41]
  PIN gpio_out[42]
    DIRECTION OUTPUT ;
    USE SIGNAL ;
    ANTENNADIFFAREA 0.445500 ;
    PORT
      LAYER met3 ;
        RECT -2.000 2435.160 0.300 2435.510 ;
    END
  END gpio_out[42]
  PIN gpio_out[43]
    DIRECTION OUTPUT ;
    USE SIGNAL ;
    ANTENNADIFFAREA 0.445500 ;
    PORT
      LAYER met3 ;
        RECT -2.000 1797.160 0.300 1797.510 ;
    END
  END gpio_out[43]
  PIN gpio_out[44]
    DIRECTION OUTPUT ;
    USE SIGNAL ;
    ANTENNADIFFAREA 0.445500 ;
    PORT
      LAYER met3 ;
        RECT -2.000 1581.160 0.300 1581.510 ;
    END
  END gpio_out[44]
  PIN gpio_out[45]
    DIRECTION OUTPUT ;
    USE SIGNAL ;
    ANTENNADIFFAREA 0.445500 ;
    PORT
      LAYER met3 ;
        RECT -2.000 1365.160 0.300 1365.510 ;
    END
  END gpio_out[45]
  PIN gpio_out[46]
    DIRECTION OUTPUT ;
    USE SIGNAL ;
    ANTENNADIFFAREA 0.445500 ;
    PORT
      LAYER met3 ;
        RECT -2.000 1149.160 0.300 1149.510 ;
    END
  END gpio_out[46]
  PIN gpio_out[47]
    DIRECTION OUTPUT ;
    USE SIGNAL ;
    PORT
      LAYER met3 ;
        RECT -2.000 933.160 0.300 933.510 ;
    END
  END gpio_out[47]
  PIN gpio_out[48]
    DIRECTION OUTPUT ;
    USE SIGNAL ;
    PORT
      LAYER met3 ;
        RECT -2.000 717.160 0.300 717.510 ;
    END
  END gpio_out[48]
  PIN gpio_out[49]
    DIRECTION OUTPUT ;
    USE SIGNAL ;
    PORT
      LAYER met2 ;
        RECT 781.150 -2.000 781.430 0.280 ;
    END
  END gpio_out[49]
  PIN gpio_out[4]
    DIRECTION OUTPUT ;
    USE SIGNAL ;
    PORT
      LAYER met3 ;
        RECT 6754.330 1251.120 6756.630 1251.470 ;
    END
  END gpio_out[4]
  PIN gpio_out[50]
    DIRECTION OUTPUT ;
    USE SIGNAL ;
    PORT
      LAYER met2 ;
        RECT 1324.150 -2.000 1324.430 0.280 ;
    END
  END gpio_out[50]
  PIN gpio_out[51]
    DIRECTION OUTPUT ;
    USE SIGNAL ;
    PORT
      LAYER met2 ;
        RECT 1598.150 -2.000 1598.430 0.280 ;
    END
  END gpio_out[51]
  PIN gpio_out[52]
    DIRECTION OUTPUT ;
    USE SIGNAL ;
    PORT
      LAYER met2 ;
        RECT 1872.150 -2.000 1872.430 0.280 ;
    END
  END gpio_out[52]
  PIN gpio_out[53]
    DIRECTION OUTPUT ;
    USE SIGNAL ;
    PORT
      LAYER met2 ;
        RECT 2146.150 -2.000 2146.430 0.280 ;
    END
  END gpio_out[53]
  PIN gpio_out[54]
    DIRECTION OUTPUT ;
    USE SIGNAL ;
    PORT
      LAYER met2 ;
        RECT 2420.150 -2.000 2420.430 0.280 ;
    END
  END gpio_out[54]
  PIN gpio_out[55]
    DIRECTION OUTPUT ;
    USE SIGNAL ;
    PORT
      LAYER met2 ;
        RECT 3234.630 -2.000 3234.910 0.280 ;
    END
  END gpio_out[55]
  PIN gpio_out[56]
    DIRECTION OUTPUT ;
    USE SIGNAL ;
    PORT
      LAYER met2 ;
        RECT 3508.630 -2.000 3508.910 0.280 ;
    END
  END gpio_out[56]
  PIN gpio_out[57]
    DIRECTION OUTPUT ;
    USE SIGNAL ;
    PORT
      LAYER met2 ;
        RECT 4369.150 -2.000 4369.430 0.280 ;
    END
  END gpio_out[57]
  PIN gpio_out[58]
    DIRECTION OUTPUT ;
    USE SIGNAL ;
    PORT
      LAYER met2 ;
        RECT 4912.150 -2.000 4912.430 0.280 ;
    END
  END gpio_out[58]
  PIN gpio_out[59]
    DIRECTION OUTPUT ;
    USE SIGNAL ;
    PORT
      LAYER met2 ;
        RECT 5186.150 -2.000 5186.430 0.280 ;
    END
  END gpio_out[59]
  PIN gpio_out[5]
    DIRECTION OUTPUT ;
    USE SIGNAL ;
    PORT
      LAYER met3 ;
        RECT 6754.330 1476.120 6756.630 1476.470 ;
    END
  END gpio_out[5]
  PIN gpio_out[60]
    DIRECTION OUTPUT ;
    USE SIGNAL ;
    PORT
      LAYER met2 ;
        RECT 5460.150 -2.000 5460.430 0.280 ;
    END
  END gpio_out[60]
  PIN gpio_out[61]
    DIRECTION OUTPUT ;
    USE SIGNAL ;
    PORT
      LAYER met2 ;
        RECT 5734.150 -2.000 5734.430 0.280 ;
    END
  END gpio_out[61]
  PIN gpio_out[62]
    DIRECTION OUTPUT ;
    USE SIGNAL ;
    PORT
      LAYER met2 ;
        RECT 6008.150 -2.000 6008.430 0.280 ;
    END
  END gpio_out[62]
  PIN gpio_out[6]
    DIRECTION OUTPUT ;
    USE SIGNAL ;
    PORT
      LAYER met3 ;
        RECT 6754.330 1702.120 6756.630 1702.470 ;
    END
  END gpio_out[6]
  PIN gpio_out[7]
    DIRECTION OUTPUT ;
    USE SIGNAL ;
    PORT
      LAYER met3 ;
        RECT 6754.330 2588.120 6756.630 2588.470 ;
    END
  END gpio_out[7]
  PIN gpio_out[8]
    DIRECTION OUTPUT ;
    USE SIGNAL ;
    PORT
      LAYER met3 ;
        RECT 6754.330 2814.120 6756.630 2814.470 ;
    END
  END gpio_out[8]
  PIN gpio_out[9]
    DIRECTION OUTPUT ;
    USE SIGNAL ;
    PORT
      LAYER met3 ;
        RECT 6754.330 3039.120 6756.630 3039.470 ;
    END
  END gpio_out[9]
  PIN gpio_slow_sel[0]
    DIRECTION OUTPUT ;
    USE SIGNAL ;
    PORT
      LAYER met3 ;
        RECT 6754.330 303.120 6756.630 303.470 ;
    END
  END gpio_slow_sel[0]
  PIN gpio_slow_sel[10]
    DIRECTION OUTPUT ;
    USE SIGNAL ;
    PORT
      LAYER met3 ;
        RECT 6754.330 3219.120 6756.630 3219.470 ;
    END
  END gpio_slow_sel[10]
  PIN gpio_slow_sel[11]
    DIRECTION OUTPUT ;
    USE SIGNAL ;
    PORT
      LAYER met3 ;
        RECT 6754.330 3444.120 6756.630 3444.470 ;
    END
  END gpio_slow_sel[11]
  PIN gpio_slow_sel[12]
    DIRECTION OUTPUT ;
    USE SIGNAL ;
    PORT
      LAYER met3 ;
        RECT 6754.330 3669.120 6756.630 3669.470 ;
    END
  END gpio_slow_sel[12]
  PIN gpio_slow_sel[13]
    DIRECTION OUTPUT ;
    USE SIGNAL ;
    PORT
      LAYER met3 ;
        RECT 6754.330 4115.120 6756.630 4115.470 ;
    END
  END gpio_slow_sel[13]
  PIN gpio_slow_sel[14]
    DIRECTION OUTPUT ;
    USE SIGNAL ;
    PORT
      LAYER met3 ;
        RECT 6754.330 4561.120 6756.630 4561.470 ;
    END
  END gpio_slow_sel[14]
  PIN gpio_slow_sel[15]
    DIRECTION OUTPUT ;
    USE SIGNAL ;
    PORT
      LAYER met2 ;
        RECT 6573.200 4766.350 6573.480 4768.630 ;
    END
  END gpio_slow_sel[15]
  PIN gpio_slow_sel[16]
    DIRECTION OUTPUT ;
    USE SIGNAL ;
    PORT
      LAYER met2 ;
        RECT 6064.200 4766.350 6064.480 4768.630 ;
    END
  END gpio_slow_sel[16]
  PIN gpio_slow_sel[17]
    DIRECTION OUTPUT ;
    USE SIGNAL ;
    PORT
      LAYER met2 ;
        RECT 5807.200 4766.350 5807.480 4768.630 ;
    END
  END gpio_slow_sel[17]
  PIN gpio_slow_sel[18]
    DIRECTION OUTPUT ;
    USE SIGNAL ;
    PORT
      LAYER met2 ;
        RECT 5362.200 4766.350 5362.480 4768.630 ;
    END
  END gpio_slow_sel[18]
  PIN gpio_slow_sel[19]
    DIRECTION OUTPUT ;
    USE SIGNAL ;
    PORT
      LAYER met2 ;
        RECT 4853.200 4766.350 4853.480 4768.630 ;
    END
  END gpio_slow_sel[19]
  PIN gpio_slow_sel[1]
    DIRECTION OUTPUT ;
    USE SIGNAL ;
    PORT
      LAYER met3 ;
        RECT 6754.330 529.120 6756.630 529.470 ;
    END
  END gpio_slow_sel[1]
  PIN gpio_slow_sel[20]
    DIRECTION OUTPUT ;
    USE SIGNAL ;
    PORT
      LAYER met2 ;
        RECT 4595.200 4766.350 4595.480 4768.630 ;
    END
  END gpio_slow_sel[20]
  PIN gpio_slow_sel[21]
    DIRECTION OUTPUT ;
    USE SIGNAL ;
    PORT
      LAYER met2 ;
        RECT 4338.200 4766.350 4338.480 4768.630 ;
    END
  END gpio_slow_sel[21]
  PIN gpio_slow_sel[22]
    DIRECTION OUTPUT ;
    USE SIGNAL ;
    PORT
      LAYER met2 ;
        RECT 4081.200 4766.350 4081.480 4768.630 ;
    END
  END gpio_slow_sel[22]
  PIN gpio_slow_sel[23]
    DIRECTION OUTPUT ;
    USE SIGNAL ;
    PORT
      LAYER met2 ;
        RECT 3824.200 4766.350 3824.480 4768.630 ;
    END
  END gpio_slow_sel[23]
  PIN gpio_slow_sel[24]
    DIRECTION OUTPUT ;
    USE SIGNAL ;
    PORT
      LAYER met2 ;
        RECT 3499.200 4766.350 3499.480 4768.630 ;
    END
  END gpio_slow_sel[24]
  PIN gpio_slow_sel[25]
    DIRECTION OUTPUT ;
    USE SIGNAL ;
    PORT
      LAYER met2 ;
        RECT 3242.200 4766.350 3242.480 4768.630 ;
    END
  END gpio_slow_sel[25]
  PIN gpio_slow_sel[26]
    DIRECTION OUTPUT ;
    USE SIGNAL ;
    PORT
      LAYER met2 ;
        RECT 2985.200 4766.350 2985.480 4768.630 ;
    END
  END gpio_slow_sel[26]
  PIN gpio_slow_sel[27]
    DIRECTION OUTPUT ;
    USE SIGNAL ;
    PORT
      LAYER met2 ;
        RECT 2476.200 4766.350 2476.480 4768.630 ;
    END
  END gpio_slow_sel[27]
  PIN gpio_slow_sel[28]
    DIRECTION OUTPUT ;
    USE SIGNAL ;
    PORT
      LAYER met2 ;
        RECT 2219.200 4766.350 2219.480 4768.630 ;
    END
  END gpio_slow_sel[28]
  PIN gpio_slow_sel[29]
    DIRECTION OUTPUT ;
    USE SIGNAL ;
    PORT
      LAYER met2 ;
        RECT 1774.200 4766.350 1774.480 4768.630 ;
    END
  END gpio_slow_sel[29]
  PIN gpio_slow_sel[2]
    DIRECTION OUTPUT ;
    USE SIGNAL ;
    PORT
      LAYER met3 ;
        RECT 6754.330 754.120 6756.630 754.470 ;
    END
  END gpio_slow_sel[2]
  PIN gpio_slow_sel[30]
    DIRECTION OUTPUT ;
    USE SIGNAL ;
    PORT
      LAYER met2 ;
        RECT 1265.200 4766.350 1265.480 4768.630 ;
    END
  END gpio_slow_sel[30]
  PIN gpio_slow_sel[31]
    DIRECTION OUTPUT ;
    USE SIGNAL ;
    PORT
      LAYER met2 ;
        RECT 1007.200 4766.350 1007.480 4768.630 ;
    END
  END gpio_slow_sel[31]
  PIN gpio_slow_sel[32]
    DIRECTION OUTPUT ;
    USE SIGNAL ;
    PORT
      LAYER met2 ;
        RECT 750.200 4766.350 750.480 4768.630 ;
    END
  END gpio_slow_sel[32]
  PIN gpio_slow_sel[33]
    DIRECTION OUTPUT ;
    USE SIGNAL ;
    PORT
      LAYER met2 ;
        RECT 493.200 4766.350 493.480 4768.630 ;
    END
  END gpio_slow_sel[33]
  PIN gpio_slow_sel[34]
    DIRECTION OUTPUT ;
    USE SIGNAL ;
    PORT
      LAYER met2 ;
        RECT 236.200 4766.350 236.480 4768.630 ;
    END
  END gpio_slow_sel[34]
  PIN gpio_slow_sel[35]
    DIRECTION OUTPUT ;
    USE SIGNAL ;
    PORT
      LAYER met3 ;
        RECT -2.000 4626.160 0.300 4626.510 ;
    END
  END gpio_slow_sel[35]
  PIN gpio_slow_sel[36]
    DIRECTION OUTPUT ;
    USE SIGNAL ;
    PORT
      LAYER met3 ;
        RECT -2.000 3777.160 0.300 3777.510 ;
    END
  END gpio_slow_sel[36]
  PIN gpio_slow_sel[37]
    DIRECTION OUTPUT ;
    USE SIGNAL ;
    PORT
      LAYER met3 ;
        RECT -2.000 3561.160 0.300 3561.510 ;
    END
  END gpio_slow_sel[37]
  PIN gpio_slow_sel[38]
    DIRECTION OUTPUT ;
    USE SIGNAL ;
    PORT
      LAYER met3 ;
        RECT -2.000 3345.160 0.300 3345.510 ;
    END
  END gpio_slow_sel[38]
  PIN gpio_slow_sel[39]
    DIRECTION OUTPUT ;
    USE SIGNAL ;
    PORT
      LAYER met3 ;
        RECT -2.000 3129.160 0.300 3129.510 ;
    END
  END gpio_slow_sel[39]
  PIN gpio_slow_sel[3]
    DIRECTION OUTPUT ;
    USE SIGNAL ;
    PORT
      LAYER met3 ;
        RECT 6754.330 980.120 6756.630 980.470 ;
    END
  END gpio_slow_sel[3]
  PIN gpio_slow_sel[40]
    DIRECTION OUTPUT ;
    USE SIGNAL ;
    PORT
      LAYER met3 ;
        RECT -2.000 2913.160 0.300 2913.510 ;
    END
  END gpio_slow_sel[40]
  PIN gpio_slow_sel[41]
    DIRECTION OUTPUT ;
    USE SIGNAL ;
    PORT
      LAYER met3 ;
        RECT -2.000 2697.160 0.300 2697.510 ;
    END
  END gpio_slow_sel[41]
  PIN gpio_slow_sel[42]
    DIRECTION OUTPUT ;
    USE SIGNAL ;
    PORT
      LAYER met3 ;
        RECT -2.000 2481.160 0.300 2481.510 ;
    END
  END gpio_slow_sel[42]
  PIN gpio_slow_sel[43]
    DIRECTION OUTPUT ;
    USE SIGNAL ;
    PORT
      LAYER met3 ;
        RECT -2.000 1843.160 0.300 1843.510 ;
    END
  END gpio_slow_sel[43]
  PIN gpio_slow_sel[44]
    DIRECTION OUTPUT ;
    USE SIGNAL ;
    PORT
      LAYER met3 ;
        RECT -2.000 1627.160 0.300 1627.510 ;
    END
  END gpio_slow_sel[44]
  PIN gpio_slow_sel[45]
    DIRECTION OUTPUT ;
    USE SIGNAL ;
    PORT
      LAYER met3 ;
        RECT -2.000 1411.160 0.300 1411.510 ;
    END
  END gpio_slow_sel[45]
  PIN gpio_slow_sel[46]
    DIRECTION OUTPUT ;
    USE SIGNAL ;
    PORT
      LAYER met3 ;
        RECT -2.000 1195.160 0.300 1195.510 ;
    END
  END gpio_slow_sel[46]
  PIN gpio_slow_sel[47]
    DIRECTION OUTPUT ;
    USE SIGNAL ;
    PORT
      LAYER met3 ;
        RECT -2.000 979.160 0.300 979.510 ;
    END
  END gpio_slow_sel[47]
  PIN gpio_slow_sel[48]
    DIRECTION OUTPUT ;
    USE SIGNAL ;
    PORT
      LAYER met3 ;
        RECT -2.000 763.160 0.300 763.510 ;
    END
  END gpio_slow_sel[48]
  PIN gpio_slow_sel[49]
    DIRECTION OUTPUT ;
    USE SIGNAL ;
    PORT
      LAYER met2 ;
        RECT 735.150 -2.000 735.430 0.280 ;
    END
  END gpio_slow_sel[49]
  PIN gpio_slow_sel[4]
    DIRECTION OUTPUT ;
    USE SIGNAL ;
    PORT
      LAYER met3 ;
        RECT 6754.330 1205.120 6756.630 1205.470 ;
    END
  END gpio_slow_sel[4]
  PIN gpio_slow_sel[50]
    DIRECTION OUTPUT ;
    USE SIGNAL ;
    PORT
      LAYER met2 ;
        RECT 1278.150 -2.000 1278.430 0.280 ;
    END
  END gpio_slow_sel[50]
  PIN gpio_slow_sel[51]
    DIRECTION OUTPUT ;
    USE SIGNAL ;
    PORT
      LAYER met2 ;
        RECT 1552.150 -2.000 1552.430 0.280 ;
    END
  END gpio_slow_sel[51]
  PIN gpio_slow_sel[52]
    DIRECTION OUTPUT ;
    USE SIGNAL ;
    PORT
      LAYER met2 ;
        RECT 1826.150 -2.000 1826.430 0.280 ;
    END
  END gpio_slow_sel[52]
  PIN gpio_slow_sel[53]
    DIRECTION OUTPUT ;
    USE SIGNAL ;
    PORT
      LAYER met2 ;
        RECT 2100.150 -2.000 2100.430 0.280 ;
    END
  END gpio_slow_sel[53]
  PIN gpio_slow_sel[54]
    DIRECTION OUTPUT ;
    USE SIGNAL ;
    PORT
      LAYER met2 ;
        RECT 2374.150 -2.000 2374.430 0.280 ;
    END
  END gpio_slow_sel[54]
  PIN gpio_slow_sel[55]
    DIRECTION OUTPUT ;
    USE SIGNAL ;
    PORT
      LAYER met2 ;
        RECT 3188.630 -2.000 3188.910 0.280 ;
    END
  END gpio_slow_sel[55]
  PIN gpio_slow_sel[56]
    DIRECTION OUTPUT ;
    USE SIGNAL ;
    PORT
      LAYER met2 ;
        RECT 3462.630 -2.000 3462.910 0.280 ;
    END
  END gpio_slow_sel[56]
  PIN gpio_slow_sel[57]
    DIRECTION OUTPUT ;
    USE SIGNAL ;
    PORT
      LAYER met2 ;
        RECT 4323.150 -2.000 4323.430 0.280 ;
    END
  END gpio_slow_sel[57]
  PIN gpio_slow_sel[58]
    DIRECTION OUTPUT ;
    USE SIGNAL ;
    PORT
      LAYER met2 ;
        RECT 4866.150 -2.000 4866.430 0.280 ;
    END
  END gpio_slow_sel[58]
  PIN gpio_slow_sel[59]
    DIRECTION OUTPUT ;
    USE SIGNAL ;
    PORT
      LAYER met2 ;
        RECT 5140.150 -2.000 5140.430 0.280 ;
    END
  END gpio_slow_sel[59]
  PIN gpio_slow_sel[5]
    DIRECTION OUTPUT ;
    USE SIGNAL ;
    PORT
      LAYER met3 ;
        RECT 6754.330 1430.120 6756.630 1430.470 ;
    END
  END gpio_slow_sel[5]
  PIN gpio_slow_sel[60]
    DIRECTION OUTPUT ;
    USE SIGNAL ;
    PORT
      LAYER met2 ;
        RECT 5414.150 -2.000 5414.430 0.280 ;
    END
  END gpio_slow_sel[60]
  PIN gpio_slow_sel[61]
    DIRECTION OUTPUT ;
    USE SIGNAL ;
    PORT
      LAYER met2 ;
        RECT 5688.150 -2.000 5688.430 0.280 ;
    END
  END gpio_slow_sel[61]
  PIN gpio_slow_sel[62]
    DIRECTION OUTPUT ;
    USE SIGNAL ;
    PORT
      LAYER met2 ;
        RECT 5962.150 -2.000 5962.430 0.280 ;
    END
  END gpio_slow_sel[62]
  PIN gpio_slow_sel[6]
    DIRECTION OUTPUT ;
    USE SIGNAL ;
    PORT
      LAYER met3 ;
        RECT 6754.330 1656.120 6756.630 1656.470 ;
    END
  END gpio_slow_sel[6]
  PIN gpio_slow_sel[7]
    DIRECTION OUTPUT ;
    USE SIGNAL ;
    PORT
      LAYER met3 ;
        RECT 6754.330 2542.120 6756.630 2542.470 ;
    END
  END gpio_slow_sel[7]
  PIN gpio_slow_sel[8]
    DIRECTION OUTPUT ;
    USE SIGNAL ;
    PORT
      LAYER met3 ;
        RECT 6754.330 2768.120 6756.630 2768.470 ;
    END
  END gpio_slow_sel[8]
  PIN gpio_slow_sel[9]
    DIRECTION OUTPUT ;
    USE SIGNAL ;
    PORT
      LAYER met3 ;
        RECT 6754.330 2993.120 6756.630 2993.470 ;
    END
  END gpio_slow_sel[9]
  PIN gpio_vtrip_sel[0]
    DIRECTION OUTPUT ;
    USE SIGNAL ;
    PORT
      LAYER met3 ;
        RECT 6754.330 358.320 6756.630 358.670 ;
    END
  END gpio_vtrip_sel[0]
  PIN gpio_vtrip_sel[10]
    DIRECTION OUTPUT ;
    USE SIGNAL ;
    PORT
      LAYER met3 ;
        RECT 6754.330 3274.320 6756.630 3274.670 ;
    END
  END gpio_vtrip_sel[10]
  PIN gpio_vtrip_sel[11]
    DIRECTION OUTPUT ;
    USE SIGNAL ;
    PORT
      LAYER met3 ;
        RECT 6754.330 3499.320 6756.630 3499.670 ;
    END
  END gpio_vtrip_sel[11]
  PIN gpio_vtrip_sel[12]
    DIRECTION OUTPUT ;
    USE SIGNAL ;
    PORT
      LAYER met3 ;
        RECT 6754.330 3724.320 6756.630 3724.670 ;
    END
  END gpio_vtrip_sel[12]
  PIN gpio_vtrip_sel[13]
    DIRECTION OUTPUT ;
    USE SIGNAL ;
    PORT
      LAYER met3 ;
        RECT 6754.330 4170.320 6756.630 4170.670 ;
    END
  END gpio_vtrip_sel[13]
  PIN gpio_vtrip_sel[14]
    DIRECTION OUTPUT ;
    USE SIGNAL ;
    PORT
      LAYER met3 ;
        RECT 6754.330 4616.320 6756.630 4616.670 ;
    END
  END gpio_vtrip_sel[14]
  PIN gpio_vtrip_sel[15]
    DIRECTION OUTPUT ;
    USE SIGNAL ;
    PORT
      LAYER met2 ;
        RECT 6518.000 4766.350 6518.280 4768.630 ;
    END
  END gpio_vtrip_sel[15]
  PIN gpio_vtrip_sel[16]
    DIRECTION OUTPUT ;
    USE SIGNAL ;
    PORT
      LAYER met2 ;
        RECT 6009.000 4766.350 6009.280 4768.630 ;
    END
  END gpio_vtrip_sel[16]
  PIN gpio_vtrip_sel[17]
    DIRECTION OUTPUT ;
    USE SIGNAL ;
    PORT
      LAYER met2 ;
        RECT 5752.000 4766.350 5752.280 4768.630 ;
    END
  END gpio_vtrip_sel[17]
  PIN gpio_vtrip_sel[18]
    DIRECTION OUTPUT ;
    USE SIGNAL ;
    PORT
      LAYER met2 ;
        RECT 5307.000 4766.350 5307.280 4768.630 ;
    END
  END gpio_vtrip_sel[18]
  PIN gpio_vtrip_sel[19]
    DIRECTION OUTPUT ;
    USE SIGNAL ;
    PORT
      LAYER met2 ;
        RECT 4798.000 4766.350 4798.280 4768.630 ;
    END
  END gpio_vtrip_sel[19]
  PIN gpio_vtrip_sel[1]
    DIRECTION OUTPUT ;
    USE SIGNAL ;
    PORT
      LAYER met3 ;
        RECT 6754.330 584.320 6756.630 584.670 ;
    END
  END gpio_vtrip_sel[1]
  PIN gpio_vtrip_sel[20]
    DIRECTION OUTPUT ;
    USE SIGNAL ;
    PORT
      LAYER met2 ;
        RECT 4540.000 4766.350 4540.280 4768.630 ;
    END
  END gpio_vtrip_sel[20]
  PIN gpio_vtrip_sel[21]
    DIRECTION OUTPUT ;
    USE SIGNAL ;
    PORT
      LAYER met2 ;
        RECT 4283.000 4766.350 4283.280 4768.630 ;
    END
  END gpio_vtrip_sel[21]
  PIN gpio_vtrip_sel[22]
    DIRECTION OUTPUT ;
    USE SIGNAL ;
    PORT
      LAYER met2 ;
        RECT 4026.000 4766.350 4026.280 4768.630 ;
    END
  END gpio_vtrip_sel[22]
  PIN gpio_vtrip_sel[23]
    DIRECTION OUTPUT ;
    USE SIGNAL ;
    PORT
      LAYER met2 ;
        RECT 3769.000 4766.350 3769.280 4768.630 ;
    END
  END gpio_vtrip_sel[23]
  PIN gpio_vtrip_sel[24]
    DIRECTION OUTPUT ;
    USE SIGNAL ;
    PORT
      LAYER met2 ;
        RECT 3444.000 4766.350 3444.280 4768.630 ;
    END
  END gpio_vtrip_sel[24]
  PIN gpio_vtrip_sel[25]
    DIRECTION OUTPUT ;
    USE SIGNAL ;
    PORT
      LAYER met2 ;
        RECT 3187.000 4766.350 3187.280 4768.630 ;
    END
  END gpio_vtrip_sel[25]
  PIN gpio_vtrip_sel[26]
    DIRECTION OUTPUT ;
    USE SIGNAL ;
    PORT
      LAYER met2 ;
        RECT 2930.000 4766.350 2930.280 4768.630 ;
    END
  END gpio_vtrip_sel[26]
  PIN gpio_vtrip_sel[27]
    DIRECTION OUTPUT ;
    USE SIGNAL ;
    PORT
      LAYER met2 ;
        RECT 2421.000 4766.350 2421.280 4768.630 ;
    END
  END gpio_vtrip_sel[27]
  PIN gpio_vtrip_sel[28]
    DIRECTION OUTPUT ;
    USE SIGNAL ;
    PORT
      LAYER met2 ;
        RECT 2164.000 4766.350 2164.280 4768.630 ;
    END
  END gpio_vtrip_sel[28]
  PIN gpio_vtrip_sel[29]
    DIRECTION OUTPUT ;
    USE SIGNAL ;
    PORT
      LAYER met2 ;
        RECT 1719.000 4766.350 1719.280 4768.630 ;
    END
  END gpio_vtrip_sel[29]
  PIN gpio_vtrip_sel[2]
    DIRECTION OUTPUT ;
    USE SIGNAL ;
    PORT
      LAYER met3 ;
        RECT 6754.330 809.320 6756.630 809.670 ;
    END
  END gpio_vtrip_sel[2]
  PIN gpio_vtrip_sel[30]
    DIRECTION OUTPUT ;
    USE SIGNAL ;
    PORT
      LAYER met2 ;
        RECT 1210.000 4766.350 1210.280 4768.630 ;
    END
  END gpio_vtrip_sel[30]
  PIN gpio_vtrip_sel[31]
    DIRECTION OUTPUT ;
    USE SIGNAL ;
    PORT
      LAYER met2 ;
        RECT 952.000 4766.350 952.280 4768.630 ;
    END
  END gpio_vtrip_sel[31]
  PIN gpio_vtrip_sel[32]
    DIRECTION OUTPUT ;
    USE SIGNAL ;
    PORT
      LAYER met2 ;
        RECT 695.000 4766.350 695.280 4768.630 ;
    END
  END gpio_vtrip_sel[32]
  PIN gpio_vtrip_sel[33]
    DIRECTION OUTPUT ;
    USE SIGNAL ;
    PORT
      LAYER met2 ;
        RECT 438.000 4766.350 438.280 4768.630 ;
    END
  END gpio_vtrip_sel[33]
  PIN gpio_vtrip_sel[34]
    DIRECTION OUTPUT ;
    USE SIGNAL ;
    PORT
      LAYER met2 ;
        RECT 181.000 4766.350 181.280 4768.630 ;
    END
  END gpio_vtrip_sel[34]
  PIN gpio_vtrip_sel[35]
    DIRECTION OUTPUT ;
    USE SIGNAL ;
    PORT
      LAYER met3 ;
        RECT -2.000 4570.960 0.300 4571.310 ;
    END
  END gpio_vtrip_sel[35]
  PIN gpio_vtrip_sel[36]
    DIRECTION OUTPUT ;
    USE SIGNAL ;
    PORT
      LAYER met3 ;
        RECT -2.000 3721.960 0.300 3722.310 ;
    END
  END gpio_vtrip_sel[36]
  PIN gpio_vtrip_sel[37]
    DIRECTION OUTPUT ;
    USE SIGNAL ;
    PORT
      LAYER met3 ;
        RECT -2.000 3505.960 0.300 3506.310 ;
    END
  END gpio_vtrip_sel[37]
  PIN gpio_vtrip_sel[38]
    DIRECTION OUTPUT ;
    USE SIGNAL ;
    PORT
      LAYER met3 ;
        RECT -2.000 3289.960 0.300 3290.310 ;
    END
  END gpio_vtrip_sel[38]
  PIN gpio_vtrip_sel[39]
    DIRECTION OUTPUT ;
    USE SIGNAL ;
    PORT
      LAYER met3 ;
        RECT -2.000 3073.960 0.300 3074.310 ;
    END
  END gpio_vtrip_sel[39]
  PIN gpio_vtrip_sel[3]
    DIRECTION OUTPUT ;
    USE SIGNAL ;
    PORT
      LAYER met3 ;
        RECT 6754.330 1035.320 6756.630 1035.670 ;
    END
  END gpio_vtrip_sel[3]
  PIN gpio_vtrip_sel[40]
    DIRECTION OUTPUT ;
    USE SIGNAL ;
    PORT
      LAYER met3 ;
        RECT -2.000 2857.960 0.300 2858.310 ;
    END
  END gpio_vtrip_sel[40]
  PIN gpio_vtrip_sel[41]
    DIRECTION OUTPUT ;
    USE SIGNAL ;
    PORT
      LAYER met3 ;
        RECT -2.000 2641.960 0.300 2642.310 ;
    END
  END gpio_vtrip_sel[41]
  PIN gpio_vtrip_sel[42]
    DIRECTION OUTPUT ;
    USE SIGNAL ;
    PORT
      LAYER met3 ;
        RECT -2.000 2425.960 0.300 2426.310 ;
    END
  END gpio_vtrip_sel[42]
  PIN gpio_vtrip_sel[43]
    DIRECTION OUTPUT ;
    USE SIGNAL ;
    PORT
      LAYER met3 ;
        RECT -2.000 1787.960 0.300 1788.310 ;
    END
  END gpio_vtrip_sel[43]
  PIN gpio_vtrip_sel[44]
    DIRECTION OUTPUT ;
    USE SIGNAL ;
    PORT
      LAYER met3 ;
        RECT -2.000 1571.960 0.300 1572.310 ;
    END
  END gpio_vtrip_sel[44]
  PIN gpio_vtrip_sel[45]
    DIRECTION OUTPUT ;
    USE SIGNAL ;
    PORT
      LAYER met3 ;
        RECT -2.000 1355.960 0.300 1356.310 ;
    END
  END gpio_vtrip_sel[45]
  PIN gpio_vtrip_sel[46]
    DIRECTION OUTPUT ;
    USE SIGNAL ;
    PORT
      LAYER met3 ;
        RECT -2.000 1139.960 0.300 1140.310 ;
    END
  END gpio_vtrip_sel[46]
  PIN gpio_vtrip_sel[47]
    DIRECTION OUTPUT ;
    USE SIGNAL ;
    PORT
      LAYER met3 ;
        RECT -2.000 923.960 0.300 924.310 ;
    END
  END gpio_vtrip_sel[47]
  PIN gpio_vtrip_sel[48]
    DIRECTION OUTPUT ;
    USE SIGNAL ;
    PORT
      LAYER met3 ;
        RECT -2.000 707.960 0.300 708.310 ;
    END
  END gpio_vtrip_sel[48]
  PIN gpio_vtrip_sel[49]
    DIRECTION OUTPUT ;
    USE SIGNAL ;
    PORT
      LAYER met2 ;
        RECT 790.350 -2.000 790.630 0.280 ;
    END
  END gpio_vtrip_sel[49]
  PIN gpio_vtrip_sel[4]
    DIRECTION OUTPUT ;
    USE SIGNAL ;
    PORT
      LAYER met3 ;
        RECT 6754.330 1260.320 6756.630 1260.670 ;
    END
  END gpio_vtrip_sel[4]
  PIN gpio_vtrip_sel[50]
    DIRECTION OUTPUT ;
    USE SIGNAL ;
    PORT
      LAYER met2 ;
        RECT 1333.350 -2.000 1333.630 0.280 ;
    END
  END gpio_vtrip_sel[50]
  PIN gpio_vtrip_sel[51]
    DIRECTION OUTPUT ;
    USE SIGNAL ;
    PORT
      LAYER met2 ;
        RECT 1607.350 -2.000 1607.630 0.280 ;
    END
  END gpio_vtrip_sel[51]
  PIN gpio_vtrip_sel[52]
    DIRECTION OUTPUT ;
    USE SIGNAL ;
    PORT
      LAYER met2 ;
        RECT 1881.350 -2.000 1881.630 0.280 ;
    END
  END gpio_vtrip_sel[52]
  PIN gpio_vtrip_sel[53]
    DIRECTION OUTPUT ;
    USE SIGNAL ;
    PORT
      LAYER met2 ;
        RECT 2155.350 -2.000 2155.630 0.280 ;
    END
  END gpio_vtrip_sel[53]
  PIN gpio_vtrip_sel[54]
    DIRECTION OUTPUT ;
    USE SIGNAL ;
    PORT
      LAYER met2 ;
        RECT 2429.350 -2.000 2429.630 0.280 ;
    END
  END gpio_vtrip_sel[54]
  PIN gpio_vtrip_sel[55]
    DIRECTION OUTPUT ;
    USE SIGNAL ;
    PORT
      LAYER met2 ;
        RECT 3243.830 -2.000 3244.110 0.280 ;
    END
  END gpio_vtrip_sel[55]
  PIN gpio_vtrip_sel[56]
    DIRECTION OUTPUT ;
    USE SIGNAL ;
    PORT
      LAYER met2 ;
        RECT 3517.830 -2.000 3518.110 0.280 ;
    END
  END gpio_vtrip_sel[56]
  PIN gpio_vtrip_sel[57]
    DIRECTION OUTPUT ;
    USE SIGNAL ;
    PORT
      LAYER met2 ;
        RECT 4378.350 -2.000 4378.630 0.280 ;
    END
  END gpio_vtrip_sel[57]
  PIN gpio_vtrip_sel[58]
    DIRECTION OUTPUT ;
    USE SIGNAL ;
    PORT
      LAYER met2 ;
        RECT 4921.350 -2.000 4921.630 0.280 ;
    END
  END gpio_vtrip_sel[58]
  PIN gpio_vtrip_sel[59]
    DIRECTION OUTPUT ;
    USE SIGNAL ;
    PORT
      LAYER met2 ;
        RECT 5195.350 -2.000 5195.630 0.280 ;
    END
  END gpio_vtrip_sel[59]
  PIN gpio_vtrip_sel[5]
    DIRECTION OUTPUT ;
    USE SIGNAL ;
    PORT
      LAYER met3 ;
        RECT 6754.330 1485.320 6756.630 1485.670 ;
    END
  END gpio_vtrip_sel[5]
  PIN gpio_vtrip_sel[60]
    DIRECTION OUTPUT ;
    USE SIGNAL ;
    PORT
      LAYER met2 ;
        RECT 5469.350 -2.000 5469.630 0.280 ;
    END
  END gpio_vtrip_sel[60]
  PIN gpio_vtrip_sel[61]
    DIRECTION OUTPUT ;
    USE SIGNAL ;
    PORT
      LAYER met2 ;
        RECT 5743.350 -2.000 5743.630 0.280 ;
    END
  END gpio_vtrip_sel[61]
  PIN gpio_vtrip_sel[62]
    DIRECTION OUTPUT ;
    USE SIGNAL ;
    PORT
      LAYER met2 ;
        RECT 6017.350 -2.000 6017.630 0.280 ;
    END
  END gpio_vtrip_sel[62]
  PIN gpio_vtrip_sel[6]
    DIRECTION OUTPUT ;
    USE SIGNAL ;
    PORT
      LAYER met3 ;
        RECT 6754.330 1711.320 6756.630 1711.670 ;
    END
  END gpio_vtrip_sel[6]
  PIN gpio_vtrip_sel[7]
    DIRECTION OUTPUT ;
    USE SIGNAL ;
    PORT
      LAYER met3 ;
        RECT 6754.330 2597.320 6756.630 2597.670 ;
    END
  END gpio_vtrip_sel[7]
  PIN gpio_vtrip_sel[8]
    DIRECTION OUTPUT ;
    USE SIGNAL ;
    PORT
      LAYER met3 ;
        RECT 6754.330 2823.320 6756.630 2823.670 ;
    END
  END gpio_vtrip_sel[8]
  PIN gpio_vtrip_sel[9]
    DIRECTION OUTPUT ;
    USE SIGNAL ;
    PORT
      LAYER met3 ;
        RECT 6754.330 3048.320 6756.630 3048.670 ;
    END
  END gpio_vtrip_sel[9]
  PIN mask_rev[0]
    DIRECTION INPUT ;
    USE SIGNAL ;
    PORT
      LAYER met2 ;
        RECT 6613.410 -2.000 6613.670 0.280 ;
    END
  END mask_rev[0]
  PIN mask_rev[10]
    DIRECTION INPUT ;
    USE SIGNAL ;
    PORT
      LAYER met2 ;
        RECT 6624.610 -2.000 6624.870 0.280 ;
    END
  END mask_rev[10]
  PIN mask_rev[11]
    DIRECTION INPUT ;
    USE SIGNAL ;
    PORT
      LAYER met2 ;
        RECT 6625.730 -2.000 6625.990 0.280 ;
    END
  END mask_rev[11]
  PIN mask_rev[12]
    DIRECTION INPUT ;
    USE SIGNAL ;
    PORT
      LAYER met2 ;
        RECT 6626.850 -2.000 6627.110 0.280 ;
    END
  END mask_rev[12]
  PIN mask_rev[13]
    DIRECTION INPUT ;
    USE SIGNAL ;
    PORT
      LAYER met2 ;
        RECT 6627.970 -2.000 6628.230 0.280 ;
    END
  END mask_rev[13]
  PIN mask_rev[14]
    DIRECTION INPUT ;
    USE SIGNAL ;
    PORT
      LAYER met2 ;
        RECT 6629.090 -2.000 6629.350 0.280 ;
    END
  END mask_rev[14]
  PIN mask_rev[15]
    DIRECTION INPUT ;
    USE SIGNAL ;
    PORT
      LAYER met2 ;
        RECT 6630.210 -2.000 6630.470 0.280 ;
    END
  END mask_rev[15]
  PIN mask_rev[16]
    DIRECTION INPUT ;
    USE SIGNAL ;
    PORT
      LAYER met2 ;
        RECT 6631.330 -2.000 6631.590 0.280 ;
    END
  END mask_rev[16]
  PIN mask_rev[17]
    DIRECTION INPUT ;
    USE SIGNAL ;
    PORT
      LAYER met2 ;
        RECT 6632.450 -2.000 6632.710 0.280 ;
    END
  END mask_rev[17]
  PIN mask_rev[18]
    DIRECTION INPUT ;
    USE SIGNAL ;
    PORT
      LAYER met2 ;
        RECT 6633.570 -2.000 6633.830 0.280 ;
    END
  END mask_rev[18]
  PIN mask_rev[19]
    DIRECTION INPUT ;
    USE SIGNAL ;
    PORT
      LAYER met2 ;
        RECT 6634.690 -2.000 6634.950 0.280 ;
    END
  END mask_rev[19]
  PIN mask_rev[1]
    DIRECTION INPUT ;
    USE SIGNAL ;
    PORT
      LAYER met2 ;
        RECT 6614.530 -2.000 6614.790 0.280 ;
    END
  END mask_rev[1]
  PIN mask_rev[20]
    DIRECTION INPUT ;
    USE SIGNAL ;
    PORT
      LAYER met2 ;
        RECT 6635.810 -2.000 6636.070 0.280 ;
    END
  END mask_rev[20]
  PIN mask_rev[21]
    DIRECTION INPUT ;
    USE SIGNAL ;
    PORT
      LAYER met2 ;
        RECT 6636.930 -2.000 6637.190 0.280 ;
    END
  END mask_rev[21]
  PIN mask_rev[22]
    DIRECTION INPUT ;
    USE SIGNAL ;
    PORT
      LAYER met2 ;
        RECT 6638.050 -2.000 6638.310 0.280 ;
    END
  END mask_rev[22]
  PIN mask_rev[23]
    DIRECTION INPUT ;
    USE SIGNAL ;
    PORT
      LAYER met2 ;
        RECT 6639.170 -2.000 6639.430 0.280 ;
    END
  END mask_rev[23]
  PIN mask_rev[24]
    DIRECTION INPUT ;
    USE SIGNAL ;
    PORT
      LAYER met2 ;
        RECT 6640.290 -2.000 6640.550 0.280 ;
    END
  END mask_rev[24]
  PIN mask_rev[25]
    DIRECTION INPUT ;
    USE SIGNAL ;
    PORT
      LAYER met2 ;
        RECT 6641.410 -2.000 6641.670 0.280 ;
    END
  END mask_rev[25]
  PIN mask_rev[26]
    DIRECTION INPUT ;
    USE SIGNAL ;
    PORT
      LAYER met2 ;
        RECT 6642.530 -2.000 6642.790 0.280 ;
    END
  END mask_rev[26]
  PIN mask_rev[27]
    DIRECTION INPUT ;
    USE SIGNAL ;
    PORT
      LAYER met2 ;
        RECT 6643.650 -2.000 6643.910 0.280 ;
    END
  END mask_rev[27]
  PIN mask_rev[28]
    DIRECTION INPUT ;
    USE SIGNAL ;
    PORT
      LAYER met2 ;
        RECT 6644.770 -2.000 6645.030 0.280 ;
    END
  END mask_rev[28]
  PIN mask_rev[29]
    DIRECTION INPUT ;
    USE SIGNAL ;
    PORT
      LAYER met2 ;
        RECT 6645.890 -2.000 6646.150 0.280 ;
    END
  END mask_rev[29]
  PIN mask_rev[2]
    DIRECTION INPUT ;
    USE SIGNAL ;
    PORT
      LAYER met2 ;
        RECT 6615.650 -2.000 6615.910 0.280 ;
    END
  END mask_rev[2]
  PIN mask_rev[30]
    DIRECTION INPUT ;
    USE SIGNAL ;
    PORT
      LAYER met2 ;
        RECT 6647.010 -2.000 6647.270 0.280 ;
    END
  END mask_rev[30]
  PIN mask_rev[31]
    DIRECTION INPUT ;
    USE SIGNAL ;
    PORT
      LAYER met2 ;
        RECT 6648.130 -2.000 6648.390 0.280 ;
    END
  END mask_rev[31]
  PIN mask_rev[3]
    DIRECTION INPUT ;
    USE SIGNAL ;
    PORT
      LAYER met2 ;
        RECT 6616.770 -2.000 6617.030 0.280 ;
    END
  END mask_rev[3]
  PIN mask_rev[4]
    DIRECTION INPUT ;
    USE SIGNAL ;
    PORT
      LAYER met2 ;
        RECT 6617.890 -2.000 6618.150 0.280 ;
    END
  END mask_rev[4]
  PIN mask_rev[5]
    DIRECTION INPUT ;
    USE SIGNAL ;
    PORT
      LAYER met2 ;
        RECT 6619.010 -2.000 6619.270 0.280 ;
    END
  END mask_rev[5]
  PIN mask_rev[6]
    DIRECTION INPUT ;
    USE SIGNAL ;
    PORT
      LAYER met2 ;
        RECT 6620.130 -2.000 6620.390 0.280 ;
    END
  END mask_rev[6]
  PIN mask_rev[7]
    DIRECTION INPUT ;
    USE SIGNAL ;
    PORT
      LAYER met2 ;
        RECT 6621.250 -2.000 6621.510 0.280 ;
    END
  END mask_rev[7]
  PIN mask_rev[8]
    DIRECTION INPUT ;
    USE SIGNAL ;
    PORT
      LAYER met2 ;
        RECT 6622.370 -2.000 6622.630 0.280 ;
    END
  END mask_rev[8]
  PIN mask_rev[9]
    DIRECTION INPUT ;
    USE SIGNAL ;
    PORT
      LAYER met2 ;
        RECT 6623.490 -2.000 6623.750 0.280 ;
    END
  END mask_rev[9]
  PIN por_l
    DIRECTION INPUT ;
    USE SIGNAL ;
    PORT
      LAYER met3 ;
        RECT -2.000 528.180 0.300 528.530 ;
    END
  END por_l
  PIN porb_h
    DIRECTION INPUT ;
    USE SIGNAL ;
    PORT
      LAYER met3 ;
        RECT -2.000 527.055 0.300 527.405 ;
    END
  END porb_h
  PIN porb_l
    DIRECTION INPUT ;
    USE SIGNAL ;
    ANTENNAGATEAREA 0.631200 ;
    ANTENNADIFFAREA 0.434700 ;
    PORT
      LAYER met3 ;
        RECT -2.000 529.295 0.300 529.645 ;
    END
  END porb_l
  PIN resetb_h
    DIRECTION INPUT ;
    USE SIGNAL ;
    PORT
      LAYER met2 ;
        RECT 497.880 -2.000 498.160 0.280 ;
    END
  END resetb_h
  PIN resetb_l
    DIRECTION INPUT ;
    USE SIGNAL ;
    ANTENNAGATEAREA 0.631200 ;
    ANTENNADIFFAREA 0.434700 ;
    PORT
      LAYER met2 ;
        RECT 550.820 -2.000 551.100 0.280 ;
    END
  END resetb_l
  PIN vccd
    DIRECTION INPUT ;
    USE POWER ;
    PORT
      LAYER met3 ;
        RECT -2.000 129.810 0.300 153.810 ;
    END
  END vccd
  PIN vccd
    DIRECTION INPUT ;
    USE POWER ;
    PORT
      LAYER met3 ;
        RECT -2.000 180.070 0.300 204.020 ;
    END
  END vccd
  PIN vccd1
    DIRECTION INOUT ;
    USE POWER ;
    PORT
      LAYER met3 ;
        RECT 6754.330 4327.610 6756.630 4351.560 ;
    END
  END vccd1
  PIN vccd1
    DIRECTION INOUT ;
    USE POWER ;
    PORT
      LAYER met3 ;
        RECT 6754.330 4377.810 6756.630 4401.810 ;
    END
  END vccd1
  PIN vccd1
    DIRECTION INOUT ;
    USE POWER ;
    PORT
      LAYER met3 ;
        RECT 6754.330 2114.050 6756.630 2137.360 ;
    END
  END vccd1
  PIN vccd2
    DIRECTION INPUT ;
    USE POWER ;
    PORT
      LAYER met3 ;
        RECT -2.000 4349.820 0.300 4373.820 ;
    END
  END vccd2
  PIN vccd2
    DIRECTION INPUT ;
    USE POWER ;
    PORT
      LAYER met3 ;
        RECT -2.000 4400.070 0.300 4424.020 ;
    END
  END vccd2
  PIN vccd2
    DIRECTION INPUT ;
    USE POWER ;
    PORT
      LAYER met3 ;
        RECT -2.000 2019.310 0.300 2042.570 ;
    END
  END vccd2
  PIN vdda
    DIRECTION INPUT ;
    USE POWER ;
    PORT
      LAYER met3 ;
        RECT 6492.030 -2.000 6515.930 0.300 ;
    END
  END vdda
  PIN vdda
    DIRECTION INPUT ;
    USE POWER ;
    PORT
      LAYER met3 ;
        RECT 6541.920 -2.000 6565.820 0.300 ;
    END
  END vdda
  PIN vdda
    DIRECTION INPUT ;
    USE POWER ;
    PORT
      LAYER met3 ;
        RECT 2904.030 -2.000 2927.930 0.300 ;
    END
  END vdda
  PIN vdda
    DIRECTION INPUT ;
    USE POWER ;
    PORT
      LAYER met3 ;
        RECT 2953.920 -2.000 2977.820 0.300 ;
    END
  END vdda
  PIN vdda1
    DIRECTION INPUT ;
    USE POWER ;
    PORT
      LAYER met3 ;
        RECT 6754.330 3882.030 6756.630 3905.930 ;
    END
  END vdda1
  PIN vdda1
    DIRECTION INPUT ;
    USE POWER ;
    PORT
      LAYER met3 ;
        RECT 6754.330 3931.920 6756.630 3955.820 ;
    END
  END vdda1
  PIN vdda1
    DIRECTION INPUT ;
    USE POWER ;
    PORT
      LAYER met3 ;
        RECT 6754.330 2309.020 6756.630 2332.920 ;
    END
  END vdda1
  PIN vdda1
    DIRECTION INPUT ;
    USE POWER ;
    PORT
      LAYER met3 ;
        RECT 6754.330 2358.920 6756.630 2382.820 ;
    END
  END vdda1
  PIN vdda2
    DIRECTION INPUT ;
    USE POWER ;
    PORT
      LAYER met3 ;
        RECT -2.000 2254.700 0.300 2278.600 ;
    END
  END vdda2
  PIN vdda2
    DIRECTION INPUT ;
    USE POWER ;
    PORT
      LAYER met3 ;
        RECT -2.000 2204.810 0.300 2228.710 ;
    END
  END vdda2
  PIN vddio
    DIRECTION INPUT ;
    USE POWER ;
    PORT
      LAYER met3 ;
        RECT -2.000 4188.710 0.300 4212.610 ;
    END
  END vddio
  PIN vddio
    DIRECTION INPUT ;
    USE POWER ;
    PORT
      LAYER met3 ;
        RECT -2.000 4138.810 0.300 4162.710 ;
    END
  END vddio
  PIN vddio
    DIRECTION INPUT ;
    USE POWER ;
    PORT
      LAYER met3 ;
        RECT -2.000 390.700 0.300 414.600 ;
    END
  END vddio
  PIN vddio
    DIRECTION INPUT ;
    USE POWER ;
    PORT
      LAYER met3 ;
        RECT -2.000 340.810 0.300 364.710 ;
    END
  END vddio
  PIN vssa
    DIRECTION INPUT ;
    USE GROUND ;
    PORT
      LAYER met3 ;
        RECT 3772.030 -2.000 3795.930 0.300 ;
    END
  END vssa
  PIN vssa
    DIRECTION INPUT ;
    USE GROUND ;
    PORT
      LAYER met3 ;
        RECT 3821.920 -2.000 3845.820 0.300 ;
    END
  END vssa
  PIN vssa
    DIRECTION INPUT ;
    USE GROUND ;
    PORT
      LAYER met3 ;
        RECT 184.030 -2.000 207.930 0.300 ;
    END
  END vssa
  PIN vssa
    DIRECTION INPUT ;
    USE GROUND ;
    PORT
      LAYER met3 ;
        RECT 233.920 -2.000 257.820 0.300 ;
    END
  END vssa
  PIN vssa1
    DIRECTION INPUT ;
    USE GROUND ;
    PORT
      LAYER met3 ;
        RECT 6305.710 4766.330 6329.610 4768.630 ;
    END
  END vssa1
  PIN vssa1
    DIRECTION INPUT ;
    USE GROUND ;
    PORT
      LAYER met3 ;
        RECT 6255.810 4766.330 6279.710 4768.630 ;
    END
  END vssa1
  PIN vssa1
    DIRECTION INPUT ;
    USE GROUND ;
    PORT
      LAYER met3 ;
        RECT 2717.710 4766.330 2741.610 4768.630 ;
    END
  END vssa1
  PIN vssa1
    DIRECTION INPUT ;
    USE GROUND ;
    PORT
      LAYER met3 ;
        RECT 2667.810 4766.330 2691.710 4768.630 ;
    END
  END vssa1
  PIN vssa1
    DIRECTION INPUT ;
    USE GROUND ;
    PORT
      LAYER met3 ;
        RECT 6754.330 1868.030 6756.630 1891.930 ;
    END
  END vssa1
  PIN vssa1
    DIRECTION INPUT ;
    USE GROUND ;
    PORT
      LAYER met3 ;
        RECT 6754.330 1917.920 6756.630 1941.820 ;
    END
  END vssa1
  PIN vssa2
    DIRECTION INPUT ;
    USE GROUND ;
    PORT
      LAYER met3 ;
        RECT -2.000 3977.710 0.300 4001.610 ;
    END
  END vssa2
  PIN vssa2
    DIRECTION INPUT ;
    USE GROUND ;
    PORT
      LAYER met3 ;
        RECT -2.000 3927.810 0.300 3951.710 ;
    END
  END vssa2
  PIN vssd
    DIRECTION INPUT ;
    USE GROUND ;
    PORT
      LAYER met3 ;
        RECT 4633.820 -2.000 4657.820 0.300 ;
    END
  END vssd
  PIN vssd
    DIRECTION INPUT ;
    USE GROUND ;
    PORT
      LAYER met3 ;
        RECT 4584.420 -2.000 4607.570 0.300 ;
    END
  END vssd
  PIN vssd
    DIRECTION INPUT ;
    USE GROUND ;
    PORT
      LAYER met3 ;
        RECT 1045.820 -2.000 1069.820 0.300 ;
    END
  END vssd
  PIN vssd
    DIRECTION INPUT ;
    USE GROUND ;
    PORT
      LAYER met3 ;
        RECT 996.420 -2.000 1019.570 0.300 ;
    END
  END vssd
  PIN vssd1
    DIRECTION INOUT ;
    USE GROUND ;
    PORT
      LAYER met3 ;
        RECT 6754.330 4353.050 6756.630 4376.360 ;
    END
  END vssd1
  PIN vssd1
    DIRECTION INOUT ;
    USE GROUND ;
    PORT
      LAYER met3 ;
        RECT 6752.980 2138.810 6756.630 2162.810 ;
    END
  END vssd1
  PIN vssd1
    DIRECTION INOUT ;
    USE GROUND ;
    PORT
      LAYER met3 ;
        RECT 6754.330 2088.610 6756.630 2112.560 ;
    END
  END vssd1
  PIN vssd2
    DIRECTION INPUT ;
    USE GROUND ;
    PORT
      LAYER met3 ;
        RECT -2.000 4375.270 0.300 4398.580 ;
    END
  END vssd2
  PIN vssd2
    DIRECTION INPUT ;
    USE GROUND ;
    PORT
      LAYER met3 ;
        RECT -2.000 1993.810 0.300 2017.810 ;
    END
  END vssd2
  PIN vssd2
    DIRECTION INPUT ;
    USE GROUND ;
    PORT
      LAYER met3 ;
        RECT -2.000 2044.070 0.300 2068.020 ;
    END
  END vssd2
  PIN vssio
    DIRECTION INPUT ;
    USE GROUND ;
    PORT
      LAYER met3 ;
        RECT 6223.030 -2.000 6246.930 0.300 ;
    END
  END vssio
  PIN vssio
    DIRECTION INPUT ;
    USE GROUND ;
    PORT
      LAYER met3 ;
        RECT 6272.920 -2.000 6296.820 0.300 ;
    END
  END vssio
  PIN vssio
    DIRECTION INPUT ;
    USE GROUND ;
    PORT
      LAYER met3 ;
        RECT 2635.030 -2.000 2658.930 0.300 ;
    END
  END vssio
  PIN vssio
    DIRECTION INPUT ;
    USE GROUND ;
    PORT
      LAYER met3 ;
        RECT 2684.920 -2.000 2708.820 0.300 ;
    END
  END vssio
  PIN vssio
    DIRECTION INPUT ;
    USE GROUND ;
    PORT
      LAYER met3 ;
        RECT 5094.710 4766.330 5118.610 4768.630 ;
    END
  END vssio
  PIN vssio
    DIRECTION INPUT ;
    USE GROUND ;
    PORT
      LAYER met3 ;
        RECT 5044.810 4766.330 5068.710 4768.630 ;
    END
  END vssio
  PIN vssio
    DIRECTION INPUT ;
    USE GROUND ;
    PORT
      LAYER met3 ;
        RECT 1506.710 4766.330 1530.610 4768.630 ;
    END
  END vssio
  PIN vssio
    DIRECTION INPUT ;
    USE GROUND ;
    PORT
      LAYER met3 ;
        RECT 1456.810 4766.330 1480.710 4768.630 ;
    END
  END vssio
  OBS
      LAYER nwell ;
        RECT 155.330 510.795 344.310 4487.605 ;
      LAYER li1 ;
        RECT 155.520 510.795 344.120 4487.605 ;
      LAYER met1 ;
        RECT 150.530 510.640 6536.760 4766.420 ;
      LAYER met2 ;
        RECT 0.090 4766.070 137.210 4766.530 ;
        RECT 138.070 4766.070 147.210 4766.530 ;
        RECT 148.070 4766.070 171.520 4766.530 ;
        RECT 172.360 4766.070 174.280 4766.530 ;
        RECT 175.120 4766.070 177.500 4766.530 ;
        RECT 178.340 4766.070 180.720 4766.530 ;
        RECT 181.560 4766.070 189.920 4766.530 ;
        RECT 190.760 4766.070 192.680 4766.530 ;
        RECT 193.520 4766.070 195.900 4766.530 ;
        RECT 196.740 4766.070 199.120 4766.530 ;
        RECT 199.960 4766.070 211.540 4766.530 ;
        RECT 212.380 4766.070 214.300 4766.530 ;
        RECT 215.140 4766.070 217.520 4766.530 ;
        RECT 218.360 4766.070 220.740 4766.530 ;
        RECT 221.580 4766.070 223.105 4766.530 ;
        RECT 224.735 4766.070 226.720 4766.530 ;
        RECT 227.560 4766.070 232.520 4766.530 ;
        RECT 233.720 4766.070 235.920 4766.530 ;
        RECT 236.760 4766.070 245.120 4766.530 ;
        RECT 245.960 4766.070 393.210 4766.530 ;
        RECT 394.070 4766.070 403.210 4766.530 ;
        RECT 404.070 4766.070 428.520 4766.530 ;
        RECT 429.360 4766.070 431.280 4766.530 ;
        RECT 432.120 4766.070 434.500 4766.530 ;
        RECT 435.340 4766.070 437.720 4766.530 ;
        RECT 438.560 4766.070 446.920 4766.530 ;
        RECT 447.760 4766.070 449.680 4766.530 ;
        RECT 450.520 4766.070 452.900 4766.530 ;
        RECT 453.740 4766.070 456.120 4766.530 ;
        RECT 456.960 4766.070 468.540 4766.530 ;
        RECT 469.380 4766.070 471.300 4766.530 ;
        RECT 472.140 4766.070 474.520 4766.530 ;
        RECT 475.360 4766.070 477.740 4766.530 ;
        RECT 478.580 4766.070 480.105 4766.530 ;
        RECT 481.735 4766.070 483.720 4766.530 ;
        RECT 484.560 4766.070 489.520 4766.530 ;
        RECT 490.720 4766.070 492.920 4766.530 ;
        RECT 493.760 4766.070 502.120 4766.530 ;
        RECT 502.960 4766.070 649.210 4766.530 ;
        RECT 650.070 4766.070 659.210 4766.530 ;
        RECT 660.070 4766.070 685.520 4766.530 ;
        RECT 686.360 4766.070 688.280 4766.530 ;
        RECT 689.120 4766.070 691.500 4766.530 ;
        RECT 692.340 4766.070 694.720 4766.530 ;
        RECT 695.560 4766.070 703.920 4766.530 ;
        RECT 704.760 4766.070 706.680 4766.530 ;
        RECT 707.520 4766.070 709.900 4766.530 ;
        RECT 710.740 4766.070 713.120 4766.530 ;
        RECT 713.960 4766.070 725.540 4766.530 ;
        RECT 726.380 4766.070 728.300 4766.530 ;
        RECT 729.140 4766.070 731.520 4766.530 ;
        RECT 732.360 4766.070 734.740 4766.530 ;
        RECT 735.580 4766.070 737.105 4766.530 ;
        RECT 738.735 4766.070 740.720 4766.530 ;
        RECT 741.560 4766.070 746.520 4766.530 ;
        RECT 747.720 4766.070 749.920 4766.530 ;
        RECT 750.760 4766.070 759.120 4766.530 ;
        RECT 759.960 4766.070 905.210 4766.530 ;
        RECT 906.070 4766.070 915.210 4766.530 ;
        RECT 916.070 4766.070 942.520 4766.530 ;
        RECT 943.360 4766.070 945.280 4766.530 ;
        RECT 946.120 4766.070 948.500 4766.530 ;
        RECT 949.340 4766.070 951.720 4766.530 ;
        RECT 952.560 4766.070 960.920 4766.530 ;
        RECT 961.760 4766.070 963.680 4766.530 ;
        RECT 964.520 4766.070 966.900 4766.530 ;
        RECT 967.740 4766.070 970.120 4766.530 ;
        RECT 970.960 4766.070 982.540 4766.530 ;
        RECT 983.380 4766.070 985.300 4766.530 ;
        RECT 986.140 4766.070 988.520 4766.530 ;
        RECT 989.360 4766.070 991.740 4766.530 ;
        RECT 992.580 4766.070 994.105 4766.530 ;
        RECT 995.735 4766.070 997.720 4766.530 ;
        RECT 998.560 4766.070 1003.520 4766.530 ;
        RECT 1004.720 4766.070 1006.920 4766.530 ;
        RECT 1007.760 4766.070 1016.120 4766.530 ;
        RECT 1016.960 4766.070 1161.210 4766.530 ;
        RECT 1162.070 4766.070 1171.210 4766.530 ;
        RECT 1172.070 4766.070 1200.520 4766.530 ;
        RECT 1201.360 4766.070 1203.280 4766.530 ;
        RECT 1204.120 4766.070 1206.500 4766.530 ;
        RECT 1207.340 4766.070 1209.720 4766.530 ;
        RECT 1210.560 4766.070 1218.920 4766.530 ;
        RECT 1219.760 4766.070 1221.680 4766.530 ;
        RECT 1222.520 4766.070 1224.900 4766.530 ;
        RECT 1225.740 4766.070 1228.120 4766.530 ;
        RECT 1228.960 4766.070 1240.540 4766.530 ;
        RECT 1241.380 4766.070 1243.300 4766.530 ;
        RECT 1244.140 4766.070 1246.520 4766.530 ;
        RECT 1247.360 4766.070 1249.740 4766.530 ;
        RECT 1250.580 4766.070 1252.105 4766.530 ;
        RECT 1253.735 4766.070 1255.720 4766.530 ;
        RECT 1256.560 4766.070 1261.520 4766.530 ;
        RECT 1262.720 4766.070 1264.920 4766.530 ;
        RECT 1265.760 4766.070 1274.120 4766.530 ;
        RECT 1274.960 4766.070 1683.210 4766.530 ;
        RECT 1684.070 4766.070 1693.210 4766.530 ;
        RECT 1694.070 4766.070 1709.520 4766.530 ;
        RECT 1710.360 4766.070 1712.280 4766.530 ;
        RECT 1713.120 4766.070 1715.500 4766.530 ;
        RECT 1716.340 4766.070 1718.720 4766.530 ;
        RECT 1719.560 4766.070 1727.920 4766.530 ;
        RECT 1728.760 4766.070 1730.680 4766.530 ;
        RECT 1731.520 4766.070 1733.900 4766.530 ;
        RECT 1734.740 4766.070 1737.120 4766.530 ;
        RECT 1737.960 4766.070 1749.540 4766.530 ;
        RECT 1750.380 4766.070 1752.300 4766.530 ;
        RECT 1753.140 4766.070 1755.520 4766.530 ;
        RECT 1756.360 4766.070 1758.740 4766.530 ;
        RECT 1759.580 4766.070 1761.105 4766.530 ;
        RECT 1762.735 4766.070 1764.720 4766.530 ;
        RECT 1765.560 4766.070 1770.520 4766.530 ;
        RECT 1771.720 4766.070 1773.920 4766.530 ;
        RECT 1774.760 4766.070 1783.120 4766.530 ;
        RECT 1783.960 4766.070 2128.210 4766.530 ;
        RECT 2129.070 4766.070 2138.210 4766.530 ;
        RECT 2139.070 4766.070 2154.520 4766.530 ;
        RECT 2155.360 4766.070 2157.280 4766.530 ;
        RECT 2158.120 4766.070 2160.500 4766.530 ;
        RECT 2161.340 4766.070 2163.720 4766.530 ;
        RECT 2164.560 4766.070 2172.920 4766.530 ;
        RECT 2173.760 4766.070 2175.680 4766.530 ;
        RECT 2176.520 4766.070 2178.900 4766.530 ;
        RECT 2179.740 4766.070 2182.120 4766.530 ;
        RECT 2182.960 4766.070 2194.540 4766.530 ;
        RECT 2195.380 4766.070 2197.300 4766.530 ;
        RECT 2198.140 4766.070 2200.520 4766.530 ;
        RECT 2201.360 4766.070 2203.740 4766.530 ;
        RECT 2204.580 4766.070 2206.105 4766.530 ;
        RECT 2207.735 4766.070 2209.720 4766.530 ;
        RECT 2210.560 4766.070 2215.520 4766.530 ;
        RECT 2216.720 4766.070 2218.920 4766.530 ;
        RECT 2219.760 4766.070 2228.120 4766.530 ;
        RECT 2228.960 4766.070 2384.210 4766.530 ;
        RECT 2385.070 4766.070 2394.210 4766.530 ;
        RECT 2395.070 4766.070 2411.520 4766.530 ;
        RECT 2412.360 4766.070 2414.280 4766.530 ;
        RECT 2415.120 4766.070 2417.500 4766.530 ;
        RECT 2418.340 4766.070 2420.720 4766.530 ;
        RECT 2421.560 4766.070 2429.920 4766.530 ;
        RECT 2430.760 4766.070 2432.680 4766.530 ;
        RECT 2433.520 4766.070 2435.900 4766.530 ;
        RECT 2436.740 4766.070 2439.120 4766.530 ;
        RECT 2439.960 4766.070 2451.540 4766.530 ;
        RECT 2452.380 4766.070 2454.300 4766.530 ;
        RECT 2455.140 4766.070 2457.520 4766.530 ;
        RECT 2458.360 4766.070 2460.740 4766.530 ;
        RECT 2461.580 4766.070 2463.105 4766.530 ;
        RECT 2464.735 4766.070 2466.720 4766.530 ;
        RECT 2467.560 4766.070 2472.520 4766.530 ;
        RECT 2473.720 4766.070 2475.920 4766.530 ;
        RECT 2476.760 4766.070 2485.120 4766.530 ;
        RECT 2485.960 4766.070 2881.210 4766.530 ;
        RECT 2882.070 4766.070 2891.210 4766.530 ;
        RECT 2892.070 4766.070 2920.520 4766.530 ;
        RECT 2921.360 4766.070 2923.280 4766.530 ;
        RECT 2924.120 4766.070 2926.500 4766.530 ;
        RECT 2927.340 4766.070 2929.720 4766.530 ;
        RECT 2930.560 4766.070 2938.920 4766.530 ;
        RECT 2939.760 4766.070 2941.680 4766.530 ;
        RECT 2942.520 4766.070 2944.900 4766.530 ;
        RECT 2945.740 4766.070 2948.120 4766.530 ;
        RECT 2948.960 4766.070 2960.540 4766.530 ;
        RECT 2961.380 4766.070 2963.300 4766.530 ;
        RECT 2964.140 4766.070 2966.520 4766.530 ;
        RECT 2967.360 4766.070 2969.740 4766.530 ;
        RECT 2970.580 4766.070 2972.105 4766.530 ;
        RECT 2973.735 4766.070 2975.720 4766.530 ;
        RECT 2976.560 4766.070 2981.520 4766.530 ;
        RECT 2982.720 4766.070 2984.920 4766.530 ;
        RECT 2985.760 4766.070 2994.120 4766.530 ;
        RECT 2994.960 4766.070 3143.210 4766.530 ;
        RECT 3144.070 4766.070 3153.210 4766.530 ;
        RECT 3154.070 4766.070 3177.520 4766.530 ;
        RECT 3178.360 4766.070 3180.280 4766.530 ;
        RECT 3181.120 4766.070 3183.500 4766.530 ;
        RECT 3184.340 4766.070 3186.720 4766.530 ;
        RECT 3187.560 4766.070 3195.920 4766.530 ;
        RECT 3196.760 4766.070 3198.680 4766.530 ;
        RECT 3199.520 4766.070 3201.900 4766.530 ;
        RECT 3202.740 4766.070 3205.120 4766.530 ;
        RECT 3205.960 4766.070 3217.540 4766.530 ;
        RECT 3218.380 4766.070 3220.300 4766.530 ;
        RECT 3221.140 4766.070 3223.520 4766.530 ;
        RECT 3224.360 4766.070 3226.740 4766.530 ;
        RECT 3227.580 4766.070 3229.105 4766.530 ;
        RECT 3230.735 4766.070 3232.720 4766.530 ;
        RECT 3233.560 4766.070 3238.520 4766.530 ;
        RECT 3239.720 4766.070 3241.920 4766.530 ;
        RECT 3242.760 4766.070 3251.120 4766.530 ;
        RECT 3251.960 4766.070 3400.210 4766.530 ;
        RECT 3401.070 4766.070 3410.210 4766.530 ;
        RECT 3411.070 4766.070 3434.520 4766.530 ;
        RECT 3435.360 4766.070 3437.280 4766.530 ;
        RECT 3438.120 4766.070 3440.500 4766.530 ;
        RECT 3441.340 4766.070 3443.720 4766.530 ;
        RECT 3444.560 4766.070 3452.920 4766.530 ;
        RECT 3453.760 4766.070 3455.680 4766.530 ;
        RECT 3456.520 4766.070 3458.900 4766.530 ;
        RECT 3459.740 4766.070 3462.120 4766.530 ;
        RECT 3462.960 4766.070 3474.540 4766.530 ;
        RECT 3475.380 4766.070 3477.300 4766.530 ;
        RECT 3478.140 4766.070 3480.520 4766.530 ;
        RECT 3481.360 4766.070 3483.740 4766.530 ;
        RECT 3484.580 4766.070 3486.105 4766.530 ;
        RECT 3487.735 4766.070 3489.720 4766.530 ;
        RECT 3490.560 4766.070 3495.520 4766.530 ;
        RECT 3496.720 4766.070 3498.920 4766.530 ;
        RECT 3499.760 4766.070 3508.120 4766.530 ;
        RECT 3508.960 4766.070 3725.210 4766.530 ;
        RECT 3726.070 4766.070 3735.210 4766.530 ;
        RECT 3736.070 4766.070 3759.520 4766.530 ;
        RECT 3760.360 4766.070 3762.280 4766.530 ;
        RECT 3763.120 4766.070 3765.500 4766.530 ;
        RECT 3766.340 4766.070 3768.720 4766.530 ;
        RECT 3769.560 4766.070 3777.920 4766.530 ;
        RECT 3778.760 4766.070 3780.680 4766.530 ;
        RECT 3781.520 4766.070 3783.900 4766.530 ;
        RECT 3784.740 4766.070 3787.120 4766.530 ;
        RECT 3787.960 4766.070 3799.540 4766.530 ;
        RECT 3800.380 4766.070 3802.300 4766.530 ;
        RECT 3803.140 4766.070 3805.520 4766.530 ;
        RECT 3806.360 4766.070 3808.740 4766.530 ;
        RECT 3809.580 4766.070 3811.105 4766.530 ;
        RECT 3812.735 4766.070 3814.720 4766.530 ;
        RECT 3815.560 4766.070 3820.520 4766.530 ;
        RECT 3821.720 4766.070 3823.920 4766.530 ;
        RECT 3824.760 4766.070 3833.120 4766.530 ;
        RECT 3833.960 4766.070 3981.210 4766.530 ;
        RECT 3982.070 4766.070 3991.210 4766.530 ;
        RECT 3992.070 4766.070 4016.520 4766.530 ;
        RECT 4017.360 4766.070 4019.280 4766.530 ;
        RECT 4020.120 4766.070 4022.500 4766.530 ;
        RECT 4023.340 4766.070 4025.720 4766.530 ;
        RECT 4026.560 4766.070 4034.920 4766.530 ;
        RECT 4035.760 4766.070 4037.680 4766.530 ;
        RECT 4038.520 4766.070 4040.900 4766.530 ;
        RECT 4041.740 4766.070 4044.120 4766.530 ;
        RECT 4044.960 4766.070 4056.540 4766.530 ;
        RECT 4057.380 4766.070 4059.300 4766.530 ;
        RECT 4060.140 4766.070 4062.520 4766.530 ;
        RECT 4063.360 4766.070 4065.740 4766.530 ;
        RECT 4066.580 4766.070 4068.105 4766.530 ;
        RECT 4069.735 4766.070 4071.720 4766.530 ;
        RECT 4072.560 4766.070 4077.520 4766.530 ;
        RECT 4078.720 4766.070 4080.920 4766.530 ;
        RECT 4081.760 4766.070 4090.120 4766.530 ;
        RECT 4090.960 4766.070 4237.210 4766.530 ;
        RECT 4238.070 4766.070 4247.210 4766.530 ;
        RECT 4248.070 4766.070 4273.520 4766.530 ;
        RECT 4274.360 4766.070 4276.280 4766.530 ;
        RECT 4277.120 4766.070 4279.500 4766.530 ;
        RECT 4280.340 4766.070 4282.720 4766.530 ;
        RECT 4283.560 4766.070 4291.920 4766.530 ;
        RECT 4292.760 4766.070 4294.680 4766.530 ;
        RECT 4295.520 4766.070 4297.900 4766.530 ;
        RECT 4298.740 4766.070 4301.120 4766.530 ;
        RECT 4301.960 4766.070 4313.540 4766.530 ;
        RECT 4314.380 4766.070 4316.300 4766.530 ;
        RECT 4317.140 4766.070 4319.520 4766.530 ;
        RECT 4320.360 4766.070 4322.740 4766.530 ;
        RECT 4323.580 4766.070 4325.105 4766.530 ;
        RECT 4326.735 4766.070 4328.720 4766.530 ;
        RECT 4329.560 4766.070 4334.520 4766.530 ;
        RECT 4335.720 4766.070 4337.920 4766.530 ;
        RECT 4338.760 4766.070 4347.120 4766.530 ;
        RECT 4347.960 4766.070 4493.210 4766.530 ;
        RECT 4494.070 4766.070 4503.210 4766.530 ;
        RECT 4504.070 4766.070 4530.520 4766.530 ;
        RECT 4531.360 4766.070 4533.280 4766.530 ;
        RECT 4534.120 4766.070 4536.500 4766.530 ;
        RECT 4537.340 4766.070 4539.720 4766.530 ;
        RECT 4540.560 4766.070 4548.920 4766.530 ;
        RECT 4549.760 4766.070 4551.680 4766.530 ;
        RECT 4552.520 4766.070 4554.900 4766.530 ;
        RECT 4555.740 4766.070 4558.120 4766.530 ;
        RECT 4558.960 4766.070 4570.540 4766.530 ;
        RECT 4571.380 4766.070 4573.300 4766.530 ;
        RECT 4574.140 4766.070 4576.520 4766.530 ;
        RECT 0.090 4765.940 4576.520 4766.070 ;
        RECT 4577.360 4766.070 4579.740 4766.530 ;
        RECT 4580.580 4766.070 4582.105 4766.530 ;
        RECT 4583.735 4766.070 4585.720 4766.530 ;
        RECT 4586.560 4766.070 4591.520 4766.530 ;
        RECT 4592.720 4766.070 4594.920 4766.530 ;
        RECT 4595.760 4766.070 4604.120 4766.530 ;
        RECT 4604.960 4766.070 4749.210 4766.530 ;
        RECT 4750.070 4766.070 4759.210 4766.530 ;
        RECT 4760.070 4766.070 4788.520 4766.530 ;
        RECT 4789.360 4766.070 4791.280 4766.530 ;
        RECT 4792.120 4766.070 4794.500 4766.530 ;
        RECT 4795.340 4766.070 4797.720 4766.530 ;
        RECT 4798.560 4766.070 4806.920 4766.530 ;
        RECT 4807.760 4766.070 4809.680 4766.530 ;
        RECT 4810.520 4766.070 4812.900 4766.530 ;
        RECT 4813.740 4766.070 4816.120 4766.530 ;
        RECT 4816.960 4766.070 4828.540 4766.530 ;
        RECT 4829.380 4766.070 4831.300 4766.530 ;
        RECT 4832.140 4766.070 4834.520 4766.530 ;
        RECT 4835.360 4766.070 4837.740 4766.530 ;
        RECT 4838.580 4766.070 4840.105 4766.530 ;
        RECT 4841.735 4766.070 4843.720 4766.530 ;
        RECT 4844.560 4766.070 4849.520 4766.530 ;
        RECT 4850.720 4766.070 4852.920 4766.530 ;
        RECT 4853.760 4766.070 4862.120 4766.530 ;
        RECT 4862.960 4766.070 5271.210 4766.530 ;
        RECT 5272.070 4766.070 5281.210 4766.530 ;
        RECT 5282.070 4766.070 5297.520 4766.530 ;
        RECT 5298.360 4766.070 5300.280 4766.530 ;
        RECT 5301.120 4766.070 5303.500 4766.530 ;
        RECT 5304.340 4766.070 5306.720 4766.530 ;
        RECT 5307.560 4766.070 5315.920 4766.530 ;
        RECT 5316.760 4766.070 5318.680 4766.530 ;
        RECT 5319.520 4766.070 5321.900 4766.530 ;
        RECT 5322.740 4766.070 5325.120 4766.530 ;
        RECT 5325.960 4766.070 5337.540 4766.530 ;
        RECT 5338.380 4766.070 5340.300 4766.530 ;
        RECT 5341.140 4766.070 5343.520 4766.530 ;
        RECT 5344.360 4766.070 5346.740 4766.530 ;
        RECT 5347.580 4766.070 5349.105 4766.530 ;
        RECT 5350.735 4766.070 5352.720 4766.530 ;
        RECT 5353.560 4766.070 5358.520 4766.530 ;
        RECT 5359.720 4766.070 5361.920 4766.530 ;
        RECT 5362.760 4766.070 5371.120 4766.530 ;
        RECT 5371.960 4766.070 5716.210 4766.530 ;
        RECT 5717.070 4766.070 5726.210 4766.530 ;
        RECT 5727.070 4766.070 5742.520 4766.530 ;
        RECT 5743.360 4766.070 5745.280 4766.530 ;
        RECT 5746.120 4766.070 5748.500 4766.530 ;
        RECT 5749.340 4766.070 5751.720 4766.530 ;
        RECT 5752.560 4766.070 5760.920 4766.530 ;
        RECT 5761.760 4766.070 5763.680 4766.530 ;
        RECT 5764.520 4766.070 5766.900 4766.530 ;
        RECT 5767.740 4766.070 5770.120 4766.530 ;
        RECT 5770.960 4766.070 5782.540 4766.530 ;
        RECT 5783.380 4766.070 5785.300 4766.530 ;
        RECT 5786.140 4766.070 5788.520 4766.530 ;
        RECT 5789.360 4766.070 5791.740 4766.530 ;
        RECT 5792.580 4766.070 5794.105 4766.530 ;
        RECT 5795.735 4766.070 5797.720 4766.530 ;
        RECT 5798.560 4766.070 5803.520 4766.530 ;
        RECT 5804.720 4766.070 5806.920 4766.530 ;
        RECT 5807.760 4766.070 5816.120 4766.530 ;
        RECT 5816.960 4766.070 5972.210 4766.530 ;
        RECT 5973.070 4766.070 5982.210 4766.530 ;
        RECT 5983.070 4766.070 5999.520 4766.530 ;
        RECT 6000.360 4766.070 6002.280 4766.530 ;
        RECT 6003.120 4766.070 6005.500 4766.530 ;
        RECT 6006.340 4766.070 6008.720 4766.530 ;
        RECT 6009.560 4766.070 6017.920 4766.530 ;
        RECT 6018.760 4766.070 6020.680 4766.530 ;
        RECT 6021.520 4766.070 6023.900 4766.530 ;
        RECT 6024.740 4766.070 6027.120 4766.530 ;
        RECT 6027.960 4766.070 6039.540 4766.530 ;
        RECT 6040.380 4766.070 6042.300 4766.530 ;
        RECT 6043.140 4766.070 6045.520 4766.530 ;
        RECT 6046.360 4766.070 6048.740 4766.530 ;
        RECT 6049.580 4766.070 6051.105 4766.530 ;
        RECT 6052.735 4766.070 6054.720 4766.530 ;
        RECT 6055.560 4766.070 6060.520 4766.530 ;
        RECT 6061.720 4766.070 6063.920 4766.530 ;
        RECT 6064.760 4766.070 6073.120 4766.530 ;
        RECT 6073.960 4766.070 6469.210 4766.530 ;
        RECT 6470.070 4766.070 6479.210 4766.530 ;
        RECT 6480.070 4766.070 6508.520 4766.530 ;
        RECT 6509.360 4766.070 6511.280 4766.530 ;
        RECT 6512.120 4766.070 6514.500 4766.530 ;
        RECT 6515.340 4766.070 6517.720 4766.530 ;
        RECT 6518.560 4766.070 6526.920 4766.530 ;
        RECT 6527.760 4766.070 6529.680 4766.530 ;
        RECT 6530.520 4766.070 6532.900 4766.530 ;
        RECT 6533.740 4766.070 6536.120 4766.530 ;
        RECT 6536.960 4766.070 6548.540 4766.530 ;
        RECT 6549.380 4766.070 6551.300 4766.530 ;
        RECT 6552.140 4766.070 6554.520 4766.530 ;
        RECT 6555.360 4766.070 6557.740 4766.530 ;
        RECT 6558.580 4766.070 6560.105 4766.530 ;
        RECT 6561.735 4766.070 6563.720 4766.530 ;
        RECT 6564.560 4766.070 6569.520 4766.530 ;
        RECT 6570.720 4766.070 6572.920 4766.530 ;
        RECT 6573.760 4766.070 6582.120 4766.530 ;
        RECT 6582.960 4766.070 6754.550 4766.530 ;
        RECT 4577.360 4765.940 6754.550 4766.070 ;
        RECT 0.090 0.560 6754.550 4765.940 ;
        RECT 0.090 0.070 497.600 0.560 ;
        RECT 498.440 0.070 550.540 0.560 ;
        RECT 551.380 0.070 725.670 0.560 ;
        RECT 726.510 0.070 734.870 0.560 ;
        RECT 735.710 0.070 737.910 0.560 ;
        RECT 739.110 0.070 744.070 0.560 ;
        RECT 744.910 0.070 746.895 0.560 ;
        RECT 748.525 0.070 750.050 0.560 ;
        RECT 750.890 0.070 753.270 0.560 ;
        RECT 754.110 0.070 756.490 0.560 ;
        RECT 757.330 0.070 759.250 0.560 ;
        RECT 760.090 0.070 771.670 0.560 ;
        RECT 772.510 0.070 774.890 0.560 ;
        RECT 775.730 0.070 778.110 0.560 ;
        RECT 778.950 0.070 780.870 0.560 ;
        RECT 781.710 0.070 790.070 0.560 ;
        RECT 790.910 0.070 793.290 0.560 ;
        RECT 794.130 0.070 796.510 0.560 ;
        RECT 797.350 0.070 799.270 0.560 ;
        RECT 800.110 0.070 802.620 0.560 ;
        RECT 803.440 0.070 818.675 0.560 ;
        RECT 819.495 0.070 1268.670 0.560 ;
        RECT 1269.510 0.070 1277.870 0.560 ;
        RECT 1278.710 0.070 1280.910 0.560 ;
        RECT 1282.110 0.070 1287.070 0.560 ;
        RECT 1287.910 0.070 1289.895 0.560 ;
        RECT 1291.525 0.070 1293.050 0.560 ;
        RECT 1293.890 0.070 1296.270 0.560 ;
        RECT 1297.110 0.070 1299.490 0.560 ;
        RECT 1300.330 0.070 1302.250 0.560 ;
        RECT 1303.090 0.070 1314.670 0.560 ;
        RECT 1315.510 0.070 1317.890 0.560 ;
        RECT 1318.730 0.070 1321.110 0.560 ;
        RECT 1321.950 0.070 1323.870 0.560 ;
        RECT 1324.710 0.070 1333.070 0.560 ;
        RECT 1333.910 0.070 1336.290 0.560 ;
        RECT 1337.130 0.070 1339.510 0.560 ;
        RECT 1340.350 0.070 1342.270 0.560 ;
        RECT 1343.110 0.070 1345.620 0.560 ;
        RECT 1346.440 0.070 1366.520 0.560 ;
        RECT 1367.340 0.070 1542.670 0.560 ;
        RECT 1543.510 0.070 1551.870 0.560 ;
        RECT 1552.710 0.070 1554.910 0.560 ;
        RECT 1556.110 0.070 1561.070 0.560 ;
        RECT 1561.910 0.070 1563.895 0.560 ;
        RECT 1565.525 0.070 1567.050 0.560 ;
        RECT 1567.890 0.070 1570.270 0.560 ;
        RECT 1571.110 0.070 1573.490 0.560 ;
        RECT 1574.330 0.070 1576.250 0.560 ;
        RECT 1577.090 0.070 1588.670 0.560 ;
        RECT 1589.510 0.070 1591.890 0.560 ;
        RECT 1592.730 0.070 1595.110 0.560 ;
        RECT 1595.950 0.070 1597.870 0.560 ;
        RECT 1598.710 0.070 1607.070 0.560 ;
        RECT 1607.910 0.070 1610.290 0.560 ;
        RECT 1611.130 0.070 1613.510 0.560 ;
        RECT 1614.350 0.070 1616.270 0.560 ;
        RECT 1617.110 0.070 1619.620 0.560 ;
        RECT 1620.440 0.070 1640.545 0.560 ;
        RECT 1641.365 0.070 1816.670 0.560 ;
        RECT 1817.510 0.070 1825.870 0.560 ;
        RECT 1826.710 0.070 1828.910 0.560 ;
        RECT 1830.110 0.070 1835.070 0.560 ;
        RECT 1835.910 0.070 1837.895 0.560 ;
        RECT 1839.525 0.070 1841.050 0.560 ;
        RECT 1841.890 0.070 1844.270 0.560 ;
        RECT 1845.110 0.070 1847.490 0.560 ;
        RECT 1848.330 0.070 1850.250 0.560 ;
        RECT 1851.090 0.070 1862.670 0.560 ;
        RECT 1863.510 0.070 1865.890 0.560 ;
        RECT 1866.730 0.070 1869.110 0.560 ;
        RECT 1869.950 0.070 1871.870 0.560 ;
        RECT 1872.710 0.070 1881.070 0.560 ;
        RECT 1881.910 0.070 1884.290 0.560 ;
        RECT 1885.130 0.070 1887.510 0.560 ;
        RECT 1888.350 0.070 1890.270 0.560 ;
        RECT 1891.110 0.070 1893.620 0.560 ;
        RECT 1894.440 0.070 1914.610 0.560 ;
        RECT 1915.430 0.070 2090.670 0.560 ;
        RECT 2091.510 0.070 2099.870 0.560 ;
        RECT 2100.710 0.070 2102.910 0.560 ;
        RECT 2104.110 0.070 2109.070 0.560 ;
        RECT 2109.910 0.070 2111.895 0.560 ;
        RECT 2113.525 0.070 2115.050 0.560 ;
        RECT 2115.890 0.070 2118.270 0.560 ;
        RECT 2119.110 0.070 2121.490 0.560 ;
        RECT 2122.330 0.070 2124.250 0.560 ;
        RECT 2125.090 0.070 2136.670 0.560 ;
        RECT 2137.510 0.070 2139.890 0.560 ;
        RECT 2140.730 0.070 2143.110 0.560 ;
        RECT 2143.950 0.070 2145.870 0.560 ;
        RECT 2146.710 0.070 2155.070 0.560 ;
        RECT 2155.910 0.070 2158.290 0.560 ;
        RECT 2159.130 0.070 2161.510 0.560 ;
        RECT 2162.350 0.070 2164.270 0.560 ;
        RECT 2165.110 0.070 2167.620 0.560 ;
        RECT 2168.440 0.070 2188.610 0.560 ;
        RECT 2189.430 0.070 2364.670 0.560 ;
        RECT 2365.510 0.070 2373.870 0.560 ;
        RECT 2374.710 0.070 2376.910 0.560 ;
        RECT 2378.110 0.070 2383.070 0.560 ;
        RECT 2383.910 0.070 2385.895 0.560 ;
        RECT 2387.525 0.070 2389.050 0.560 ;
        RECT 2389.890 0.070 2392.270 0.560 ;
        RECT 2393.110 0.070 2395.490 0.560 ;
        RECT 2396.330 0.070 2398.250 0.560 ;
        RECT 2399.090 0.070 2410.670 0.560 ;
        RECT 2411.510 0.070 2413.890 0.560 ;
        RECT 2414.730 0.070 2417.110 0.560 ;
        RECT 2417.950 0.070 2419.870 0.560 ;
        RECT 2420.710 0.070 2429.070 0.560 ;
        RECT 2429.910 0.070 2432.290 0.560 ;
        RECT 2433.130 0.070 2435.510 0.560 ;
        RECT 2436.350 0.070 2438.270 0.560 ;
        RECT 2439.110 0.070 2441.620 0.560 ;
        RECT 2442.440 0.070 2462.895 0.560 ;
        RECT 2463.715 0.070 3179.150 0.560 ;
        RECT 3179.990 0.070 3188.350 0.560 ;
        RECT 3189.190 0.070 3191.390 0.560 ;
        RECT 3192.590 0.070 3197.550 0.560 ;
        RECT 3198.390 0.070 3200.375 0.560 ;
        RECT 3202.005 0.070 3203.530 0.560 ;
        RECT 3204.370 0.070 3206.750 0.560 ;
        RECT 3207.590 0.070 3209.970 0.560 ;
        RECT 3210.810 0.070 3212.730 0.560 ;
        RECT 3213.570 0.070 3225.150 0.560 ;
        RECT 3225.990 0.070 3228.370 0.560 ;
        RECT 3229.210 0.070 3231.590 0.560 ;
        RECT 3232.430 0.070 3234.350 0.560 ;
        RECT 3235.190 0.070 3243.550 0.560 ;
        RECT 3244.390 0.070 3246.770 0.560 ;
        RECT 3247.610 0.070 3249.990 0.560 ;
        RECT 3250.830 0.070 3252.750 0.560 ;
        RECT 3253.590 0.070 3256.100 0.560 ;
        RECT 3256.920 0.070 3272.155 0.560 ;
        RECT 3272.975 0.070 3453.150 0.560 ;
        RECT 3453.990 0.070 3462.350 0.560 ;
        RECT 3463.190 0.070 3465.390 0.560 ;
        RECT 3466.590 0.070 3471.550 0.560 ;
        RECT 3472.390 0.070 3474.375 0.560 ;
        RECT 3476.005 0.070 3477.530 0.560 ;
        RECT 3478.370 0.070 3480.750 0.560 ;
        RECT 3481.590 0.070 3483.970 0.560 ;
        RECT 3484.810 0.070 3486.730 0.560 ;
        RECT 3487.570 0.070 3499.150 0.560 ;
        RECT 3499.990 0.070 3502.370 0.560 ;
        RECT 3503.210 0.070 3505.590 0.560 ;
        RECT 3506.430 0.070 3508.350 0.560 ;
        RECT 3509.190 0.070 3517.550 0.560 ;
        RECT 3518.390 0.070 3520.770 0.560 ;
        RECT 3521.610 0.070 3523.990 0.560 ;
        RECT 3524.830 0.070 3526.750 0.560 ;
        RECT 3527.590 0.070 3530.100 0.560 ;
        RECT 3530.920 0.070 3546.155 0.560 ;
        RECT 3546.975 0.070 4313.670 0.560 ;
        RECT 4314.510 0.070 4322.870 0.560 ;
        RECT 4323.710 0.070 4325.910 0.560 ;
        RECT 4327.110 0.070 4332.070 0.560 ;
        RECT 4332.910 0.070 4334.895 0.560 ;
        RECT 4336.525 0.070 4338.050 0.560 ;
        RECT 4338.890 0.070 4341.270 0.560 ;
        RECT 4342.110 0.070 4344.490 0.560 ;
        RECT 4345.330 0.070 4347.250 0.560 ;
        RECT 4348.090 0.070 4359.670 0.560 ;
        RECT 4360.510 0.070 4362.890 0.560 ;
        RECT 4363.730 0.070 4366.110 0.560 ;
        RECT 4366.950 0.070 4368.870 0.560 ;
        RECT 4369.710 0.070 4378.070 0.560 ;
        RECT 4378.910 0.070 4381.290 0.560 ;
        RECT 4382.130 0.070 4384.510 0.560 ;
        RECT 4385.350 0.070 4387.270 0.560 ;
        RECT 4388.110 0.070 4390.620 0.560 ;
        RECT 4391.440 0.070 4406.675 0.560 ;
        RECT 4407.495 0.070 4856.670 0.560 ;
        RECT 4857.510 0.070 4865.870 0.560 ;
        RECT 4866.710 0.070 4868.910 0.560 ;
        RECT 4870.110 0.070 4875.070 0.560 ;
        RECT 4875.910 0.070 4877.895 0.560 ;
        RECT 4879.525 0.070 4881.050 0.560 ;
        RECT 4881.890 0.070 4884.270 0.560 ;
        RECT 4885.110 0.070 4887.490 0.560 ;
        RECT 4888.330 0.070 4890.250 0.560 ;
        RECT 4891.090 0.070 4902.670 0.560 ;
        RECT 4903.510 0.070 4905.890 0.560 ;
        RECT 4906.730 0.070 4909.110 0.560 ;
        RECT 4909.950 0.070 4911.870 0.560 ;
        RECT 4912.710 0.070 4921.070 0.560 ;
        RECT 4921.910 0.070 4924.290 0.560 ;
        RECT 4925.130 0.070 4927.510 0.560 ;
        RECT 4928.350 0.070 4930.270 0.560 ;
        RECT 4931.110 0.070 4933.620 0.560 ;
        RECT 4934.440 0.070 4954.520 0.560 ;
        RECT 4955.340 0.070 5130.670 0.560 ;
        RECT 5131.510 0.070 5139.870 0.560 ;
        RECT 5140.710 0.070 5142.910 0.560 ;
        RECT 5144.110 0.070 5149.070 0.560 ;
        RECT 5149.910 0.070 5151.895 0.560 ;
        RECT 5153.525 0.070 5155.050 0.560 ;
        RECT 5155.890 0.070 5158.270 0.560 ;
        RECT 5159.110 0.070 5161.490 0.560 ;
        RECT 5162.330 0.070 5164.250 0.560 ;
        RECT 5165.090 0.070 5176.670 0.560 ;
        RECT 5177.510 0.070 5179.890 0.560 ;
        RECT 5180.730 0.070 5183.110 0.560 ;
        RECT 5183.950 0.070 5185.870 0.560 ;
        RECT 5186.710 0.070 5195.070 0.560 ;
        RECT 5195.910 0.070 5198.290 0.560 ;
        RECT 5199.130 0.070 5201.510 0.560 ;
        RECT 5202.350 0.070 5204.270 0.560 ;
        RECT 5205.110 0.070 5207.620 0.560 ;
        RECT 5208.440 0.070 5228.545 0.560 ;
        RECT 5229.365 0.070 5404.670 0.560 ;
        RECT 5405.510 0.070 5413.870 0.560 ;
        RECT 5414.710 0.070 5416.910 0.560 ;
        RECT 5418.110 0.070 5423.070 0.560 ;
        RECT 5423.910 0.070 5425.895 0.560 ;
        RECT 5427.525 0.070 5429.050 0.560 ;
        RECT 5429.890 0.070 5432.270 0.560 ;
        RECT 5433.110 0.070 5435.490 0.560 ;
        RECT 5436.330 0.070 5438.250 0.560 ;
        RECT 5439.090 0.070 5450.670 0.560 ;
        RECT 5451.510 0.070 5453.890 0.560 ;
        RECT 5454.730 0.070 5457.110 0.560 ;
        RECT 5457.950 0.070 5459.870 0.560 ;
        RECT 5460.710 0.070 5469.070 0.560 ;
        RECT 5469.910 0.070 5472.290 0.560 ;
        RECT 5473.130 0.070 5475.510 0.560 ;
        RECT 5476.350 0.070 5478.270 0.560 ;
        RECT 5479.110 0.070 5481.620 0.560 ;
        RECT 5482.440 0.070 5502.610 0.560 ;
        RECT 5503.430 0.070 5678.670 0.560 ;
        RECT 5679.510 0.070 5687.870 0.560 ;
        RECT 5688.710 0.070 5690.910 0.560 ;
        RECT 5692.110 0.070 5697.070 0.560 ;
        RECT 5697.910 0.070 5699.895 0.560 ;
        RECT 5701.525 0.070 5703.050 0.560 ;
        RECT 5703.890 0.070 5706.270 0.560 ;
        RECT 5707.110 0.070 5709.490 0.560 ;
        RECT 5710.330 0.070 5712.250 0.560 ;
        RECT 5713.090 0.070 5724.670 0.560 ;
        RECT 5725.510 0.070 5727.890 0.560 ;
        RECT 5728.730 0.070 5731.110 0.560 ;
        RECT 5731.950 0.070 5733.870 0.560 ;
        RECT 5734.710 0.070 5743.070 0.560 ;
        RECT 5743.910 0.070 5746.290 0.560 ;
        RECT 5747.130 0.070 5749.510 0.560 ;
        RECT 5750.350 0.070 5752.270 0.560 ;
        RECT 5753.110 0.070 5755.620 0.560 ;
        RECT 5756.440 0.070 5776.610 0.560 ;
        RECT 5777.430 0.070 5952.670 0.560 ;
        RECT 5953.510 0.070 5961.870 0.560 ;
        RECT 5962.710 0.070 5964.910 0.560 ;
        RECT 5966.110 0.070 5971.070 0.560 ;
        RECT 5971.910 0.070 5973.895 0.560 ;
        RECT 5975.525 0.070 5977.050 0.560 ;
        RECT 5977.890 0.070 5980.270 0.560 ;
        RECT 5981.110 0.070 5983.490 0.560 ;
        RECT 5984.330 0.070 5986.250 0.560 ;
        RECT 5987.090 0.070 5998.670 0.560 ;
        RECT 5999.510 0.070 6001.890 0.560 ;
        RECT 6002.730 0.070 6005.110 0.560 ;
        RECT 6005.950 0.070 6007.870 0.560 ;
        RECT 6008.710 0.070 6017.070 0.560 ;
        RECT 6017.910 0.070 6020.290 0.560 ;
        RECT 6021.130 0.070 6023.510 0.560 ;
        RECT 6024.350 0.070 6026.270 0.560 ;
        RECT 6027.110 0.070 6029.620 0.560 ;
        RECT 6030.440 0.070 6050.895 0.560 ;
        RECT 6051.715 0.070 6613.130 0.560 ;
        RECT 6613.950 0.070 6614.250 0.560 ;
        RECT 6615.070 0.070 6615.370 0.560 ;
        RECT 6616.190 0.070 6616.490 0.560 ;
        RECT 6617.310 0.070 6617.610 0.560 ;
        RECT 6618.430 0.070 6618.730 0.560 ;
        RECT 6619.550 0.070 6619.850 0.560 ;
        RECT 6620.670 0.070 6620.970 0.560 ;
        RECT 6621.790 0.070 6622.090 0.560 ;
        RECT 6622.910 0.070 6623.210 0.560 ;
        RECT 6624.030 0.070 6624.330 0.560 ;
        RECT 6625.150 0.070 6625.450 0.560 ;
        RECT 6626.270 0.070 6626.570 0.560 ;
        RECT 6627.390 0.070 6627.690 0.560 ;
        RECT 6628.510 0.070 6628.810 0.560 ;
        RECT 6629.630 0.070 6629.930 0.560 ;
        RECT 6630.750 0.070 6631.050 0.560 ;
        RECT 6631.870 0.070 6632.170 0.560 ;
        RECT 6632.990 0.070 6633.290 0.560 ;
        RECT 6634.110 0.070 6634.410 0.560 ;
        RECT 6635.230 0.070 6635.530 0.560 ;
        RECT 6636.350 0.070 6636.650 0.560 ;
        RECT 6637.470 0.070 6637.770 0.560 ;
        RECT 6638.590 0.070 6638.890 0.560 ;
        RECT 6639.710 0.070 6640.010 0.560 ;
        RECT 6640.830 0.070 6641.130 0.560 ;
        RECT 6641.950 0.070 6642.250 0.560 ;
        RECT 6643.070 0.070 6643.370 0.560 ;
        RECT 6644.190 0.070 6644.490 0.560 ;
        RECT 6645.310 0.070 6645.610 0.560 ;
        RECT 6646.430 0.070 6646.730 0.560 ;
        RECT 6647.550 0.070 6647.850 0.560 ;
        RECT 6648.670 0.070 6754.550 0.560 ;
      LAYER met3 ;
        RECT 0.000 4765.930 1456.410 4766.610 ;
        RECT 1481.110 4765.930 1506.310 4766.610 ;
        RECT 1531.010 4765.930 2667.410 4766.610 ;
        RECT 2692.110 4765.930 2717.310 4766.610 ;
        RECT 2742.010 4765.930 5044.410 4766.610 ;
        RECT 5069.110 4765.930 5094.310 4766.610 ;
        RECT 5119.010 4765.930 6255.410 4766.610 ;
        RECT 6280.110 4765.930 6305.310 4766.610 ;
        RECT 6330.010 4765.930 6754.630 4766.610 ;
        RECT 0.000 4645.740 6754.630 4765.930 ;
        RECT 0.000 4644.630 6753.930 4645.740 ;
        RECT 0.000 4636.110 6754.630 4644.630 ;
        RECT 0.700 4635.740 6754.630 4636.110 ;
        RECT 0.700 4634.960 6753.930 4635.740 ;
        RECT 0.000 4634.630 6753.930 4634.960 ;
        RECT 0.000 4626.910 6754.630 4634.630 ;
        RECT 0.700 4626.270 6754.630 4626.910 ;
        RECT 0.700 4625.760 6753.930 4626.270 ;
        RECT 0.000 4625.120 6753.930 4625.760 ;
        RECT 0.000 4623.840 6754.630 4625.120 ;
        RECT 0.700 4623.510 6754.630 4623.840 ;
        RECT 0.700 4622.400 6753.930 4623.510 ;
        RECT 0.000 4622.360 6753.930 4622.400 ;
        RECT 0.000 4620.290 6754.630 4622.360 ;
        RECT 0.000 4619.140 6753.930 4620.290 ;
        RECT 0.000 4617.710 6754.630 4619.140 ;
        RECT 0.700 4617.070 6754.630 4617.710 ;
        RECT 0.700 4616.560 6753.930 4617.070 ;
        RECT 0.000 4615.920 6753.930 4616.560 ;
        RECT 0.000 4614.855 6754.630 4615.920 ;
        RECT 0.700 4612.985 6754.630 4614.855 ;
        RECT 0.000 4611.730 6754.630 4612.985 ;
        RECT 0.700 4610.580 6754.630 4611.730 ;
        RECT 0.000 4608.510 6754.630 4610.580 ;
        RECT 0.700 4607.870 6754.630 4608.510 ;
        RECT 0.700 4607.360 6753.930 4607.870 ;
        RECT 0.000 4606.720 6753.930 4607.360 ;
        RECT 0.000 4605.290 6754.630 4606.720 ;
        RECT 0.700 4605.110 6754.630 4605.290 ;
        RECT 0.700 4604.140 6753.930 4605.110 ;
        RECT 0.000 4603.960 6753.930 4604.140 ;
        RECT 0.000 4602.530 6754.630 4603.960 ;
        RECT 0.700 4601.890 6754.630 4602.530 ;
        RECT 0.700 4601.380 6753.930 4601.890 ;
        RECT 0.000 4600.740 6753.930 4601.380 ;
        RECT 0.000 4598.670 6754.630 4600.740 ;
        RECT 0.000 4597.520 6753.930 4598.670 ;
        RECT 0.000 4590.110 6754.630 4597.520 ;
        RECT 0.700 4588.960 6754.630 4590.110 ;
        RECT 0.000 4586.890 6754.630 4588.960 ;
        RECT 0.700 4586.250 6754.630 4586.890 ;
        RECT 0.700 4585.740 6753.930 4586.250 ;
        RECT 0.000 4585.100 6753.930 4585.740 ;
        RECT 0.000 4583.670 6754.630 4585.100 ;
        RECT 0.700 4583.490 6754.630 4583.670 ;
        RECT 0.700 4582.520 6753.930 4583.490 ;
        RECT 0.000 4582.340 6753.930 4582.520 ;
        RECT 0.000 4580.910 6754.630 4582.340 ;
        RECT 0.700 4580.270 6754.630 4580.910 ;
        RECT 0.700 4579.760 6753.930 4580.270 ;
        RECT 0.000 4579.120 6753.930 4579.760 ;
        RECT 0.000 4577.050 6754.630 4579.120 ;
        RECT 0.000 4575.900 6753.930 4577.050 ;
        RECT 0.000 4574.645 6754.630 4575.900 ;
        RECT 0.000 4572.775 6753.930 4574.645 ;
        RECT 0.000 4571.710 6754.630 4572.775 ;
        RECT 0.700 4571.070 6754.630 4571.710 ;
        RECT 0.700 4570.560 6753.930 4571.070 ;
        RECT 0.000 4569.920 6753.930 4570.560 ;
        RECT 0.000 4568.490 6754.630 4569.920 ;
        RECT 0.700 4567.340 6754.630 4568.490 ;
        RECT 0.000 4565.270 6754.630 4567.340 ;
        RECT 0.700 4565.230 6754.630 4565.270 ;
        RECT 0.700 4564.120 6753.930 4565.230 ;
        RECT 0.000 4563.790 6753.930 4564.120 ;
        RECT 0.000 4562.510 6754.630 4563.790 ;
        RECT 0.700 4561.870 6754.630 4562.510 ;
        RECT 0.700 4561.360 6753.930 4561.870 ;
        RECT 0.000 4560.720 6753.930 4561.360 ;
        RECT 0.000 4552.670 6754.630 4560.720 ;
        RECT 0.000 4551.520 6753.930 4552.670 ;
        RECT 0.000 4533.920 6754.630 4551.520 ;
        RECT 0.700 4532.820 6754.630 4533.920 ;
        RECT 0.000 4523.920 6754.630 4532.820 ;
        RECT 0.700 4522.820 6754.630 4523.920 ;
        RECT 0.000 4424.420 6754.630 4522.820 ;
        RECT 0.700 4402.210 6754.630 4424.420 ;
        RECT 0.700 4399.670 6753.930 4402.210 ;
        RECT 0.000 4398.980 6753.930 4399.670 ;
        RECT 0.700 4377.810 6753.930 4398.980 ;
        RECT 0.700 4377.805 6755.815 4377.810 ;
        RECT 0.700 4377.410 6753.930 4377.805 ;
        RECT 0.700 4376.760 6754.630 4377.410 ;
        RECT 0.700 4374.870 6753.930 4376.760 ;
        RECT 0.000 4374.220 6753.930 4374.870 ;
        RECT 0.700 4352.650 6753.930 4374.220 ;
        RECT 0.700 4351.960 6754.630 4352.650 ;
        RECT 0.700 4349.420 6753.930 4351.960 ;
        RECT 0.000 4327.210 6753.930 4349.420 ;
        RECT 0.000 4213.010 6754.630 4327.210 ;
        RECT 0.700 4195.740 6754.630 4213.010 ;
        RECT 0.700 4194.630 6753.930 4195.740 ;
        RECT 0.700 4188.310 6754.630 4194.630 ;
        RECT 0.000 4185.740 6754.630 4188.310 ;
        RECT 0.000 4184.630 6753.930 4185.740 ;
        RECT 0.000 4180.270 6754.630 4184.630 ;
        RECT 0.000 4179.120 6753.930 4180.270 ;
        RECT 0.000 4177.510 6754.630 4179.120 ;
        RECT 0.000 4176.360 6753.930 4177.510 ;
        RECT 0.000 4174.290 6754.630 4176.360 ;
        RECT 0.000 4173.140 6753.930 4174.290 ;
        RECT 0.000 4171.070 6754.630 4173.140 ;
        RECT 0.000 4169.920 6753.930 4171.070 ;
        RECT 0.000 4163.110 6754.630 4169.920 ;
        RECT 0.700 4161.870 6754.630 4163.110 ;
        RECT 0.700 4160.720 6753.930 4161.870 ;
        RECT 0.700 4159.110 6754.630 4160.720 ;
        RECT 0.700 4157.960 6753.930 4159.110 ;
        RECT 0.700 4155.890 6754.630 4157.960 ;
        RECT 0.700 4154.740 6753.930 4155.890 ;
        RECT 0.700 4152.670 6754.630 4154.740 ;
        RECT 0.700 4151.520 6753.930 4152.670 ;
        RECT 0.700 4140.250 6754.630 4151.520 ;
        RECT 0.700 4139.100 6753.930 4140.250 ;
        RECT 0.700 4138.410 6754.630 4139.100 ;
        RECT 0.000 4137.490 6754.630 4138.410 ;
        RECT 0.000 4136.340 6753.930 4137.490 ;
        RECT 0.000 4134.270 6754.630 4136.340 ;
        RECT 0.000 4133.120 6753.930 4134.270 ;
        RECT 0.000 4131.050 6754.630 4133.120 ;
        RECT 0.000 4129.900 6753.930 4131.050 ;
        RECT 0.000 4128.645 6754.630 4129.900 ;
        RECT 0.000 4126.775 6753.930 4128.645 ;
        RECT 0.000 4125.070 6754.630 4126.775 ;
        RECT 0.000 4123.920 6753.930 4125.070 ;
        RECT 0.000 4119.230 6754.630 4123.920 ;
        RECT 0.000 4117.790 6753.930 4119.230 ;
        RECT 0.000 4115.870 6754.630 4117.790 ;
        RECT 0.000 4114.720 6753.930 4115.870 ;
        RECT 0.000 4106.670 6754.630 4114.720 ;
        RECT 0.000 4105.520 6753.930 4106.670 ;
        RECT 0.000 4002.010 6754.630 4105.520 ;
        RECT 0.700 3977.310 6754.630 4002.010 ;
        RECT 0.000 3956.220 6754.630 3977.310 ;
        RECT 0.000 3952.110 6753.930 3956.220 ;
        RECT 0.700 3931.520 6753.930 3952.110 ;
        RECT 0.700 3927.410 6754.630 3931.520 ;
        RECT 0.000 3906.330 6754.630 3927.410 ;
        RECT 0.000 3881.630 6753.930 3906.330 ;
        RECT 0.000 3787.110 6754.630 3881.630 ;
        RECT 0.700 3785.960 6754.630 3787.110 ;
        RECT 0.000 3777.910 6754.630 3785.960 ;
        RECT 0.700 3776.760 6754.630 3777.910 ;
        RECT 0.000 3774.840 6754.630 3776.760 ;
        RECT 0.700 3773.400 6754.630 3774.840 ;
        RECT 0.000 3768.710 6754.630 3773.400 ;
        RECT 0.700 3767.560 6754.630 3768.710 ;
        RECT 0.000 3765.855 6754.630 3767.560 ;
        RECT 0.700 3763.985 6754.630 3765.855 ;
        RECT 0.000 3762.730 6754.630 3763.985 ;
        RECT 0.700 3761.580 6754.630 3762.730 ;
        RECT 0.000 3759.510 6754.630 3761.580 ;
        RECT 0.700 3758.360 6754.630 3759.510 ;
        RECT 0.000 3756.290 6754.630 3758.360 ;
        RECT 0.700 3755.140 6754.630 3756.290 ;
        RECT 0.000 3753.530 6754.630 3755.140 ;
        RECT 0.700 3752.380 6754.630 3753.530 ;
        RECT 0.000 3750.740 6754.630 3752.380 ;
        RECT 0.000 3749.630 6753.930 3750.740 ;
        RECT 0.000 3741.110 6754.630 3749.630 ;
        RECT 0.700 3740.740 6754.630 3741.110 ;
        RECT 0.700 3739.960 6753.930 3740.740 ;
        RECT 0.000 3739.630 6753.930 3739.960 ;
        RECT 0.000 3737.890 6754.630 3739.630 ;
        RECT 0.700 3736.740 6754.630 3737.890 ;
        RECT 0.000 3734.670 6754.630 3736.740 ;
        RECT 0.700 3734.270 6754.630 3734.670 ;
        RECT 0.700 3733.520 6753.930 3734.270 ;
        RECT 0.000 3733.120 6753.930 3733.520 ;
        RECT 0.000 3731.910 6754.630 3733.120 ;
        RECT 0.700 3731.510 6754.630 3731.910 ;
        RECT 0.700 3730.760 6753.930 3731.510 ;
        RECT 0.000 3730.360 6753.930 3730.760 ;
        RECT 0.000 3728.290 6754.630 3730.360 ;
        RECT 0.000 3727.140 6753.930 3728.290 ;
        RECT 0.000 3725.070 6754.630 3727.140 ;
        RECT 0.000 3723.920 6753.930 3725.070 ;
        RECT 0.000 3722.710 6754.630 3723.920 ;
        RECT 0.700 3721.560 6754.630 3722.710 ;
        RECT 0.000 3719.490 6754.630 3721.560 ;
        RECT 0.700 3718.340 6754.630 3719.490 ;
        RECT 0.000 3716.270 6754.630 3718.340 ;
        RECT 0.700 3715.870 6754.630 3716.270 ;
        RECT 0.700 3715.120 6753.930 3715.870 ;
        RECT 0.000 3714.720 6753.930 3715.120 ;
        RECT 0.000 3713.510 6754.630 3714.720 ;
        RECT 0.700 3713.110 6754.630 3713.510 ;
        RECT 0.700 3712.360 6753.930 3713.110 ;
        RECT 0.000 3711.960 6753.930 3712.360 ;
        RECT 0.000 3709.890 6754.630 3711.960 ;
        RECT 0.000 3708.740 6753.930 3709.890 ;
        RECT 0.000 3706.670 6754.630 3708.740 ;
        RECT 0.000 3705.520 6753.930 3706.670 ;
        RECT 0.000 3694.250 6754.630 3705.520 ;
        RECT 0.000 3693.100 6753.930 3694.250 ;
        RECT 0.000 3691.490 6754.630 3693.100 ;
        RECT 0.000 3690.340 6753.930 3691.490 ;
        RECT 0.000 3688.270 6754.630 3690.340 ;
        RECT 0.000 3687.120 6753.930 3688.270 ;
        RECT 0.000 3685.050 6754.630 3687.120 ;
        RECT 0.000 3683.920 6753.930 3685.050 ;
        RECT 0.700 3683.900 6753.930 3683.920 ;
        RECT 0.700 3682.820 6754.630 3683.900 ;
        RECT 0.000 3682.645 6754.630 3682.820 ;
        RECT 0.000 3680.775 6753.930 3682.645 ;
        RECT 0.000 3679.070 6754.630 3680.775 ;
        RECT 0.000 3677.920 6753.930 3679.070 ;
        RECT 0.000 3673.920 6754.630 3677.920 ;
        RECT 0.700 3673.230 6754.630 3673.920 ;
        RECT 0.700 3672.820 6753.930 3673.230 ;
        RECT 0.000 3671.790 6753.930 3672.820 ;
        RECT 0.000 3669.870 6754.630 3671.790 ;
        RECT 0.000 3668.720 6753.930 3669.870 ;
        RECT 0.000 3660.670 6754.630 3668.720 ;
        RECT 0.000 3659.520 6753.930 3660.670 ;
        RECT 0.000 3571.110 6754.630 3659.520 ;
        RECT 0.700 3569.960 6754.630 3571.110 ;
        RECT 0.000 3561.910 6754.630 3569.960 ;
        RECT 0.700 3560.760 6754.630 3561.910 ;
        RECT 0.000 3558.840 6754.630 3560.760 ;
        RECT 0.700 3557.400 6754.630 3558.840 ;
        RECT 0.000 3552.710 6754.630 3557.400 ;
        RECT 0.700 3551.560 6754.630 3552.710 ;
        RECT 0.000 3549.855 6754.630 3551.560 ;
        RECT 0.700 3547.985 6754.630 3549.855 ;
        RECT 0.000 3546.730 6754.630 3547.985 ;
        RECT 0.700 3545.580 6754.630 3546.730 ;
        RECT 0.000 3543.510 6754.630 3545.580 ;
        RECT 0.700 3542.360 6754.630 3543.510 ;
        RECT 0.000 3540.290 6754.630 3542.360 ;
        RECT 0.700 3539.140 6754.630 3540.290 ;
        RECT 0.000 3537.530 6754.630 3539.140 ;
        RECT 0.700 3536.380 6754.630 3537.530 ;
        RECT 0.000 3525.740 6754.630 3536.380 ;
        RECT 0.000 3525.110 6753.930 3525.740 ;
        RECT 0.700 3524.630 6753.930 3525.110 ;
        RECT 0.700 3523.960 6754.630 3524.630 ;
        RECT 0.000 3521.890 6754.630 3523.960 ;
        RECT 0.700 3520.740 6754.630 3521.890 ;
        RECT 0.000 3518.670 6754.630 3520.740 ;
        RECT 0.700 3517.520 6754.630 3518.670 ;
        RECT 0.000 3515.910 6754.630 3517.520 ;
        RECT 0.700 3515.740 6754.630 3515.910 ;
        RECT 0.700 3514.760 6753.930 3515.740 ;
        RECT 0.000 3514.630 6753.930 3514.760 ;
        RECT 0.000 3509.270 6754.630 3514.630 ;
        RECT 0.000 3508.120 6753.930 3509.270 ;
        RECT 0.000 3506.710 6754.630 3508.120 ;
        RECT 0.700 3506.510 6754.630 3506.710 ;
        RECT 0.700 3505.560 6753.930 3506.510 ;
        RECT 0.000 3505.360 6753.930 3505.560 ;
        RECT 0.000 3503.490 6754.630 3505.360 ;
        RECT 0.700 3503.290 6754.630 3503.490 ;
        RECT 0.700 3502.340 6753.930 3503.290 ;
        RECT 0.000 3502.140 6753.930 3502.340 ;
        RECT 0.000 3500.270 6754.630 3502.140 ;
        RECT 0.700 3500.070 6754.630 3500.270 ;
        RECT 0.700 3499.120 6753.930 3500.070 ;
        RECT 0.000 3498.920 6753.930 3499.120 ;
        RECT 0.000 3497.510 6754.630 3498.920 ;
        RECT 0.700 3496.360 6754.630 3497.510 ;
        RECT 0.000 3490.870 6754.630 3496.360 ;
        RECT 0.000 3489.720 6753.930 3490.870 ;
        RECT 0.000 3488.110 6754.630 3489.720 ;
        RECT 0.000 3486.960 6753.930 3488.110 ;
        RECT 0.000 3484.890 6754.630 3486.960 ;
        RECT 0.000 3483.740 6753.930 3484.890 ;
        RECT 0.000 3481.670 6754.630 3483.740 ;
        RECT 0.000 3480.520 6753.930 3481.670 ;
        RECT 0.000 3469.250 6754.630 3480.520 ;
        RECT 0.000 3468.920 6753.930 3469.250 ;
        RECT 0.700 3468.100 6753.930 3468.920 ;
        RECT 0.700 3467.820 6754.630 3468.100 ;
        RECT 0.000 3466.490 6754.630 3467.820 ;
        RECT 0.000 3465.340 6753.930 3466.490 ;
        RECT 0.000 3463.270 6754.630 3465.340 ;
        RECT 0.000 3462.120 6753.930 3463.270 ;
        RECT 0.000 3460.050 6754.630 3462.120 ;
        RECT 0.000 3458.920 6753.930 3460.050 ;
        RECT 0.700 3458.900 6753.930 3458.920 ;
        RECT 0.700 3457.820 6754.630 3458.900 ;
        RECT 0.000 3457.645 6754.630 3457.820 ;
        RECT 0.000 3455.775 6753.930 3457.645 ;
        RECT 0.000 3454.070 6754.630 3455.775 ;
        RECT 0.000 3452.920 6753.930 3454.070 ;
        RECT 0.000 3448.230 6754.630 3452.920 ;
        RECT 0.000 3446.790 6753.930 3448.230 ;
        RECT 0.000 3444.870 6754.630 3446.790 ;
        RECT 0.000 3443.720 6753.930 3444.870 ;
        RECT 0.000 3435.670 6754.630 3443.720 ;
        RECT 0.000 3434.520 6753.930 3435.670 ;
        RECT 0.000 3355.110 6754.630 3434.520 ;
        RECT 0.700 3353.960 6754.630 3355.110 ;
        RECT 0.000 3345.910 6754.630 3353.960 ;
        RECT 0.700 3344.760 6754.630 3345.910 ;
        RECT 0.000 3342.840 6754.630 3344.760 ;
        RECT 0.700 3341.400 6754.630 3342.840 ;
        RECT 0.000 3336.710 6754.630 3341.400 ;
        RECT 0.700 3335.560 6754.630 3336.710 ;
        RECT 0.000 3333.855 6754.630 3335.560 ;
        RECT 0.700 3331.985 6754.630 3333.855 ;
        RECT 0.000 3330.730 6754.630 3331.985 ;
        RECT 0.700 3329.580 6754.630 3330.730 ;
        RECT 0.000 3327.510 6754.630 3329.580 ;
        RECT 0.700 3326.360 6754.630 3327.510 ;
        RECT 0.000 3324.290 6754.630 3326.360 ;
        RECT 0.700 3323.140 6754.630 3324.290 ;
        RECT 0.000 3321.530 6754.630 3323.140 ;
        RECT 0.700 3320.380 6754.630 3321.530 ;
        RECT 0.000 3309.110 6754.630 3320.380 ;
        RECT 0.700 3307.960 6754.630 3309.110 ;
        RECT 0.000 3305.890 6754.630 3307.960 ;
        RECT 0.700 3304.740 6754.630 3305.890 ;
        RECT 0.000 3302.670 6754.630 3304.740 ;
        RECT 0.700 3301.520 6754.630 3302.670 ;
        RECT 0.000 3300.740 6754.630 3301.520 ;
        RECT 0.000 3299.910 6753.930 3300.740 ;
        RECT 0.700 3299.630 6753.930 3299.910 ;
        RECT 0.700 3298.760 6754.630 3299.630 ;
        RECT 0.000 3290.740 6754.630 3298.760 ;
        RECT 0.000 3290.710 6753.930 3290.740 ;
        RECT 0.700 3289.630 6753.930 3290.710 ;
        RECT 0.700 3289.560 6754.630 3289.630 ;
        RECT 0.000 3287.490 6754.630 3289.560 ;
        RECT 0.700 3286.340 6754.630 3287.490 ;
        RECT 0.000 3284.270 6754.630 3286.340 ;
        RECT 0.700 3283.120 6753.930 3284.270 ;
        RECT 0.000 3281.510 6754.630 3283.120 ;
        RECT 0.700 3280.360 6753.930 3281.510 ;
        RECT 0.000 3278.290 6754.630 3280.360 ;
        RECT 0.000 3277.140 6753.930 3278.290 ;
        RECT 0.000 3275.070 6754.630 3277.140 ;
        RECT 0.000 3273.920 6753.930 3275.070 ;
        RECT 0.000 3265.870 6754.630 3273.920 ;
        RECT 0.000 3264.720 6753.930 3265.870 ;
        RECT 0.000 3263.110 6754.630 3264.720 ;
        RECT 0.000 3261.960 6753.930 3263.110 ;
        RECT 0.000 3259.890 6754.630 3261.960 ;
        RECT 0.000 3258.740 6753.930 3259.890 ;
        RECT 0.000 3256.670 6754.630 3258.740 ;
        RECT 0.000 3255.520 6753.930 3256.670 ;
        RECT 0.000 3253.920 6754.630 3255.520 ;
        RECT 0.700 3252.820 6754.630 3253.920 ;
        RECT 0.000 3244.250 6754.630 3252.820 ;
        RECT 0.000 3243.920 6753.930 3244.250 ;
        RECT 0.700 3243.100 6753.930 3243.920 ;
        RECT 0.700 3242.820 6754.630 3243.100 ;
        RECT 0.000 3241.490 6754.630 3242.820 ;
        RECT 0.000 3240.340 6753.930 3241.490 ;
        RECT 0.000 3238.270 6754.630 3240.340 ;
        RECT 0.000 3237.120 6753.930 3238.270 ;
        RECT 0.000 3235.050 6754.630 3237.120 ;
        RECT 0.000 3233.900 6753.930 3235.050 ;
        RECT 0.000 3232.645 6754.630 3233.900 ;
        RECT 0.000 3230.775 6753.930 3232.645 ;
        RECT 0.000 3229.070 6754.630 3230.775 ;
        RECT 0.000 3227.920 6753.930 3229.070 ;
        RECT 0.000 3223.230 6754.630 3227.920 ;
        RECT 0.000 3221.790 6753.930 3223.230 ;
        RECT 0.000 3219.870 6754.630 3221.790 ;
        RECT 0.000 3218.720 6753.930 3219.870 ;
        RECT 0.000 3210.670 6754.630 3218.720 ;
        RECT 0.000 3209.520 6753.930 3210.670 ;
        RECT 0.000 3139.110 6754.630 3209.520 ;
        RECT 0.700 3137.960 6754.630 3139.110 ;
        RECT 0.000 3129.910 6754.630 3137.960 ;
        RECT 0.700 3128.760 6754.630 3129.910 ;
        RECT 0.000 3126.840 6754.630 3128.760 ;
        RECT 0.700 3125.400 6754.630 3126.840 ;
        RECT 0.000 3120.710 6754.630 3125.400 ;
        RECT 0.700 3119.560 6754.630 3120.710 ;
        RECT 0.000 3117.855 6754.630 3119.560 ;
        RECT 0.700 3115.985 6754.630 3117.855 ;
        RECT 0.000 3114.730 6754.630 3115.985 ;
        RECT 0.700 3113.580 6754.630 3114.730 ;
        RECT 0.000 3111.510 6754.630 3113.580 ;
        RECT 0.700 3110.360 6754.630 3111.510 ;
        RECT 0.000 3108.290 6754.630 3110.360 ;
        RECT 0.700 3107.140 6754.630 3108.290 ;
        RECT 0.000 3105.530 6754.630 3107.140 ;
        RECT 0.700 3104.380 6754.630 3105.530 ;
        RECT 0.000 3093.110 6754.630 3104.380 ;
        RECT 0.700 3091.960 6754.630 3093.110 ;
        RECT 0.000 3089.890 6754.630 3091.960 ;
        RECT 0.700 3088.740 6754.630 3089.890 ;
        RECT 0.000 3086.670 6754.630 3088.740 ;
        RECT 0.700 3085.520 6754.630 3086.670 ;
        RECT 0.000 3083.910 6754.630 3085.520 ;
        RECT 0.700 3082.760 6754.630 3083.910 ;
        RECT 0.000 3075.740 6754.630 3082.760 ;
        RECT 0.000 3074.710 6753.930 3075.740 ;
        RECT 0.700 3074.630 6753.930 3074.710 ;
        RECT 0.700 3073.560 6754.630 3074.630 ;
        RECT 0.000 3071.490 6754.630 3073.560 ;
        RECT 0.700 3070.340 6754.630 3071.490 ;
        RECT 0.000 3068.270 6754.630 3070.340 ;
        RECT 0.700 3067.120 6754.630 3068.270 ;
        RECT 0.000 3065.740 6754.630 3067.120 ;
        RECT 0.000 3065.510 6753.930 3065.740 ;
        RECT 0.700 3064.630 6753.930 3065.510 ;
        RECT 0.700 3064.360 6754.630 3064.630 ;
        RECT 0.000 3058.270 6754.630 3064.360 ;
        RECT 0.000 3057.120 6753.930 3058.270 ;
        RECT 0.000 3055.510 6754.630 3057.120 ;
        RECT 0.000 3054.360 6753.930 3055.510 ;
        RECT 0.000 3052.290 6754.630 3054.360 ;
        RECT 0.000 3051.140 6753.930 3052.290 ;
        RECT 0.000 3049.070 6754.630 3051.140 ;
        RECT 0.000 3047.920 6753.930 3049.070 ;
        RECT 0.000 3039.870 6754.630 3047.920 ;
        RECT 0.000 3038.920 6753.930 3039.870 ;
        RECT 0.700 3038.720 6753.930 3038.920 ;
        RECT 0.700 3037.820 6754.630 3038.720 ;
        RECT 0.000 3037.110 6754.630 3037.820 ;
        RECT 0.000 3035.960 6753.930 3037.110 ;
        RECT 0.000 3033.890 6754.630 3035.960 ;
        RECT 0.000 3032.740 6753.930 3033.890 ;
        RECT 0.000 3030.670 6754.630 3032.740 ;
        RECT 0.000 3029.520 6753.930 3030.670 ;
        RECT 0.000 3028.920 6754.630 3029.520 ;
        RECT 0.700 3027.820 6754.630 3028.920 ;
        RECT 0.000 3018.250 6754.630 3027.820 ;
        RECT 0.000 3017.100 6753.930 3018.250 ;
        RECT 0.000 3015.490 6754.630 3017.100 ;
        RECT 0.000 3014.340 6753.930 3015.490 ;
        RECT 0.000 3012.270 6754.630 3014.340 ;
        RECT 0.000 3011.120 6753.930 3012.270 ;
        RECT 0.000 3009.050 6754.630 3011.120 ;
        RECT 0.000 3007.900 6753.930 3009.050 ;
        RECT 0.000 3006.645 6754.630 3007.900 ;
        RECT 0.000 3004.775 6753.930 3006.645 ;
        RECT 0.000 3003.070 6754.630 3004.775 ;
        RECT 0.000 3001.920 6753.930 3003.070 ;
        RECT 0.000 2997.230 6754.630 3001.920 ;
        RECT 0.000 2995.790 6753.930 2997.230 ;
        RECT 0.000 2993.870 6754.630 2995.790 ;
        RECT 0.000 2992.720 6753.930 2993.870 ;
        RECT 0.000 2984.670 6754.630 2992.720 ;
        RECT 0.000 2983.520 6753.930 2984.670 ;
        RECT 0.000 2923.110 6754.630 2983.520 ;
        RECT 0.700 2921.960 6754.630 2923.110 ;
        RECT 0.000 2913.910 6754.630 2921.960 ;
        RECT 0.700 2912.760 6754.630 2913.910 ;
        RECT 0.000 2910.840 6754.630 2912.760 ;
        RECT 0.700 2909.400 6754.630 2910.840 ;
        RECT 0.000 2904.710 6754.630 2909.400 ;
        RECT 0.700 2903.560 6754.630 2904.710 ;
        RECT 0.000 2901.855 6754.630 2903.560 ;
        RECT 0.700 2899.985 6754.630 2901.855 ;
        RECT 0.000 2898.730 6754.630 2899.985 ;
        RECT 0.700 2897.580 6754.630 2898.730 ;
        RECT 0.000 2895.510 6754.630 2897.580 ;
        RECT 0.700 2894.360 6754.630 2895.510 ;
        RECT 0.000 2892.290 6754.630 2894.360 ;
        RECT 0.700 2891.140 6754.630 2892.290 ;
        RECT 0.000 2889.530 6754.630 2891.140 ;
        RECT 0.700 2888.380 6754.630 2889.530 ;
        RECT 0.000 2877.110 6754.630 2888.380 ;
        RECT 0.700 2875.960 6754.630 2877.110 ;
        RECT 0.000 2873.890 6754.630 2875.960 ;
        RECT 0.700 2872.740 6754.630 2873.890 ;
        RECT 0.000 2870.670 6754.630 2872.740 ;
        RECT 0.700 2869.520 6754.630 2870.670 ;
        RECT 0.000 2867.910 6754.630 2869.520 ;
        RECT 0.700 2866.760 6754.630 2867.910 ;
        RECT 0.000 2858.710 6754.630 2866.760 ;
        RECT 0.700 2857.560 6754.630 2858.710 ;
        RECT 0.000 2855.490 6754.630 2857.560 ;
        RECT 0.700 2854.340 6754.630 2855.490 ;
        RECT 0.000 2852.270 6754.630 2854.340 ;
        RECT 0.700 2851.120 6754.630 2852.270 ;
        RECT 0.000 2850.740 6754.630 2851.120 ;
        RECT 0.000 2849.630 6753.930 2850.740 ;
        RECT 0.000 2849.510 6754.630 2849.630 ;
        RECT 0.700 2848.360 6754.630 2849.510 ;
        RECT 0.000 2840.740 6754.630 2848.360 ;
        RECT 0.000 2839.630 6753.930 2840.740 ;
        RECT 0.000 2833.270 6754.630 2839.630 ;
        RECT 0.000 2832.120 6753.930 2833.270 ;
        RECT 0.000 2830.510 6754.630 2832.120 ;
        RECT 0.000 2829.360 6753.930 2830.510 ;
        RECT 0.000 2827.290 6754.630 2829.360 ;
        RECT 0.000 2826.140 6753.930 2827.290 ;
        RECT 0.000 2824.070 6754.630 2826.140 ;
        RECT 0.000 2823.920 6753.930 2824.070 ;
        RECT 0.700 2822.920 6753.930 2823.920 ;
        RECT 0.700 2822.820 6754.630 2822.920 ;
        RECT 0.000 2814.870 6754.630 2822.820 ;
        RECT 0.000 2813.920 6753.930 2814.870 ;
        RECT 0.700 2813.720 6753.930 2813.920 ;
        RECT 0.700 2812.820 6754.630 2813.720 ;
        RECT 0.000 2812.110 6754.630 2812.820 ;
        RECT 0.000 2810.960 6753.930 2812.110 ;
        RECT 0.000 2808.890 6754.630 2810.960 ;
        RECT 0.000 2807.740 6753.930 2808.890 ;
        RECT 0.000 2805.670 6754.630 2807.740 ;
        RECT 0.000 2804.520 6753.930 2805.670 ;
        RECT 0.000 2793.250 6754.630 2804.520 ;
        RECT 0.000 2792.100 6753.930 2793.250 ;
        RECT 0.000 2790.490 6754.630 2792.100 ;
        RECT 0.000 2789.340 6753.930 2790.490 ;
        RECT 0.000 2787.270 6754.630 2789.340 ;
        RECT 0.000 2786.120 6753.930 2787.270 ;
        RECT 0.000 2784.050 6754.630 2786.120 ;
        RECT 0.000 2782.900 6753.930 2784.050 ;
        RECT 0.000 2781.645 6754.630 2782.900 ;
        RECT 0.000 2779.775 6753.930 2781.645 ;
        RECT 0.000 2778.070 6754.630 2779.775 ;
        RECT 0.000 2776.920 6753.930 2778.070 ;
        RECT 0.000 2772.230 6754.630 2776.920 ;
        RECT 0.000 2770.790 6753.930 2772.230 ;
        RECT 0.000 2768.870 6754.630 2770.790 ;
        RECT 0.000 2767.720 6753.930 2768.870 ;
        RECT 0.000 2759.670 6754.630 2767.720 ;
        RECT 0.000 2758.520 6753.930 2759.670 ;
        RECT 0.000 2707.110 6754.630 2758.520 ;
        RECT 0.700 2705.960 6754.630 2707.110 ;
        RECT 0.000 2697.910 6754.630 2705.960 ;
        RECT 0.700 2696.760 6754.630 2697.910 ;
        RECT 0.000 2694.840 6754.630 2696.760 ;
        RECT 0.700 2693.400 6754.630 2694.840 ;
        RECT 0.000 2688.710 6754.630 2693.400 ;
        RECT 0.700 2687.560 6754.630 2688.710 ;
        RECT 0.000 2685.855 6754.630 2687.560 ;
        RECT 0.700 2683.985 6754.630 2685.855 ;
        RECT 0.000 2682.730 6754.630 2683.985 ;
        RECT 0.700 2681.580 6754.630 2682.730 ;
        RECT 0.000 2679.510 6754.630 2681.580 ;
        RECT 0.700 2678.360 6754.630 2679.510 ;
        RECT 0.000 2676.290 6754.630 2678.360 ;
        RECT 0.700 2675.140 6754.630 2676.290 ;
        RECT 0.000 2673.530 6754.630 2675.140 ;
        RECT 0.700 2672.380 6754.630 2673.530 ;
        RECT 0.000 2661.110 6754.630 2672.380 ;
        RECT 0.700 2659.960 6754.630 2661.110 ;
        RECT 0.000 2657.890 6754.630 2659.960 ;
        RECT 0.700 2656.740 6754.630 2657.890 ;
        RECT 0.000 2654.670 6754.630 2656.740 ;
        RECT 0.700 2653.520 6754.630 2654.670 ;
        RECT 0.000 2651.910 6754.630 2653.520 ;
        RECT 0.700 2650.760 6754.630 2651.910 ;
        RECT 0.000 2642.710 6754.630 2650.760 ;
        RECT 0.700 2641.560 6754.630 2642.710 ;
        RECT 0.000 2639.490 6754.630 2641.560 ;
        RECT 0.700 2638.340 6754.630 2639.490 ;
        RECT 0.000 2636.270 6754.630 2638.340 ;
        RECT 0.700 2635.120 6754.630 2636.270 ;
        RECT 0.000 2633.510 6754.630 2635.120 ;
        RECT 0.700 2632.360 6754.630 2633.510 ;
        RECT 0.000 2625.740 6754.630 2632.360 ;
        RECT 0.000 2624.630 6753.930 2625.740 ;
        RECT 0.000 2615.735 6754.630 2624.630 ;
        RECT 0.000 2614.625 6753.930 2615.735 ;
        RECT 0.000 2608.920 6754.630 2614.625 ;
        RECT 0.700 2607.820 6754.630 2608.920 ;
        RECT 0.000 2607.270 6754.630 2607.820 ;
        RECT 0.000 2606.120 6753.930 2607.270 ;
        RECT 0.000 2604.510 6754.630 2606.120 ;
        RECT 0.000 2603.360 6753.930 2604.510 ;
        RECT 0.000 2601.290 6754.630 2603.360 ;
        RECT 0.000 2600.140 6753.930 2601.290 ;
        RECT 0.000 2598.920 6754.630 2600.140 ;
        RECT 0.700 2598.070 6754.630 2598.920 ;
        RECT 0.700 2597.820 6753.930 2598.070 ;
        RECT 0.000 2596.920 6753.930 2597.820 ;
        RECT 0.000 2588.870 6754.630 2596.920 ;
        RECT 0.000 2587.720 6753.930 2588.870 ;
        RECT 0.000 2586.110 6754.630 2587.720 ;
        RECT 0.000 2584.960 6753.930 2586.110 ;
        RECT 0.000 2582.890 6754.630 2584.960 ;
        RECT 0.000 2581.740 6753.930 2582.890 ;
        RECT 0.000 2579.670 6754.630 2581.740 ;
        RECT 0.000 2578.520 6753.930 2579.670 ;
        RECT 0.000 2567.250 6754.630 2578.520 ;
        RECT 0.000 2566.100 6753.930 2567.250 ;
        RECT 0.000 2564.490 6754.630 2566.100 ;
        RECT 0.000 2563.340 6753.930 2564.490 ;
        RECT 0.000 2561.270 6754.630 2563.340 ;
        RECT 0.000 2560.120 6753.930 2561.270 ;
        RECT 0.000 2558.050 6754.630 2560.120 ;
        RECT 0.000 2556.900 6753.930 2558.050 ;
        RECT 0.000 2555.645 6754.630 2556.900 ;
        RECT 0.000 2553.775 6753.930 2555.645 ;
        RECT 0.000 2552.070 6754.630 2553.775 ;
        RECT 0.000 2550.920 6753.930 2552.070 ;
        RECT 0.000 2546.230 6754.630 2550.920 ;
        RECT 0.000 2544.790 6753.930 2546.230 ;
        RECT 0.000 2542.870 6754.630 2544.790 ;
        RECT 0.000 2541.720 6753.930 2542.870 ;
        RECT 0.000 2533.670 6754.630 2541.720 ;
        RECT 0.000 2532.520 6753.930 2533.670 ;
        RECT 0.000 2491.110 6754.630 2532.520 ;
        RECT 0.700 2489.960 6754.630 2491.110 ;
        RECT 0.000 2481.910 6754.630 2489.960 ;
        RECT 0.700 2480.760 6754.630 2481.910 ;
        RECT 0.000 2478.840 6754.630 2480.760 ;
        RECT 0.700 2477.400 6754.630 2478.840 ;
        RECT 0.000 2472.710 6754.630 2477.400 ;
        RECT 0.700 2471.560 6754.630 2472.710 ;
        RECT 0.000 2469.855 6754.630 2471.560 ;
        RECT 0.700 2467.985 6754.630 2469.855 ;
        RECT 0.000 2466.730 6754.630 2467.985 ;
        RECT 0.700 2465.580 6754.630 2466.730 ;
        RECT 0.000 2463.510 6754.630 2465.580 ;
        RECT 0.700 2462.360 6754.630 2463.510 ;
        RECT 0.000 2460.290 6754.630 2462.360 ;
        RECT 0.700 2459.140 6754.630 2460.290 ;
        RECT 0.000 2457.530 6754.630 2459.140 ;
        RECT 0.700 2456.380 6754.630 2457.530 ;
        RECT 0.000 2445.110 6754.630 2456.380 ;
        RECT 0.700 2443.960 6754.630 2445.110 ;
        RECT 0.000 2441.890 6754.630 2443.960 ;
        RECT 0.700 2440.740 6754.630 2441.890 ;
        RECT 0.000 2438.670 6754.630 2440.740 ;
        RECT 0.700 2437.520 6754.630 2438.670 ;
        RECT 0.000 2435.910 6754.630 2437.520 ;
        RECT 0.700 2434.760 6754.630 2435.910 ;
        RECT 0.000 2426.710 6754.630 2434.760 ;
        RECT 0.700 2425.560 6754.630 2426.710 ;
        RECT 0.000 2423.490 6754.630 2425.560 ;
        RECT 0.700 2422.340 6754.630 2423.490 ;
        RECT 0.000 2420.270 6754.630 2422.340 ;
        RECT 0.700 2419.120 6754.630 2420.270 ;
        RECT 0.000 2417.510 6754.630 2419.120 ;
        RECT 0.700 2416.360 6754.630 2417.510 ;
        RECT 0.000 2393.920 6754.630 2416.360 ;
        RECT 0.700 2392.820 6754.630 2393.920 ;
        RECT 0.000 2383.920 6754.630 2392.820 ;
        RECT 0.700 2383.220 6754.630 2383.920 ;
        RECT 0.700 2382.820 6753.930 2383.220 ;
        RECT 0.000 2358.520 6753.930 2382.820 ;
        RECT 0.000 2333.320 6754.630 2358.520 ;
        RECT 0.000 2308.620 6753.930 2333.320 ;
        RECT 0.000 2279.000 6754.630 2308.620 ;
        RECT 0.700 2254.300 6754.630 2279.000 ;
        RECT 0.000 2229.110 6754.630 2254.300 ;
        RECT 0.700 2204.410 6754.630 2229.110 ;
        RECT 0.000 2163.210 6754.630 2204.410 ;
        RECT 0.000 2138.410 6752.580 2163.210 ;
        RECT 0.000 2137.760 6754.630 2138.410 ;
        RECT 0.000 2113.650 6753.930 2137.760 ;
        RECT 0.000 2112.960 6754.630 2113.650 ;
        RECT 0.000 2088.210 6753.930 2112.960 ;
        RECT 0.000 2068.420 6754.630 2088.210 ;
        RECT 0.700 2043.670 6754.630 2068.420 ;
        RECT 0.000 2042.970 6754.630 2043.670 ;
        RECT 0.700 2018.910 6754.630 2042.970 ;
        RECT 0.000 2018.210 6754.630 2018.910 ;
        RECT 0.700 1993.410 6754.630 2018.210 ;
        RECT 0.000 1942.220 6754.630 1993.410 ;
        RECT 0.000 1917.520 6753.930 1942.220 ;
        RECT 0.000 1892.330 6754.630 1917.520 ;
        RECT 0.000 1867.630 6753.930 1892.330 ;
        RECT 0.000 1853.110 6754.630 1867.630 ;
        RECT 0.700 1851.960 6754.630 1853.110 ;
        RECT 0.000 1843.910 6754.630 1851.960 ;
        RECT 0.700 1842.760 6754.630 1843.910 ;
        RECT 0.000 1840.840 6754.630 1842.760 ;
        RECT 0.700 1839.400 6754.630 1840.840 ;
        RECT 0.000 1834.710 6754.630 1839.400 ;
        RECT 0.700 1833.560 6754.630 1834.710 ;
        RECT 0.000 1831.855 6754.630 1833.560 ;
        RECT 0.700 1829.985 6754.630 1831.855 ;
        RECT 0.000 1828.730 6754.630 1829.985 ;
        RECT 0.700 1827.580 6754.630 1828.730 ;
        RECT 0.000 1825.510 6754.630 1827.580 ;
        RECT 0.700 1824.360 6754.630 1825.510 ;
        RECT 0.000 1822.290 6754.630 1824.360 ;
        RECT 0.700 1821.140 6754.630 1822.290 ;
        RECT 0.000 1819.530 6754.630 1821.140 ;
        RECT 0.700 1818.380 6754.630 1819.530 ;
        RECT 0.000 1807.110 6754.630 1818.380 ;
        RECT 0.700 1805.960 6754.630 1807.110 ;
        RECT 0.000 1803.890 6754.630 1805.960 ;
        RECT 0.700 1802.740 6754.630 1803.890 ;
        RECT 0.000 1800.670 6754.630 1802.740 ;
        RECT 0.700 1799.520 6754.630 1800.670 ;
        RECT 0.000 1797.910 6754.630 1799.520 ;
        RECT 0.700 1796.760 6754.630 1797.910 ;
        RECT 0.000 1788.710 6754.630 1796.760 ;
        RECT 0.700 1787.560 6754.630 1788.710 ;
        RECT 0.000 1785.490 6754.630 1787.560 ;
        RECT 0.700 1784.340 6754.630 1785.490 ;
        RECT 0.000 1782.270 6754.630 1784.340 ;
        RECT 0.700 1781.120 6754.630 1782.270 ;
        RECT 0.000 1779.510 6754.630 1781.120 ;
        RECT 0.700 1778.360 6754.630 1779.510 ;
        RECT 0.000 1748.920 6754.630 1778.360 ;
        RECT 0.700 1747.820 6754.630 1748.920 ;
        RECT 0.000 1740.740 6754.630 1747.820 ;
        RECT 0.000 1739.630 6753.930 1740.740 ;
        RECT 0.000 1738.920 6754.630 1739.630 ;
        RECT 0.700 1737.820 6754.630 1738.920 ;
        RECT 0.000 1730.735 6754.630 1737.820 ;
        RECT 0.000 1729.625 6753.930 1730.735 ;
        RECT 0.000 1721.270 6754.630 1729.625 ;
        RECT 0.000 1720.120 6753.930 1721.270 ;
        RECT 0.000 1718.510 6754.630 1720.120 ;
        RECT 0.000 1717.360 6753.930 1718.510 ;
        RECT 0.000 1715.290 6754.630 1717.360 ;
        RECT 0.000 1714.140 6753.930 1715.290 ;
        RECT 0.000 1712.070 6754.630 1714.140 ;
        RECT 0.000 1710.920 6753.930 1712.070 ;
        RECT 0.000 1702.870 6754.630 1710.920 ;
        RECT 0.000 1701.720 6753.930 1702.870 ;
        RECT 0.000 1700.110 6754.630 1701.720 ;
        RECT 0.000 1698.960 6753.930 1700.110 ;
        RECT 0.000 1696.890 6754.630 1698.960 ;
        RECT 0.000 1695.740 6753.930 1696.890 ;
        RECT 0.000 1693.670 6754.630 1695.740 ;
        RECT 0.000 1692.520 6753.930 1693.670 ;
        RECT 0.000 1681.250 6754.630 1692.520 ;
        RECT 0.000 1680.100 6753.930 1681.250 ;
        RECT 0.000 1678.490 6754.630 1680.100 ;
        RECT 0.000 1677.340 6753.930 1678.490 ;
        RECT 0.000 1675.270 6754.630 1677.340 ;
        RECT 0.000 1674.120 6753.930 1675.270 ;
        RECT 0.000 1672.050 6754.630 1674.120 ;
        RECT 0.000 1670.900 6753.930 1672.050 ;
        RECT 0.000 1669.645 6754.630 1670.900 ;
        RECT 0.000 1667.775 6753.930 1669.645 ;
        RECT 0.000 1666.070 6754.630 1667.775 ;
        RECT 0.000 1664.920 6753.930 1666.070 ;
        RECT 0.000 1660.230 6754.630 1664.920 ;
        RECT 0.000 1658.790 6753.930 1660.230 ;
        RECT 0.000 1656.870 6754.630 1658.790 ;
        RECT 0.000 1655.720 6753.930 1656.870 ;
        RECT 0.000 1647.670 6754.630 1655.720 ;
        RECT 0.000 1646.520 6753.930 1647.670 ;
        RECT 0.000 1637.110 6754.630 1646.520 ;
        RECT 0.700 1635.960 6754.630 1637.110 ;
        RECT 0.000 1627.910 6754.630 1635.960 ;
        RECT 0.700 1626.760 6754.630 1627.910 ;
        RECT 0.000 1624.840 6754.630 1626.760 ;
        RECT 0.700 1623.400 6754.630 1624.840 ;
        RECT 0.000 1618.710 6754.630 1623.400 ;
        RECT 0.700 1617.560 6754.630 1618.710 ;
        RECT 0.000 1615.855 6754.630 1617.560 ;
        RECT 0.700 1613.985 6754.630 1615.855 ;
        RECT 0.000 1612.730 6754.630 1613.985 ;
        RECT 0.700 1611.580 6754.630 1612.730 ;
        RECT 0.000 1609.510 6754.630 1611.580 ;
        RECT 0.700 1608.360 6754.630 1609.510 ;
        RECT 0.000 1606.290 6754.630 1608.360 ;
        RECT 0.700 1605.140 6754.630 1606.290 ;
        RECT 0.000 1603.530 6754.630 1605.140 ;
        RECT 0.700 1602.380 6754.630 1603.530 ;
        RECT 0.000 1591.110 6754.630 1602.380 ;
        RECT 0.700 1589.960 6754.630 1591.110 ;
        RECT 0.000 1587.890 6754.630 1589.960 ;
        RECT 0.700 1586.740 6754.630 1587.890 ;
        RECT 0.000 1584.670 6754.630 1586.740 ;
        RECT 0.700 1583.520 6754.630 1584.670 ;
        RECT 0.000 1581.910 6754.630 1583.520 ;
        RECT 0.700 1580.760 6754.630 1581.910 ;
        RECT 0.000 1572.710 6754.630 1580.760 ;
        RECT 0.700 1571.560 6754.630 1572.710 ;
        RECT 0.000 1569.490 6754.630 1571.560 ;
        RECT 0.700 1568.340 6754.630 1569.490 ;
        RECT 0.000 1566.270 6754.630 1568.340 ;
        RECT 0.700 1565.120 6754.630 1566.270 ;
        RECT 0.000 1563.510 6754.630 1565.120 ;
        RECT 0.700 1562.360 6754.630 1563.510 ;
        RECT 0.000 1533.920 6754.630 1562.360 ;
        RECT 0.700 1532.820 6754.630 1533.920 ;
        RECT 0.000 1523.920 6754.630 1532.820 ;
        RECT 0.700 1522.820 6754.630 1523.920 ;
        RECT 0.000 1515.740 6754.630 1522.820 ;
        RECT 0.000 1514.630 6753.930 1515.740 ;
        RECT 0.000 1505.735 6754.630 1514.630 ;
        RECT 0.000 1504.625 6753.930 1505.735 ;
        RECT 0.000 1495.270 6754.630 1504.625 ;
        RECT 0.000 1494.120 6753.930 1495.270 ;
        RECT 0.000 1492.510 6754.630 1494.120 ;
        RECT 0.000 1491.360 6753.930 1492.510 ;
        RECT 0.000 1489.290 6754.630 1491.360 ;
        RECT 0.000 1488.140 6753.930 1489.290 ;
        RECT 0.000 1486.070 6754.630 1488.140 ;
        RECT 0.000 1484.920 6753.930 1486.070 ;
        RECT 0.000 1476.870 6754.630 1484.920 ;
        RECT 0.000 1475.720 6753.930 1476.870 ;
        RECT 0.000 1474.110 6754.630 1475.720 ;
        RECT 0.000 1472.960 6753.930 1474.110 ;
        RECT 0.000 1470.890 6754.630 1472.960 ;
        RECT 0.000 1469.740 6753.930 1470.890 ;
        RECT 0.000 1467.670 6754.630 1469.740 ;
        RECT 0.000 1466.520 6753.930 1467.670 ;
        RECT 0.000 1455.250 6754.630 1466.520 ;
        RECT 0.000 1454.100 6753.930 1455.250 ;
        RECT 0.000 1452.490 6754.630 1454.100 ;
        RECT 0.000 1451.340 6753.930 1452.490 ;
        RECT 0.000 1449.270 6754.630 1451.340 ;
        RECT 0.000 1448.120 6753.930 1449.270 ;
        RECT 0.000 1446.050 6754.630 1448.120 ;
        RECT 0.000 1444.900 6753.930 1446.050 ;
        RECT 0.000 1443.645 6754.630 1444.900 ;
        RECT 0.000 1441.775 6753.930 1443.645 ;
        RECT 0.000 1440.070 6754.630 1441.775 ;
        RECT 0.000 1438.920 6753.930 1440.070 ;
        RECT 0.000 1434.230 6754.630 1438.920 ;
        RECT 0.000 1432.790 6753.930 1434.230 ;
        RECT 0.000 1430.870 6754.630 1432.790 ;
        RECT 0.000 1429.720 6753.930 1430.870 ;
        RECT 0.000 1421.670 6754.630 1429.720 ;
        RECT 0.000 1421.110 6753.930 1421.670 ;
        RECT 0.700 1420.520 6753.930 1421.110 ;
        RECT 0.700 1419.960 6754.630 1420.520 ;
        RECT 0.000 1411.910 6754.630 1419.960 ;
        RECT 0.700 1410.760 6754.630 1411.910 ;
        RECT 0.000 1408.840 6754.630 1410.760 ;
        RECT 0.700 1407.400 6754.630 1408.840 ;
        RECT 0.000 1402.710 6754.630 1407.400 ;
        RECT 0.700 1401.560 6754.630 1402.710 ;
        RECT 0.000 1399.855 6754.630 1401.560 ;
        RECT 0.700 1397.985 6754.630 1399.855 ;
        RECT 0.000 1396.730 6754.630 1397.985 ;
        RECT 0.700 1395.580 6754.630 1396.730 ;
        RECT 0.000 1393.510 6754.630 1395.580 ;
        RECT 0.700 1392.360 6754.630 1393.510 ;
        RECT 0.000 1390.290 6754.630 1392.360 ;
        RECT 0.700 1389.140 6754.630 1390.290 ;
        RECT 0.000 1387.530 6754.630 1389.140 ;
        RECT 0.700 1386.380 6754.630 1387.530 ;
        RECT 0.000 1375.110 6754.630 1386.380 ;
        RECT 0.700 1373.960 6754.630 1375.110 ;
        RECT 0.000 1371.890 6754.630 1373.960 ;
        RECT 0.700 1370.740 6754.630 1371.890 ;
        RECT 0.000 1368.670 6754.630 1370.740 ;
        RECT 0.700 1367.520 6754.630 1368.670 ;
        RECT 0.000 1365.910 6754.630 1367.520 ;
        RECT 0.700 1364.760 6754.630 1365.910 ;
        RECT 0.000 1356.710 6754.630 1364.760 ;
        RECT 0.700 1355.560 6754.630 1356.710 ;
        RECT 0.000 1353.490 6754.630 1355.560 ;
        RECT 0.700 1352.340 6754.630 1353.490 ;
        RECT 0.000 1350.270 6754.630 1352.340 ;
        RECT 0.700 1349.120 6754.630 1350.270 ;
        RECT 0.000 1347.510 6754.630 1349.120 ;
        RECT 0.700 1346.360 6754.630 1347.510 ;
        RECT 0.000 1318.920 6754.630 1346.360 ;
        RECT 0.700 1317.820 6754.630 1318.920 ;
        RECT 0.000 1308.920 6754.630 1317.820 ;
        RECT 0.700 1307.820 6754.630 1308.920 ;
        RECT 0.000 1290.740 6754.630 1307.820 ;
        RECT 0.000 1289.630 6753.930 1290.740 ;
        RECT 0.000 1280.735 6754.630 1289.630 ;
        RECT 0.000 1279.625 6753.930 1280.735 ;
        RECT 0.000 1270.270 6754.630 1279.625 ;
        RECT 0.000 1269.120 6753.930 1270.270 ;
        RECT 0.000 1267.510 6754.630 1269.120 ;
        RECT 0.000 1266.360 6753.930 1267.510 ;
        RECT 0.000 1264.290 6754.630 1266.360 ;
        RECT 0.000 1263.140 6753.930 1264.290 ;
        RECT 0.000 1261.070 6754.630 1263.140 ;
        RECT 0.000 1259.920 6753.930 1261.070 ;
        RECT 0.000 1251.870 6754.630 1259.920 ;
        RECT 0.000 1250.720 6753.930 1251.870 ;
        RECT 0.000 1249.110 6754.630 1250.720 ;
        RECT 0.000 1247.960 6753.930 1249.110 ;
        RECT 0.000 1245.890 6754.630 1247.960 ;
        RECT 0.000 1244.740 6753.930 1245.890 ;
        RECT 0.000 1242.670 6754.630 1244.740 ;
        RECT 0.000 1241.520 6753.930 1242.670 ;
        RECT 0.000 1230.250 6754.630 1241.520 ;
        RECT 0.000 1229.100 6753.930 1230.250 ;
        RECT 0.000 1227.490 6754.630 1229.100 ;
        RECT 0.000 1226.340 6753.930 1227.490 ;
        RECT 0.000 1224.270 6754.630 1226.340 ;
        RECT 0.000 1223.120 6753.930 1224.270 ;
        RECT 0.000 1221.050 6754.630 1223.120 ;
        RECT 0.000 1219.900 6753.930 1221.050 ;
        RECT 0.000 1218.645 6754.630 1219.900 ;
        RECT 0.000 1216.775 6753.930 1218.645 ;
        RECT 0.000 1215.070 6754.630 1216.775 ;
        RECT 0.000 1213.920 6753.930 1215.070 ;
        RECT 0.000 1209.230 6754.630 1213.920 ;
        RECT 0.000 1207.790 6753.930 1209.230 ;
        RECT 0.000 1205.870 6754.630 1207.790 ;
        RECT 0.000 1205.110 6753.930 1205.870 ;
        RECT 0.700 1204.720 6753.930 1205.110 ;
        RECT 0.700 1203.960 6754.630 1204.720 ;
        RECT 0.000 1196.670 6754.630 1203.960 ;
        RECT 0.000 1195.910 6753.930 1196.670 ;
        RECT 0.700 1195.520 6753.930 1195.910 ;
        RECT 0.700 1194.760 6754.630 1195.520 ;
        RECT 0.000 1192.840 6754.630 1194.760 ;
        RECT 0.700 1191.400 6754.630 1192.840 ;
        RECT 0.000 1186.710 6754.630 1191.400 ;
        RECT 0.700 1185.560 6754.630 1186.710 ;
        RECT 0.000 1183.855 6754.630 1185.560 ;
        RECT 0.700 1181.985 6754.630 1183.855 ;
        RECT 0.000 1180.730 6754.630 1181.985 ;
        RECT 0.700 1179.580 6754.630 1180.730 ;
        RECT 0.000 1177.510 6754.630 1179.580 ;
        RECT 0.700 1176.360 6754.630 1177.510 ;
        RECT 0.000 1174.290 6754.630 1176.360 ;
        RECT 0.700 1173.140 6754.630 1174.290 ;
        RECT 0.000 1171.530 6754.630 1173.140 ;
        RECT 0.700 1170.380 6754.630 1171.530 ;
        RECT 0.000 1159.110 6754.630 1170.380 ;
        RECT 0.700 1157.960 6754.630 1159.110 ;
        RECT 0.000 1155.890 6754.630 1157.960 ;
        RECT 0.700 1154.740 6754.630 1155.890 ;
        RECT 0.000 1152.670 6754.630 1154.740 ;
        RECT 0.700 1151.520 6754.630 1152.670 ;
        RECT 0.000 1149.910 6754.630 1151.520 ;
        RECT 0.700 1148.760 6754.630 1149.910 ;
        RECT 0.000 1140.710 6754.630 1148.760 ;
        RECT 0.700 1139.560 6754.630 1140.710 ;
        RECT 0.000 1137.490 6754.630 1139.560 ;
        RECT 0.700 1136.340 6754.630 1137.490 ;
        RECT 0.000 1134.270 6754.630 1136.340 ;
        RECT 0.700 1133.120 6754.630 1134.270 ;
        RECT 0.000 1131.510 6754.630 1133.120 ;
        RECT 0.700 1130.360 6754.630 1131.510 ;
        RECT 0.000 1103.920 6754.630 1130.360 ;
        RECT 0.700 1102.820 6754.630 1103.920 ;
        RECT 0.000 1093.920 6754.630 1102.820 ;
        RECT 0.700 1092.820 6754.630 1093.920 ;
        RECT 0.000 1065.740 6754.630 1092.820 ;
        RECT 0.000 1064.630 6753.930 1065.740 ;
        RECT 0.000 1055.735 6754.630 1064.630 ;
        RECT 0.000 1054.625 6753.930 1055.735 ;
        RECT 0.000 1045.270 6754.630 1054.625 ;
        RECT 0.000 1044.120 6753.930 1045.270 ;
        RECT 0.000 1042.510 6754.630 1044.120 ;
        RECT 0.000 1041.360 6753.930 1042.510 ;
        RECT 0.000 1039.290 6754.630 1041.360 ;
        RECT 0.000 1038.140 6753.930 1039.290 ;
        RECT 0.000 1036.070 6754.630 1038.140 ;
        RECT 0.000 1034.920 6753.930 1036.070 ;
        RECT 0.000 1026.870 6754.630 1034.920 ;
        RECT 0.000 1025.720 6753.930 1026.870 ;
        RECT 0.000 1024.110 6754.630 1025.720 ;
        RECT 0.000 1022.960 6753.930 1024.110 ;
        RECT 0.000 1020.890 6754.630 1022.960 ;
        RECT 0.000 1019.740 6753.930 1020.890 ;
        RECT 0.000 1017.670 6754.630 1019.740 ;
        RECT 0.000 1016.520 6753.930 1017.670 ;
        RECT 0.000 1005.250 6754.630 1016.520 ;
        RECT 0.000 1004.100 6753.930 1005.250 ;
        RECT 0.000 1002.490 6754.630 1004.100 ;
        RECT 0.000 1001.340 6753.930 1002.490 ;
        RECT 0.000 999.270 6754.630 1001.340 ;
        RECT 0.000 998.120 6753.930 999.270 ;
        RECT 0.000 996.050 6754.630 998.120 ;
        RECT 0.000 994.900 6753.930 996.050 ;
        RECT 0.000 993.645 6754.630 994.900 ;
        RECT 0.000 991.775 6753.930 993.645 ;
        RECT 0.000 990.070 6754.630 991.775 ;
        RECT 0.000 989.110 6753.930 990.070 ;
        RECT 0.700 988.920 6753.930 989.110 ;
        RECT 0.700 987.960 6754.630 988.920 ;
        RECT 0.000 984.230 6754.630 987.960 ;
        RECT 0.000 982.790 6753.930 984.230 ;
        RECT 0.000 980.870 6754.630 982.790 ;
        RECT 0.000 979.910 6753.930 980.870 ;
        RECT 0.700 979.720 6753.930 979.910 ;
        RECT 0.700 978.760 6754.630 979.720 ;
        RECT 0.000 976.840 6754.630 978.760 ;
        RECT 0.700 975.400 6754.630 976.840 ;
        RECT 0.000 971.670 6754.630 975.400 ;
        RECT 0.000 970.710 6753.930 971.670 ;
        RECT 0.700 970.520 6753.930 970.710 ;
        RECT 0.700 969.560 6754.630 970.520 ;
        RECT 0.000 967.855 6754.630 969.560 ;
        RECT 0.700 965.985 6754.630 967.855 ;
        RECT 0.000 964.730 6754.630 965.985 ;
        RECT 0.700 963.580 6754.630 964.730 ;
        RECT 0.000 961.510 6754.630 963.580 ;
        RECT 0.700 960.360 6754.630 961.510 ;
        RECT 0.000 958.290 6754.630 960.360 ;
        RECT 0.700 957.140 6754.630 958.290 ;
        RECT 0.000 955.530 6754.630 957.140 ;
        RECT 0.700 954.380 6754.630 955.530 ;
        RECT 0.000 943.110 6754.630 954.380 ;
        RECT 0.700 941.960 6754.630 943.110 ;
        RECT 0.000 939.890 6754.630 941.960 ;
        RECT 0.700 938.740 6754.630 939.890 ;
        RECT 0.000 936.670 6754.630 938.740 ;
        RECT 0.700 935.520 6754.630 936.670 ;
        RECT 0.000 933.910 6754.630 935.520 ;
        RECT 0.700 932.760 6754.630 933.910 ;
        RECT 0.000 924.710 6754.630 932.760 ;
        RECT 0.700 923.560 6754.630 924.710 ;
        RECT 0.000 921.490 6754.630 923.560 ;
        RECT 0.700 920.340 6754.630 921.490 ;
        RECT 0.000 918.270 6754.630 920.340 ;
        RECT 0.700 917.120 6754.630 918.270 ;
        RECT 0.000 915.510 6754.630 917.120 ;
        RECT 0.700 914.360 6754.630 915.510 ;
        RECT 0.000 888.920 6754.630 914.360 ;
        RECT 0.700 887.820 6754.630 888.920 ;
        RECT 0.000 878.920 6754.630 887.820 ;
        RECT 0.700 877.820 6754.630 878.920 ;
        RECT 0.000 840.740 6754.630 877.820 ;
        RECT 0.000 839.630 6753.930 840.740 ;
        RECT 0.000 830.735 6754.630 839.630 ;
        RECT 0.000 829.625 6753.930 830.735 ;
        RECT 0.000 819.270 6754.630 829.625 ;
        RECT 0.000 818.120 6753.930 819.270 ;
        RECT 0.000 816.510 6754.630 818.120 ;
        RECT 0.000 815.360 6753.930 816.510 ;
        RECT 0.000 813.290 6754.630 815.360 ;
        RECT 0.000 812.140 6753.930 813.290 ;
        RECT 0.000 810.070 6754.630 812.140 ;
        RECT 0.000 808.920 6753.930 810.070 ;
        RECT 0.000 800.870 6754.630 808.920 ;
        RECT 0.000 799.720 6753.930 800.870 ;
        RECT 0.000 798.110 6754.630 799.720 ;
        RECT 0.000 796.960 6753.930 798.110 ;
        RECT 0.000 794.890 6754.630 796.960 ;
        RECT 0.000 793.740 6753.930 794.890 ;
        RECT 0.000 791.670 6754.630 793.740 ;
        RECT 0.000 790.520 6753.930 791.670 ;
        RECT 0.000 779.250 6754.630 790.520 ;
        RECT 0.000 778.100 6753.930 779.250 ;
        RECT 0.000 776.490 6754.630 778.100 ;
        RECT 0.000 775.340 6753.930 776.490 ;
        RECT 0.000 773.270 6754.630 775.340 ;
        RECT 0.000 773.110 6753.930 773.270 ;
        RECT 0.700 772.120 6753.930 773.110 ;
        RECT 0.700 771.960 6754.630 772.120 ;
        RECT 0.000 770.050 6754.630 771.960 ;
        RECT 0.000 768.900 6753.930 770.050 ;
        RECT 0.000 767.645 6754.630 768.900 ;
        RECT 0.000 765.775 6753.930 767.645 ;
        RECT 0.000 764.070 6754.630 765.775 ;
        RECT 0.000 763.910 6753.930 764.070 ;
        RECT 0.700 762.920 6753.930 763.910 ;
        RECT 0.700 762.760 6754.630 762.920 ;
        RECT 0.000 760.840 6754.630 762.760 ;
        RECT 0.700 759.400 6754.630 760.840 ;
        RECT 0.000 758.230 6754.630 759.400 ;
        RECT 0.000 756.790 6753.930 758.230 ;
        RECT 0.000 754.870 6754.630 756.790 ;
        RECT 0.000 754.710 6753.930 754.870 ;
        RECT 0.700 753.720 6753.930 754.710 ;
        RECT 0.700 753.560 6754.630 753.720 ;
        RECT 0.000 751.855 6754.630 753.560 ;
        RECT 0.700 749.985 6754.630 751.855 ;
        RECT 0.000 748.730 6754.630 749.985 ;
        RECT 0.700 747.580 6754.630 748.730 ;
        RECT 0.000 745.670 6754.630 747.580 ;
        RECT 0.000 745.510 6753.930 745.670 ;
        RECT 0.700 744.520 6753.930 745.510 ;
        RECT 0.700 744.360 6754.630 744.520 ;
        RECT 0.000 742.290 6754.630 744.360 ;
        RECT 0.700 741.140 6754.630 742.290 ;
        RECT 0.000 739.530 6754.630 741.140 ;
        RECT 0.700 738.380 6754.630 739.530 ;
        RECT 0.000 727.110 6754.630 738.380 ;
        RECT 0.700 725.960 6754.630 727.110 ;
        RECT 0.000 723.890 6754.630 725.960 ;
        RECT 0.700 722.740 6754.630 723.890 ;
        RECT 0.000 720.670 6754.630 722.740 ;
        RECT 0.700 719.520 6754.630 720.670 ;
        RECT 0.000 717.910 6754.630 719.520 ;
        RECT 0.700 716.760 6754.630 717.910 ;
        RECT 0.000 708.710 6754.630 716.760 ;
        RECT 0.700 707.560 6754.630 708.710 ;
        RECT 0.000 705.490 6754.630 707.560 ;
        RECT 0.700 704.340 6754.630 705.490 ;
        RECT 0.000 702.270 6754.630 704.340 ;
        RECT 0.700 701.120 6754.630 702.270 ;
        RECT 0.000 699.510 6754.630 701.120 ;
        RECT 0.700 698.360 6754.630 699.510 ;
        RECT 0.000 673.920 6754.630 698.360 ;
        RECT 0.950 672.820 6754.630 673.920 ;
        RECT 0.000 663.920 6754.630 672.820 ;
        RECT 0.700 662.820 6754.630 663.920 ;
        RECT 0.000 615.740 6754.630 662.820 ;
        RECT 0.000 614.630 6753.930 615.740 ;
        RECT 0.000 605.735 6754.630 614.630 ;
        RECT 0.000 604.625 6753.930 605.735 ;
        RECT 0.000 594.270 6754.630 604.625 ;
        RECT 0.000 593.120 6753.930 594.270 ;
        RECT 0.000 591.510 6754.630 593.120 ;
        RECT 0.000 590.360 6753.930 591.510 ;
        RECT 0.000 588.290 6754.630 590.360 ;
        RECT 0.000 587.140 6753.930 588.290 ;
        RECT 0.000 585.070 6754.630 587.140 ;
        RECT 0.000 583.920 6753.930 585.070 ;
        RECT 0.000 575.870 6754.630 583.920 ;
        RECT 0.000 574.720 6753.930 575.870 ;
        RECT 0.000 573.110 6754.630 574.720 ;
        RECT 0.000 571.960 6753.930 573.110 ;
        RECT 0.000 569.890 6754.630 571.960 ;
        RECT 0.000 568.740 6753.930 569.890 ;
        RECT 0.000 566.670 6754.630 568.740 ;
        RECT 0.000 565.520 6753.930 566.670 ;
        RECT 0.000 554.250 6754.630 565.520 ;
        RECT 0.000 553.100 6753.930 554.250 ;
        RECT 0.000 551.490 6754.630 553.100 ;
        RECT 0.000 550.340 6753.930 551.490 ;
        RECT 0.000 548.270 6754.630 550.340 ;
        RECT 0.000 547.120 6753.930 548.270 ;
        RECT 0.000 545.050 6754.630 547.120 ;
        RECT 0.000 543.900 6753.930 545.050 ;
        RECT 0.000 542.645 6754.630 543.900 ;
        RECT 0.000 540.775 6753.930 542.645 ;
        RECT 0.000 539.070 6754.630 540.775 ;
        RECT 0.000 537.920 6753.930 539.070 ;
        RECT 0.000 533.230 6754.630 537.920 ;
        RECT 0.000 531.790 6753.930 533.230 ;
        RECT 0.000 530.045 6754.630 531.790 ;
        RECT 0.700 529.870 6754.630 530.045 ;
        RECT 0.700 528.720 6753.930 529.870 ;
        RECT 0.700 526.655 6754.630 528.720 ;
        RECT 0.000 520.670 6754.630 526.655 ;
        RECT 0.000 519.520 6753.930 520.670 ;
        RECT 0.000 415.000 6754.630 519.520 ;
        RECT 0.700 390.740 6754.630 415.000 ;
        RECT 0.700 390.300 6753.930 390.740 ;
        RECT 0.000 389.630 6753.930 390.300 ;
        RECT 0.000 380.735 6754.630 389.630 ;
        RECT 0.000 379.625 6753.930 380.735 ;
        RECT 0.000 368.270 6754.630 379.625 ;
        RECT 0.000 367.120 6753.930 368.270 ;
        RECT 0.000 365.510 6754.630 367.120 ;
        RECT 0.000 365.110 6753.930 365.510 ;
        RECT 0.700 364.360 6753.930 365.110 ;
        RECT 0.700 362.290 6754.630 364.360 ;
        RECT 0.700 361.140 6753.930 362.290 ;
        RECT 0.700 359.070 6754.630 361.140 ;
        RECT 0.700 357.920 6753.930 359.070 ;
        RECT 0.700 349.870 6754.630 357.920 ;
        RECT 0.700 348.720 6753.930 349.870 ;
        RECT 0.700 347.110 6754.630 348.720 ;
        RECT 0.700 345.960 6753.930 347.110 ;
        RECT 0.700 343.890 6754.630 345.960 ;
        RECT 0.700 342.740 6753.930 343.890 ;
        RECT 0.700 340.670 6754.630 342.740 ;
        RECT 0.700 340.410 6753.930 340.670 ;
        RECT 0.000 339.520 6753.930 340.410 ;
        RECT 0.000 328.250 6754.630 339.520 ;
        RECT 0.000 327.100 6753.930 328.250 ;
        RECT 0.000 325.490 6754.630 327.100 ;
        RECT 0.000 324.340 6753.930 325.490 ;
        RECT 0.000 322.270 6754.630 324.340 ;
        RECT 0.000 321.120 6753.930 322.270 ;
        RECT 0.000 319.050 6754.630 321.120 ;
        RECT 0.000 317.900 6753.930 319.050 ;
        RECT 0.000 316.645 6754.630 317.900 ;
        RECT 0.000 314.775 6753.930 316.645 ;
        RECT 0.000 313.070 6754.630 314.775 ;
        RECT 0.000 311.920 6753.930 313.070 ;
        RECT 0.000 307.230 6754.630 311.920 ;
        RECT 0.000 305.790 6753.930 307.230 ;
        RECT 0.000 303.870 6754.630 305.790 ;
        RECT 0.000 302.720 6753.930 303.870 ;
        RECT 0.000 294.670 6754.630 302.720 ;
        RECT 0.000 293.520 6753.930 294.670 ;
        RECT 0.000 204.420 6754.630 293.520 ;
        RECT 0.700 179.670 6754.630 204.420 ;
        RECT 0.000 154.210 6754.630 179.670 ;
        RECT 0.700 129.410 6754.630 154.210 ;
        RECT 0.000 0.700 6754.630 129.410 ;
        RECT 0.000 0.175 183.630 0.700 ;
        RECT 208.330 0.175 233.520 0.700 ;
        RECT 258.220 0.175 996.020 0.700 ;
        RECT 1019.970 0.175 1045.420 0.700 ;
        RECT 1070.220 0.175 2634.630 0.700 ;
        RECT 2659.330 0.175 2684.520 0.700 ;
        RECT 2709.220 0.175 2903.630 0.700 ;
        RECT 2928.330 0.175 2953.520 0.700 ;
        RECT 2978.220 0.175 3771.630 0.700 ;
        RECT 3796.330 0.175 3821.520 0.700 ;
        RECT 3846.220 0.175 4584.020 0.700 ;
        RECT 4607.970 0.175 4633.420 0.700 ;
        RECT 4658.220 0.175 6222.630 0.700 ;
        RECT 6247.330 0.175 6272.520 0.700 ;
        RECT 6297.220 0.175 6491.630 0.700 ;
        RECT 6516.330 0.175 6541.520 0.700 ;
        RECT 6566.220 0.175 6754.630 0.700 ;
      LAYER met4 ;
        RECT 0.295 2.400 6754.345 4763.040 ;
      LAYER met5 ;
        RECT 1.620 2.400 6753.020 4763.040 ;
  END
END double_wide_openframe_project_wrapper
END LIBRARY

